VERSION 5.8 ;
BUSBITCHARS "[]" ;
DIVIDERCHAR "/" ;
UNITS
    DATABASE MICRONS 1000 ;
END UNITS

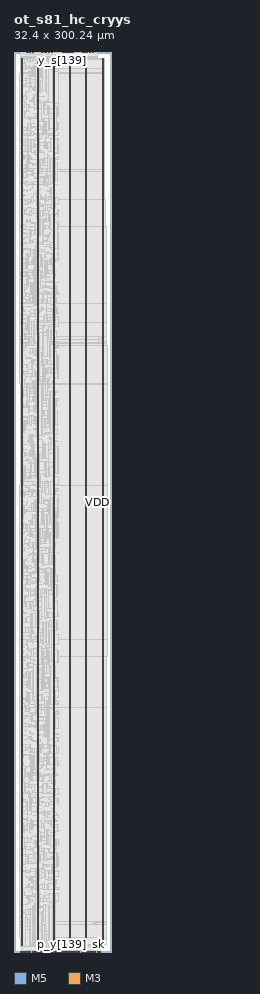
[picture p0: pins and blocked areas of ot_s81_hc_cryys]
MACRO ot_s81_hc_cryys
  FOREIGN ot_s81_hc_cryys 0 0 ;
  CLASS BLOCK ;
  SIZE 32.4 BY 300.24 ;
  PIN p_flt
    DIRECTION OUTPUT ;
    USE SIGNAL ;
    PORT
      LAYER M5 ;
        RECT  28.992 0 29.016 0.192 ;
    END
  END p_flt
  PIN p_req
    DIRECTION INPUT ;
    USE SIGNAL ;
    PORT
      LAYER M5 ;
        RECT  28.8 0 28.824 0.192 ;
    END
  END p_req
  PIN p_y[0]
    DIRECTION OUTPUT ;
    USE SIGNAL ;
    PORT
      LAYER M5 ;
        RECT  2.208 0 2.232 0.192 ;
    END
  END p_y[0]
  PIN p_y[100]
    DIRECTION OUTPUT ;
    USE SIGNAL ;
    PORT
      LAYER M5 ;
        RECT  12.24 0 12.264 0.192 ;
    END
  END p_y[100]
  PIN p_y[101]
    DIRECTION OUTPUT ;
    USE SIGNAL ;
    PORT
      LAYER M3 ;
        RECT  12.348 0 12.366 0.038 ;
    END
  END p_y[101]
  PIN p_y[102]
    DIRECTION OUTPUT ;
    USE SIGNAL ;
    PORT
      LAYER M5 ;
        RECT  12.432 0 12.456 0.192 ;
    END
  END p_y[102]
  PIN p_y[103]
    DIRECTION OUTPUT ;
    USE SIGNAL ;
    PORT
      LAYER M3 ;
        RECT  12.564 0 12.582 0.038 ;
    END
  END p_y[103]
  PIN p_y[104]
    DIRECTION OUTPUT ;
    USE SIGNAL ;
    PORT
      LAYER M5 ;
        RECT  12.672 0 12.696 0.192 ;
    END
  END p_y[104]
  PIN p_y[105]
    DIRECTION OUTPUT ;
    USE SIGNAL ;
    PORT
      LAYER M3 ;
        RECT  12.744 0 12.762 0.038 ;
    END
  END p_y[105]
  PIN p_y[106]
    DIRECTION OUTPUT ;
    USE SIGNAL ;
    PORT
      LAYER M5 ;
        RECT  12.864 0 12.888 0.192 ;
    END
  END p_y[106]
  PIN p_y[107]
    DIRECTION OUTPUT ;
    USE SIGNAL ;
    PORT
      LAYER M3 ;
        RECT  12.96 0 12.978 0.038 ;
    END
  END p_y[107]
  PIN p_y[108]
    DIRECTION OUTPUT ;
    USE SIGNAL ;
    PORT
      LAYER M5 ;
        RECT  13.056 0 13.08 0.192 ;
    END
  END p_y[108]
  PIN p_y[109]
    DIRECTION OUTPUT ;
    USE SIGNAL ;
    PORT
      LAYER M3 ;
        RECT  13.176 0 13.194 0.038 ;
    END
  END p_y[109]
  PIN p_y[10]
    DIRECTION OUTPUT ;
    USE SIGNAL ;
    PORT
      LAYER M5 ;
        RECT  3.216 0 3.24 0.192 ;
    END
  END p_y[10]
  PIN p_y[110]
    DIRECTION OUTPUT ;
    USE SIGNAL ;
    PORT
      LAYER M5 ;
        RECT  13.248 0 13.272 0.192 ;
    END
  END p_y[110]
  PIN p_y[111]
    DIRECTION OUTPUT ;
    USE SIGNAL ;
    PORT
      LAYER M3 ;
        RECT  13.356 0 13.374 0.038 ;
    END
  END p_y[111]
  PIN p_y[112]
    DIRECTION OUTPUT ;
    USE SIGNAL ;
    PORT
      LAYER M5 ;
        RECT  13.44 0 13.464 0.192 ;
    END
  END p_y[112]
  PIN p_y[113]
    DIRECTION OUTPUT ;
    USE SIGNAL ;
    PORT
      LAYER M3 ;
        RECT  13.572 0 13.59 0.038 ;
    END
  END p_y[113]
  PIN p_y[114]
    DIRECTION OUTPUT ;
    USE SIGNAL ;
    PORT
      LAYER M5 ;
        RECT  13.68 0 13.704 0.192 ;
    END
  END p_y[114]
  PIN p_y[115]
    DIRECTION OUTPUT ;
    USE SIGNAL ;
    PORT
      LAYER M3 ;
        RECT  13.752 0 13.77 0.038 ;
    END
  END p_y[115]
  PIN p_y[116]
    DIRECTION OUTPUT ;
    USE SIGNAL ;
    PORT
      LAYER M5 ;
        RECT  13.872 0 13.896 0.192 ;
    END
  END p_y[116]
  PIN p_y[117]
    DIRECTION OUTPUT ;
    USE SIGNAL ;
    PORT
      LAYER M3 ;
        RECT  13.968 0 13.986 0.038 ;
    END
  END p_y[117]
  PIN p_y[118]
    DIRECTION OUTPUT ;
    USE SIGNAL ;
    PORT
      LAYER M5 ;
        RECT  14.064 0 14.088 0.192 ;
    END
  END p_y[118]
  PIN p_y[119]
    DIRECTION OUTPUT ;
    USE SIGNAL ;
    PORT
      LAYER M3 ;
        RECT  14.184 0 14.202 0.038 ;
    END
  END p_y[119]
  PIN p_y[11]
    DIRECTION OUTPUT ;
    USE SIGNAL ;
    PORT
      LAYER M3 ;
        RECT  3.312 0 3.33 0.038 ;
    END
  END p_y[11]
  PIN p_y[120]
    DIRECTION OUTPUT ;
    USE SIGNAL ;
    PORT
      LAYER M5 ;
        RECT  14.256 0 14.28 0.192 ;
    END
  END p_y[120]
  PIN p_y[121]
    DIRECTION OUTPUT ;
    USE SIGNAL ;
    PORT
      LAYER M3 ;
        RECT  14.364 0 14.382 0.038 ;
    END
  END p_y[121]
  PIN p_y[122]
    DIRECTION OUTPUT ;
    USE SIGNAL ;
    PORT
      LAYER M5 ;
        RECT  14.448 0 14.472 0.192 ;
    END
  END p_y[122]
  PIN p_y[123]
    DIRECTION OUTPUT ;
    USE SIGNAL ;
    PORT
      LAYER M3 ;
        RECT  14.58 0 14.598 0.038 ;
    END
  END p_y[123]
  PIN p_y[124]
    DIRECTION OUTPUT ;
    USE SIGNAL ;
    PORT
      LAYER M5 ;
        RECT  14.688 0 14.712 0.192 ;
    END
  END p_y[124]
  PIN p_y[125]
    DIRECTION OUTPUT ;
    USE SIGNAL ;
    PORT
      LAYER M3 ;
        RECT  14.76 0 14.778 0.038 ;
    END
  END p_y[125]
  PIN p_y[126]
    DIRECTION OUTPUT ;
    USE SIGNAL ;
    PORT
      LAYER M5 ;
        RECT  14.88 0 14.904 0.192 ;
    END
  END p_y[126]
  PIN p_y[127]
    DIRECTION OUTPUT ;
    USE SIGNAL ;
    PORT
      LAYER M3 ;
        RECT  14.976 0 14.994 0.038 ;
    END
  END p_y[127]
  PIN p_y[128]
    DIRECTION OUTPUT ;
    USE SIGNAL ;
    PORT
      LAYER M5 ;
        RECT  15.072 0 15.096 0.192 ;
    END
  END p_y[128]
  PIN p_y[129]
    DIRECTION OUTPUT ;
    USE SIGNAL ;
    PORT
      LAYER M3 ;
        RECT  15.156 0 15.174 0.038 ;
    END
  END p_y[129]
  PIN p_y[12]
    DIRECTION OUTPUT ;
    USE SIGNAL ;
    PORT
      LAYER M5 ;
        RECT  3.408 0 3.432 0.192 ;
    END
  END p_y[12]
  PIN p_y[130]
    DIRECTION OUTPUT ;
    USE SIGNAL ;
    PORT
      LAYER M5 ;
        RECT  15.264 0 15.288 0.192 ;
    END
  END p_y[130]
  PIN p_y[131]
    DIRECTION OUTPUT ;
    USE SIGNAL ;
    PORT
      LAYER M3 ;
        RECT  15.372 0 15.39 0.038 ;
    END
  END p_y[131]
  PIN p_y[132]
    DIRECTION OUTPUT ;
    USE SIGNAL ;
    PORT
      LAYER M5 ;
        RECT  15.456 0 15.48 0.192 ;
    END
  END p_y[132]
  PIN p_y[133]
    DIRECTION OUTPUT ;
    USE SIGNAL ;
    PORT
      LAYER M3 ;
        RECT  15.588 0 15.606 0.038 ;
    END
  END p_y[133]
  PIN p_y[134]
    DIRECTION OUTPUT ;
    USE SIGNAL ;
    PORT
      LAYER M5 ;
        RECT  15.648 0 15.672 0.192 ;
    END
  END p_y[134]
  PIN p_y[135]
    DIRECTION OUTPUT ;
    USE SIGNAL ;
    PORT
      LAYER M3 ;
        RECT  15.768 0 15.786 0.038 ;
    END
  END p_y[135]
  PIN p_y[136]
    DIRECTION OUTPUT ;
    USE SIGNAL ;
    PORT
      LAYER M5 ;
        RECT  15.888 0 15.912 0.192 ;
    END
  END p_y[136]
  PIN p_y[137]
    DIRECTION OUTPUT ;
    USE SIGNAL ;
    PORT
      LAYER M3 ;
        RECT  15.984 0 16.002 0.038 ;
    END
  END p_y[137]
  PIN p_y[138]
    DIRECTION OUTPUT ;
    USE SIGNAL ;
    PORT
      LAYER M5 ;
        RECT  16.08 0 16.104 0.192 ;
    END
  END p_y[138]
  PIN p_y[139]
    DIRECTION OUTPUT ;
    USE SIGNAL ;
    PORT
      LAYER M3 ;
        RECT  16.164 0 16.182 0.038 ;
    END
  END p_y[139]
  PIN p_y[13]
    DIRECTION OUTPUT ;
    USE SIGNAL ;
    PORT
      LAYER M3 ;
        RECT  3.492 0 3.51 0.038 ;
    END
  END p_y[13]
  PIN p_y[140]
    DIRECTION OUTPUT ;
    USE SIGNAL ;
    PORT
      LAYER M5 ;
        RECT  16.272 0 16.296 0.192 ;
    END
  END p_y[140]
  PIN p_y[141]
    DIRECTION OUTPUT ;
    USE SIGNAL ;
    PORT
      LAYER M3 ;
        RECT  16.344 0 16.362 0.038 ;
    END
  END p_y[141]
  PIN p_y[142]
    DIRECTION OUTPUT ;
    USE SIGNAL ;
    PORT
      LAYER M5 ;
        RECT  16.368 0 16.392 0.192 ;
    END
  END p_y[142]
  PIN p_y[143]
    DIRECTION OUTPUT ;
    USE SIGNAL ;
    PORT
      LAYER M3 ;
        RECT  16.956 0 16.974 0.038 ;
    END
  END p_y[143]
  PIN p_y[144]
    DIRECTION OUTPUT ;
    USE SIGNAL ;
    PORT
      LAYER M5 ;
        RECT  16.944 0 16.968 0.192 ;
    END
  END p_y[144]
  PIN p_y[145]
    DIRECTION OUTPUT ;
    USE SIGNAL ;
    PORT
      LAYER M3 ;
        RECT  16.992 0 17.01 0.038 ;
    END
  END p_y[145]
  PIN p_y[146]
    DIRECTION OUTPUT ;
    USE SIGNAL ;
    PORT
      LAYER M5 ;
        RECT  16.992 0 17.016 0.192 ;
    END
  END p_y[146]
  PIN p_y[147]
    DIRECTION OUTPUT ;
    USE SIGNAL ;
    PORT
      LAYER M3 ;
        RECT  17.028 0 17.046 0.038 ;
    END
  END p_y[147]
  PIN p_y[148]
    DIRECTION OUTPUT ;
    USE SIGNAL ;
    PORT
      LAYER M5 ;
        RECT  17.088 0 17.112 0.192 ;
    END
  END p_y[148]
  PIN p_y[149]
    DIRECTION OUTPUT ;
    USE SIGNAL ;
    PORT
      LAYER M3 ;
        RECT  17.172 0 17.19 0.038 ;
    END
  END p_y[149]
  PIN p_y[14]
    DIRECTION OUTPUT ;
    USE SIGNAL ;
    PORT
      LAYER M5 ;
        RECT  3.6 0 3.624 0.192 ;
    END
  END p_y[14]
  PIN p_y[150]
    DIRECTION OUTPUT ;
    USE SIGNAL ;
    PORT
      LAYER M5 ;
        RECT  17.28 0 17.304 0.192 ;
    END
  END p_y[150]
  PIN p_y[151]
    DIRECTION OUTPUT ;
    USE SIGNAL ;
    PORT
      LAYER M3 ;
        RECT  17.388 0 17.406 0.038 ;
    END
  END p_y[151]
  PIN p_y[152]
    DIRECTION OUTPUT ;
    USE SIGNAL ;
    PORT
      LAYER M5 ;
        RECT  17.472 0 17.496 0.192 ;
    END
  END p_y[152]
  PIN p_y[153]
    DIRECTION OUTPUT ;
    USE SIGNAL ;
    PORT
      LAYER M3 ;
        RECT  17.568 0 17.586 0.038 ;
    END
  END p_y[153]
  PIN p_y[154]
    DIRECTION OUTPUT ;
    USE SIGNAL ;
    PORT
      LAYER M5 ;
        RECT  17.664 0 17.688 0.192 ;
    END
  END p_y[154]
  PIN p_y[155]
    DIRECTION OUTPUT ;
    USE SIGNAL ;
    PORT
      LAYER M3 ;
        RECT  17.784 0 17.802 0.038 ;
    END
  END p_y[155]
  PIN p_y[156]
    DIRECTION OUTPUT ;
    USE SIGNAL ;
    PORT
      LAYER M5 ;
        RECT  17.904 0 17.928 0.192 ;
    END
  END p_y[156]
  PIN p_y[157]
    DIRECTION OUTPUT ;
    USE SIGNAL ;
    PORT
      LAYER M3 ;
        RECT  18 0 18.018 0.038 ;
    END
  END p_y[157]
  PIN p_y[158]
    DIRECTION OUTPUT ;
    USE SIGNAL ;
    PORT
      LAYER M5 ;
        RECT  18.096 0 18.12 0.192 ;
    END
  END p_y[158]
  PIN p_y[159]
    DIRECTION OUTPUT ;
    USE SIGNAL ;
    PORT
      LAYER M3 ;
        RECT  18.18 0 18.198 0.038 ;
    END
  END p_y[159]
  PIN p_y[15]
    DIRECTION OUTPUT ;
    USE SIGNAL ;
    PORT
      LAYER M3 ;
        RECT  3.708 0 3.726 0.038 ;
    END
  END p_y[15]
  PIN p_y[160]
    DIRECTION OUTPUT ;
    USE SIGNAL ;
    PORT
      LAYER M5 ;
        RECT  18.288 0 18.312 0.192 ;
    END
  END p_y[160]
  PIN p_y[161]
    DIRECTION OUTPUT ;
    USE SIGNAL ;
    PORT
      LAYER M3 ;
        RECT  18.396 0 18.414 0.038 ;
    END
  END p_y[161]
  PIN p_y[162]
    DIRECTION OUTPUT ;
    USE SIGNAL ;
    PORT
      LAYER M5 ;
        RECT  18.48 0 18.504 0.192 ;
    END
  END p_y[162]
  PIN p_y[163]
    DIRECTION OUTPUT ;
    USE SIGNAL ;
    PORT
      LAYER M3 ;
        RECT  18.576 0 18.594 0.038 ;
    END
  END p_y[163]
  PIN p_y[164]
    DIRECTION OUTPUT ;
    USE SIGNAL ;
    PORT
      LAYER M5 ;
        RECT  18.672 0 18.696 0.192 ;
    END
  END p_y[164]
  PIN p_y[165]
    DIRECTION OUTPUT ;
    USE SIGNAL ;
    PORT
      LAYER M3 ;
        RECT  18.792 0 18.81 0.038 ;
    END
  END p_y[165]
  PIN p_y[166]
    DIRECTION OUTPUT ;
    USE SIGNAL ;
    PORT
      LAYER M5 ;
        RECT  18.912 0 18.936 0.192 ;
    END
  END p_y[166]
  PIN p_y[167]
    DIRECTION OUTPUT ;
    USE SIGNAL ;
    PORT
      LAYER M3 ;
        RECT  19.008 0 19.026 0.038 ;
    END
  END p_y[167]
  PIN p_y[168]
    DIRECTION OUTPUT ;
    USE SIGNAL ;
    PORT
      LAYER M5 ;
        RECT  19.104 0 19.128 0.192 ;
    END
  END p_y[168]
  PIN p_y[169]
    DIRECTION OUTPUT ;
    USE SIGNAL ;
    PORT
      LAYER M3 ;
        RECT  19.188 0 19.206 0.038 ;
    END
  END p_y[169]
  PIN p_y[16]
    DIRECTION OUTPUT ;
    USE SIGNAL ;
    PORT
      LAYER M5 ;
        RECT  3.792 0 3.816 0.192 ;
    END
  END p_y[16]
  PIN p_y[170]
    DIRECTION OUTPUT ;
    USE SIGNAL ;
    PORT
      LAYER M5 ;
        RECT  19.296 0 19.32 0.192 ;
    END
  END p_y[170]
  PIN p_y[171]
    DIRECTION OUTPUT ;
    USE SIGNAL ;
    PORT
      LAYER M3 ;
        RECT  19.404 0 19.422 0.038 ;
    END
  END p_y[171]
  PIN p_y[172]
    DIRECTION OUTPUT ;
    USE SIGNAL ;
    PORT
      LAYER M5 ;
        RECT  19.488 0 19.512 0.192 ;
    END
  END p_y[172]
  PIN p_y[173]
    DIRECTION OUTPUT ;
    USE SIGNAL ;
    PORT
      LAYER M3 ;
        RECT  19.584 0 19.602 0.038 ;
    END
  END p_y[173]
  PIN p_y[174]
    DIRECTION OUTPUT ;
    USE SIGNAL ;
    PORT
      LAYER M5 ;
        RECT  19.68 0 19.704 0.192 ;
    END
  END p_y[174]
  PIN p_y[175]
    DIRECTION OUTPUT ;
    USE SIGNAL ;
    PORT
      LAYER M3 ;
        RECT  19.8 0 19.818 0.038 ;
    END
  END p_y[175]
  PIN p_y[176]
    DIRECTION OUTPUT ;
    USE SIGNAL ;
    PORT
      LAYER M5 ;
        RECT  19.872 0 19.896 0.192 ;
    END
  END p_y[176]
  PIN p_y[177]
    DIRECTION OUTPUT ;
    USE SIGNAL ;
    PORT
      LAYER M3 ;
        RECT  20.016 0 20.034 0.038 ;
    END
  END p_y[177]
  PIN p_y[178]
    DIRECTION OUTPUT ;
    USE SIGNAL ;
    PORT
      LAYER M5 ;
        RECT  20.112 0 20.136 0.192 ;
    END
  END p_y[178]
  PIN p_y[179]
    DIRECTION OUTPUT ;
    USE SIGNAL ;
    PORT
      LAYER M3 ;
        RECT  20.196 0 20.214 0.038 ;
    END
  END p_y[179]
  PIN p_y[17]
    DIRECTION OUTPUT ;
    USE SIGNAL ;
    PORT
      LAYER M3 ;
        RECT  3.924 0 3.942 0.038 ;
    END
  END p_y[17]
  PIN p_y[180]
    DIRECTION OUTPUT ;
    USE SIGNAL ;
    PORT
      LAYER M5 ;
        RECT  20.304 0 20.328 0.192 ;
    END
  END p_y[180]
  PIN p_y[181]
    DIRECTION OUTPUT ;
    USE SIGNAL ;
    PORT
      LAYER M3 ;
        RECT  20.412 0 20.43 0.038 ;
    END
  END p_y[181]
  PIN p_y[182]
    DIRECTION OUTPUT ;
    USE SIGNAL ;
    PORT
      LAYER M5 ;
        RECT  20.496 0 20.52 0.192 ;
    END
  END p_y[182]
  PIN p_y[183]
    DIRECTION OUTPUT ;
    USE SIGNAL ;
    PORT
      LAYER M3 ;
        RECT  20.592 0 20.61 0.038 ;
    END
  END p_y[183]
  PIN p_y[184]
    DIRECTION OUTPUT ;
    USE SIGNAL ;
    PORT
      LAYER M5 ;
        RECT  20.688 0 20.712 0.192 ;
    END
  END p_y[184]
  PIN p_y[185]
    DIRECTION OUTPUT ;
    USE SIGNAL ;
    PORT
      LAYER M3 ;
        RECT  20.808 0 20.826 0.038 ;
    END
  END p_y[185]
  PIN p_y[186]
    DIRECTION OUTPUT ;
    USE SIGNAL ;
    PORT
      LAYER M5 ;
        RECT  20.88 0 20.904 0.192 ;
    END
  END p_y[186]
  PIN p_y[187]
    DIRECTION OUTPUT ;
    USE SIGNAL ;
    PORT
      LAYER M3 ;
        RECT  20.988 0 21.006 0.038 ;
    END
  END p_y[187]
  PIN p_y[188]
    DIRECTION OUTPUT ;
    USE SIGNAL ;
    PORT
      LAYER M5 ;
        RECT  21.12 0 21.144 0.192 ;
    END
  END p_y[188]
  PIN p_y[189]
    DIRECTION OUTPUT ;
    USE SIGNAL ;
    PORT
      LAYER M3 ;
        RECT  21.204 0 21.222 0.038 ;
    END
  END p_y[189]
  PIN p_y[18]
    DIRECTION OUTPUT ;
    USE SIGNAL ;
    PORT
      LAYER M5 ;
        RECT  4.032 0 4.056 0.192 ;
    END
  END p_y[18]
  PIN p_y[190]
    DIRECTION OUTPUT ;
    USE SIGNAL ;
    PORT
      LAYER M5 ;
        RECT  21.312 0 21.336 0.192 ;
    END
  END p_y[190]
  PIN p_y[191]
    DIRECTION OUTPUT ;
    USE SIGNAL ;
    PORT
      LAYER M3 ;
        RECT  21.42 0 21.438 0.038 ;
    END
  END p_y[191]
  PIN p_y[192]
    DIRECTION OUTPUT ;
    USE SIGNAL ;
    PORT
      LAYER M5 ;
        RECT  21.504 0 21.528 0.192 ;
    END
  END p_y[192]
  PIN p_y[193]
    DIRECTION OUTPUT ;
    USE SIGNAL ;
    PORT
      LAYER M3 ;
        RECT  21.6 0 21.618 0.038 ;
    END
  END p_y[193]
  PIN p_y[194]
    DIRECTION OUTPUT ;
    USE SIGNAL ;
    PORT
      LAYER M5 ;
        RECT  21.696 0 21.72 0.192 ;
    END
  END p_y[194]
  PIN p_y[195]
    DIRECTION OUTPUT ;
    USE SIGNAL ;
    PORT
      LAYER M3 ;
        RECT  21.744 0 21.762 0.038 ;
    END
  END p_y[195]
  PIN p_y[196]
    DIRECTION OUTPUT ;
    USE SIGNAL ;
    PORT
      LAYER M5 ;
        RECT  21.744 0 21.768 0.192 ;
    END
  END p_y[196]
  PIN p_y[197]
    DIRECTION OUTPUT ;
    USE SIGNAL ;
    PORT
      LAYER M3 ;
        RECT  22.356 0 22.374 0.038 ;
    END
  END p_y[197]
  PIN p_y[198]
    DIRECTION OUTPUT ;
    USE SIGNAL ;
    PORT
      LAYER M5 ;
        RECT  22.368 0 22.392 0.192 ;
    END
  END p_y[198]
  PIN p_y[199]
    DIRECTION OUTPUT ;
    USE SIGNAL ;
    PORT
      LAYER M3 ;
        RECT  22.392 0 22.41 0.038 ;
    END
  END p_y[199]
  PIN p_y[19]
    DIRECTION OUTPUT ;
    USE SIGNAL ;
    PORT
      LAYER M3 ;
        RECT  4.104 0 4.122 0.038 ;
    END
  END p_y[19]
  PIN p_y[1]
    DIRECTION OUTPUT ;
    USE SIGNAL ;
    PORT
      LAYER M3 ;
        RECT  2.304 0 2.322 0.038 ;
    END
  END p_y[1]
  PIN p_y[200]
    DIRECTION OUTPUT ;
    USE SIGNAL ;
    PORT
      LAYER M5 ;
        RECT  22.416 0 22.44 0.192 ;
    END
  END p_y[200]
  PIN p_y[201]
    DIRECTION OUTPUT ;
    USE SIGNAL ;
    PORT
      LAYER M3 ;
        RECT  22.428 0 22.446 0.038 ;
    END
  END p_y[201]
  PIN p_y[202]
    DIRECTION OUTPUT ;
    USE SIGNAL ;
    PORT
      LAYER M5 ;
        RECT  22.512 0 22.536 0.192 ;
    END
  END p_y[202]
  PIN p_y[203]
    DIRECTION OUTPUT ;
    USE SIGNAL ;
    PORT
      LAYER M3 ;
        RECT  22.608 0 22.626 0.038 ;
    END
  END p_y[203]
  PIN p_y[204]
    DIRECTION OUTPUT ;
    USE SIGNAL ;
    PORT
      LAYER M5 ;
        RECT  22.704 0 22.728 0.192 ;
    END
  END p_y[204]
  PIN p_y[205]
    DIRECTION OUTPUT ;
    USE SIGNAL ;
    PORT
      LAYER M3 ;
        RECT  22.824 0 22.842 0.038 ;
    END
  END p_y[205]
  PIN p_y[206]
    DIRECTION OUTPUT ;
    USE SIGNAL ;
    PORT
      LAYER M5 ;
        RECT  22.896 0 22.92 0.192 ;
    END
  END p_y[206]
  PIN p_y[207]
    DIRECTION OUTPUT ;
    USE SIGNAL ;
    PORT
      LAYER M3 ;
        RECT  23.004 0 23.022 0.038 ;
    END
  END p_y[207]
  PIN p_y[208]
    DIRECTION OUTPUT ;
    USE SIGNAL ;
    PORT
      LAYER M5 ;
        RECT  23.136 0 23.16 0.192 ;
    END
  END p_y[208]
  PIN p_y[209]
    DIRECTION OUTPUT ;
    USE SIGNAL ;
    PORT
      LAYER M3 ;
        RECT  23.22 0 23.238 0.038 ;
    END
  END p_y[209]
  PIN p_y[20]
    DIRECTION OUTPUT ;
    USE SIGNAL ;
    PORT
      LAYER M5 ;
        RECT  4.224 0 4.248 0.192 ;
    END
  END p_y[20]
  PIN p_y[210]
    DIRECTION OUTPUT ;
    USE SIGNAL ;
    PORT
      LAYER M5 ;
        RECT  23.328 0 23.352 0.192 ;
    END
  END p_y[210]
  PIN p_y[211]
    DIRECTION OUTPUT ;
    USE SIGNAL ;
    PORT
      LAYER M3 ;
        RECT  23.4 0 23.418 0.038 ;
    END
  END p_y[211]
  PIN p_y[212]
    DIRECTION OUTPUT ;
    USE SIGNAL ;
    PORT
      LAYER M5 ;
        RECT  23.52 0 23.544 0.192 ;
    END
  END p_y[212]
  PIN p_y[213]
    DIRECTION OUTPUT ;
    USE SIGNAL ;
    PORT
      LAYER M3 ;
        RECT  23.616 0 23.634 0.038 ;
    END
  END p_y[213]
  PIN p_y[214]
    DIRECTION OUTPUT ;
    USE SIGNAL ;
    PORT
      LAYER M5 ;
        RECT  23.712 0 23.736 0.192 ;
    END
  END p_y[214]
  PIN p_y[215]
    DIRECTION OUTPUT ;
    USE SIGNAL ;
    PORT
      LAYER M3 ;
        RECT  23.832 0 23.85 0.038 ;
    END
  END p_y[215]
  PIN p_y[216]
    DIRECTION OUTPUT ;
    USE SIGNAL ;
    PORT
      LAYER M5 ;
        RECT  23.904 0 23.928 0.192 ;
    END
  END p_y[216]
  PIN p_y[217]
    DIRECTION OUTPUT ;
    USE SIGNAL ;
    PORT
      LAYER M3 ;
        RECT  24.012 0 24.03 0.038 ;
    END
  END p_y[217]
  PIN p_y[218]
    DIRECTION OUTPUT ;
    USE SIGNAL ;
    PORT
      LAYER M5 ;
        RECT  24.096 0 24.12 0.192 ;
    END
  END p_y[218]
  PIN p_y[219]
    DIRECTION OUTPUT ;
    USE SIGNAL ;
    PORT
      LAYER M3 ;
        RECT  24.228 0 24.246 0.038 ;
    END
  END p_y[219]
  PIN p_y[21]
    DIRECTION OUTPUT ;
    USE SIGNAL ;
    PORT
      LAYER M3 ;
        RECT  4.32 0 4.338 0.038 ;
    END
  END p_y[21]
  PIN p_y[220]
    DIRECTION OUTPUT ;
    USE SIGNAL ;
    PORT
      LAYER M5 ;
        RECT  24.336 0 24.36 0.192 ;
    END
  END p_y[220]
  PIN p_y[221]
    DIRECTION OUTPUT ;
    USE SIGNAL ;
    PORT
      LAYER M3 ;
        RECT  24.408 0 24.426 0.038 ;
    END
  END p_y[221]
  PIN p_y[222]
    DIRECTION OUTPUT ;
    USE SIGNAL ;
    PORT
      LAYER M5 ;
        RECT  24.528 0 24.552 0.192 ;
    END
  END p_y[222]
  PIN p_y[223]
    DIRECTION OUTPUT ;
    USE SIGNAL ;
    PORT
      LAYER M3 ;
        RECT  24.624 0 24.642 0.038 ;
    END
  END p_y[223]
  PIN p_y[224]
    DIRECTION OUTPUT ;
    USE SIGNAL ;
    PORT
      LAYER M5 ;
        RECT  24.72 0 24.744 0.192 ;
    END
  END p_y[224]
  PIN p_y[225]
    DIRECTION OUTPUT ;
    USE SIGNAL ;
    PORT
      LAYER M3 ;
        RECT  24.84 0 24.858 0.038 ;
    END
  END p_y[225]
  PIN p_y[226]
    DIRECTION OUTPUT ;
    USE SIGNAL ;
    PORT
      LAYER M5 ;
        RECT  24.912 0 24.936 0.192 ;
    END
  END p_y[226]
  PIN p_y[227]
    DIRECTION OUTPUT ;
    USE SIGNAL ;
    PORT
      LAYER M3 ;
        RECT  25.02 0 25.038 0.038 ;
    END
  END p_y[227]
  PIN p_y[228]
    DIRECTION OUTPUT ;
    USE SIGNAL ;
    PORT
      LAYER M5 ;
        RECT  25.104 0 25.128 0.192 ;
    END
  END p_y[228]
  PIN p_y[229]
    DIRECTION OUTPUT ;
    USE SIGNAL ;
    PORT
      LAYER M3 ;
        RECT  25.236 0 25.254 0.038 ;
    END
  END p_y[229]
  PIN p_y[22]
    DIRECTION OUTPUT ;
    USE SIGNAL ;
    PORT
      LAYER M5 ;
        RECT  4.416 0 4.44 0.192 ;
    END
  END p_y[22]
  PIN p_y[230]
    DIRECTION OUTPUT ;
    USE SIGNAL ;
    PORT
      LAYER M5 ;
        RECT  25.344 0 25.368 0.192 ;
    END
  END p_y[230]
  PIN p_y[231]
    DIRECTION OUTPUT ;
    USE SIGNAL ;
    PORT
      LAYER M3 ;
        RECT  25.416 0 25.434 0.038 ;
    END
  END p_y[231]
  PIN p_y[232]
    DIRECTION OUTPUT ;
    USE SIGNAL ;
    PORT
      LAYER M5 ;
        RECT  25.536 0 25.56 0.192 ;
    END
  END p_y[232]
  PIN p_y[233]
    DIRECTION OUTPUT ;
    USE SIGNAL ;
    PORT
      LAYER M3 ;
        RECT  25.632 0 25.65 0.038 ;
    END
  END p_y[233]
  PIN p_y[234]
    DIRECTION OUTPUT ;
    USE SIGNAL ;
    PORT
      LAYER M5 ;
        RECT  25.728 0 25.752 0.192 ;
    END
  END p_y[234]
  PIN p_y[235]
    DIRECTION OUTPUT ;
    USE SIGNAL ;
    PORT
      LAYER M3 ;
        RECT  25.812 0 25.83 0.038 ;
    END
  END p_y[235]
  PIN p_y[236]
    DIRECTION OUTPUT ;
    USE SIGNAL ;
    PORT
      LAYER M5 ;
        RECT  25.92 0 25.944 0.192 ;
    END
  END p_y[236]
  PIN p_y[237]
    DIRECTION OUTPUT ;
    USE SIGNAL ;
    PORT
      LAYER M3 ;
        RECT  26.028 0 26.046 0.038 ;
    END
  END p_y[237]
  PIN p_y[238]
    DIRECTION OUTPUT ;
    USE SIGNAL ;
    PORT
      LAYER M5 ;
        RECT  26.112 0 26.136 0.192 ;
    END
  END p_y[238]
  PIN p_y[239]
    DIRECTION OUTPUT ;
    USE SIGNAL ;
    PORT
      LAYER M3 ;
        RECT  26.244 0 26.262 0.038 ;
    END
  END p_y[239]
  PIN p_y[23]
    DIRECTION OUTPUT ;
    USE SIGNAL ;
    PORT
      LAYER M3 ;
        RECT  4.5 0 4.518 0.038 ;
    END
  END p_y[23]
  PIN p_y[240]
    DIRECTION OUTPUT ;
    USE SIGNAL ;
    PORT
      LAYER M5 ;
        RECT  26.352 0 26.376 0.192 ;
    END
  END p_y[240]
  PIN p_y[241]
    DIRECTION OUTPUT ;
    USE SIGNAL ;
    PORT
      LAYER M3 ;
        RECT  26.424 0 26.442 0.038 ;
    END
  END p_y[241]
  PIN p_y[242]
    DIRECTION OUTPUT ;
    USE SIGNAL ;
    PORT
      LAYER M5 ;
        RECT  26.544 0 26.568 0.192 ;
    END
  END p_y[242]
  PIN p_y[243]
    DIRECTION OUTPUT ;
    USE SIGNAL ;
    PORT
      LAYER M3 ;
        RECT  26.64 0 26.658 0.038 ;
    END
  END p_y[243]
  PIN p_y[244]
    DIRECTION OUTPUT ;
    USE SIGNAL ;
    PORT
      LAYER M5 ;
        RECT  26.736 0 26.76 0.192 ;
    END
  END p_y[244]
  PIN p_y[245]
    DIRECTION OUTPUT ;
    USE SIGNAL ;
    PORT
      LAYER M3 ;
        RECT  26.82 0 26.838 0.038 ;
    END
  END p_y[245]
  PIN p_y[246]
    DIRECTION OUTPUT ;
    USE SIGNAL ;
    PORT
      LAYER M5 ;
        RECT  26.928 0 26.952 0.192 ;
    END
  END p_y[246]
  PIN p_y[247]
    DIRECTION OUTPUT ;
    USE SIGNAL ;
    PORT
      LAYER M3 ;
        RECT  27.036 0 27.054 0.038 ;
    END
  END p_y[247]
  PIN p_y[248]
    DIRECTION OUTPUT ;
    USE SIGNAL ;
    PORT
      LAYER M5 ;
        RECT  27.12 0 27.144 0.192 ;
    END
  END p_y[248]
  PIN p_y[249]
    DIRECTION OUTPUT ;
    USE SIGNAL ;
    PORT
      LAYER M3 ;
        RECT  27.144 0 27.162 0.038 ;
    END
  END p_y[249]
  PIN p_y[24]
    DIRECTION OUTPUT ;
    USE SIGNAL ;
    PORT
      LAYER M5 ;
        RECT  4.608 0 4.632 0.192 ;
    END
  END p_y[24]
  PIN p_y[250]
    DIRECTION OUTPUT ;
    USE SIGNAL ;
    PORT
      LAYER M5 ;
        RECT  27.168 0 27.192 0.192 ;
    END
  END p_y[250]
  PIN p_y[251]
    DIRECTION OUTPUT ;
    USE SIGNAL ;
    PORT
      LAYER M3 ;
        RECT  27.756 0 27.774 0.038 ;
    END
  END p_y[251]
  PIN p_y[252]
    DIRECTION OUTPUT ;
    USE SIGNAL ;
    PORT
      LAYER M5 ;
        RECT  27.744 0 27.768 0.192 ;
    END
  END p_y[252]
  PIN p_y[253]
    DIRECTION OUTPUT ;
    USE SIGNAL ;
    PORT
      LAYER M3 ;
        RECT  27.792 0 27.81 0.038 ;
    END
  END p_y[253]
  PIN p_y[254]
    DIRECTION OUTPUT ;
    USE SIGNAL ;
    PORT
      LAYER M5 ;
        RECT  27.792 0 27.816 0.192 ;
    END
  END p_y[254]
  PIN p_y[255]
    DIRECTION OUTPUT ;
    USE SIGNAL ;
    PORT
      LAYER M3 ;
        RECT  27.828 0 27.846 0.038 ;
    END
  END p_y[255]
  PIN p_y[25]
    DIRECTION OUTPUT ;
    USE SIGNAL ;
    PORT
      LAYER M3 ;
        RECT  4.716 0 4.734 0.038 ;
    END
  END p_y[25]
  PIN p_y[26]
    DIRECTION OUTPUT ;
    USE SIGNAL ;
    PORT
      LAYER M5 ;
        RECT  4.8 0 4.824 0.192 ;
    END
  END p_y[26]
  PIN p_y[27]
    DIRECTION OUTPUT ;
    USE SIGNAL ;
    PORT
      LAYER M3 ;
        RECT  4.932 0 4.95 0.038 ;
    END
  END p_y[27]
  PIN p_y[28]
    DIRECTION OUTPUT ;
    USE SIGNAL ;
    PORT
      LAYER M5 ;
        RECT  4.992 0 5.016 0.192 ;
    END
  END p_y[28]
  PIN p_y[29]
    DIRECTION OUTPUT ;
    USE SIGNAL ;
    PORT
      LAYER M3 ;
        RECT  5.112 0 5.13 0.038 ;
    END
  END p_y[29]
  PIN p_y[2]
    DIRECTION OUTPUT ;
    USE SIGNAL ;
    PORT
      LAYER M5 ;
        RECT  2.4 0 2.424 0.192 ;
    END
  END p_y[2]
  PIN p_y[30]
    DIRECTION OUTPUT ;
    USE SIGNAL ;
    PORT
      LAYER M5 ;
        RECT  5.232 0 5.256 0.192 ;
    END
  END p_y[30]
  PIN p_y[31]
    DIRECTION OUTPUT ;
    USE SIGNAL ;
    PORT
      LAYER M3 ;
        RECT  5.328 0 5.346 0.038 ;
    END
  END p_y[31]
  PIN p_y[32]
    DIRECTION OUTPUT ;
    USE SIGNAL ;
    PORT
      LAYER M5 ;
        RECT  5.424 0 5.448 0.192 ;
    END
  END p_y[32]
  PIN p_y[33]
    DIRECTION OUTPUT ;
    USE SIGNAL ;
    PORT
      LAYER M3 ;
        RECT  5.508 0 5.526 0.038 ;
    END
  END p_y[33]
  PIN p_y[34]
    DIRECTION OUTPUT ;
    USE SIGNAL ;
    PORT
      LAYER M5 ;
        RECT  5.568 0 5.592 0.192 ;
    END
  END p_y[34]
  PIN p_y[35]
    DIRECTION OUTPUT ;
    USE SIGNAL ;
    PORT
      LAYER M3 ;
        RECT  5.544 0 5.562 0.038 ;
    END
  END p_y[35]
  PIN p_y[36]
    DIRECTION OUTPUT ;
    USE SIGNAL ;
    PORT
      LAYER M5 ;
        RECT  6.144 0 6.168 0.192 ;
    END
  END p_y[36]
  PIN p_y[37]
    DIRECTION OUTPUT ;
    USE SIGNAL ;
    PORT
      LAYER M3 ;
        RECT  6.156 0 6.174 0.038 ;
    END
  END p_y[37]
  PIN p_y[38]
    DIRECTION OUTPUT ;
    USE SIGNAL ;
    PORT
      LAYER M5 ;
        RECT  6.192 0 6.216 0.192 ;
    END
  END p_y[38]
  PIN p_y[39]
    DIRECTION OUTPUT ;
    USE SIGNAL ;
    PORT
      LAYER M3 ;
        RECT  6.192 0 6.21 0.038 ;
    END
  END p_y[39]
  PIN p_y[3]
    DIRECTION OUTPUT ;
    USE SIGNAL ;
    PORT
      LAYER M3 ;
        RECT  2.52 0 2.538 0.038 ;
    END
  END p_y[3]
  PIN p_y[40]
    DIRECTION OUTPUT ;
    USE SIGNAL ;
    PORT
      LAYER M5 ;
        RECT  6.24 0 6.264 0.192 ;
    END
  END p_y[40]
  PIN p_y[41]
    DIRECTION OUTPUT ;
    USE SIGNAL ;
    PORT
      LAYER M3 ;
        RECT  6.336 0 6.354 0.038 ;
    END
  END p_y[41]
  PIN p_y[42]
    DIRECTION OUTPUT ;
    USE SIGNAL ;
    PORT
      LAYER M5 ;
        RECT  6.432 0 6.456 0.192 ;
    END
  END p_y[42]
  PIN p_y[43]
    DIRECTION OUTPUT ;
    USE SIGNAL ;
    PORT
      LAYER M3 ;
        RECT  6.516 0 6.534 0.038 ;
    END
  END p_y[43]
  PIN p_y[44]
    DIRECTION OUTPUT ;
    USE SIGNAL ;
    PORT
      LAYER M5 ;
        RECT  6.624 0 6.648 0.192 ;
    END
  END p_y[44]
  PIN p_y[45]
    DIRECTION OUTPUT ;
    USE SIGNAL ;
    PORT
      LAYER M3 ;
        RECT  6.732 0 6.75 0.038 ;
    END
  END p_y[45]
  PIN p_y[46]
    DIRECTION OUTPUT ;
    USE SIGNAL ;
    PORT
      LAYER M5 ;
        RECT  6.816 0 6.84 0.192 ;
    END
  END p_y[46]
  PIN p_y[47]
    DIRECTION OUTPUT ;
    USE SIGNAL ;
    PORT
      LAYER M3 ;
        RECT  6.912 0 6.93 0.038 ;
    END
  END p_y[47]
  PIN p_y[48]
    DIRECTION OUTPUT ;
    USE SIGNAL ;
    PORT
      LAYER M5 ;
        RECT  7.008 0 7.032 0.192 ;
    END
  END p_y[48]
  PIN p_y[49]
    DIRECTION OUTPUT ;
    USE SIGNAL ;
    PORT
      LAYER M3 ;
        RECT  7.128 0 7.146 0.038 ;
    END
  END p_y[49]
  PIN p_y[4]
    DIRECTION OUTPUT ;
    USE SIGNAL ;
    PORT
      LAYER M5 ;
        RECT  2.592 0 2.616 0.192 ;
    END
  END p_y[4]
  PIN p_y[50]
    DIRECTION OUTPUT ;
    USE SIGNAL ;
    PORT
      LAYER M5 ;
        RECT  7.248 0 7.272 0.192 ;
    END
  END p_y[50]
  PIN p_y[51]
    DIRECTION OUTPUT ;
    USE SIGNAL ;
    PORT
      LAYER M3 ;
        RECT  7.344 0 7.362 0.038 ;
    END
  END p_y[51]
  PIN p_y[52]
    DIRECTION OUTPUT ;
    USE SIGNAL ;
    PORT
      LAYER M5 ;
        RECT  7.44 0 7.464 0.192 ;
    END
  END p_y[52]
  PIN p_y[53]
    DIRECTION OUTPUT ;
    USE SIGNAL ;
    PORT
      LAYER M3 ;
        RECT  7.524 0 7.542 0.038 ;
    END
  END p_y[53]
  PIN p_y[54]
    DIRECTION OUTPUT ;
    USE SIGNAL ;
    PORT
      LAYER M5 ;
        RECT  7.632 0 7.656 0.192 ;
    END
  END p_y[54]
  PIN p_y[55]
    DIRECTION OUTPUT ;
    USE SIGNAL ;
    PORT
      LAYER M3 ;
        RECT  7.74 0 7.758 0.038 ;
    END
  END p_y[55]
  PIN p_y[56]
    DIRECTION OUTPUT ;
    USE SIGNAL ;
    PORT
      LAYER M5 ;
        RECT  7.824 0 7.848 0.192 ;
    END
  END p_y[56]
  PIN p_y[57]
    DIRECTION OUTPUT ;
    USE SIGNAL ;
    PORT
      LAYER M3 ;
        RECT  7.92 0 7.938 0.038 ;
    END
  END p_y[57]
  PIN p_y[58]
    DIRECTION OUTPUT ;
    USE SIGNAL ;
    PORT
      LAYER M5 ;
        RECT  8.016 0 8.04 0.192 ;
    END
  END p_y[58]
  PIN p_y[59]
    DIRECTION OUTPUT ;
    USE SIGNAL ;
    PORT
      LAYER M3 ;
        RECT  8.136 0 8.154 0.038 ;
    END
  END p_y[59]
  PIN p_y[5]
    DIRECTION OUTPUT ;
    USE SIGNAL ;
    PORT
      LAYER M3 ;
        RECT  2.7 0 2.718 0.038 ;
    END
  END p_y[5]
  PIN p_y[60]
    DIRECTION OUTPUT ;
    USE SIGNAL ;
    PORT
      LAYER M5 ;
        RECT  8.208 0 8.232 0.192 ;
    END
  END p_y[60]
  PIN p_y[61]
    DIRECTION OUTPUT ;
    USE SIGNAL ;
    PORT
      LAYER M3 ;
        RECT  8.352 0 8.37 0.038 ;
    END
  END p_y[61]
  PIN p_y[62]
    DIRECTION OUTPUT ;
    USE SIGNAL ;
    PORT
      LAYER M5 ;
        RECT  8.448 0 8.472 0.192 ;
    END
  END p_y[62]
  PIN p_y[63]
    DIRECTION OUTPUT ;
    USE SIGNAL ;
    PORT
      LAYER M3 ;
        RECT  8.532 0 8.55 0.038 ;
    END
  END p_y[63]
  PIN p_y[64]
    DIRECTION OUTPUT ;
    USE SIGNAL ;
    PORT
      LAYER M5 ;
        RECT  8.64 0 8.664 0.192 ;
    END
  END p_y[64]
  PIN p_y[65]
    DIRECTION OUTPUT ;
    USE SIGNAL ;
    PORT
      LAYER M3 ;
        RECT  8.748 0 8.766 0.038 ;
    END
  END p_y[65]
  PIN p_y[66]
    DIRECTION OUTPUT ;
    USE SIGNAL ;
    PORT
      LAYER M5 ;
        RECT  8.832 0 8.856 0.192 ;
    END
  END p_y[66]
  PIN p_y[67]
    DIRECTION OUTPUT ;
    USE SIGNAL ;
    PORT
      LAYER M3 ;
        RECT  8.928 0 8.946 0.038 ;
    END
  END p_y[67]
  PIN p_y[68]
    DIRECTION OUTPUT ;
    USE SIGNAL ;
    PORT
      LAYER M5 ;
        RECT  9.024 0 9.048 0.192 ;
    END
  END p_y[68]
  PIN p_y[69]
    DIRECTION OUTPUT ;
    USE SIGNAL ;
    PORT
      LAYER M3 ;
        RECT  9.144 0 9.162 0.038 ;
    END
  END p_y[69]
  PIN p_y[6]
    DIRECTION OUTPUT ;
    USE SIGNAL ;
    PORT
      LAYER M5 ;
        RECT  2.784 0 2.808 0.192 ;
    END
  END p_y[6]
  PIN p_y[70]
    DIRECTION OUTPUT ;
    USE SIGNAL ;
    PORT
      LAYER M5 ;
        RECT  9.216 0 9.24 0.192 ;
    END
  END p_y[70]
  PIN p_y[71]
    DIRECTION OUTPUT ;
    USE SIGNAL ;
    PORT
      LAYER M3 ;
        RECT  9.324 0 9.342 0.038 ;
    END
  END p_y[71]
  PIN p_y[72]
    DIRECTION OUTPUT ;
    USE SIGNAL ;
    PORT
      LAYER M5 ;
        RECT  9.456 0 9.48 0.192 ;
    END
  END p_y[72]
  PIN p_y[73]
    DIRECTION OUTPUT ;
    USE SIGNAL ;
    PORT
      LAYER M3 ;
        RECT  9.54 0 9.558 0.038 ;
    END
  END p_y[73]
  PIN p_y[74]
    DIRECTION OUTPUT ;
    USE SIGNAL ;
    PORT
      LAYER M5 ;
        RECT  9.648 0 9.672 0.192 ;
    END
  END p_y[74]
  PIN p_y[75]
    DIRECTION OUTPUT ;
    USE SIGNAL ;
    PORT
      LAYER M3 ;
        RECT  9.756 0 9.774 0.038 ;
    END
  END p_y[75]
  PIN p_y[76]
    DIRECTION OUTPUT ;
    USE SIGNAL ;
    PORT
      LAYER M5 ;
        RECT  9.84 0 9.864 0.192 ;
    END
  END p_y[76]
  PIN p_y[77]
    DIRECTION OUTPUT ;
    USE SIGNAL ;
    PORT
      LAYER M3 ;
        RECT  9.936 0 9.954 0.038 ;
    END
  END p_y[77]
  PIN p_y[78]
    DIRECTION OUTPUT ;
    USE SIGNAL ;
    PORT
      LAYER M5 ;
        RECT  10.032 0 10.056 0.192 ;
    END
  END p_y[78]
  PIN p_y[79]
    DIRECTION OUTPUT ;
    USE SIGNAL ;
    PORT
      LAYER M3 ;
        RECT  10.152 0 10.17 0.038 ;
    END
  END p_y[79]
  PIN p_y[7]
    DIRECTION OUTPUT ;
    USE SIGNAL ;
    PORT
      LAYER M3 ;
        RECT  2.916 0 2.934 0.038 ;
    END
  END p_y[7]
  PIN p_y[80]
    DIRECTION OUTPUT ;
    USE SIGNAL ;
    PORT
      LAYER M5 ;
        RECT  10.224 0 10.248 0.192 ;
    END
  END p_y[80]
  PIN p_y[81]
    DIRECTION OUTPUT ;
    USE SIGNAL ;
    PORT
      LAYER M3 ;
        RECT  10.332 0 10.35 0.038 ;
    END
  END p_y[81]
  PIN p_y[82]
    DIRECTION OUTPUT ;
    USE SIGNAL ;
    PORT
      LAYER M5 ;
        RECT  10.464 0 10.488 0.192 ;
    END
  END p_y[82]
  PIN p_y[83]
    DIRECTION OUTPUT ;
    USE SIGNAL ;
    PORT
      LAYER M3 ;
        RECT  10.548 0 10.566 0.038 ;
    END
  END p_y[83]
  PIN p_y[84]
    DIRECTION OUTPUT ;
    USE SIGNAL ;
    PORT
      LAYER M5 ;
        RECT  10.656 0 10.68 0.192 ;
    END
  END p_y[84]
  PIN p_y[85]
    DIRECTION OUTPUT ;
    USE SIGNAL ;
    PORT
      LAYER M3 ;
        RECT  10.764 0 10.782 0.038 ;
    END
  END p_y[85]
  PIN p_y[86]
    DIRECTION OUTPUT ;
    USE SIGNAL ;
    PORT
      LAYER M5 ;
        RECT  10.848 0 10.872 0.192 ;
    END
  END p_y[86]
  PIN p_y[87]
    DIRECTION OUTPUT ;
    USE SIGNAL ;
    PORT
      LAYER M3 ;
        RECT  10.944 0 10.962 0.038 ;
    END
  END p_y[87]
  PIN p_y[88]
    DIRECTION OUTPUT ;
    USE SIGNAL ;
    PORT
      LAYER M5 ;
        RECT  10.944 0 10.968 0.192 ;
    END
  END p_y[88]
  PIN p_y[89]
    DIRECTION OUTPUT ;
    USE SIGNAL ;
    PORT
      LAYER M3 ;
        RECT  11.556 0 11.574 0.038 ;
    END
  END p_y[89]
  PIN p_y[8]
    DIRECTION OUTPUT ;
    USE SIGNAL ;
    PORT
      LAYER M5 ;
        RECT  3.024 0 3.048 0.192 ;
    END
  END p_y[8]
  PIN p_y[90]
    DIRECTION OUTPUT ;
    USE SIGNAL ;
    PORT
      LAYER M5 ;
        RECT  11.568 0 11.592 0.192 ;
    END
  END p_y[90]
  PIN p_y[91]
    DIRECTION OUTPUT ;
    USE SIGNAL ;
    PORT
      LAYER M3 ;
        RECT  11.592 0 11.61 0.038 ;
    END
  END p_y[91]
  PIN p_y[92]
    DIRECTION OUTPUT ;
    USE SIGNAL ;
    PORT
      LAYER M5 ;
        RECT  11.616 0 11.64 0.192 ;
    END
  END p_y[92]
  PIN p_y[93]
    DIRECTION OUTPUT ;
    USE SIGNAL ;
    PORT
      LAYER M3 ;
        RECT  11.628 0 11.646 0.038 ;
    END
  END p_y[93]
  PIN p_y[94]
    DIRECTION OUTPUT ;
    USE SIGNAL ;
    PORT
      LAYER M5 ;
        RECT  11.664 0 11.688 0.192 ;
    END
  END p_y[94]
  PIN p_y[95]
    DIRECTION OUTPUT ;
    USE SIGNAL ;
    PORT
      LAYER M3 ;
        RECT  11.736 0 11.754 0.038 ;
    END
  END p_y[95]
  PIN p_y[96]
    DIRECTION OUTPUT ;
    USE SIGNAL ;
    PORT
      LAYER M5 ;
        RECT  11.856 0 11.88 0.192 ;
    END
  END p_y[96]
  PIN p_y[97]
    DIRECTION OUTPUT ;
    USE SIGNAL ;
    PORT
      LAYER M3 ;
        RECT  11.952 0 11.97 0.038 ;
    END
  END p_y[97]
  PIN p_y[98]
    DIRECTION OUTPUT ;
    USE SIGNAL ;
    PORT
      LAYER M5 ;
        RECT  12.048 0 12.072 0.192 ;
    END
  END p_y[98]
  PIN p_y[99]
    DIRECTION OUTPUT ;
    USE SIGNAL ;
    PORT
      LAYER M3 ;
        RECT  12.168 0 12.186 0.038 ;
    END
  END p_y[99]
  PIN p_y[9]
    DIRECTION OUTPUT ;
    USE SIGNAL ;
    PORT
      LAYER M3 ;
        RECT  3.096 0 3.114 0.038 ;
    END
  END p_y[9]
  PIN sk
    DIRECTION INPUT ;
    USE SIGNAL ;
    PORT
      LAYER M5 ;
        RECT  28.224 0 28.248 0.192 ;
    END
  END sk
  PIN srs
    DIRECTION INPUT ;
    USE SIGNAL ;
    PORT
      LAYER M5 ;
        RECT  28.416 0 28.44 0.192 ;
    END
  END srs
  PIN y_s[0]
    DIRECTION INPUT ;
    USE SIGNAL ;
    PORT
      LAYER M5 ;
        RECT  2.208 300.048 2.232 300.24 ;
    END
  END y_s[0]
  PIN y_s[100]
    DIRECTION INPUT ;
    USE SIGNAL ;
    PORT
      LAYER M5 ;
        RECT  12.24 300.048 12.264 300.24 ;
    END
  END y_s[100]
  PIN y_s[101]
    DIRECTION INPUT ;
    USE SIGNAL ;
    PORT
      LAYER M3 ;
        RECT  12.348 300.202 12.366 300.24 ;
    END
  END y_s[101]
  PIN y_s[102]
    DIRECTION INPUT ;
    USE SIGNAL ;
    PORT
      LAYER M5 ;
        RECT  12.432 300.048 12.456 300.24 ;
    END
  END y_s[102]
  PIN y_s[103]
    DIRECTION INPUT ;
    USE SIGNAL ;
    PORT
      LAYER M3 ;
        RECT  12.564 300.202 12.582 300.24 ;
    END
  END y_s[103]
  PIN y_s[104]
    DIRECTION INPUT ;
    USE SIGNAL ;
    PORT
      LAYER M5 ;
        RECT  12.672 300.048 12.696 300.24 ;
    END
  END y_s[104]
  PIN y_s[105]
    DIRECTION INPUT ;
    USE SIGNAL ;
    PORT
      LAYER M3 ;
        RECT  12.744 300.202 12.762 300.24 ;
    END
  END y_s[105]
  PIN y_s[106]
    DIRECTION INPUT ;
    USE SIGNAL ;
    PORT
      LAYER M5 ;
        RECT  12.864 300.048 12.888 300.24 ;
    END
  END y_s[106]
  PIN y_s[107]
    DIRECTION INPUT ;
    USE SIGNAL ;
    PORT
      LAYER M3 ;
        RECT  12.96 300.202 12.978 300.24 ;
    END
  END y_s[107]
  PIN y_s[108]
    DIRECTION INPUT ;
    USE SIGNAL ;
    PORT
      LAYER M5 ;
        RECT  13.056 300.048 13.08 300.24 ;
    END
  END y_s[108]
  PIN y_s[109]
    DIRECTION INPUT ;
    USE SIGNAL ;
    PORT
      LAYER M3 ;
        RECT  13.176 300.202 13.194 300.24 ;
    END
  END y_s[109]
  PIN y_s[10]
    DIRECTION INPUT ;
    USE SIGNAL ;
    PORT
      LAYER M5 ;
        RECT  3.216 300.048 3.24 300.24 ;
    END
  END y_s[10]
  PIN y_s[110]
    DIRECTION INPUT ;
    USE SIGNAL ;
    PORT
      LAYER M5 ;
        RECT  13.248 300.048 13.272 300.24 ;
    END
  END y_s[110]
  PIN y_s[111]
    DIRECTION INPUT ;
    USE SIGNAL ;
    PORT
      LAYER M3 ;
        RECT  13.356 300.202 13.374 300.24 ;
    END
  END y_s[111]
  PIN y_s[112]
    DIRECTION INPUT ;
    USE SIGNAL ;
    PORT
      LAYER M5 ;
        RECT  13.44 300.048 13.464 300.24 ;
    END
  END y_s[112]
  PIN y_s[113]
    DIRECTION INPUT ;
    USE SIGNAL ;
    PORT
      LAYER M3 ;
        RECT  13.572 300.202 13.59 300.24 ;
    END
  END y_s[113]
  PIN y_s[114]
    DIRECTION INPUT ;
    USE SIGNAL ;
    PORT
      LAYER M5 ;
        RECT  13.68 300.048 13.704 300.24 ;
    END
  END y_s[114]
  PIN y_s[115]
    DIRECTION INPUT ;
    USE SIGNAL ;
    PORT
      LAYER M3 ;
        RECT  13.752 300.202 13.77 300.24 ;
    END
  END y_s[115]
  PIN y_s[116]
    DIRECTION INPUT ;
    USE SIGNAL ;
    PORT
      LAYER M5 ;
        RECT  13.872 300.048 13.896 300.24 ;
    END
  END y_s[116]
  PIN y_s[117]
    DIRECTION INPUT ;
    USE SIGNAL ;
    PORT
      LAYER M3 ;
        RECT  13.968 300.202 13.986 300.24 ;
    END
  END y_s[117]
  PIN y_s[118]
    DIRECTION INPUT ;
    USE SIGNAL ;
    PORT
      LAYER M5 ;
        RECT  14.064 300.048 14.088 300.24 ;
    END
  END y_s[118]
  PIN y_s[119]
    DIRECTION INPUT ;
    USE SIGNAL ;
    PORT
      LAYER M3 ;
        RECT  14.184 300.202 14.202 300.24 ;
    END
  END y_s[119]
  PIN y_s[11]
    DIRECTION INPUT ;
    USE SIGNAL ;
    PORT
      LAYER M3 ;
        RECT  3.312 300.202 3.33 300.24 ;
    END
  END y_s[11]
  PIN y_s[120]
    DIRECTION INPUT ;
    USE SIGNAL ;
    PORT
      LAYER M5 ;
        RECT  14.256 300.048 14.28 300.24 ;
    END
  END y_s[120]
  PIN y_s[121]
    DIRECTION INPUT ;
    USE SIGNAL ;
    PORT
      LAYER M3 ;
        RECT  14.364 300.202 14.382 300.24 ;
    END
  END y_s[121]
  PIN y_s[122]
    DIRECTION INPUT ;
    USE SIGNAL ;
    PORT
      LAYER M5 ;
        RECT  14.448 300.048 14.472 300.24 ;
    END
  END y_s[122]
  PIN y_s[123]
    DIRECTION INPUT ;
    USE SIGNAL ;
    PORT
      LAYER M3 ;
        RECT  14.58 300.202 14.598 300.24 ;
    END
  END y_s[123]
  PIN y_s[124]
    DIRECTION INPUT ;
    USE SIGNAL ;
    PORT
      LAYER M5 ;
        RECT  14.688 300.048 14.712 300.24 ;
    END
  END y_s[124]
  PIN y_s[125]
    DIRECTION INPUT ;
    USE SIGNAL ;
    PORT
      LAYER M3 ;
        RECT  14.76 300.202 14.778 300.24 ;
    END
  END y_s[125]
  PIN y_s[126]
    DIRECTION INPUT ;
    USE SIGNAL ;
    PORT
      LAYER M5 ;
        RECT  14.88 300.048 14.904 300.24 ;
    END
  END y_s[126]
  PIN y_s[127]
    DIRECTION INPUT ;
    USE SIGNAL ;
    PORT
      LAYER M3 ;
        RECT  14.976 300.202 14.994 300.24 ;
    END
  END y_s[127]
  PIN y_s[128]
    DIRECTION INPUT ;
    USE SIGNAL ;
    PORT
      LAYER M5 ;
        RECT  15.072 300.048 15.096 300.24 ;
    END
  END y_s[128]
  PIN y_s[129]
    DIRECTION INPUT ;
    USE SIGNAL ;
    PORT
      LAYER M3 ;
        RECT  15.156 300.202 15.174 300.24 ;
    END
  END y_s[129]
  PIN y_s[12]
    DIRECTION INPUT ;
    USE SIGNAL ;
    PORT
      LAYER M5 ;
        RECT  3.408 300.048 3.432 300.24 ;
    END
  END y_s[12]
  PIN y_s[130]
    DIRECTION INPUT ;
    USE SIGNAL ;
    PORT
      LAYER M5 ;
        RECT  15.264 300.048 15.288 300.24 ;
    END
  END y_s[130]
  PIN y_s[131]
    DIRECTION INPUT ;
    USE SIGNAL ;
    PORT
      LAYER M3 ;
        RECT  15.372 300.202 15.39 300.24 ;
    END
  END y_s[131]
  PIN y_s[132]
    DIRECTION INPUT ;
    USE SIGNAL ;
    PORT
      LAYER M5 ;
        RECT  15.456 300.048 15.48 300.24 ;
    END
  END y_s[132]
  PIN y_s[133]
    DIRECTION INPUT ;
    USE SIGNAL ;
    PORT
      LAYER M3 ;
        RECT  15.588 300.202 15.606 300.24 ;
    END
  END y_s[133]
  PIN y_s[134]
    DIRECTION INPUT ;
    USE SIGNAL ;
    PORT
      LAYER M5 ;
        RECT  15.648 300.048 15.672 300.24 ;
    END
  END y_s[134]
  PIN y_s[135]
    DIRECTION INPUT ;
    USE SIGNAL ;
    PORT
      LAYER M3 ;
        RECT  15.768 300.202 15.786 300.24 ;
    END
  END y_s[135]
  PIN y_s[136]
    DIRECTION INPUT ;
    USE SIGNAL ;
    PORT
      LAYER M5 ;
        RECT  15.888 300.048 15.912 300.24 ;
    END
  END y_s[136]
  PIN y_s[137]
    DIRECTION INPUT ;
    USE SIGNAL ;
    PORT
      LAYER M3 ;
        RECT  15.984 300.202 16.002 300.24 ;
    END
  END y_s[137]
  PIN y_s[138]
    DIRECTION INPUT ;
    USE SIGNAL ;
    PORT
      LAYER M5 ;
        RECT  16.08 300.048 16.104 300.24 ;
    END
  END y_s[138]
  PIN y_s[139]
    DIRECTION INPUT ;
    USE SIGNAL ;
    PORT
      LAYER M3 ;
        RECT  16.164 300.202 16.182 300.24 ;
    END
  END y_s[139]
  PIN y_s[13]
    DIRECTION INPUT ;
    USE SIGNAL ;
    PORT
      LAYER M3 ;
        RECT  3.492 300.202 3.51 300.24 ;
    END
  END y_s[13]
  PIN y_s[140]
    DIRECTION INPUT ;
    USE SIGNAL ;
    PORT
      LAYER M5 ;
        RECT  16.272 300.048 16.296 300.24 ;
    END
  END y_s[140]
  PIN y_s[141]
    DIRECTION INPUT ;
    USE SIGNAL ;
    PORT
      LAYER M3 ;
        RECT  16.344 300.202 16.362 300.24 ;
    END
  END y_s[141]
  PIN y_s[142]
    DIRECTION INPUT ;
    USE SIGNAL ;
    PORT
      LAYER M5 ;
        RECT  16.368 300.048 16.392 300.24 ;
    END
  END y_s[142]
  PIN y_s[143]
    DIRECTION INPUT ;
    USE SIGNAL ;
    PORT
      LAYER M3 ;
        RECT  16.956 300.202 16.974 300.24 ;
    END
  END y_s[143]
  PIN y_s[144]
    DIRECTION INPUT ;
    USE SIGNAL ;
    PORT
      LAYER M5 ;
        RECT  16.944 300.048 16.968 300.24 ;
    END
  END y_s[144]
  PIN y_s[145]
    DIRECTION INPUT ;
    USE SIGNAL ;
    PORT
      LAYER M3 ;
        RECT  16.992 300.202 17.01 300.24 ;
    END
  END y_s[145]
  PIN y_s[146]
    DIRECTION INPUT ;
    USE SIGNAL ;
    PORT
      LAYER M5 ;
        RECT  16.992 300.048 17.016 300.24 ;
    END
  END y_s[146]
  PIN y_s[147]
    DIRECTION INPUT ;
    USE SIGNAL ;
    PORT
      LAYER M3 ;
        RECT  17.028 300.202 17.046 300.24 ;
    END
  END y_s[147]
  PIN y_s[148]
    DIRECTION INPUT ;
    USE SIGNAL ;
    PORT
      LAYER M5 ;
        RECT  17.088 300.048 17.112 300.24 ;
    END
  END y_s[148]
  PIN y_s[149]
    DIRECTION INPUT ;
    USE SIGNAL ;
    PORT
      LAYER M3 ;
        RECT  17.172 300.202 17.19 300.24 ;
    END
  END y_s[149]
  PIN y_s[14]
    DIRECTION INPUT ;
    USE SIGNAL ;
    PORT
      LAYER M5 ;
        RECT  3.6 300.048 3.624 300.24 ;
    END
  END y_s[14]
  PIN y_s[150]
    DIRECTION INPUT ;
    USE SIGNAL ;
    PORT
      LAYER M5 ;
        RECT  17.28 300.048 17.304 300.24 ;
    END
  END y_s[150]
  PIN y_s[151]
    DIRECTION INPUT ;
    USE SIGNAL ;
    PORT
      LAYER M3 ;
        RECT  17.388 300.202 17.406 300.24 ;
    END
  END y_s[151]
  PIN y_s[152]
    DIRECTION INPUT ;
    USE SIGNAL ;
    PORT
      LAYER M5 ;
        RECT  17.472 300.048 17.496 300.24 ;
    END
  END y_s[152]
  PIN y_s[153]
    DIRECTION INPUT ;
    USE SIGNAL ;
    PORT
      LAYER M3 ;
        RECT  17.568 300.202 17.586 300.24 ;
    END
  END y_s[153]
  PIN y_s[154]
    DIRECTION INPUT ;
    USE SIGNAL ;
    PORT
      LAYER M5 ;
        RECT  17.664 300.048 17.688 300.24 ;
    END
  END y_s[154]
  PIN y_s[155]
    DIRECTION INPUT ;
    USE SIGNAL ;
    PORT
      LAYER M3 ;
        RECT  17.784 300.202 17.802 300.24 ;
    END
  END y_s[155]
  PIN y_s[156]
    DIRECTION INPUT ;
    USE SIGNAL ;
    PORT
      LAYER M5 ;
        RECT  17.904 300.048 17.928 300.24 ;
    END
  END y_s[156]
  PIN y_s[157]
    DIRECTION INPUT ;
    USE SIGNAL ;
    PORT
      LAYER M3 ;
        RECT  18 300.202 18.018 300.24 ;
    END
  END y_s[157]
  PIN y_s[158]
    DIRECTION INPUT ;
    USE SIGNAL ;
    PORT
      LAYER M5 ;
        RECT  18.096 300.048 18.12 300.24 ;
    END
  END y_s[158]
  PIN y_s[159]
    DIRECTION INPUT ;
    USE SIGNAL ;
    PORT
      LAYER M3 ;
        RECT  18.18 300.202 18.198 300.24 ;
    END
  END y_s[159]
  PIN y_s[15]
    DIRECTION INPUT ;
    USE SIGNAL ;
    PORT
      LAYER M3 ;
        RECT  3.708 300.202 3.726 300.24 ;
    END
  END y_s[15]
  PIN y_s[160]
    DIRECTION INPUT ;
    USE SIGNAL ;
    PORT
      LAYER M5 ;
        RECT  18.288 300.048 18.312 300.24 ;
    END
  END y_s[160]
  PIN y_s[161]
    DIRECTION INPUT ;
    USE SIGNAL ;
    PORT
      LAYER M3 ;
        RECT  18.396 300.202 18.414 300.24 ;
    END
  END y_s[161]
  PIN y_s[162]
    DIRECTION INPUT ;
    USE SIGNAL ;
    PORT
      LAYER M5 ;
        RECT  18.48 300.048 18.504 300.24 ;
    END
  END y_s[162]
  PIN y_s[163]
    DIRECTION INPUT ;
    USE SIGNAL ;
    PORT
      LAYER M3 ;
        RECT  18.576 300.202 18.594 300.24 ;
    END
  END y_s[163]
  PIN y_s[164]
    DIRECTION INPUT ;
    USE SIGNAL ;
    PORT
      LAYER M5 ;
        RECT  18.672 300.048 18.696 300.24 ;
    END
  END y_s[164]
  PIN y_s[165]
    DIRECTION INPUT ;
    USE SIGNAL ;
    PORT
      LAYER M3 ;
        RECT  18.792 300.202 18.81 300.24 ;
    END
  END y_s[165]
  PIN y_s[166]
    DIRECTION INPUT ;
    USE SIGNAL ;
    PORT
      LAYER M5 ;
        RECT  18.912 300.048 18.936 300.24 ;
    END
  END y_s[166]
  PIN y_s[167]
    DIRECTION INPUT ;
    USE SIGNAL ;
    PORT
      LAYER M3 ;
        RECT  19.008 300.202 19.026 300.24 ;
    END
  END y_s[167]
  PIN y_s[168]
    DIRECTION INPUT ;
    USE SIGNAL ;
    PORT
      LAYER M5 ;
        RECT  19.104 300.048 19.128 300.24 ;
    END
  END y_s[168]
  PIN y_s[169]
    DIRECTION INPUT ;
    USE SIGNAL ;
    PORT
      LAYER M3 ;
        RECT  19.188 300.202 19.206 300.24 ;
    END
  END y_s[169]
  PIN y_s[16]
    DIRECTION INPUT ;
    USE SIGNAL ;
    PORT
      LAYER M5 ;
        RECT  3.792 300.048 3.816 300.24 ;
    END
  END y_s[16]
  PIN y_s[170]
    DIRECTION INPUT ;
    USE SIGNAL ;
    PORT
      LAYER M5 ;
        RECT  19.296 300.048 19.32 300.24 ;
    END
  END y_s[170]
  PIN y_s[171]
    DIRECTION INPUT ;
    USE SIGNAL ;
    PORT
      LAYER M3 ;
        RECT  19.404 300.202 19.422 300.24 ;
    END
  END y_s[171]
  PIN y_s[172]
    DIRECTION INPUT ;
    USE SIGNAL ;
    PORT
      LAYER M5 ;
        RECT  19.488 300.048 19.512 300.24 ;
    END
  END y_s[172]
  PIN y_s[173]
    DIRECTION INPUT ;
    USE SIGNAL ;
    PORT
      LAYER M3 ;
        RECT  19.584 300.202 19.602 300.24 ;
    END
  END y_s[173]
  PIN y_s[174]
    DIRECTION INPUT ;
    USE SIGNAL ;
    PORT
      LAYER M5 ;
        RECT  19.68 300.048 19.704 300.24 ;
    END
  END y_s[174]
  PIN y_s[175]
    DIRECTION INPUT ;
    USE SIGNAL ;
    PORT
      LAYER M3 ;
        RECT  19.8 300.202 19.818 300.24 ;
    END
  END y_s[175]
  PIN y_s[176]
    DIRECTION INPUT ;
    USE SIGNAL ;
    PORT
      LAYER M5 ;
        RECT  19.872 300.048 19.896 300.24 ;
    END
  END y_s[176]
  PIN y_s[177]
    DIRECTION INPUT ;
    USE SIGNAL ;
    PORT
      LAYER M3 ;
        RECT  20.016 300.202 20.034 300.24 ;
    END
  END y_s[177]
  PIN y_s[178]
    DIRECTION INPUT ;
    USE SIGNAL ;
    PORT
      LAYER M5 ;
        RECT  20.112 300.048 20.136 300.24 ;
    END
  END y_s[178]
  PIN y_s[179]
    DIRECTION INPUT ;
    USE SIGNAL ;
    PORT
      LAYER M3 ;
        RECT  20.196 300.202 20.214 300.24 ;
    END
  END y_s[179]
  PIN y_s[17]
    DIRECTION INPUT ;
    USE SIGNAL ;
    PORT
      LAYER M3 ;
        RECT  3.924 300.202 3.942 300.24 ;
    END
  END y_s[17]
  PIN y_s[180]
    DIRECTION INPUT ;
    USE SIGNAL ;
    PORT
      LAYER M5 ;
        RECT  20.304 300.048 20.328 300.24 ;
    END
  END y_s[180]
  PIN y_s[181]
    DIRECTION INPUT ;
    USE SIGNAL ;
    PORT
      LAYER M3 ;
        RECT  20.412 300.202 20.43 300.24 ;
    END
  END y_s[181]
  PIN y_s[182]
    DIRECTION INPUT ;
    USE SIGNAL ;
    PORT
      LAYER M5 ;
        RECT  20.496 300.048 20.52 300.24 ;
    END
  END y_s[182]
  PIN y_s[183]
    DIRECTION INPUT ;
    USE SIGNAL ;
    PORT
      LAYER M3 ;
        RECT  20.592 300.202 20.61 300.24 ;
    END
  END y_s[183]
  PIN y_s[184]
    DIRECTION INPUT ;
    USE SIGNAL ;
    PORT
      LAYER M5 ;
        RECT  20.688 300.048 20.712 300.24 ;
    END
  END y_s[184]
  PIN y_s[185]
    DIRECTION INPUT ;
    USE SIGNAL ;
    PORT
      LAYER M3 ;
        RECT  20.808 300.202 20.826 300.24 ;
    END
  END y_s[185]
  PIN y_s[186]
    DIRECTION INPUT ;
    USE SIGNAL ;
    PORT
      LAYER M5 ;
        RECT  20.88 300.048 20.904 300.24 ;
    END
  END y_s[186]
  PIN y_s[187]
    DIRECTION INPUT ;
    USE SIGNAL ;
    PORT
      LAYER M3 ;
        RECT  20.988 300.202 21.006 300.24 ;
    END
  END y_s[187]
  PIN y_s[188]
    DIRECTION INPUT ;
    USE SIGNAL ;
    PORT
      LAYER M5 ;
        RECT  21.12 300.048 21.144 300.24 ;
    END
  END y_s[188]
  PIN y_s[189]
    DIRECTION INPUT ;
    USE SIGNAL ;
    PORT
      LAYER M3 ;
        RECT  21.204 300.202 21.222 300.24 ;
    END
  END y_s[189]
  PIN y_s[18]
    DIRECTION INPUT ;
    USE SIGNAL ;
    PORT
      LAYER M5 ;
        RECT  4.032 300.048 4.056 300.24 ;
    END
  END y_s[18]
  PIN y_s[190]
    DIRECTION INPUT ;
    USE SIGNAL ;
    PORT
      LAYER M5 ;
        RECT  21.312 300.048 21.336 300.24 ;
    END
  END y_s[190]
  PIN y_s[191]
    DIRECTION INPUT ;
    USE SIGNAL ;
    PORT
      LAYER M3 ;
        RECT  21.42 300.202 21.438 300.24 ;
    END
  END y_s[191]
  PIN y_s[192]
    DIRECTION INPUT ;
    USE SIGNAL ;
    PORT
      LAYER M5 ;
        RECT  21.504 300.048 21.528 300.24 ;
    END
  END y_s[192]
  PIN y_s[193]
    DIRECTION INPUT ;
    USE SIGNAL ;
    PORT
      LAYER M3 ;
        RECT  21.6 300.202 21.618 300.24 ;
    END
  END y_s[193]
  PIN y_s[194]
    DIRECTION INPUT ;
    USE SIGNAL ;
    PORT
      LAYER M5 ;
        RECT  21.696 300.048 21.72 300.24 ;
    END
  END y_s[194]
  PIN y_s[195]
    DIRECTION INPUT ;
    USE SIGNAL ;
    PORT
      LAYER M3 ;
        RECT  21.744 300.202 21.762 300.24 ;
    END
  END y_s[195]
  PIN y_s[196]
    DIRECTION INPUT ;
    USE SIGNAL ;
    PORT
      LAYER M5 ;
        RECT  21.744 300.048 21.768 300.24 ;
    END
  END y_s[196]
  PIN y_s[197]
    DIRECTION INPUT ;
    USE SIGNAL ;
    PORT
      LAYER M3 ;
        RECT  22.356 300.202 22.374 300.24 ;
    END
  END y_s[197]
  PIN y_s[198]
    DIRECTION INPUT ;
    USE SIGNAL ;
    PORT
      LAYER M5 ;
        RECT  22.368 300.048 22.392 300.24 ;
    END
  END y_s[198]
  PIN y_s[199]
    DIRECTION INPUT ;
    USE SIGNAL ;
    PORT
      LAYER M3 ;
        RECT  22.392 300.202 22.41 300.24 ;
    END
  END y_s[199]
  PIN y_s[19]
    DIRECTION INPUT ;
    USE SIGNAL ;
    PORT
      LAYER M3 ;
        RECT  4.104 300.202 4.122 300.24 ;
    END
  END y_s[19]
  PIN y_s[1]
    DIRECTION INPUT ;
    USE SIGNAL ;
    PORT
      LAYER M3 ;
        RECT  2.304 300.202 2.322 300.24 ;
    END
  END y_s[1]
  PIN y_s[200]
    DIRECTION INPUT ;
    USE SIGNAL ;
    PORT
      LAYER M5 ;
        RECT  22.416 300.048 22.44 300.24 ;
    END
  END y_s[200]
  PIN y_s[201]
    DIRECTION INPUT ;
    USE SIGNAL ;
    PORT
      LAYER M3 ;
        RECT  22.428 300.202 22.446 300.24 ;
    END
  END y_s[201]
  PIN y_s[202]
    DIRECTION INPUT ;
    USE SIGNAL ;
    PORT
      LAYER M5 ;
        RECT  22.512 300.048 22.536 300.24 ;
    END
  END y_s[202]
  PIN y_s[203]
    DIRECTION INPUT ;
    USE SIGNAL ;
    PORT
      LAYER M3 ;
        RECT  22.608 300.202 22.626 300.24 ;
    END
  END y_s[203]
  PIN y_s[204]
    DIRECTION INPUT ;
    USE SIGNAL ;
    PORT
      LAYER M5 ;
        RECT  22.704 300.048 22.728 300.24 ;
    END
  END y_s[204]
  PIN y_s[205]
    DIRECTION INPUT ;
    USE SIGNAL ;
    PORT
      LAYER M3 ;
        RECT  22.824 300.202 22.842 300.24 ;
    END
  END y_s[205]
  PIN y_s[206]
    DIRECTION INPUT ;
    USE SIGNAL ;
    PORT
      LAYER M5 ;
        RECT  22.896 300.048 22.92 300.24 ;
    END
  END y_s[206]
  PIN y_s[207]
    DIRECTION INPUT ;
    USE SIGNAL ;
    PORT
      LAYER M3 ;
        RECT  23.004 300.202 23.022 300.24 ;
    END
  END y_s[207]
  PIN y_s[208]
    DIRECTION INPUT ;
    USE SIGNAL ;
    PORT
      LAYER M5 ;
        RECT  23.136 300.048 23.16 300.24 ;
    END
  END y_s[208]
  PIN y_s[209]
    DIRECTION INPUT ;
    USE SIGNAL ;
    PORT
      LAYER M3 ;
        RECT  23.22 300.202 23.238 300.24 ;
    END
  END y_s[209]
  PIN y_s[20]
    DIRECTION INPUT ;
    USE SIGNAL ;
    PORT
      LAYER M5 ;
        RECT  4.224 300.048 4.248 300.24 ;
    END
  END y_s[20]
  PIN y_s[210]
    DIRECTION INPUT ;
    USE SIGNAL ;
    PORT
      LAYER M5 ;
        RECT  23.328 300.048 23.352 300.24 ;
    END
  END y_s[210]
  PIN y_s[211]
    DIRECTION INPUT ;
    USE SIGNAL ;
    PORT
      LAYER M3 ;
        RECT  23.4 300.202 23.418 300.24 ;
    END
  END y_s[211]
  PIN y_s[212]
    DIRECTION INPUT ;
    USE SIGNAL ;
    PORT
      LAYER M5 ;
        RECT  23.52 300.048 23.544 300.24 ;
    END
  END y_s[212]
  PIN y_s[213]
    DIRECTION INPUT ;
    USE SIGNAL ;
    PORT
      LAYER M3 ;
        RECT  23.616 300.202 23.634 300.24 ;
    END
  END y_s[213]
  PIN y_s[214]
    DIRECTION INPUT ;
    USE SIGNAL ;
    PORT
      LAYER M5 ;
        RECT  23.712 300.048 23.736 300.24 ;
    END
  END y_s[214]
  PIN y_s[215]
    DIRECTION INPUT ;
    USE SIGNAL ;
    PORT
      LAYER M3 ;
        RECT  23.832 300.202 23.85 300.24 ;
    END
  END y_s[215]
  PIN y_s[216]
    DIRECTION INPUT ;
    USE SIGNAL ;
    PORT
      LAYER M5 ;
        RECT  23.904 300.048 23.928 300.24 ;
    END
  END y_s[216]
  PIN y_s[217]
    DIRECTION INPUT ;
    USE SIGNAL ;
    PORT
      LAYER M3 ;
        RECT  24.012 300.202 24.03 300.24 ;
    END
  END y_s[217]
  PIN y_s[218]
    DIRECTION INPUT ;
    USE SIGNAL ;
    PORT
      LAYER M5 ;
        RECT  24.096 300.048 24.12 300.24 ;
    END
  END y_s[218]
  PIN y_s[219]
    DIRECTION INPUT ;
    USE SIGNAL ;
    PORT
      LAYER M3 ;
        RECT  24.228 300.202 24.246 300.24 ;
    END
  END y_s[219]
  PIN y_s[21]
    DIRECTION INPUT ;
    USE SIGNAL ;
    PORT
      LAYER M3 ;
        RECT  4.32 300.202 4.338 300.24 ;
    END
  END y_s[21]
  PIN y_s[220]
    DIRECTION INPUT ;
    USE SIGNAL ;
    PORT
      LAYER M5 ;
        RECT  24.336 300.048 24.36 300.24 ;
    END
  END y_s[220]
  PIN y_s[221]
    DIRECTION INPUT ;
    USE SIGNAL ;
    PORT
      LAYER M3 ;
        RECT  24.408 300.202 24.426 300.24 ;
    END
  END y_s[221]
  PIN y_s[222]
    DIRECTION INPUT ;
    USE SIGNAL ;
    PORT
      LAYER M5 ;
        RECT  24.528 300.048 24.552 300.24 ;
    END
  END y_s[222]
  PIN y_s[223]
    DIRECTION INPUT ;
    USE SIGNAL ;
    PORT
      LAYER M3 ;
        RECT  24.624 300.202 24.642 300.24 ;
    END
  END y_s[223]
  PIN y_s[224]
    DIRECTION INPUT ;
    USE SIGNAL ;
    PORT
      LAYER M5 ;
        RECT  24.72 300.048 24.744 300.24 ;
    END
  END y_s[224]
  PIN y_s[225]
    DIRECTION INPUT ;
    USE SIGNAL ;
    PORT
      LAYER M3 ;
        RECT  24.84 300.202 24.858 300.24 ;
    END
  END y_s[225]
  PIN y_s[226]
    DIRECTION INPUT ;
    USE SIGNAL ;
    PORT
      LAYER M5 ;
        RECT  24.912 300.048 24.936 300.24 ;
    END
  END y_s[226]
  PIN y_s[227]
    DIRECTION INPUT ;
    USE SIGNAL ;
    PORT
      LAYER M3 ;
        RECT  25.02 300.202 25.038 300.24 ;
    END
  END y_s[227]
  PIN y_s[228]
    DIRECTION INPUT ;
    USE SIGNAL ;
    PORT
      LAYER M5 ;
        RECT  25.104 300.048 25.128 300.24 ;
    END
  END y_s[228]
  PIN y_s[229]
    DIRECTION INPUT ;
    USE SIGNAL ;
    PORT
      LAYER M3 ;
        RECT  25.236 300.202 25.254 300.24 ;
    END
  END y_s[229]
  PIN y_s[22]
    DIRECTION INPUT ;
    USE SIGNAL ;
    PORT
      LAYER M5 ;
        RECT  4.416 300.048 4.44 300.24 ;
    END
  END y_s[22]
  PIN y_s[230]
    DIRECTION INPUT ;
    USE SIGNAL ;
    PORT
      LAYER M5 ;
        RECT  25.344 300.048 25.368 300.24 ;
    END
  END y_s[230]
  PIN y_s[231]
    DIRECTION INPUT ;
    USE SIGNAL ;
    PORT
      LAYER M3 ;
        RECT  25.416 300.202 25.434 300.24 ;
    END
  END y_s[231]
  PIN y_s[232]
    DIRECTION INPUT ;
    USE SIGNAL ;
    PORT
      LAYER M5 ;
        RECT  25.536 300.048 25.56 300.24 ;
    END
  END y_s[232]
  PIN y_s[233]
    DIRECTION INPUT ;
    USE SIGNAL ;
    PORT
      LAYER M3 ;
        RECT  25.632 300.202 25.65 300.24 ;
    END
  END y_s[233]
  PIN y_s[234]
    DIRECTION INPUT ;
    USE SIGNAL ;
    PORT
      LAYER M5 ;
        RECT  25.728 300.048 25.752 300.24 ;
    END
  END y_s[234]
  PIN y_s[235]
    DIRECTION INPUT ;
    USE SIGNAL ;
    PORT
      LAYER M3 ;
        RECT  25.812 300.202 25.83 300.24 ;
    END
  END y_s[235]
  PIN y_s[236]
    DIRECTION INPUT ;
    USE SIGNAL ;
    PORT
      LAYER M5 ;
        RECT  25.92 300.048 25.944 300.24 ;
    END
  END y_s[236]
  PIN y_s[237]
    DIRECTION INPUT ;
    USE SIGNAL ;
    PORT
      LAYER M3 ;
        RECT  26.028 300.202 26.046 300.24 ;
    END
  END y_s[237]
  PIN y_s[238]
    DIRECTION INPUT ;
    USE SIGNAL ;
    PORT
      LAYER M5 ;
        RECT  26.112 300.048 26.136 300.24 ;
    END
  END y_s[238]
  PIN y_s[239]
    DIRECTION INPUT ;
    USE SIGNAL ;
    PORT
      LAYER M3 ;
        RECT  26.244 300.202 26.262 300.24 ;
    END
  END y_s[239]
  PIN y_s[23]
    DIRECTION INPUT ;
    USE SIGNAL ;
    PORT
      LAYER M3 ;
        RECT  4.5 300.202 4.518 300.24 ;
    END
  END y_s[23]
  PIN y_s[240]
    DIRECTION INPUT ;
    USE SIGNAL ;
    PORT
      LAYER M5 ;
        RECT  26.352 300.048 26.376 300.24 ;
    END
  END y_s[240]
  PIN y_s[241]
    DIRECTION INPUT ;
    USE SIGNAL ;
    PORT
      LAYER M3 ;
        RECT  26.424 300.202 26.442 300.24 ;
    END
  END y_s[241]
  PIN y_s[242]
    DIRECTION INPUT ;
    USE SIGNAL ;
    PORT
      LAYER M5 ;
        RECT  26.544 300.048 26.568 300.24 ;
    END
  END y_s[242]
  PIN y_s[243]
    DIRECTION INPUT ;
    USE SIGNAL ;
    PORT
      LAYER M3 ;
        RECT  26.64 300.202 26.658 300.24 ;
    END
  END y_s[243]
  PIN y_s[244]
    DIRECTION INPUT ;
    USE SIGNAL ;
    PORT
      LAYER M5 ;
        RECT  26.736 300.048 26.76 300.24 ;
    END
  END y_s[244]
  PIN y_s[245]
    DIRECTION INPUT ;
    USE SIGNAL ;
    PORT
      LAYER M3 ;
        RECT  26.82 300.202 26.838 300.24 ;
    END
  END y_s[245]
  PIN y_s[246]
    DIRECTION INPUT ;
    USE SIGNAL ;
    PORT
      LAYER M5 ;
        RECT  26.928 300.048 26.952 300.24 ;
    END
  END y_s[246]
  PIN y_s[247]
    DIRECTION INPUT ;
    USE SIGNAL ;
    PORT
      LAYER M3 ;
        RECT  27.036 300.202 27.054 300.24 ;
    END
  END y_s[247]
  PIN y_s[248]
    DIRECTION INPUT ;
    USE SIGNAL ;
    PORT
      LAYER M5 ;
        RECT  27.12 300.048 27.144 300.24 ;
    END
  END y_s[248]
  PIN y_s[249]
    DIRECTION INPUT ;
    USE SIGNAL ;
    PORT
      LAYER M3 ;
        RECT  27.144 300.202 27.162 300.24 ;
    END
  END y_s[249]
  PIN y_s[24]
    DIRECTION INPUT ;
    USE SIGNAL ;
    PORT
      LAYER M5 ;
        RECT  4.608 300.048 4.632 300.24 ;
    END
  END y_s[24]
  PIN y_s[250]
    DIRECTION INPUT ;
    USE SIGNAL ;
    PORT
      LAYER M5 ;
        RECT  27.168 300.048 27.192 300.24 ;
    END
  END y_s[250]
  PIN y_s[251]
    DIRECTION INPUT ;
    USE SIGNAL ;
    PORT
      LAYER M3 ;
        RECT  27.756 300.202 27.774 300.24 ;
    END
  END y_s[251]
  PIN y_s[252]
    DIRECTION INPUT ;
    USE SIGNAL ;
    PORT
      LAYER M5 ;
        RECT  27.744 300.048 27.768 300.24 ;
    END
  END y_s[252]
  PIN y_s[253]
    DIRECTION INPUT ;
    USE SIGNAL ;
    PORT
      LAYER M3 ;
        RECT  27.792 300.202 27.81 300.24 ;
    END
  END y_s[253]
  PIN y_s[254]
    DIRECTION INPUT ;
    USE SIGNAL ;
    PORT
      LAYER M5 ;
        RECT  27.792 300.048 27.816 300.24 ;
    END
  END y_s[254]
  PIN y_s[255]
    DIRECTION INPUT ;
    USE SIGNAL ;
    PORT
      LAYER M3 ;
        RECT  27.828 300.202 27.846 300.24 ;
    END
  END y_s[255]
  PIN y_s[25]
    DIRECTION INPUT ;
    USE SIGNAL ;
    PORT
      LAYER M3 ;
        RECT  4.716 300.202 4.734 300.24 ;
    END
  END y_s[25]
  PIN y_s[26]
    DIRECTION INPUT ;
    USE SIGNAL ;
    PORT
      LAYER M5 ;
        RECT  4.8 300.048 4.824 300.24 ;
    END
  END y_s[26]
  PIN y_s[27]
    DIRECTION INPUT ;
    USE SIGNAL ;
    PORT
      LAYER M3 ;
        RECT  4.932 300.202 4.95 300.24 ;
    END
  END y_s[27]
  PIN y_s[28]
    DIRECTION INPUT ;
    USE SIGNAL ;
    PORT
      LAYER M5 ;
        RECT  4.992 300.048 5.016 300.24 ;
    END
  END y_s[28]
  PIN y_s[29]
    DIRECTION INPUT ;
    USE SIGNAL ;
    PORT
      LAYER M3 ;
        RECT  5.112 300.202 5.13 300.24 ;
    END
  END y_s[29]
  PIN y_s[2]
    DIRECTION INPUT ;
    USE SIGNAL ;
    PORT
      LAYER M5 ;
        RECT  2.4 300.048 2.424 300.24 ;
    END
  END y_s[2]
  PIN y_s[30]
    DIRECTION INPUT ;
    USE SIGNAL ;
    PORT
      LAYER M5 ;
        RECT  5.232 300.048 5.256 300.24 ;
    END
  END y_s[30]
  PIN y_s[31]
    DIRECTION INPUT ;
    USE SIGNAL ;
    PORT
      LAYER M3 ;
        RECT  5.328 300.202 5.346 300.24 ;
    END
  END y_s[31]
  PIN y_s[32]
    DIRECTION INPUT ;
    USE SIGNAL ;
    PORT
      LAYER M5 ;
        RECT  5.424 300.048 5.448 300.24 ;
    END
  END y_s[32]
  PIN y_s[33]
    DIRECTION INPUT ;
    USE SIGNAL ;
    PORT
      LAYER M3 ;
        RECT  5.508 300.202 5.526 300.24 ;
    END
  END y_s[33]
  PIN y_s[34]
    DIRECTION INPUT ;
    USE SIGNAL ;
    PORT
      LAYER M5 ;
        RECT  5.568 300.048 5.592 300.24 ;
    END
  END y_s[34]
  PIN y_s[35]
    DIRECTION INPUT ;
    USE SIGNAL ;
    PORT
      LAYER M3 ;
        RECT  5.544 300.202 5.562 300.24 ;
    END
  END y_s[35]
  PIN y_s[36]
    DIRECTION INPUT ;
    USE SIGNAL ;
    PORT
      LAYER M5 ;
        RECT  6.144 300.048 6.168 300.24 ;
    END
  END y_s[36]
  PIN y_s[37]
    DIRECTION INPUT ;
    USE SIGNAL ;
    PORT
      LAYER M3 ;
        RECT  6.156 300.202 6.174 300.24 ;
    END
  END y_s[37]
  PIN y_s[38]
    DIRECTION INPUT ;
    USE SIGNAL ;
    PORT
      LAYER M5 ;
        RECT  6.192 300.048 6.216 300.24 ;
    END
  END y_s[38]
  PIN y_s[39]
    DIRECTION INPUT ;
    USE SIGNAL ;
    PORT
      LAYER M3 ;
        RECT  6.192 300.202 6.21 300.24 ;
    END
  END y_s[39]
  PIN y_s[3]
    DIRECTION INPUT ;
    USE SIGNAL ;
    PORT
      LAYER M3 ;
        RECT  2.52 300.202 2.538 300.24 ;
    END
  END y_s[3]
  PIN y_s[40]
    DIRECTION INPUT ;
    USE SIGNAL ;
    PORT
      LAYER M5 ;
        RECT  6.24 300.048 6.264 300.24 ;
    END
  END y_s[40]
  PIN y_s[41]
    DIRECTION INPUT ;
    USE SIGNAL ;
    PORT
      LAYER M3 ;
        RECT  6.336 300.202 6.354 300.24 ;
    END
  END y_s[41]
  PIN y_s[42]
    DIRECTION INPUT ;
    USE SIGNAL ;
    PORT
      LAYER M5 ;
        RECT  6.432 300.048 6.456 300.24 ;
    END
  END y_s[42]
  PIN y_s[43]
    DIRECTION INPUT ;
    USE SIGNAL ;
    PORT
      LAYER M3 ;
        RECT  6.516 300.202 6.534 300.24 ;
    END
  END y_s[43]
  PIN y_s[44]
    DIRECTION INPUT ;
    USE SIGNAL ;
    PORT
      LAYER M5 ;
        RECT  6.624 300.048 6.648 300.24 ;
    END
  END y_s[44]
  PIN y_s[45]
    DIRECTION INPUT ;
    USE SIGNAL ;
    PORT
      LAYER M3 ;
        RECT  6.732 300.202 6.75 300.24 ;
    END
  END y_s[45]
  PIN y_s[46]
    DIRECTION INPUT ;
    USE SIGNAL ;
    PORT
      LAYER M5 ;
        RECT  6.816 300.048 6.84 300.24 ;
    END
  END y_s[46]
  PIN y_s[47]
    DIRECTION INPUT ;
    USE SIGNAL ;
    PORT
      LAYER M3 ;
        RECT  6.912 300.202 6.93 300.24 ;
    END
  END y_s[47]
  PIN y_s[48]
    DIRECTION INPUT ;
    USE SIGNAL ;
    PORT
      LAYER M5 ;
        RECT  7.008 300.048 7.032 300.24 ;
    END
  END y_s[48]
  PIN y_s[49]
    DIRECTION INPUT ;
    USE SIGNAL ;
    PORT
      LAYER M3 ;
        RECT  7.128 300.202 7.146 300.24 ;
    END
  END y_s[49]
  PIN y_s[4]
    DIRECTION INPUT ;
    USE SIGNAL ;
    PORT
      LAYER M5 ;
        RECT  2.592 300.048 2.616 300.24 ;
    END
  END y_s[4]
  PIN y_s[50]
    DIRECTION INPUT ;
    USE SIGNAL ;
    PORT
      LAYER M5 ;
        RECT  7.248 300.048 7.272 300.24 ;
    END
  END y_s[50]
  PIN y_s[51]
    DIRECTION INPUT ;
    USE SIGNAL ;
    PORT
      LAYER M3 ;
        RECT  7.344 300.202 7.362 300.24 ;
    END
  END y_s[51]
  PIN y_s[52]
    DIRECTION INPUT ;
    USE SIGNAL ;
    PORT
      LAYER M5 ;
        RECT  7.44 300.048 7.464 300.24 ;
    END
  END y_s[52]
  PIN y_s[53]
    DIRECTION INPUT ;
    USE SIGNAL ;
    PORT
      LAYER M3 ;
        RECT  7.524 300.202 7.542 300.24 ;
    END
  END y_s[53]
  PIN y_s[54]
    DIRECTION INPUT ;
    USE SIGNAL ;
    PORT
      LAYER M5 ;
        RECT  7.632 300.048 7.656 300.24 ;
    END
  END y_s[54]
  PIN y_s[55]
    DIRECTION INPUT ;
    USE SIGNAL ;
    PORT
      LAYER M3 ;
        RECT  7.74 300.202 7.758 300.24 ;
    END
  END y_s[55]
  PIN y_s[56]
    DIRECTION INPUT ;
    USE SIGNAL ;
    PORT
      LAYER M5 ;
        RECT  7.824 300.048 7.848 300.24 ;
    END
  END y_s[56]
  PIN y_s[57]
    DIRECTION INPUT ;
    USE SIGNAL ;
    PORT
      LAYER M3 ;
        RECT  7.92 300.202 7.938 300.24 ;
    END
  END y_s[57]
  PIN y_s[58]
    DIRECTION INPUT ;
    USE SIGNAL ;
    PORT
      LAYER M5 ;
        RECT  8.016 300.048 8.04 300.24 ;
    END
  END y_s[58]
  PIN y_s[59]
    DIRECTION INPUT ;
    USE SIGNAL ;
    PORT
      LAYER M3 ;
        RECT  8.136 300.202 8.154 300.24 ;
    END
  END y_s[59]
  PIN y_s[5]
    DIRECTION INPUT ;
    USE SIGNAL ;
    PORT
      LAYER M3 ;
        RECT  2.7 300.202 2.718 300.24 ;
    END
  END y_s[5]
  PIN y_s[60]
    DIRECTION INPUT ;
    USE SIGNAL ;
    PORT
      LAYER M5 ;
        RECT  8.208 300.048 8.232 300.24 ;
    END
  END y_s[60]
  PIN y_s[61]
    DIRECTION INPUT ;
    USE SIGNAL ;
    PORT
      LAYER M3 ;
        RECT  8.352 300.202 8.37 300.24 ;
    END
  END y_s[61]
  PIN y_s[62]
    DIRECTION INPUT ;
    USE SIGNAL ;
    PORT
      LAYER M5 ;
        RECT  8.448 300.048 8.472 300.24 ;
    END
  END y_s[62]
  PIN y_s[63]
    DIRECTION INPUT ;
    USE SIGNAL ;
    PORT
      LAYER M3 ;
        RECT  8.532 300.202 8.55 300.24 ;
    END
  END y_s[63]
  PIN y_s[64]
    DIRECTION INPUT ;
    USE SIGNAL ;
    PORT
      LAYER M5 ;
        RECT  8.64 300.048 8.664 300.24 ;
    END
  END y_s[64]
  PIN y_s[65]
    DIRECTION INPUT ;
    USE SIGNAL ;
    PORT
      LAYER M3 ;
        RECT  8.748 300.202 8.766 300.24 ;
    END
  END y_s[65]
  PIN y_s[66]
    DIRECTION INPUT ;
    USE SIGNAL ;
    PORT
      LAYER M5 ;
        RECT  8.832 300.048 8.856 300.24 ;
    END
  END y_s[66]
  PIN y_s[67]
    DIRECTION INPUT ;
    USE SIGNAL ;
    PORT
      LAYER M3 ;
        RECT  8.928 300.202 8.946 300.24 ;
    END
  END y_s[67]
  PIN y_s[68]
    DIRECTION INPUT ;
    USE SIGNAL ;
    PORT
      LAYER M5 ;
        RECT  9.024 300.048 9.048 300.24 ;
    END
  END y_s[68]
  PIN y_s[69]
    DIRECTION INPUT ;
    USE SIGNAL ;
    PORT
      LAYER M3 ;
        RECT  9.144 300.202 9.162 300.24 ;
    END
  END y_s[69]
  PIN y_s[6]
    DIRECTION INPUT ;
    USE SIGNAL ;
    PORT
      LAYER M5 ;
        RECT  2.784 300.048 2.808 300.24 ;
    END
  END y_s[6]
  PIN y_s[70]
    DIRECTION INPUT ;
    USE SIGNAL ;
    PORT
      LAYER M5 ;
        RECT  9.216 300.048 9.24 300.24 ;
    END
  END y_s[70]
  PIN y_s[71]
    DIRECTION INPUT ;
    USE SIGNAL ;
    PORT
      LAYER M3 ;
        RECT  9.324 300.202 9.342 300.24 ;
    END
  END y_s[71]
  PIN y_s[72]
    DIRECTION INPUT ;
    USE SIGNAL ;
    PORT
      LAYER M5 ;
        RECT  9.456 300.048 9.48 300.24 ;
    END
  END y_s[72]
  PIN y_s[73]
    DIRECTION INPUT ;
    USE SIGNAL ;
    PORT
      LAYER M3 ;
        RECT  9.54 300.202 9.558 300.24 ;
    END
  END y_s[73]
  PIN y_s[74]
    DIRECTION INPUT ;
    USE SIGNAL ;
    PORT
      LAYER M5 ;
        RECT  9.648 300.048 9.672 300.24 ;
    END
  END y_s[74]
  PIN y_s[75]
    DIRECTION INPUT ;
    USE SIGNAL ;
    PORT
      LAYER M3 ;
        RECT  9.756 300.202 9.774 300.24 ;
    END
  END y_s[75]
  PIN y_s[76]
    DIRECTION INPUT ;
    USE SIGNAL ;
    PORT
      LAYER M5 ;
        RECT  9.84 300.048 9.864 300.24 ;
    END
  END y_s[76]
  PIN y_s[77]
    DIRECTION INPUT ;
    USE SIGNAL ;
    PORT
      LAYER M3 ;
        RECT  9.936 300.202 9.954 300.24 ;
    END
  END y_s[77]
  PIN y_s[78]
    DIRECTION INPUT ;
    USE SIGNAL ;
    PORT
      LAYER M5 ;
        RECT  10.032 300.048 10.056 300.24 ;
    END
  END y_s[78]
  PIN y_s[79]
    DIRECTION INPUT ;
    USE SIGNAL ;
    PORT
      LAYER M3 ;
        RECT  10.152 300.202 10.17 300.24 ;
    END
  END y_s[79]
  PIN y_s[7]
    DIRECTION INPUT ;
    USE SIGNAL ;
    PORT
      LAYER M3 ;
        RECT  2.916 300.202 2.934 300.24 ;
    END
  END y_s[7]
  PIN y_s[80]
    DIRECTION INPUT ;
    USE SIGNAL ;
    PORT
      LAYER M5 ;
        RECT  10.224 300.048 10.248 300.24 ;
    END
  END y_s[80]
  PIN y_s[81]
    DIRECTION INPUT ;
    USE SIGNAL ;
    PORT
      LAYER M3 ;
        RECT  10.332 300.202 10.35 300.24 ;
    END
  END y_s[81]
  PIN y_s[82]
    DIRECTION INPUT ;
    USE SIGNAL ;
    PORT
      LAYER M5 ;
        RECT  10.464 300.048 10.488 300.24 ;
    END
  END y_s[82]
  PIN y_s[83]
    DIRECTION INPUT ;
    USE SIGNAL ;
    PORT
      LAYER M3 ;
        RECT  10.548 300.202 10.566 300.24 ;
    END
  END y_s[83]
  PIN y_s[84]
    DIRECTION INPUT ;
    USE SIGNAL ;
    PORT
      LAYER M5 ;
        RECT  10.656 300.048 10.68 300.24 ;
    END
  END y_s[84]
  PIN y_s[85]
    DIRECTION INPUT ;
    USE SIGNAL ;
    PORT
      LAYER M3 ;
        RECT  10.764 300.202 10.782 300.24 ;
    END
  END y_s[85]
  PIN y_s[86]
    DIRECTION INPUT ;
    USE SIGNAL ;
    PORT
      LAYER M5 ;
        RECT  10.848 300.048 10.872 300.24 ;
    END
  END y_s[86]
  PIN y_s[87]
    DIRECTION INPUT ;
    USE SIGNAL ;
    PORT
      LAYER M3 ;
        RECT  10.944 300.202 10.962 300.24 ;
    END
  END y_s[87]
  PIN y_s[88]
    DIRECTION INPUT ;
    USE SIGNAL ;
    PORT
      LAYER M5 ;
        RECT  10.944 300.048 10.968 300.24 ;
    END
  END y_s[88]
  PIN y_s[89]
    DIRECTION INPUT ;
    USE SIGNAL ;
    PORT
      LAYER M3 ;
        RECT  11.556 300.202 11.574 300.24 ;
    END
  END y_s[89]
  PIN y_s[8]
    DIRECTION INPUT ;
    USE SIGNAL ;
    PORT
      LAYER M5 ;
        RECT  3.024 300.048 3.048 300.24 ;
    END
  END y_s[8]
  PIN y_s[90]
    DIRECTION INPUT ;
    USE SIGNAL ;
    PORT
      LAYER M5 ;
        RECT  11.568 300.048 11.592 300.24 ;
    END
  END y_s[90]
  PIN y_s[91]
    DIRECTION INPUT ;
    USE SIGNAL ;
    PORT
      LAYER M3 ;
        RECT  11.592 300.202 11.61 300.24 ;
    END
  END y_s[91]
  PIN y_s[92]
    DIRECTION INPUT ;
    USE SIGNAL ;
    PORT
      LAYER M5 ;
        RECT  11.616 300.048 11.64 300.24 ;
    END
  END y_s[92]
  PIN y_s[93]
    DIRECTION INPUT ;
    USE SIGNAL ;
    PORT
      LAYER M3 ;
        RECT  11.628 300.202 11.646 300.24 ;
    END
  END y_s[93]
  PIN y_s[94]
    DIRECTION INPUT ;
    USE SIGNAL ;
    PORT
      LAYER M5 ;
        RECT  11.664 300.048 11.688 300.24 ;
    END
  END y_s[94]
  PIN y_s[95]
    DIRECTION INPUT ;
    USE SIGNAL ;
    PORT
      LAYER M3 ;
        RECT  11.736 300.202 11.754 300.24 ;
    END
  END y_s[95]
  PIN y_s[96]
    DIRECTION INPUT ;
    USE SIGNAL ;
    PORT
      LAYER M5 ;
        RECT  11.856 300.048 11.88 300.24 ;
    END
  END y_s[96]
  PIN y_s[97]
    DIRECTION INPUT ;
    USE SIGNAL ;
    PORT
      LAYER M3 ;
        RECT  11.952 300.202 11.97 300.24 ;
    END
  END y_s[97]
  PIN y_s[98]
    DIRECTION INPUT ;
    USE SIGNAL ;
    PORT
      LAYER M5 ;
        RECT  12.048 300.048 12.072 300.24 ;
    END
  END y_s[98]
  PIN y_s[99]
    DIRECTION INPUT ;
    USE SIGNAL ;
    PORT
      LAYER M3 ;
        RECT  12.168 300.202 12.186 300.24 ;
    END
  END y_s[99]
  PIN y_s[9]
    DIRECTION INPUT ;
    USE SIGNAL ;
    PORT
      LAYER M3 ;
        RECT  3.096 300.202 3.114 300.24 ;
    END
  END y_s[9]
  PIN yacc
    DIRECTION INPUT ;
    USE SIGNAL ;
    PORT
      LAYER M5 ;
        RECT  28.608 0 28.632 0.192 ;
    END
  END yacc
  PIN VDD
    DIRECTION INOUT ;
    USE POWER ;
    PORT
      LAYER M5 ;
        RECT  29.592 2.151 29.712 298.089 ;
        RECT  24.192 2.151 24.312 298.089 ;
        RECT  18.792 2.151 18.912 298.089 ;
        RECT  13.392 2.151 13.512 298.089 ;
        RECT  7.992 2.151 8.112 298.089 ;
        RECT  2.592 2.151 2.712 298.089 ;
    END
  END VDD
  PIN VSS
    DIRECTION INOUT ;
    USE GROUND ;
    PORT
      LAYER M5 ;
        RECT  29.4 2.137 29.52 298.103 ;
        RECT  24 2.137 24.12 298.103 ;
        RECT  18.6 2.137 18.72 298.103 ;
        RECT  13.2 2.137 13.32 298.103 ;
        RECT  7.8 2.137 7.92 298.103 ;
        RECT  2.4 2.137 2.52 298.103 ;
    END
  END VSS
  # OT_OBS_CLOSED layer=M5 d_um=1.536 added=40
  OBS
    LAYER RVTN ;
     RECT  2.16 2.16 30.24 2.295 ;
     RECT  2.16 2.565 30.24 2.835 ;
     RECT  2.16 3.105 30.24 3.375 ;
     RECT  2.16 3.645 30.24 3.915 ;
     RECT  2.16 4.185 30.24 4.455 ;
     RECT  2.16 4.725 30.24 4.995 ;
     RECT  2.16 5.265 30.24 5.535 ;
     RECT  2.16 5.805 30.24 6.075 ;
     RECT  2.16 6.345 30.24 6.615 ;
     RECT  2.16 6.885 30.24 7.155 ;
     RECT  2.16 7.425 30.24 7.695 ;
     RECT  2.16 7.965 30.24 8.235 ;
     RECT  2.16 8.505 30.24 8.775 ;
     RECT  2.16 9.045 30.24 9.315 ;
     RECT  2.16 9.585 30.24 9.855 ;
     RECT  2.16 10.125 30.24 10.395 ;
     RECT  2.16 10.665 30.24 10.935 ;
     RECT  2.16 11.205 30.24 11.475 ;
     RECT  2.16 11.745 30.24 12.015 ;
     RECT  2.16 12.285 30.24 12.555 ;
     RECT  2.16 12.825 30.24 13.095 ;
     RECT  2.16 13.365 30.24 13.635 ;
     RECT  2.16 13.905 30.24 14.175 ;
     RECT  2.16 14.445 30.24 14.715 ;
     RECT  2.16 14.985 30.24 15.255 ;
     RECT  2.16 15.525 30.24 15.795 ;
     RECT  2.16 16.065 30.24 16.335 ;
     RECT  2.16 16.605 30.24 16.875 ;
     RECT  2.16 17.145 30.24 17.415 ;
     RECT  2.16 17.685 30.24 17.955 ;
     RECT  2.16 18.225 30.24 18.495 ;
     RECT  2.16 18.765 30.24 19.035 ;
     RECT  2.16 19.305 30.24 19.575 ;
     RECT  2.16 19.845 30.24 20.115 ;
     RECT  2.16 20.385 30.24 20.655 ;
     RECT  2.16 20.925 30.24 21.195 ;
     RECT  2.16 21.465 30.24 21.735 ;
     RECT  2.16 22.005 30.24 22.275 ;
     RECT  2.16 22.545 30.24 22.815 ;
     RECT  2.16 23.085 30.24 23.355 ;
     RECT  2.16 23.625 30.24 23.895 ;
     RECT  2.16 24.165 30.24 24.435 ;
     RECT  2.16 24.705 30.24 24.975 ;
     RECT  2.16 25.245 30.24 25.515 ;
     RECT  2.16 25.785 30.24 26.055 ;
     RECT  2.16 26.325 30.24 26.595 ;
     RECT  2.16 26.865 30.24 27.135 ;
     RECT  2.16 27.405 30.24 27.675 ;
     RECT  2.16 27.945 30.24 28.215 ;
     RECT  2.16 28.485 30.24 28.755 ;
     RECT  2.16 29.025 30.24 29.295 ;
     RECT  2.16 29.565 30.24 29.835 ;
     RECT  2.16 30.105 30.24 30.375 ;
     RECT  2.16 30.645 30.24 30.915 ;
     RECT  2.16 31.185 30.24 31.455 ;
     RECT  2.16 31.725 30.24 31.995 ;
     RECT  2.16 32.265 30.24 32.535 ;
     RECT  2.16 32.805 30.24 33.075 ;
     RECT  2.16 33.345 30.24 33.615 ;
     RECT  2.16 33.885 30.24 34.155 ;
     RECT  2.16 34.425 30.24 34.695 ;
     RECT  2.16 34.965 30.24 35.235 ;
     RECT  2.16 35.505 30.24 35.775 ;
     RECT  2.16 36.045 30.24 36.315 ;
     RECT  2.16 36.585 30.24 36.855 ;
     RECT  2.16 37.125 30.24 37.395 ;
     RECT  2.16 37.665 30.24 37.935 ;
     RECT  2.16 38.205 30.24 38.475 ;
     RECT  2.16 38.745 30.24 39.015 ;
     RECT  2.16 39.285 30.24 39.555 ;
     RECT  2.16 39.825 30.24 40.095 ;
     RECT  2.16 40.365 30.24 40.635 ;
     RECT  2.16 40.905 30.24 41.175 ;
     RECT  2.16 41.445 30.24 41.715 ;
     RECT  2.16 41.985 30.24 42.255 ;
     RECT  2.16 42.525 30.24 42.795 ;
     RECT  2.16 43.065 30.24 43.335 ;
     RECT  2.16 43.605 30.24 43.875 ;
     RECT  2.16 44.145 30.24 44.415 ;
     RECT  2.16 44.685 30.24 44.955 ;
     RECT  2.16 45.225 30.24 45.495 ;
     RECT  2.16 45.765 30.24 46.035 ;
     RECT  2.16 46.305 30.24 46.575 ;
     RECT  2.16 46.845 30.24 47.115 ;
     RECT  2.16 47.385 30.24 47.655 ;
     RECT  2.16 47.925 30.24 48.195 ;
     RECT  2.16 48.465 30.24 48.735 ;
     RECT  2.16 49.005 30.24 49.275 ;
     RECT  2.16 49.545 30.24 49.815 ;
     RECT  2.16 50.085 30.24 50.355 ;
     RECT  2.16 50.625 30.24 50.895 ;
     RECT  2.16 51.165 30.24 51.435 ;
     RECT  2.16 51.705 30.24 51.975 ;
     RECT  2.16 52.245 30.24 52.515 ;
     RECT  2.16 52.785 30.24 53.055 ;
     RECT  2.16 53.325 30.24 53.595 ;
     RECT  2.16 53.865 30.24 54.135 ;
     RECT  2.16 54.405 30.24 54.675 ;
     RECT  2.16 54.945 30.24 55.215 ;
     RECT  2.16 55.485 30.24 55.755 ;
     RECT  2.16 56.025 30.24 56.295 ;
     RECT  2.16 56.565 30.24 56.835 ;
     RECT  2.16 57.105 30.24 57.375 ;
     RECT  2.16 57.645 30.24 57.915 ;
     RECT  2.16 58.185 30.24 58.455 ;
     RECT  2.16 58.725 30.24 58.995 ;
     RECT  2.16 59.265 30.24 59.535 ;
     RECT  2.16 59.805 30.24 60.075 ;
     RECT  2.16 60.345 30.24 60.615 ;
     RECT  2.16 60.885 30.24 61.155 ;
     RECT  2.16 61.425 30.24 61.695 ;
     RECT  2.16 61.965 30.24 62.235 ;
     RECT  2.16 62.505 30.24 62.775 ;
     RECT  2.16 63.045 30.24 63.315 ;
     RECT  2.16 63.585 30.24 63.855 ;
     RECT  2.16 64.125 30.24 64.395 ;
     RECT  2.16 64.665 30.24 64.935 ;
     RECT  2.16 65.205 30.24 65.475 ;
     RECT  2.16 65.745 30.24 66.015 ;
     RECT  2.16 66.285 30.24 66.555 ;
     RECT  2.16 66.825 30.24 67.095 ;
     RECT  2.16 67.365 30.24 67.635 ;
     RECT  2.16 67.905 30.24 68.175 ;
     RECT  2.16 68.445 30.24 68.715 ;
     RECT  2.16 68.985 30.24 69.255 ;
     RECT  2.16 69.525 30.24 69.795 ;
     RECT  2.16 70.065 30.24 70.335 ;
     RECT  2.16 70.605 30.24 70.875 ;
     RECT  2.16 71.145 30.24 71.415 ;
     RECT  2.16 71.685 30.24 71.955 ;
     RECT  2.16 72.225 30.24 72.495 ;
     RECT  2.16 72.765 30.24 73.035 ;
     RECT  2.16 73.305 30.24 73.575 ;
     RECT  2.16 73.845 30.24 74.115 ;
     RECT  2.16 74.385 30.24 74.655 ;
     RECT  2.16 74.925 30.24 75.195 ;
     RECT  2.16 75.465 30.24 75.735 ;
     RECT  2.16 76.005 30.24 76.275 ;
     RECT  2.16 76.545 30.24 76.815 ;
     RECT  2.16 77.085 30.24 77.355 ;
     RECT  2.16 77.625 30.24 77.895 ;
     RECT  2.16 78.165 30.24 78.435 ;
     RECT  2.16 78.705 30.24 78.975 ;
     RECT  2.16 79.245 30.24 79.515 ;
     RECT  2.16 79.785 30.24 80.055 ;
     RECT  2.16 80.325 30.24 80.595 ;
     RECT  2.16 80.865 30.24 81.135 ;
     RECT  2.16 81.405 30.24 81.675 ;
     RECT  2.16 81.945 30.24 82.215 ;
     RECT  2.16 82.485 30.24 82.755 ;
     RECT  2.16 83.025 30.24 83.295 ;
     RECT  2.16 83.565 30.24 83.835 ;
     RECT  2.16 84.105 30.24 84.375 ;
     RECT  2.16 84.645 30.24 84.915 ;
     RECT  2.16 85.185 30.24 85.455 ;
     RECT  2.16 85.725 30.24 85.995 ;
     RECT  2.16 86.265 30.24 86.535 ;
     RECT  2.16 86.805 30.24 87.075 ;
     RECT  2.16 87.345 30.24 87.615 ;
     RECT  2.16 87.885 30.24 88.155 ;
     RECT  2.16 88.425 30.24 88.695 ;
     RECT  2.16 88.965 30.24 89.235 ;
     RECT  2.16 89.505 30.24 89.775 ;
     RECT  2.16 90.045 30.24 90.315 ;
     RECT  2.16 90.585 30.24 90.855 ;
     RECT  2.16 91.125 30.24 91.395 ;
     RECT  2.16 91.665 30.24 91.935 ;
     RECT  2.16 92.205 30.24 92.475 ;
     RECT  2.16 92.745 30.24 93.015 ;
     RECT  2.16 93.285 30.24 93.555 ;
     RECT  2.16 93.825 30.24 94.095 ;
     RECT  2.16 94.365 30.24 94.635 ;
     RECT  2.16 94.905 30.24 95.175 ;
     RECT  2.16 95.445 30.24 95.715 ;
     RECT  2.16 95.985 30.24 96.255 ;
     RECT  2.16 96.525 30.24 96.795 ;
     RECT  2.16 97.065 30.24 97.335 ;
     RECT  2.16 97.605 30.24 97.875 ;
     RECT  2.16 98.145 30.24 98.415 ;
     RECT  2.16 98.685 30.24 98.955 ;
     RECT  2.16 99.225 30.24 99.495 ;
     RECT  2.16 99.765 30.24 100.035 ;
     RECT  2.16 100.305 30.24 100.575 ;
     RECT  2.16 100.845 30.24 101.115 ;
     RECT  2.16 101.385 30.24 101.655 ;
     RECT  2.16 101.925 30.24 102.195 ;
     RECT  2.16 102.465 30.24 102.735 ;
     RECT  2.16 103.005 30.24 103.275 ;
     RECT  2.16 103.545 30.24 103.815 ;
     RECT  2.16 104.085 30.24 104.355 ;
     RECT  2.16 104.625 30.24 104.895 ;
     RECT  2.16 105.165 30.24 105.435 ;
     RECT  2.16 105.705 30.24 105.975 ;
     RECT  2.16 106.245 30.24 106.515 ;
     RECT  2.16 106.785 30.24 107.055 ;
     RECT  2.16 107.325 30.24 107.595 ;
     RECT  2.16 107.865 30.24 108.135 ;
     RECT  2.16 108.405 30.24 108.675 ;
     RECT  2.16 108.945 30.24 109.215 ;
     RECT  2.16 109.485 30.24 109.755 ;
     RECT  2.16 110.025 30.24 110.295 ;
     RECT  2.16 110.565 30.24 110.835 ;
     RECT  2.16 111.105 30.24 111.375 ;
     RECT  2.16 111.645 30.24 111.915 ;
     RECT  2.16 112.185 30.24 112.455 ;
     RECT  2.16 112.725 30.24 112.995 ;
     RECT  2.16 113.265 30.24 113.535 ;
     RECT  2.16 113.805 30.24 114.075 ;
     RECT  2.16 114.345 30.24 114.615 ;
     RECT  2.16 114.885 30.24 115.155 ;
     RECT  2.16 115.425 30.24 115.695 ;
     RECT  2.16 115.965 30.24 116.235 ;
     RECT  2.16 116.505 30.24 116.775 ;
     RECT  2.16 117.045 30.24 117.315 ;
     RECT  2.16 117.585 30.24 117.855 ;
     RECT  2.16 118.125 30.24 118.395 ;
     RECT  2.16 118.665 30.24 118.935 ;
     RECT  2.16 119.205 30.24 119.475 ;
     RECT  2.16 119.745 30.24 120.015 ;
     RECT  2.16 120.285 30.24 120.555 ;
     RECT  2.16 120.825 30.24 121.095 ;
     RECT  2.16 121.365 30.24 121.635 ;
     RECT  2.16 121.905 30.24 122.175 ;
     RECT  2.16 122.445 30.24 122.715 ;
     RECT  2.16 122.985 30.24 123.255 ;
     RECT  2.16 123.525 30.24 123.795 ;
     RECT  2.16 124.065 30.24 124.335 ;
     RECT  2.16 124.605 30.24 124.875 ;
     RECT  2.16 125.145 30.24 125.415 ;
     RECT  2.16 125.685 30.24 125.955 ;
     RECT  2.16 126.225 30.24 126.495 ;
     RECT  2.16 126.765 30.24 127.035 ;
     RECT  2.16 127.305 30.24 127.575 ;
     RECT  2.16 127.845 30.24 128.115 ;
     RECT  2.16 128.385 30.24 128.655 ;
     RECT  2.16 128.925 30.24 129.195 ;
     RECT  2.16 129.465 30.24 129.735 ;
     RECT  2.16 130.005 30.24 130.275 ;
     RECT  2.16 130.545 30.24 130.815 ;
     RECT  2.16 131.085 30.24 131.355 ;
     RECT  2.16 131.625 30.24 131.895 ;
     RECT  2.16 132.165 30.24 132.435 ;
     RECT  2.16 132.705 30.24 132.975 ;
     RECT  2.16 133.245 30.24 133.515 ;
     RECT  2.16 133.785 30.24 134.055 ;
     RECT  2.16 134.325 30.24 134.595 ;
     RECT  2.16 134.865 30.24 135.135 ;
     RECT  2.16 135.405 30.24 135.675 ;
     RECT  2.16 135.945 30.24 136.215 ;
     RECT  2.16 136.485 30.24 136.755 ;
     RECT  2.16 137.025 30.24 137.295 ;
     RECT  2.16 137.565 30.24 137.835 ;
     RECT  2.16 138.105 30.24 138.375 ;
     RECT  2.16 138.645 30.24 138.915 ;
     RECT  2.16 139.185 30.24 139.455 ;
     RECT  2.16 139.725 30.24 139.995 ;
     RECT  2.16 140.265 30.24 140.535 ;
     RECT  2.16 140.805 30.24 141.075 ;
     RECT  2.16 141.345 30.24 141.615 ;
     RECT  2.16 141.885 30.24 142.155 ;
     RECT  2.16 142.425 30.24 142.695 ;
     RECT  2.16 142.965 30.24 143.235 ;
     RECT  2.16 143.505 30.24 143.775 ;
     RECT  2.16 144.045 30.24 144.315 ;
     RECT  2.16 144.585 30.24 144.855 ;
     RECT  2.16 145.125 30.24 145.395 ;
     RECT  2.16 145.665 30.24 145.935 ;
     RECT  2.16 146.205 30.24 146.475 ;
     RECT  2.16 146.745 30.24 147.015 ;
     RECT  2.16 147.285 30.24 147.555 ;
     RECT  2.16 147.825 30.24 148.095 ;
     RECT  2.16 148.365 30.24 148.635 ;
     RECT  2.16 148.905 30.24 149.175 ;
     RECT  2.16 149.445 30.24 149.715 ;
     RECT  2.16 149.985 30.24 150.255 ;
     RECT  2.16 150.525 30.24 150.795 ;
     RECT  2.16 151.065 30.24 151.335 ;
     RECT  2.16 151.605 30.24 151.875 ;
     RECT  2.16 152.145 30.24 152.415 ;
     RECT  2.16 152.685 30.24 152.955 ;
     RECT  2.16 153.225 30.24 153.495 ;
     RECT  2.16 153.765 30.24 154.035 ;
     RECT  2.16 154.305 30.24 154.575 ;
     RECT  2.16 154.845 30.24 155.115 ;
     RECT  2.16 155.385 30.24 155.655 ;
     RECT  2.16 155.925 30.24 156.195 ;
     RECT  2.16 156.465 30.24 156.735 ;
     RECT  2.16 157.005 30.24 157.275 ;
     RECT  2.16 157.545 30.24 157.815 ;
     RECT  2.16 158.085 30.24 158.355 ;
     RECT  2.16 158.625 30.24 158.895 ;
     RECT  2.16 159.165 30.24 159.435 ;
     RECT  2.16 159.705 30.24 159.975 ;
     RECT  2.16 160.245 30.24 160.515 ;
     RECT  2.16 160.785 30.24 161.055 ;
     RECT  2.16 161.325 30.24 161.595 ;
     RECT  2.16 161.865 30.24 162.135 ;
     RECT  2.16 162.405 30.24 162.675 ;
     RECT  2.16 162.945 30.24 163.215 ;
     RECT  2.16 163.485 30.24 163.755 ;
     RECT  2.16 164.025 30.24 164.295 ;
     RECT  2.16 164.565 30.24 164.835 ;
     RECT  2.16 165.105 30.24 165.375 ;
     RECT  2.16 165.645 30.24 165.915 ;
     RECT  2.16 166.185 30.24 166.455 ;
     RECT  2.16 166.725 30.24 166.995 ;
     RECT  2.16 167.265 30.24 167.535 ;
     RECT  2.16 167.805 30.24 168.075 ;
     RECT  2.16 168.345 30.24 168.615 ;
     RECT  2.16 168.885 30.24 169.155 ;
     RECT  2.16 169.425 30.24 169.695 ;
     RECT  2.16 169.965 30.24 170.235 ;
     RECT  2.16 170.505 30.24 170.775 ;
     RECT  2.16 171.045 30.24 171.315 ;
     RECT  2.16 171.585 30.24 171.855 ;
     RECT  2.16 172.125 30.24 172.395 ;
     RECT  2.16 172.665 30.24 172.935 ;
     RECT  2.16 173.205 30.24 173.475 ;
     RECT  2.16 173.745 30.24 174.015 ;
     RECT  2.16 174.285 30.24 174.555 ;
     RECT  2.16 174.825 30.24 175.095 ;
     RECT  2.16 175.365 30.24 175.635 ;
     RECT  2.16 175.905 30.24 176.175 ;
     RECT  2.16 176.445 30.24 176.715 ;
     RECT  2.16 176.985 30.24 177.255 ;
     RECT  2.16 177.525 30.24 177.795 ;
     RECT  2.16 178.065 30.24 178.335 ;
     RECT  2.16 178.605 30.24 178.875 ;
     RECT  2.16 179.145 30.24 179.415 ;
     RECT  2.16 179.685 30.24 179.955 ;
     RECT  2.16 180.225 30.24 180.495 ;
     RECT  2.16 180.765 30.24 181.035 ;
     RECT  2.16 181.305 30.24 181.575 ;
     RECT  2.16 181.845 30.24 182.115 ;
     RECT  2.16 182.385 30.24 182.655 ;
     RECT  2.16 182.925 30.24 183.195 ;
     RECT  2.16 183.465 30.24 183.735 ;
     RECT  2.16 184.005 30.24 184.275 ;
     RECT  2.16 184.545 30.24 184.815 ;
     RECT  2.16 185.085 30.24 185.355 ;
     RECT  2.16 185.625 30.24 185.895 ;
     RECT  2.16 186.165 30.24 186.435 ;
     RECT  2.16 186.705 30.24 186.975 ;
     RECT  2.16 187.245 30.24 187.515 ;
     RECT  2.16 187.785 30.24 188.055 ;
     RECT  2.16 188.325 30.24 188.595 ;
     RECT  2.16 188.865 30.24 189.135 ;
     RECT  2.16 189.405 30.24 189.675 ;
     RECT  2.16 189.945 30.24 190.215 ;
     RECT  2.16 190.485 30.24 190.755 ;
     RECT  2.16 191.025 30.24 191.295 ;
     RECT  2.16 191.565 30.24 191.835 ;
     RECT  2.16 192.105 30.24 192.375 ;
     RECT  2.16 192.645 30.24 192.915 ;
     RECT  2.16 193.185 30.24 193.455 ;
     RECT  2.16 193.725 30.24 193.995 ;
     RECT  2.16 194.265 30.24 194.535 ;
     RECT  2.16 194.805 30.24 195.075 ;
     RECT  2.16 195.345 30.24 195.615 ;
     RECT  2.16 195.885 30.24 196.155 ;
     RECT  2.16 196.425 30.24 196.695 ;
     RECT  2.16 196.965 30.24 197.235 ;
     RECT  2.16 197.505 30.24 197.775 ;
     RECT  2.16 198.045 30.24 198.315 ;
     RECT  2.16 198.585 30.24 198.855 ;
     RECT  2.16 199.125 30.24 199.395 ;
     RECT  2.16 199.665 30.24 199.935 ;
     RECT  2.16 200.205 30.24 200.475 ;
     RECT  2.16 200.745 30.24 201.015 ;
     RECT  2.16 201.285 30.24 201.555 ;
     RECT  2.16 201.825 30.24 202.095 ;
     RECT  2.16 202.365 30.24 202.635 ;
     RECT  2.16 202.905 30.24 203.175 ;
     RECT  2.16 203.445 30.24 203.715 ;
     RECT  2.16 203.985 30.24 204.255 ;
     RECT  2.16 204.525 30.24 204.795 ;
     RECT  2.16 205.065 30.24 205.335 ;
     RECT  2.16 205.605 30.24 205.875 ;
     RECT  2.16 206.145 30.24 206.415 ;
     RECT  2.16 206.685 30.24 206.955 ;
     RECT  2.16 207.225 30.24 207.495 ;
     RECT  2.16 207.765 30.24 208.035 ;
     RECT  2.16 208.305 30.24 208.575 ;
     RECT  2.16 208.845 30.24 209.115 ;
     RECT  2.16 209.385 30.24 209.655 ;
     RECT  2.16 209.925 30.24 210.195 ;
     RECT  2.16 210.465 30.24 210.735 ;
     RECT  2.16 211.005 30.24 211.275 ;
     RECT  2.16 211.545 30.24 211.815 ;
     RECT  2.16 212.085 30.24 212.355 ;
     RECT  2.16 212.625 30.24 212.895 ;
     RECT  2.16 213.165 30.24 213.435 ;
     RECT  2.16 213.705 30.24 213.975 ;
     RECT  2.16 214.245 30.24 214.515 ;
     RECT  2.16 214.785 30.24 215.055 ;
     RECT  2.16 215.325 30.24 215.595 ;
     RECT  2.16 215.865 30.24 216.135 ;
     RECT  2.16 216.405 30.24 216.675 ;
     RECT  2.16 216.945 30.24 217.215 ;
     RECT  2.16 217.485 30.24 217.755 ;
     RECT  2.16 218.025 30.24 218.295 ;
     RECT  2.16 218.565 30.24 218.835 ;
     RECT  2.16 219.105 30.24 219.375 ;
     RECT  2.16 219.645 30.24 219.915 ;
     RECT  2.16 220.185 30.24 220.455 ;
     RECT  2.16 220.725 30.24 220.995 ;
     RECT  2.16 221.265 30.24 221.535 ;
     RECT  2.16 221.805 30.24 222.075 ;
     RECT  2.16 222.345 30.24 222.615 ;
     RECT  2.16 222.885 30.24 223.155 ;
     RECT  2.16 223.425 30.24 223.695 ;
     RECT  2.16 223.965 30.24 224.235 ;
     RECT  2.16 224.505 30.24 224.775 ;
     RECT  2.16 225.045 30.24 225.315 ;
     RECT  2.16 225.585 30.24 225.855 ;
     RECT  2.16 226.125 30.24 226.395 ;
     RECT  2.16 226.665 30.24 226.935 ;
     RECT  2.16 227.205 30.24 227.475 ;
     RECT  2.16 227.745 30.24 228.015 ;
     RECT  2.16 228.285 30.24 228.555 ;
     RECT  2.16 228.825 30.24 229.095 ;
     RECT  2.16 229.365 30.24 229.635 ;
     RECT  2.16 229.905 30.24 230.175 ;
     RECT  2.16 230.445 30.24 230.715 ;
     RECT  2.16 230.985 30.24 231.255 ;
     RECT  2.16 231.525 30.24 231.795 ;
     RECT  2.16 232.065 30.24 232.335 ;
     RECT  2.16 232.605 30.24 232.875 ;
     RECT  2.16 233.145 30.24 233.415 ;
     RECT  2.16 233.685 30.24 233.955 ;
     RECT  2.16 234.225 30.24 234.495 ;
     RECT  2.16 234.765 30.24 235.035 ;
     RECT  2.16 235.305 30.24 235.575 ;
     RECT  2.16 235.845 30.24 236.115 ;
     RECT  2.16 236.385 30.24 236.655 ;
     RECT  2.16 236.925 30.24 237.195 ;
     RECT  2.16 237.465 30.24 237.735 ;
     RECT  2.16 238.005 30.24 238.275 ;
     RECT  2.16 238.545 30.24 238.815 ;
     RECT  2.16 239.085 30.24 239.355 ;
     RECT  2.16 239.625 30.24 239.895 ;
     RECT  2.16 240.165 30.24 240.435 ;
     RECT  2.16 240.705 30.24 240.975 ;
     RECT  2.16 241.245 30.24 241.515 ;
     RECT  2.16 241.785 30.24 242.055 ;
     RECT  2.16 242.325 30.24 242.595 ;
     RECT  2.16 242.865 30.24 243.135 ;
     RECT  2.16 243.405 30.24 243.675 ;
     RECT  2.16 243.945 30.24 244.215 ;
     RECT  2.16 244.485 30.24 244.755 ;
     RECT  2.16 245.025 30.24 245.295 ;
     RECT  2.16 245.565 30.24 245.835 ;
     RECT  2.16 246.105 30.24 246.375 ;
     RECT  2.16 246.645 30.24 246.915 ;
     RECT  2.16 247.185 30.24 247.455 ;
     RECT  2.16 247.725 30.24 247.995 ;
     RECT  2.16 248.265 30.24 248.535 ;
     RECT  2.16 248.805 30.24 249.075 ;
     RECT  2.16 249.345 30.24 249.615 ;
     RECT  2.16 249.885 30.24 250.155 ;
     RECT  2.16 250.425 30.24 250.695 ;
     RECT  2.16 250.965 30.24 251.235 ;
     RECT  2.16 251.505 30.24 251.775 ;
     RECT  2.16 252.045 30.24 252.315 ;
     RECT  2.16 252.585 30.24 252.855 ;
     RECT  2.16 253.125 30.24 253.395 ;
     RECT  2.16 253.665 30.24 253.935 ;
     RECT  2.16 254.205 30.24 254.475 ;
     RECT  2.16 254.745 30.24 255.015 ;
     RECT  2.16 255.285 30.24 255.555 ;
     RECT  2.16 255.825 30.24 256.095 ;
     RECT  2.16 256.365 30.24 256.635 ;
     RECT  2.16 256.905 30.24 257.175 ;
     RECT  2.16 257.445 30.24 257.715 ;
     RECT  2.16 257.985 30.24 258.255 ;
     RECT  2.16 258.525 30.24 258.795 ;
     RECT  2.16 259.065 30.24 259.335 ;
     RECT  2.16 259.605 30.24 259.875 ;
     RECT  2.16 260.145 30.24 260.415 ;
     RECT  2.16 260.685 30.24 260.955 ;
     RECT  2.16 261.225 30.24 261.495 ;
     RECT  2.16 261.765 30.24 262.035 ;
     RECT  2.16 262.305 30.24 262.575 ;
     RECT  2.16 262.845 30.24 263.115 ;
     RECT  2.16 263.385 30.24 263.655 ;
     RECT  2.16 263.925 30.24 264.195 ;
     RECT  2.16 264.465 30.24 264.735 ;
     RECT  2.16 265.005 30.24 265.275 ;
     RECT  2.16 265.545 30.24 265.815 ;
     RECT  2.16 266.085 30.24 266.355 ;
     RECT  2.16 266.625 30.24 266.895 ;
     RECT  2.16 267.165 30.24 267.435 ;
     RECT  2.16 267.705 30.24 267.975 ;
     RECT  2.16 268.245 30.24 268.515 ;
     RECT  2.16 268.785 30.24 269.055 ;
     RECT  2.16 269.325 30.24 269.595 ;
     RECT  2.16 269.865 30.24 270.135 ;
     RECT  2.16 270.405 30.24 270.675 ;
     RECT  2.16 270.945 30.24 271.215 ;
     RECT  2.16 271.485 30.24 271.755 ;
     RECT  2.16 272.025 30.24 272.295 ;
     RECT  2.16 272.565 30.24 272.835 ;
     RECT  2.16 273.105 30.24 273.375 ;
     RECT  2.16 273.645 30.24 273.915 ;
     RECT  2.16 274.185 30.24 274.455 ;
     RECT  2.16 274.725 30.24 274.995 ;
     RECT  2.16 275.265 30.24 275.535 ;
     RECT  2.16 275.805 30.24 276.075 ;
     RECT  2.16 276.345 30.24 276.615 ;
     RECT  2.16 276.885 30.24 277.155 ;
     RECT  2.16 277.425 30.24 277.695 ;
     RECT  2.16 277.965 30.24 278.235 ;
     RECT  2.16 278.505 30.24 278.775 ;
     RECT  2.16 279.045 30.24 279.315 ;
     RECT  2.16 279.585 30.24 279.855 ;
     RECT  2.16 280.125 30.24 280.395 ;
     RECT  2.16 280.665 30.24 280.935 ;
     RECT  2.16 281.205 30.24 281.475 ;
     RECT  2.16 281.745 30.24 282.015 ;
     RECT  2.16 282.285 30.24 282.555 ;
     RECT  2.16 282.825 30.24 283.095 ;
     RECT  2.16 283.365 30.24 283.635 ;
     RECT  2.16 283.905 30.24 284.175 ;
     RECT  2.16 284.445 30.24 284.715 ;
     RECT  2.16 284.985 30.24 285.255 ;
     RECT  2.16 285.525 30.24 285.795 ;
     RECT  2.16 286.065 30.24 286.335 ;
     RECT  2.16 286.605 30.24 286.875 ;
     RECT  2.16 287.145 30.24 287.415 ;
     RECT  2.16 287.685 30.24 287.955 ;
     RECT  2.16 288.225 30.24 288.495 ;
     RECT  2.16 288.765 30.24 289.035 ;
     RECT  2.16 289.305 30.24 289.575 ;
     RECT  2.16 289.845 30.24 290.115 ;
     RECT  2.16 290.385 30.24 290.655 ;
     RECT  2.16 290.925 30.24 291.195 ;
     RECT  2.16 291.465 30.24 291.735 ;
     RECT  2.16 292.005 30.24 292.275 ;
     RECT  2.16 292.545 30.24 292.815 ;
     RECT  2.16 293.085 30.24 293.355 ;
     RECT  2.16 293.625 30.24 293.895 ;
     RECT  2.16 294.165 30.24 294.435 ;
     RECT  2.16 294.705 30.24 294.975 ;
     RECT  2.16 295.245 30.24 295.515 ;
     RECT  2.16 295.785 30.24 296.055 ;
     RECT  2.16 296.325 30.24 296.595 ;
     RECT  2.16 296.865 30.24 297.135 ;
     RECT  2.16 297.405 30.24 297.675 ;
     RECT  2.16 297.945 30.24 298.08 ;
    LAYER RVTP ;
     RECT  2.16 2.295 30.24 2.565 ;
     RECT  2.16 2.835 30.24 3.105 ;
     RECT  2.16 3.375 30.24 3.645 ;
     RECT  2.16 3.915 30.24 4.185 ;
     RECT  2.16 4.455 30.24 4.725 ;
     RECT  2.16 4.995 30.24 5.265 ;
     RECT  2.16 5.535 30.24 5.805 ;
     RECT  2.16 6.075 30.24 6.345 ;
     RECT  2.16 6.615 30.24 6.885 ;
     RECT  2.16 7.155 30.24 7.425 ;
     RECT  2.16 7.695 30.24 7.965 ;
     RECT  2.16 8.235 30.24 8.505 ;
     RECT  2.16 8.775 30.24 9.045 ;
     RECT  2.16 9.315 30.24 9.585 ;
     RECT  2.16 9.855 30.24 10.125 ;
     RECT  2.16 10.395 30.24 10.665 ;
     RECT  2.16 10.935 30.24 11.205 ;
     RECT  2.16 11.475 30.24 11.745 ;
     RECT  2.16 12.015 30.24 12.285 ;
     RECT  2.16 12.555 30.24 12.825 ;
     RECT  2.16 13.095 30.24 13.365 ;
     RECT  2.16 13.635 30.24 13.905 ;
     RECT  2.16 14.175 30.24 14.445 ;
     RECT  2.16 14.715 30.24 14.985 ;
     RECT  2.16 15.255 30.24 15.525 ;
     RECT  2.16 15.795 30.24 16.065 ;
     RECT  2.16 16.335 30.24 16.605 ;
     RECT  2.16 16.875 30.24 17.145 ;
     RECT  2.16 17.415 30.24 17.685 ;
     RECT  2.16 17.955 30.24 18.225 ;
     RECT  2.16 18.495 30.24 18.765 ;
     RECT  2.16 19.035 30.24 19.305 ;
     RECT  2.16 19.575 30.24 19.845 ;
     RECT  2.16 20.115 30.24 20.385 ;
     RECT  2.16 20.655 30.24 20.925 ;
     RECT  2.16 21.195 30.24 21.465 ;
     RECT  2.16 21.735 30.24 22.005 ;
     RECT  2.16 22.275 30.24 22.545 ;
     RECT  2.16 22.815 30.24 23.085 ;
     RECT  2.16 23.355 30.24 23.625 ;
     RECT  2.16 23.895 30.24 24.165 ;
     RECT  2.16 24.435 30.24 24.705 ;
     RECT  2.16 24.975 30.24 25.245 ;
     RECT  2.16 25.515 30.24 25.785 ;
     RECT  2.16 26.055 30.24 26.325 ;
     RECT  2.16 26.595 30.24 26.865 ;
     RECT  2.16 27.135 30.24 27.405 ;
     RECT  2.16 27.675 30.24 27.945 ;
     RECT  2.16 28.215 30.24 28.485 ;
     RECT  2.16 28.755 30.24 29.025 ;
     RECT  2.16 29.295 30.24 29.565 ;
     RECT  2.16 29.835 30.24 30.105 ;
     RECT  2.16 30.375 30.24 30.645 ;
     RECT  2.16 30.915 30.24 31.185 ;
     RECT  2.16 31.455 30.24 31.725 ;
     RECT  2.16 31.995 30.24 32.265 ;
     RECT  2.16 32.535 30.24 32.805 ;
     RECT  2.16 33.075 30.24 33.345 ;
     RECT  2.16 33.615 30.24 33.885 ;
     RECT  2.16 34.155 30.24 34.425 ;
     RECT  2.16 34.695 30.24 34.965 ;
     RECT  2.16 35.235 30.24 35.505 ;
     RECT  2.16 35.775 30.24 36.045 ;
     RECT  2.16 36.315 30.24 36.585 ;
     RECT  2.16 36.855 30.24 37.125 ;
     RECT  2.16 37.395 30.24 37.665 ;
     RECT  2.16 37.935 30.24 38.205 ;
     RECT  2.16 38.475 30.24 38.745 ;
     RECT  2.16 39.015 30.24 39.285 ;
     RECT  2.16 39.555 30.24 39.825 ;
     RECT  2.16 40.095 30.24 40.365 ;
     RECT  2.16 40.635 30.24 40.905 ;
     RECT  2.16 41.175 30.24 41.445 ;
     RECT  2.16 41.715 30.24 41.985 ;
     RECT  2.16 42.255 30.24 42.525 ;
     RECT  2.16 42.795 30.24 43.065 ;
     RECT  2.16 43.335 30.24 43.605 ;
     RECT  2.16 43.875 30.24 44.145 ;
     RECT  2.16 44.415 30.24 44.685 ;
     RECT  2.16 44.955 30.24 45.225 ;
     RECT  2.16 45.495 30.24 45.765 ;
     RECT  2.16 46.035 30.24 46.305 ;
     RECT  2.16 46.575 30.24 46.845 ;
     RECT  2.16 47.115 30.24 47.385 ;
     RECT  2.16 47.655 30.24 47.925 ;
     RECT  2.16 48.195 30.24 48.465 ;
     RECT  2.16 48.735 30.24 49.005 ;
     RECT  2.16 49.275 30.24 49.545 ;
     RECT  2.16 49.815 30.24 50.085 ;
     RECT  2.16 50.355 30.24 50.625 ;
     RECT  2.16 50.895 30.24 51.165 ;
     RECT  2.16 51.435 30.24 51.705 ;
     RECT  2.16 51.975 30.24 52.245 ;
     RECT  2.16 52.515 30.24 52.785 ;
     RECT  2.16 53.055 30.24 53.325 ;
     RECT  2.16 53.595 30.24 53.865 ;
     RECT  2.16 54.135 30.24 54.405 ;
     RECT  2.16 54.675 30.24 54.945 ;
     RECT  2.16 55.215 30.24 55.485 ;
     RECT  2.16 55.755 30.24 56.025 ;
     RECT  2.16 56.295 30.24 56.565 ;
     RECT  2.16 56.835 30.24 57.105 ;
     RECT  2.16 57.375 30.24 57.645 ;
     RECT  2.16 57.915 30.24 58.185 ;
     RECT  2.16 58.455 30.24 58.725 ;
     RECT  2.16 58.995 30.24 59.265 ;
     RECT  2.16 59.535 30.24 59.805 ;
     RECT  2.16 60.075 30.24 60.345 ;
     RECT  2.16 60.615 30.24 60.885 ;
     RECT  2.16 61.155 30.24 61.425 ;
     RECT  2.16 61.695 30.24 61.965 ;
     RECT  2.16 62.235 30.24 62.505 ;
     RECT  2.16 62.775 30.24 63.045 ;
     RECT  2.16 63.315 30.24 63.585 ;
     RECT  2.16 63.855 30.24 64.125 ;
     RECT  2.16 64.395 30.24 64.665 ;
     RECT  2.16 64.935 30.24 65.205 ;
     RECT  2.16 65.475 30.24 65.745 ;
     RECT  2.16 66.015 30.24 66.285 ;
     RECT  2.16 66.555 30.24 66.825 ;
     RECT  2.16 67.095 30.24 67.365 ;
     RECT  2.16 67.635 30.24 67.905 ;
     RECT  2.16 68.175 30.24 68.445 ;
     RECT  2.16 68.715 30.24 68.985 ;
     RECT  2.16 69.255 30.24 69.525 ;
     RECT  2.16 69.795 30.24 70.065 ;
     RECT  2.16 70.335 30.24 70.605 ;
     RECT  2.16 70.875 30.24 71.145 ;
     RECT  2.16 71.415 30.24 71.685 ;
     RECT  2.16 71.955 30.24 72.225 ;
     RECT  2.16 72.495 30.24 72.765 ;
     RECT  2.16 73.035 30.24 73.305 ;
     RECT  2.16 73.575 30.24 73.845 ;
     RECT  2.16 74.115 30.24 74.385 ;
     RECT  2.16 74.655 30.24 74.925 ;
     RECT  2.16 75.195 30.24 75.465 ;
     RECT  2.16 75.735 30.24 76.005 ;
     RECT  2.16 76.275 30.24 76.545 ;
     RECT  2.16 76.815 30.24 77.085 ;
     RECT  2.16 77.355 30.24 77.625 ;
     RECT  2.16 77.895 30.24 78.165 ;
     RECT  2.16 78.435 30.24 78.705 ;
     RECT  2.16 78.975 30.24 79.245 ;
     RECT  2.16 79.515 30.24 79.785 ;
     RECT  2.16 80.055 30.24 80.325 ;
     RECT  2.16 80.595 30.24 80.865 ;
     RECT  2.16 81.135 30.24 81.405 ;
     RECT  2.16 81.675 30.24 81.945 ;
     RECT  2.16 82.215 30.24 82.485 ;
     RECT  2.16 82.755 30.24 83.025 ;
     RECT  2.16 83.295 30.24 83.565 ;
     RECT  2.16 83.835 30.24 84.105 ;
     RECT  2.16 84.375 30.24 84.645 ;
     RECT  2.16 84.915 30.24 85.185 ;
     RECT  2.16 85.455 30.24 85.725 ;
     RECT  2.16 85.995 30.24 86.265 ;
     RECT  2.16 86.535 30.24 86.805 ;
     RECT  2.16 87.075 30.24 87.345 ;
     RECT  2.16 87.615 30.24 87.885 ;
     RECT  2.16 88.155 30.24 88.425 ;
     RECT  2.16 88.695 30.24 88.965 ;
     RECT  2.16 89.235 30.24 89.505 ;
     RECT  2.16 89.775 30.24 90.045 ;
     RECT  2.16 90.315 30.24 90.585 ;
     RECT  2.16 90.855 30.24 91.125 ;
     RECT  2.16 91.395 30.24 91.665 ;
     RECT  2.16 91.935 30.24 92.205 ;
     RECT  2.16 92.475 30.24 92.745 ;
     RECT  2.16 93.015 30.24 93.285 ;
     RECT  2.16 93.555 30.24 93.825 ;
     RECT  2.16 94.095 30.24 94.365 ;
     RECT  2.16 94.635 30.24 94.905 ;
     RECT  2.16 95.175 30.24 95.445 ;
     RECT  2.16 95.715 30.24 95.985 ;
     RECT  2.16 96.255 30.24 96.525 ;
     RECT  2.16 96.795 30.24 97.065 ;
     RECT  2.16 97.335 30.24 97.605 ;
     RECT  2.16 97.875 30.24 98.145 ;
     RECT  2.16 98.415 30.24 98.685 ;
     RECT  2.16 98.955 30.24 99.225 ;
     RECT  2.16 99.495 30.24 99.765 ;
     RECT  2.16 100.035 30.24 100.305 ;
     RECT  2.16 100.575 30.24 100.845 ;
     RECT  2.16 101.115 30.24 101.385 ;
     RECT  2.16 101.655 30.24 101.925 ;
     RECT  2.16 102.195 30.24 102.465 ;
     RECT  2.16 102.735 30.24 103.005 ;
     RECT  2.16 103.275 30.24 103.545 ;
     RECT  2.16 103.815 30.24 104.085 ;
     RECT  2.16 104.355 30.24 104.625 ;
     RECT  2.16 104.895 30.24 105.165 ;
     RECT  2.16 105.435 30.24 105.705 ;
     RECT  2.16 105.975 30.24 106.245 ;
     RECT  2.16 106.515 30.24 106.785 ;
     RECT  2.16 107.055 30.24 107.325 ;
     RECT  2.16 107.595 30.24 107.865 ;
     RECT  2.16 108.135 30.24 108.405 ;
     RECT  2.16 108.675 30.24 108.945 ;
     RECT  2.16 109.215 30.24 109.485 ;
     RECT  2.16 109.755 30.24 110.025 ;
     RECT  2.16 110.295 30.24 110.565 ;
     RECT  2.16 110.835 30.24 111.105 ;
     RECT  2.16 111.375 30.24 111.645 ;
     RECT  2.16 111.915 30.24 112.185 ;
     RECT  2.16 112.455 30.24 112.725 ;
     RECT  2.16 112.995 30.24 113.265 ;
     RECT  2.16 113.535 30.24 113.805 ;
     RECT  2.16 114.075 30.24 114.345 ;
     RECT  2.16 114.615 30.24 114.885 ;
     RECT  2.16 115.155 30.24 115.425 ;
     RECT  2.16 115.695 30.24 115.965 ;
     RECT  2.16 116.235 30.24 116.505 ;
     RECT  2.16 116.775 30.24 117.045 ;
     RECT  2.16 117.315 30.24 117.585 ;
     RECT  2.16 117.855 30.24 118.125 ;
     RECT  2.16 118.395 30.24 118.665 ;
     RECT  2.16 118.935 30.24 119.205 ;
     RECT  2.16 119.475 30.24 119.745 ;
     RECT  2.16 120.015 30.24 120.285 ;
     RECT  2.16 120.555 30.24 120.825 ;
     RECT  2.16 121.095 30.24 121.365 ;
     RECT  2.16 121.635 30.24 121.905 ;
     RECT  2.16 122.175 30.24 122.445 ;
     RECT  2.16 122.715 30.24 122.985 ;
     RECT  2.16 123.255 30.24 123.525 ;
     RECT  2.16 123.795 30.24 124.065 ;
     RECT  2.16 124.335 30.24 124.605 ;
     RECT  2.16 124.875 30.24 125.145 ;
     RECT  2.16 125.415 30.24 125.685 ;
     RECT  2.16 125.955 30.24 126.225 ;
     RECT  2.16 126.495 30.24 126.765 ;
     RECT  2.16 127.035 30.24 127.305 ;
     RECT  2.16 127.575 30.24 127.845 ;
     RECT  2.16 128.115 30.24 128.385 ;
     RECT  2.16 128.655 30.24 128.925 ;
     RECT  2.16 129.195 30.24 129.465 ;
     RECT  2.16 129.735 30.24 130.005 ;
     RECT  2.16 130.275 30.24 130.545 ;
     RECT  2.16 130.815 30.24 131.085 ;
     RECT  2.16 131.355 30.24 131.625 ;
     RECT  2.16 131.895 30.24 132.165 ;
     RECT  2.16 132.435 30.24 132.705 ;
     RECT  2.16 132.975 30.24 133.245 ;
     RECT  2.16 133.515 30.24 133.785 ;
     RECT  2.16 134.055 30.24 134.325 ;
     RECT  2.16 134.595 30.24 134.865 ;
     RECT  2.16 135.135 30.24 135.405 ;
     RECT  2.16 135.675 30.24 135.945 ;
     RECT  2.16 136.215 30.24 136.485 ;
     RECT  2.16 136.755 30.24 137.025 ;
     RECT  2.16 137.295 30.24 137.565 ;
     RECT  2.16 137.835 30.24 138.105 ;
     RECT  2.16 138.375 30.24 138.645 ;
     RECT  2.16 138.915 30.24 139.185 ;
     RECT  2.16 139.455 30.24 139.725 ;
     RECT  2.16 139.995 30.24 140.265 ;
     RECT  2.16 140.535 30.24 140.805 ;
     RECT  2.16 141.075 30.24 141.345 ;
     RECT  2.16 141.615 30.24 141.885 ;
     RECT  2.16 142.155 30.24 142.425 ;
     RECT  2.16 142.695 30.24 142.965 ;
     RECT  2.16 143.235 30.24 143.505 ;
     RECT  2.16 143.775 30.24 144.045 ;
     RECT  2.16 144.315 30.24 144.585 ;
     RECT  2.16 144.855 30.24 145.125 ;
     RECT  2.16 145.395 30.24 145.665 ;
     RECT  2.16 145.935 30.24 146.205 ;
     RECT  2.16 146.475 30.24 146.745 ;
     RECT  2.16 147.015 30.24 147.285 ;
     RECT  2.16 147.555 30.24 147.825 ;
     RECT  2.16 148.095 30.24 148.365 ;
     RECT  2.16 148.635 30.24 148.905 ;
     RECT  2.16 149.175 30.24 149.445 ;
     RECT  2.16 149.715 30.24 149.985 ;
     RECT  2.16 150.255 30.24 150.525 ;
     RECT  2.16 150.795 30.24 151.065 ;
     RECT  2.16 151.335 30.24 151.605 ;
     RECT  2.16 151.875 30.24 152.145 ;
     RECT  2.16 152.415 30.24 152.685 ;
     RECT  2.16 152.955 30.24 153.225 ;
     RECT  2.16 153.495 30.24 153.765 ;
     RECT  2.16 154.035 30.24 154.305 ;
     RECT  2.16 154.575 30.24 154.845 ;
     RECT  2.16 155.115 30.24 155.385 ;
     RECT  2.16 155.655 30.24 155.925 ;
     RECT  2.16 156.195 30.24 156.465 ;
     RECT  2.16 156.735 30.24 157.005 ;
     RECT  2.16 157.275 30.24 157.545 ;
     RECT  2.16 157.815 30.24 158.085 ;
     RECT  2.16 158.355 30.24 158.625 ;
     RECT  2.16 158.895 30.24 159.165 ;
     RECT  2.16 159.435 30.24 159.705 ;
     RECT  2.16 159.975 30.24 160.245 ;
     RECT  2.16 160.515 30.24 160.785 ;
     RECT  2.16 161.055 30.24 161.325 ;
     RECT  2.16 161.595 30.24 161.865 ;
     RECT  2.16 162.135 30.24 162.405 ;
     RECT  2.16 162.675 30.24 162.945 ;
     RECT  2.16 163.215 30.24 163.485 ;
     RECT  2.16 163.755 30.24 164.025 ;
     RECT  2.16 164.295 30.24 164.565 ;
     RECT  2.16 164.835 30.24 165.105 ;
     RECT  2.16 165.375 30.24 165.645 ;
     RECT  2.16 165.915 30.24 166.185 ;
     RECT  2.16 166.455 30.24 166.725 ;
     RECT  2.16 166.995 30.24 167.265 ;
     RECT  2.16 167.535 30.24 167.805 ;
     RECT  2.16 168.075 30.24 168.345 ;
     RECT  2.16 168.615 30.24 168.885 ;
     RECT  2.16 169.155 30.24 169.425 ;
     RECT  2.16 169.695 30.24 169.965 ;
     RECT  2.16 170.235 30.24 170.505 ;
     RECT  2.16 170.775 30.24 171.045 ;
     RECT  2.16 171.315 30.24 171.585 ;
     RECT  2.16 171.855 30.24 172.125 ;
     RECT  2.16 172.395 30.24 172.665 ;
     RECT  2.16 172.935 30.24 173.205 ;
     RECT  2.16 173.475 30.24 173.745 ;
     RECT  2.16 174.015 30.24 174.285 ;
     RECT  2.16 174.555 30.24 174.825 ;
     RECT  2.16 175.095 30.24 175.365 ;
     RECT  2.16 175.635 30.24 175.905 ;
     RECT  2.16 176.175 30.24 176.445 ;
     RECT  2.16 176.715 30.24 176.985 ;
     RECT  2.16 177.255 30.24 177.525 ;
     RECT  2.16 177.795 30.24 178.065 ;
     RECT  2.16 178.335 30.24 178.605 ;
     RECT  2.16 178.875 30.24 179.145 ;
     RECT  2.16 179.415 30.24 179.685 ;
     RECT  2.16 179.955 30.24 180.225 ;
     RECT  2.16 180.495 30.24 180.765 ;
     RECT  2.16 181.035 30.24 181.305 ;
     RECT  2.16 181.575 30.24 181.845 ;
     RECT  2.16 182.115 30.24 182.385 ;
     RECT  2.16 182.655 30.24 182.925 ;
     RECT  2.16 183.195 30.24 183.465 ;
     RECT  2.16 183.735 30.24 184.005 ;
     RECT  2.16 184.275 30.24 184.545 ;
     RECT  2.16 184.815 30.24 185.085 ;
     RECT  2.16 185.355 30.24 185.625 ;
     RECT  2.16 185.895 30.24 186.165 ;
     RECT  2.16 186.435 30.24 186.705 ;
     RECT  2.16 186.975 30.24 187.245 ;
     RECT  2.16 187.515 30.24 187.785 ;
     RECT  2.16 188.055 30.24 188.325 ;
     RECT  2.16 188.595 30.24 188.865 ;
     RECT  2.16 189.135 30.24 189.405 ;
     RECT  2.16 189.675 30.24 189.945 ;
     RECT  2.16 190.215 30.24 190.485 ;
     RECT  2.16 190.755 30.24 191.025 ;
     RECT  2.16 191.295 30.24 191.565 ;
     RECT  2.16 191.835 30.24 192.105 ;
     RECT  2.16 192.375 30.24 192.645 ;
     RECT  2.16 192.915 30.24 193.185 ;
     RECT  2.16 193.455 30.24 193.725 ;
     RECT  2.16 193.995 30.24 194.265 ;
     RECT  2.16 194.535 30.24 194.805 ;
     RECT  2.16 195.075 30.24 195.345 ;
     RECT  2.16 195.615 30.24 195.885 ;
     RECT  2.16 196.155 30.24 196.425 ;
     RECT  2.16 196.695 30.24 196.965 ;
     RECT  2.16 197.235 30.24 197.505 ;
     RECT  2.16 197.775 30.24 198.045 ;
     RECT  2.16 198.315 30.24 198.585 ;
     RECT  2.16 198.855 30.24 199.125 ;
     RECT  2.16 199.395 30.24 199.665 ;
     RECT  2.16 199.935 30.24 200.205 ;
     RECT  2.16 200.475 30.24 200.745 ;
     RECT  2.16 201.015 30.24 201.285 ;
     RECT  2.16 201.555 30.24 201.825 ;
     RECT  2.16 202.095 30.24 202.365 ;
     RECT  2.16 202.635 30.24 202.905 ;
     RECT  2.16 203.175 30.24 203.445 ;
     RECT  2.16 203.715 30.24 203.985 ;
     RECT  2.16 204.255 30.24 204.525 ;
     RECT  2.16 204.795 30.24 205.065 ;
     RECT  2.16 205.335 30.24 205.605 ;
     RECT  2.16 205.875 30.24 206.145 ;
     RECT  2.16 206.415 30.24 206.685 ;
     RECT  2.16 206.955 30.24 207.225 ;
     RECT  2.16 207.495 30.24 207.765 ;
     RECT  2.16 208.035 30.24 208.305 ;
     RECT  2.16 208.575 30.24 208.845 ;
     RECT  2.16 209.115 30.24 209.385 ;
     RECT  2.16 209.655 30.24 209.925 ;
     RECT  2.16 210.195 30.24 210.465 ;
     RECT  2.16 210.735 30.24 211.005 ;
     RECT  2.16 211.275 30.24 211.545 ;
     RECT  2.16 211.815 30.24 212.085 ;
     RECT  2.16 212.355 30.24 212.625 ;
     RECT  2.16 212.895 30.24 213.165 ;
     RECT  2.16 213.435 30.24 213.705 ;
     RECT  2.16 213.975 30.24 214.245 ;
     RECT  2.16 214.515 30.24 214.785 ;
     RECT  2.16 215.055 30.24 215.325 ;
     RECT  2.16 215.595 30.24 215.865 ;
     RECT  2.16 216.135 30.24 216.405 ;
     RECT  2.16 216.675 30.24 216.945 ;
     RECT  2.16 217.215 30.24 217.485 ;
     RECT  2.16 217.755 30.24 218.025 ;
     RECT  2.16 218.295 30.24 218.565 ;
     RECT  2.16 218.835 30.24 219.105 ;
     RECT  2.16 219.375 30.24 219.645 ;
     RECT  2.16 219.915 30.24 220.185 ;
     RECT  2.16 220.455 30.24 220.725 ;
     RECT  2.16 220.995 30.24 221.265 ;
     RECT  2.16 221.535 30.24 221.805 ;
     RECT  2.16 222.075 30.24 222.345 ;
     RECT  2.16 222.615 30.24 222.885 ;
     RECT  2.16 223.155 30.24 223.425 ;
     RECT  2.16 223.695 30.24 223.965 ;
     RECT  2.16 224.235 30.24 224.505 ;
     RECT  2.16 224.775 30.24 225.045 ;
     RECT  2.16 225.315 30.24 225.585 ;
     RECT  2.16 225.855 30.24 226.125 ;
     RECT  2.16 226.395 30.24 226.665 ;
     RECT  2.16 226.935 30.24 227.205 ;
     RECT  2.16 227.475 30.24 227.745 ;
     RECT  2.16 228.015 30.24 228.285 ;
     RECT  2.16 228.555 30.24 228.825 ;
     RECT  2.16 229.095 30.24 229.365 ;
     RECT  2.16 229.635 30.24 229.905 ;
     RECT  2.16 230.175 30.24 230.445 ;
     RECT  2.16 230.715 30.24 230.985 ;
     RECT  2.16 231.255 30.24 231.525 ;
     RECT  2.16 231.795 30.24 232.065 ;
     RECT  2.16 232.335 30.24 232.605 ;
     RECT  2.16 232.875 30.24 233.145 ;
     RECT  2.16 233.415 30.24 233.685 ;
     RECT  2.16 233.955 30.24 234.225 ;
     RECT  2.16 234.495 30.24 234.765 ;
     RECT  2.16 235.035 30.24 235.305 ;
     RECT  2.16 235.575 30.24 235.845 ;
     RECT  2.16 236.115 30.24 236.385 ;
     RECT  2.16 236.655 30.24 236.925 ;
     RECT  2.16 237.195 30.24 237.465 ;
     RECT  2.16 237.735 30.24 238.005 ;
     RECT  2.16 238.275 30.24 238.545 ;
     RECT  2.16 238.815 30.24 239.085 ;
     RECT  2.16 239.355 30.24 239.625 ;
     RECT  2.16 239.895 30.24 240.165 ;
     RECT  2.16 240.435 30.24 240.705 ;
     RECT  2.16 240.975 30.24 241.245 ;
     RECT  2.16 241.515 30.24 241.785 ;
     RECT  2.16 242.055 30.24 242.325 ;
     RECT  2.16 242.595 30.24 242.865 ;
     RECT  2.16 243.135 30.24 243.405 ;
     RECT  2.16 243.675 30.24 243.945 ;
     RECT  2.16 244.215 30.24 244.485 ;
     RECT  2.16 244.755 30.24 245.025 ;
     RECT  2.16 245.295 30.24 245.565 ;
     RECT  2.16 245.835 30.24 246.105 ;
     RECT  2.16 246.375 30.24 246.645 ;
     RECT  2.16 246.915 30.24 247.185 ;
     RECT  2.16 247.455 30.24 247.725 ;
     RECT  2.16 247.995 30.24 248.265 ;
     RECT  2.16 248.535 30.24 248.805 ;
     RECT  2.16 249.075 30.24 249.345 ;
     RECT  2.16 249.615 30.24 249.885 ;
     RECT  2.16 250.155 30.24 250.425 ;
     RECT  2.16 250.695 30.24 250.965 ;
     RECT  2.16 251.235 30.24 251.505 ;
     RECT  2.16 251.775 30.24 252.045 ;
     RECT  2.16 252.315 30.24 252.585 ;
     RECT  2.16 252.855 30.24 253.125 ;
     RECT  2.16 253.395 30.24 253.665 ;
     RECT  2.16 253.935 30.24 254.205 ;
     RECT  2.16 254.475 30.24 254.745 ;
     RECT  2.16 255.015 30.24 255.285 ;
     RECT  2.16 255.555 30.24 255.825 ;
     RECT  2.16 256.095 30.24 256.365 ;
     RECT  2.16 256.635 30.24 256.905 ;
     RECT  2.16 257.175 30.24 257.445 ;
     RECT  2.16 257.715 30.24 257.985 ;
     RECT  2.16 258.255 30.24 258.525 ;
     RECT  2.16 258.795 30.24 259.065 ;
     RECT  2.16 259.335 30.24 259.605 ;
     RECT  2.16 259.875 30.24 260.145 ;
     RECT  2.16 260.415 30.24 260.685 ;
     RECT  2.16 260.955 30.24 261.225 ;
     RECT  2.16 261.495 30.24 261.765 ;
     RECT  2.16 262.035 30.24 262.305 ;
     RECT  2.16 262.575 30.24 262.845 ;
     RECT  2.16 263.115 30.24 263.385 ;
     RECT  2.16 263.655 30.24 263.925 ;
     RECT  2.16 264.195 30.24 264.465 ;
     RECT  2.16 264.735 30.24 265.005 ;
     RECT  2.16 265.275 30.24 265.545 ;
     RECT  2.16 265.815 30.24 266.085 ;
     RECT  2.16 266.355 30.24 266.625 ;
     RECT  2.16 266.895 30.24 267.165 ;
     RECT  2.16 267.435 30.24 267.705 ;
     RECT  2.16 267.975 30.24 268.245 ;
     RECT  2.16 268.515 30.24 268.785 ;
     RECT  2.16 269.055 30.24 269.325 ;
     RECT  2.16 269.595 30.24 269.865 ;
     RECT  2.16 270.135 30.24 270.405 ;
     RECT  2.16 270.675 30.24 270.945 ;
     RECT  2.16 271.215 30.24 271.485 ;
     RECT  2.16 271.755 30.24 272.025 ;
     RECT  2.16 272.295 30.24 272.565 ;
     RECT  2.16 272.835 30.24 273.105 ;
     RECT  2.16 273.375 30.24 273.645 ;
     RECT  2.16 273.915 30.24 274.185 ;
     RECT  2.16 274.455 30.24 274.725 ;
     RECT  2.16 274.995 30.24 275.265 ;
     RECT  2.16 275.535 30.24 275.805 ;
     RECT  2.16 276.075 30.24 276.345 ;
     RECT  2.16 276.615 30.24 276.885 ;
     RECT  2.16 277.155 30.24 277.425 ;
     RECT  2.16 277.695 30.24 277.965 ;
     RECT  2.16 278.235 30.24 278.505 ;
     RECT  2.16 278.775 30.24 279.045 ;
     RECT  2.16 279.315 30.24 279.585 ;
     RECT  2.16 279.855 30.24 280.125 ;
     RECT  2.16 280.395 30.24 280.665 ;
     RECT  2.16 280.935 30.24 281.205 ;
     RECT  2.16 281.475 30.24 281.745 ;
     RECT  2.16 282.015 30.24 282.285 ;
     RECT  2.16 282.555 30.24 282.825 ;
     RECT  2.16 283.095 30.24 283.365 ;
     RECT  2.16 283.635 30.24 283.905 ;
     RECT  2.16 284.175 30.24 284.445 ;
     RECT  2.16 284.715 30.24 284.985 ;
     RECT  2.16 285.255 30.24 285.525 ;
     RECT  2.16 285.795 30.24 286.065 ;
     RECT  2.16 286.335 30.24 286.605 ;
     RECT  2.16 286.875 30.24 287.145 ;
     RECT  2.16 287.415 30.24 287.685 ;
     RECT  2.16 287.955 30.24 288.225 ;
     RECT  2.16 288.495 30.24 288.765 ;
     RECT  2.16 289.035 30.24 289.305 ;
     RECT  2.16 289.575 30.24 289.845 ;
     RECT  2.16 290.115 30.24 290.385 ;
     RECT  2.16 290.655 30.24 290.925 ;
     RECT  2.16 291.195 30.24 291.465 ;
     RECT  2.16 291.735 30.24 292.005 ;
     RECT  2.16 292.275 30.24 292.545 ;
     RECT  2.16 292.815 30.24 293.085 ;
     RECT  2.16 293.355 30.24 293.625 ;
     RECT  2.16 293.895 30.24 294.165 ;
     RECT  2.16 294.435 30.24 294.705 ;
     RECT  2.16 294.975 30.24 295.245 ;
     RECT  2.16 295.515 30.24 295.785 ;
     RECT  2.16 296.055 30.24 296.325 ;
     RECT  2.16 296.595 30.24 296.865 ;
     RECT  2.16 297.135 30.24 297.405 ;
     RECT  2.16 297.675 30.24 297.945 ;
    LAYER M1 ;
     RECT  2.16 2.151 30.24 298.089 ;
    LAYER M2 ;
     RECT  1.975 189.612 2.011 189.63 ;
     RECT  1.975 293.166 2.011 293.184 ;
     RECT  1.903 4.77 2.047 4.788 ;
     RECT  1.903 155.466 2.083 155.484 ;
     RECT  2.083 7.236 2.155 7.254 ;
     RECT  2.083 155.286 2.155 155.484 ;
     RECT  2.155 2.538 2.16 2.556 ;
     RECT  2.047 4.77 2.16 5.094 ;
     RECT  2.011 6.426 2.16 6.444 ;
     RECT  2.155 7.236 2.16 7.344 ;
     RECT  2.155 8.316 2.16 8.334 ;
     RECT  2.119 73.854 2.16 73.872 ;
     RECT  2.047 78.516 2.16 78.534 ;
     RECT  2.047 84.726 2.16 84.744 ;
     RECT  1.939 104.526 2.16 104.544 ;
     RECT  2.011 119.286 2.16 119.304 ;
     RECT  2.083 136.026 2.16 136.044 ;
     RECT  2.155 149.526 2.16 149.544 ;
     RECT  2.155 155.088 2.16 155.484 ;
     RECT  2.011 189.342 2.16 189.63 ;
     RECT  2.047 198.936 2.16 198.954 ;
     RECT  2.119 204.768 2.16 204.786 ;
     RECT  2.083 265.554 2.16 265.572 ;
     RECT  2.155 291.276 2.16 291.294 ;
     RECT  2.011 293.166 2.16 293.274 ;
     RECT  2.16 2.151 2.263 298.089 ;
     RECT  2.263 2.151 2.515 298.134 ;
     RECT  2.515 2.151 2.579 298.17 ;
     RECT  2.299 0.036 2.695 0.054 ;
     RECT  2.695 0.036 2.831 0.126 ;
     RECT  2.579 2.151 2.911 298.089 ;
     RECT  2.911 1.728 3.019 298.089 ;
     RECT  2.831 0.036 3.119 0.054 ;
     RECT  3.019 1.152 3.191 298.089 ;
     RECT  3.559 299.232 3.631 299.25 ;
     RECT  3.631 299.232 3.731 299.358 ;
     RECT  3.191 1.152 3.947 1.17 ;
     RECT  4.315 0.036 4.711 0.054 ;
     RECT  3.731 299.268 4.711 299.286 ;
     RECT  4.711 299.268 4.811 299.439 ;
     RECT  4.783 1.152 4.927 1.17 ;
     RECT  4.927 1.152 5.063 1.206 ;
     RECT  4.711 0.036 5.135 0.126 ;
     RECT  3.191 2.151 5.251 298.089 ;
     RECT  4.811 299.268 5.387 299.286 ;
     RECT  5.251 2.106 5.539 298.089 ;
     RECT  6.043 299.34 6.115 299.358 ;
     RECT  5.539 2.034 6.151 298.089 ;
     RECT  6.151 1.962 6.431 298.089 ;
     RECT  6.115 299.268 6.539 299.358 ;
     RECT  6.431 2.106 6.719 298.089 ;
     RECT  6.655 0.036 6.755 0.054 ;
     RECT  5.063 1.152 6.755 1.17 ;
     RECT  6.539 299.34 6.755 299.358 ;
     RECT  6.719 2.151 6.871 298.089 ;
     RECT  6.871 2.151 6.979 298.134 ;
     RECT  7.555 0.036 7.627 0.054 ;
     RECT  7.627 0.036 7.763 0.126 ;
     RECT  7.763 0.108 7.943 0.126 ;
     RECT  6.979 2.151 7.951 298.206 ;
     RECT  7.555 1.152 8.231 1.17 ;
     RECT  7.951 2.106 8.383 298.206 ;
     RECT  8.383 2.106 8.527 298.242 ;
     RECT  8.527 2.034 8.555 298.242 ;
     RECT  8.555 2.034 8.743 298.134 ;
     RECT  8.743 1.728 8.987 298.134 ;
     RECT  8.987 1.728 9.131 298.089 ;
     RECT  8.923 0.036 9.563 0.054 ;
     RECT  9.751 300.186 9.887 300.204 ;
     RECT  9.131 2.07 9.931 298.089 ;
     RECT  9.931 1.728 10.075 298.089 ;
     RECT  10.075 1.728 10.147 298.134 ;
     RECT  10.147 1.152 10.175 298.134 ;
     RECT  10.175 1.152 10.211 298.089 ;
     RECT  10.211 1.152 10.247 1.17 ;
     RECT  9.931 299.268 10.643 299.286 ;
     RECT  10.211 2.151 11.155 298.089 ;
     RECT  11.011 1.152 11.695 1.17 ;
     RECT  10.471 0.036 11.723 0.054 ;
     RECT  11.623 300.186 11.723 300.204 ;
     RECT  11.695 1.152 11.731 1.242 ;
     RECT  11.155 2.106 11.759 298.089 ;
     RECT  11.731 1.152 11.975 1.314 ;
     RECT  11.975 1.152 12.299 1.17 ;
     RECT  12.559 0.18 12.739 0.198 ;
     RECT  12.343 299.268 12.875 299.286 ;
     RECT  12.739 0.036 12.983 0.198 ;
     RECT  12.983 0.036 13.055 0.126 ;
     RECT  11.759 2.151 13.171 298.089 ;
     RECT  13.171 1.728 13.351 298.089 ;
     RECT  13.351 1.224 13.423 298.089 ;
     RECT  13.423 1.152 13.747 298.089 ;
     RECT  13.747 1.152 13.955 298.134 ;
     RECT  13.055 0.036 14.063 0.054 ;
     RECT  13.955 1.152 14.711 298.089 ;
     RECT  14.935 299.502 14.971 299.52 ;
     RECT  14.711 1.152 15.035 1.17 ;
     RECT  14.971 299.421 15.179 299.52 ;
     RECT  14.827 0.036 15.395 0.054 ;
     RECT  14.711 2.106 16.843 298.089 ;
     RECT  16.879 0.108 16.987 0.126 ;
     RECT  16.987 0.036 17.051 0.126 ;
     RECT  16.951 1.152 17.051 1.17 ;
     RECT  16.051 300.186 17.051 300.204 ;
     RECT  16.843 2.07 17.195 298.089 ;
     RECT  17.995 1.152 18.175 1.17 ;
     RECT  17.195 2.106 18.175 298.089 ;
     RECT  18.175 1.152 18.383 298.089 ;
     RECT  18.383 2.106 18.419 298.089 ;
     RECT  18.383 1.152 18.491 1.242 ;
     RECT  18.491 1.224 18.599 1.242 ;
     RECT  18.419 2.151 18.787 298.089 ;
     RECT  18.787 2.151 19.031 298.134 ;
     RECT  18.931 300.186 19.031 300.204 ;
     RECT  19.031 2.151 19.183 298.089 ;
     RECT  19.183 2.106 19.607 298.089 ;
     RECT  17.051 0.036 19.787 0.054 ;
     RECT  20.191 1.224 20.227 1.242 ;
     RECT  20.227 1.152 20.363 1.242 ;
     RECT  19.607 2.151 20.587 298.089 ;
     RECT  20.587 300.186 20.687 300.204 ;
     RECT  20.587 1.728 20.867 298.089 ;
     RECT  20.867 2.151 20.911 298.089 ;
     RECT  20.875 0.036 21.011 0.054 ;
     RECT  20.911 2.151 21.415 298.134 ;
     RECT  21.415 2.151 21.551 298.206 ;
     RECT  21.551 2.151 22.279 298.089 ;
     RECT  22.279 2.151 22.387 298.134 ;
     RECT  21.739 0.036 22.423 0.054 ;
     RECT  22.423 0.036 22.531 0.126 ;
     RECT  22.387 2.151 22.667 298.206 ;
     RECT  22.531 0.036 22.703 0.198 ;
     RECT  22.667 2.151 23.611 298.134 ;
     RECT  23.611 2.106 23.791 298.134 ;
     RECT  22.703 0.036 23.827 0.054 ;
     RECT  23.827 0.036 23.935 0.126 ;
     RECT  23.935 0.036 24.035 0.162 ;
     RECT  23.791 2.106 24.035 298.17 ;
     RECT  24.035 2.106 24.359 298.134 ;
     RECT  24.035 0.036 24.791 0.126 ;
     RECT  24.791 0.036 25.331 0.054 ;
     RECT  24.359 2.151 26.771 298.134 ;
     RECT  26.771 2.151 27.031 298.089 ;
     RECT  26.815 0.108 27.139 0.126 ;
     RECT  27.139 0.036 27.167 0.126 ;
     RECT  27.031 1.728 27.347 298.089 ;
     RECT  27.031 299.268 27.455 299.286 ;
     RECT  27.347 2.034 27.679 298.089 ;
     RECT  27.679 2.034 27.751 298.134 ;
     RECT  27.751 2.034 27.887 298.314 ;
     RECT  27.887 2.034 28.319 298.089 ;
     RECT  27.167 0.036 28.715 0.054 ;
     RECT  28.319 2.106 29.083 298.089 ;
     RECT  29.083 2.07 29.327 298.089 ;
     RECT  29.327 2.106 29.723 298.089 ;
     RECT  29.723 2.151 30.24 298.089 ;
     RECT  30.24 101.466 30.263 104.994 ;
     RECT  30.24 239.166 30.263 239.184 ;
     RECT  30.263 101.826 30.299 104.994 ;
     RECT  30.24 240.786 30.299 242.082 ;
     RECT  30.24 121.176 30.335 121.554 ;
     RECT  30.24 167.166 30.335 167.184 ;
     RECT  30.24 294.75 30.335 294.768 ;
     RECT  30.24 2.376 30.371 2.628 ;
     RECT  30.24 98.622 30.371 99.864 ;
     RECT  30.24 115.74 30.371 115.758 ;
     RECT  30.299 241.254 30.371 242.082 ;
     RECT  30.24 10.476 30.407 10.494 ;
     RECT  30.335 121.176 30.407 121.464 ;
     RECT  30.24 129.942 30.407 129.96 ;
     RECT  30.24 250.974 30.407 250.992 ;
     RECT  30.24 205.506 30.443 205.524 ;
     RECT  30.24 86.436 30.479 86.994 ;
     RECT  30.24 183.546 30.479 183.564 ;
     RECT  30.24 5.976 30.515 5.994 ;
     RECT  30.371 99.846 30.515 99.864 ;
     RECT  30.299 101.826 30.515 104.346 ;
     RECT  30.24 197.478 30.515 198.072 ;
     RECT  30.515 197.478 30.551 197.496 ;
     RECT  30.24 187.596 30.587 187.614 ;
     RECT  30.24 3.384 30.623 3.402 ;
     RECT  30.24 109.494 30.623 109.854 ;
     RECT  30.371 2.376 30.767 2.484 ;
     RECT  30.24 107.406 30.767 107.622 ;
     RECT  30.24 11.286 30.803 11.304 ;
     RECT  30.623 109.836 30.803 109.854 ;
     RECT  30.24 117.396 30.803 117.414 ;
     RECT  30.371 241.254 30.803 241.974 ;
     RECT  30.24 6.894 30.839 7.254 ;
     RECT  30.407 121.446 30.839 121.464 ;
     RECT  30.24 123.498 30.839 123.516 ;
     RECT  30.803 241.956 30.839 241.974 ;
     RECT  30.479 86.436 30.875 86.454 ;
     RECT  30.24 203.184 30.875 203.706 ;
     RECT  30.839 6.894 30.911 6.912 ;
     RECT  30.515 102.672 30.911 104.346 ;
     RECT  30.767 107.604 30.911 107.622 ;
     RECT  30.767 2.466 30.947 2.484 ;
     RECT  30.24 93.798 30.947 93.816 ;
     RECT  30.515 101.826 30.947 101.844 ;
     RECT  30.24 210.096 30.947 210.114 ;
     RECT  30.24 81.486 30.983 81.504 ;
     RECT  30.911 102.672 30.983 103.374 ;
     RECT  30.24 181.926 30.983 181.944 ;
     RECT  30.911 104.166 31.019 104.346 ;
     RECT  30.875 203.688 31.019 203.706 ;
     RECT  30.983 103.356 31.055 103.374 ;
     RECT  30.24 202.176 31.055 202.194 ;
     RECT  30.371 98.622 31.091 98.64 ;
     RECT  31.019 104.328 31.091 104.346 ;
    LAYER M3 ;
     RECT  2.304 0.012 27.846 0.059 ;
     RECT  2.376 0.059 27.81 0.557 ;
     RECT  2.376 0.557 25.974 1.723 ;
     RECT  27.036 0.557 27.81 1.723 ;
     RECT  28.692 0.031 28.71 1.723 ;
     RECT  2.232 1.723 28.782 2.065 ;
     RECT  2.232 2.065 29.322 2.101 ;
     RECT  2.232 2.101 29.718 2.191 ;
     RECT  2.232 2.191 29.898 2.461 ;
     RECT  30.744 2.371 30.762 2.461 ;
     RECT  2.232 2.461 30.942 2.533 ;
     RECT  2.16 2.533 30.942 4.765 ;
     RECT  1.908 4.765 30.942 9.041 ;
     RECT  27.396 9.041 30.942 9.895 ;
     RECT  1.908 9.041 26.442 10.165 ;
     RECT  27.36 9.895 30.942 10.165 ;
     RECT  1.908 10.165 30.942 81.481 ;
     RECT  1.908 81.481 30.978 98.617 ;
     RECT  1.908 98.617 31.086 104.351 ;
     RECT  1.908 104.351 31.05 155.489 ;
     RECT  2.052 155.489 31.05 189.337 ;
     RECT  2.016 189.337 31.05 189.607 ;
     RECT  1.98 189.607 31.05 202.199 ;
     RECT  1.98 202.199 31.014 202.865 ;
     RECT  29.232 202.865 31.014 202.937 ;
     RECT  1.98 202.865 28.494 203.441 ;
     RECT  29.304 202.937 31.014 203.711 ;
     RECT  1.98 203.441 28.35 204.295 ;
     RECT  1.98 204.295 28.494 205.243 ;
     RECT  29.304 203.711 30.942 205.243 ;
     RECT  1.98 205.243 30.942 210.119 ;
     RECT  1.98 210.119 30.906 216.173 ;
     RECT  1.98 216.173 30.834 241.979 ;
     RECT  1.98 241.979 30.402 250.997 ;
     RECT  1.98 250.997 30.33 260.237 ;
     RECT  1.98 260.237 15.462 260.995 ;
     RECT  16.2 260.237 30.33 260.995 ;
     RECT  1.98 260.995 30.33 293.189 ;
     RECT  2.016 293.189 30.33 293.279 ;
     RECT  2.196 293.279 30.33 294.773 ;
     RECT  2.196 294.773 29.97 294.899 ;
     RECT  2.196 294.899 29.697 297.827 ;
     RECT  2.196 297.827 29.505 297.977 ;
     RECT  28.836 297.977 29.505 298.013 ;
     RECT  28.908 298.013 29.505 298.049 ;
     RECT  29.415 298.049 29.505 298.097 ;
     RECT  2.196 297.977 27.882 298.319 ;
     RECT  2.196 298.319 27.846 298.733 ;
     RECT  2.304 298.733 27.846 300.221 ;
    LAYER M4 ;
     RECT  2.221 153.696 2.293 153.72 ;
     RECT  2.252 225.648 2.293 225.672 ;
     RECT  2.252 267.888 2.293 267.912 ;
     RECT  2.185 298.704 2.293 298.728 ;
     RECT  2.177 1.728 2.365 1.752 ;
     RECT  2.185 3.312 2.365 3.336 ;
     RECT  2.221 6.864 2.365 6.888 ;
     RECT  1.933 8.016 2.365 8.04 ;
     RECT  2.329 9.264 2.365 9.288 ;
     RECT  2.365 1.728 2.389 3.336 ;
     RECT  2.389 1.68 2.408 3.336 ;
     RECT  2.365 4.656 2.408 4.68 ;
     RECT  2.365 6.864 2.408 9.288 ;
     RECT  2.293 11.52 2.408 11.976 ;
     RECT  2.293 13.632 2.408 13.656 ;
     RECT  2.293 15.456 2.408 15.48 ;
     RECT  2.293 16.56 2.408 16.584 ;
     RECT  2.401 51.12 2.408 51.144 ;
     RECT  2.365 79.2 2.408 79.224 ;
     RECT  2.365 108.096 2.408 108.12 ;
     RECT  2.365 115.152 2.408 115.176 ;
     RECT  2.365 116.832 2.408 116.856 ;
     RECT  2.401 138.96 2.408 138.984 ;
     RECT  2.401 150.288 2.408 150.312 ;
     RECT  2.293 152.736 2.408 153.72 ;
     RECT  2.365 157.488 2.408 157.512 ;
     RECT  2.293 161.088 2.408 161.112 ;
     RECT  2.365 199.056 2.408 199.08 ;
     RECT  2.365 214.176 2.408 214.2 ;
     RECT  2.365 216.624 2.408 216.648 ;
     RECT  2.365 217.68 2.408 217.704 ;
     RECT  2.293 224.448 2.408 224.472 ;
     RECT  2.293 225.648 2.408 226.632 ;
     RECT  2.293 241.632 2.408 241.656 ;
     RECT  2.293 262.224 2.408 262.248 ;
     RECT  2.252 266.736 2.408 266.76 ;
     RECT  2.293 267.888 2.408 268.008 ;
     RECT  2.293 270.864 2.408 270.888 ;
     RECT  2.401 274.944 2.408 274.968 ;
     RECT  2.221 290.592 2.408 290.616 ;
     RECT  2.293 293.952 2.408 293.976 ;
     RECT  2.197 295.488 2.408 295.512 ;
     RECT  2.365 296.64 2.408 296.664 ;
     RECT  2.293 298.176 2.408 298.728 ;
     RECT  2.408 1.68 2.435 298.728 ;
     RECT  2.677 299.856 2.689 299.88 ;
     RECT  2.435 1.68 2.704 298.2 ;
     RECT  2.704 1.68 2.801 13.08 ;
     RECT  2.704 15.456 2.801 16.584 ;
     RECT  2.704 77.952 2.819 79.224 ;
     RECT  2.704 83.856 2.819 86.04 ;
     RECT  2.704 89.232 2.819 92.952 ;
     RECT  2.704 99.696 2.819 100.248 ;
     RECT  2.704 105.216 2.819 108.12 ;
     RECT  2.704 121.152 2.819 122.376 ;
     RECT  2.704 207.888 2.819 209.592 ;
     RECT  2.704 210.912 2.819 212.664 ;
     RECT  2.704 237.696 2.819 243.432 ;
     RECT  2.704 245.04 2.819 248.52 ;
     RECT  2.704 249.504 2.819 249.624 ;
     RECT  2.704 250.752 2.819 252.936 ;
     RECT  2.704 267.072 2.819 269.112 ;
     RECT  2.704 293.712 2.819 295.272 ;
     RECT  2.819 84.384 2.837 86.04 ;
     RECT  2.704 87.504 2.837 87.528 ;
     RECT  2.819 89.232 2.837 92.52 ;
     RECT  2.704 95.712 2.837 95.976 ;
     RECT  2.704 101.568 2.837 104.184 ;
     RECT  2.704 255.936 2.837 256.968 ;
     RECT  2.801 15.84 2.867 16.584 ;
     RECT  2.704 217.68 2.867 218.28 ;
     RECT  2.704 219.6 2.867 222.84 ;
     RECT  2.704 231.408 2.867 234.888 ;
     RECT  2.819 239.424 2.867 243.432 ;
     RECT  2.819 245.04 2.867 247.704 ;
     RECT  2.704 261.456 2.867 263.352 ;
     RECT  2.704 270.096 2.867 270.888 ;
     RECT  2.704 296.4 2.867 298.2 ;
     RECT  2.704 18.384 2.909 20.088 ;
     RECT  2.704 67.248 2.915 70.968 ;
     RECT  2.704 138.96 2.915 140.28 ;
     RECT  2.704 172.608 2.915 177.24 ;
     RECT  2.704 272.352 2.915 274.968 ;
     RECT  2.704 276.144 2.915 277.128 ;
     RECT  2.915 67.344 2.917 70.968 ;
     RECT  2.704 116.304 2.945 119.4 ;
     RECT  2.704 151.584 2.945 153.96 ;
     RECT  2.915 272.352 2.953 272.904 ;
     RECT  2.915 273.984 2.953 274.968 ;
     RECT  2.915 276.144 2.953 276.168 ;
     RECT  2.704 80.4 2.956 82.872 ;
     RECT  2.704 46.176 2.963 48.456 ;
     RECT  2.704 163.824 2.963 166.584 ;
     RECT  2.963 163.824 2.981 163.944 ;
     RECT  2.704 178.224 2.981 179.016 ;
     RECT  2.867 239.424 2.981 241.464 ;
     RECT  2.867 233.328 2.989 234.888 ;
     RECT  2.704 284.928 3.011 285.624 ;
     RECT  2.689 299.76 3.013 299.88 ;
     RECT  2.867 231.408 3.017 231.72 ;
     RECT  3.013 299.76 3.049 300.024 ;
     RECT  2.837 95.856 3.053 95.976 ;
     RECT  2.704 192.624 3.053 193.848 ;
     RECT  2.704 258.096 3.053 259.944 ;
     RECT  2.704 50.112 3.059 51.144 ;
     RECT  3.053 95.952 3.059 95.976 ;
     RECT  2.819 100.08 3.059 100.104 ;
     RECT  2.704 141.264 3.059 143.352 ;
     RECT  2.704 39.84 3.089 42.792 ;
     RECT  2.704 124.368 3.107 130.92 ;
     RECT  2.704 144.768 3.107 148.92 ;
     RECT  2.704 180.576 3.107 180.6 ;
     RECT  2.704 181.632 3.107 182.856 ;
     RECT  2.704 184.032 3.107 184.056 ;
     RECT  2.704 185.136 3.107 187.176 ;
     RECT  2.837 91.536 3.125 92.52 ;
     RECT  2.989 233.328 3.125 234.792 ;
     RECT  3.049 299.76 3.133 300.12 ;
     RECT  2.704 167.568 3.155 167.832 ;
     RECT  2.704 98.4 3.197 98.664 ;
     RECT  2.867 242.448 3.197 242.712 ;
     RECT  2.704 194.928 3.203 194.952 ;
     RECT  2.704 197.184 3.203 197.208 ;
     RECT  3.059 50.112 3.251 50.856 ;
     RECT  2.704 112.848 3.251 113.976 ;
     RECT  3.107 145.92 3.269 148.92 ;
     RECT  2.704 292.416 3.269 292.44 ;
     RECT  2.704 62.256 3.299 63.24 ;
     RECT  2.704 155.568 3.299 162.456 ;
     RECT  2.704 213.744 3.299 215.496 ;
     RECT  2.704 216.528 3.299 216.648 ;
     RECT  2.704 64.992 3.305 66.12 ;
     RECT  2.945 152.112 3.305 153.96 ;
     RECT  2.704 168.816 3.305 169.368 ;
     RECT  2.915 173.28 3.305 177.24 ;
     RECT  2.867 245.04 3.305 245.064 ;
     RECT  2.819 252 3.305 252.6 ;
     RECT  2.704 264.48 3.305 265.944 ;
     RECT  3.299 156.864 3.34 162.456 ;
     RECT  2.963 165.312 3.341 166.584 ;
     RECT  3.089 39.84 3.347 42.216 ;
     RECT  3.299 62.256 3.347 62.28 ;
     RECT  2.704 281.664 3.347 283.896 ;
     RECT  3.305 264.48 3.377 265.848 ;
     RECT  2.704 52.848 3.395 56.76 ;
     RECT  2.704 57.936 3.395 61.224 ;
     RECT  2.704 133.584 3.395 134.952 ;
     RECT  2.819 237.696 3.395 238.344 ;
     RECT  2.704 278.256 3.395 280.392 ;
     RECT  2.837 101.568 3.413 101.592 ;
     RECT  2.704 136.032 3.413 137.736 ;
     RECT  2.704 254.112 3.413 254.232 ;
     RECT  2.867 296.4 3.413 298.104 ;
     RECT  3.413 136.032 3.443 136.2 ;
     RECT  2.867 220.08 3.443 222.84 ;
     RECT  2.704 150.288 3.449 150.312 ;
     RECT  3.305 152.112 3.449 153.72 ;
     RECT  3.347 39.84 3.485 40.968 ;
     RECT  3.269 146.4 3.521 148.92 ;
     RECT  3.305 173.376 3.521 177.24 ;
     RECT  2.704 204.432 3.521 206.616 ;
     RECT  2.909 18.768 3.539 20.088 ;
     RECT  3.107 127.776 3.539 130.92 ;
     RECT  3.395 134.688 3.539 134.952 ;
     RECT  2.915 139.536 3.539 140.28 ;
     RECT  3.539 18.768 3.557 19.368 ;
     RECT  2.956 81.504 3.557 82.872 ;
     RECT  2.819 105.216 3.557 105.24 ;
     RECT  3.299 213.744 3.557 214.008 ;
     RECT  2.867 246.192 3.557 247.704 ;
     RECT  2.819 210.912 3.565 211.464 ;
     RECT  2.945 116.304 3.58 118.92 ;
     RECT  2.704 170.4 3.587 170.424 ;
     RECT  2.704 171.504 3.587 171.528 ;
     RECT  2.867 217.968 3.629 218.28 ;
     RECT  2.704 34.608 3.635 38.136 ;
     RECT  3.539 134.688 3.635 134.808 ;
     RECT  2.819 212.544 3.635 212.664 ;
     RECT  3.485 39.888 3.665 40.968 ;
     RECT  3.395 133.584 3.665 133.608 ;
     RECT  2.704 188.208 3.665 190.92 ;
     RECT  3.305 252.288 3.665 252.6 ;
     RECT  3.395 52.848 3.673 56.616 ;
     RECT  2.704 288.672 3.673 289.56 ;
     RECT  3.341 165.504 3.683 166.584 ;
     RECT  3.521 174.288 3.683 177.24 ;
     RECT  2.981 239.808 3.683 240.12 ;
     RECT  3.58 116.304 3.685 116.856 ;
     RECT  2.819 267.072 3.685 269.064 ;
     RECT  2.704 29.184 3.697 29.832 ;
     RECT  2.704 94.704 3.697 94.728 ;
     RECT  3.299 155.568 3.697 155.784 ;
     RECT  3.665 190.896 3.697 190.92 ;
     RECT  2.867 261.456 3.697 262.536 ;
     RECT  2.704 200.592 3.701 200.808 ;
     RECT  3.557 213.984 3.701 214.008 ;
     RECT  3.58 117.84 3.731 118.92 ;
     RECT  3.697 154.992 3.733 155.784 ;
     RECT  2.819 207.984 3.733 209.592 ;
     RECT  2.704 225.504 3.733 225.528 ;
     RECT  2.704 226.608 3.733 226.872 ;
     RECT  2.704 229.104 3.733 229.752 ;
     RECT  2.819 249.504 3.733 249.528 ;
     RECT  3.395 278.256 3.733 278.472 ;
     RECT  3.011 285.456 3.733 285.624 ;
     RECT  3.34 157.968 3.737 162.456 ;
     RECT  3.683 174.384 3.737 177.24 ;
     RECT  2.704 199.056 3.737 199.08 ;
     RECT  2.819 77.952 3.74 78.888 ;
     RECT  2.704 201.792 3.74 202.344 ;
     RECT  2.704 32.448 3.769 32.472 ;
     RECT  2.819 122.352 3.769 122.376 ;
     RECT  3.413 254.112 3.769 254.184 ;
     RECT  2.819 294.24 3.769 295.272 ;
     RECT  3.413 296.4 3.769 296.664 ;
     RECT  3.395 279.888 3.772 280.392 ;
     RECT  3.251 50.112 3.773 50.76 ;
     RECT  3.769 294.24 3.773 296.664 ;
     RECT  3.449 152.208 3.779 153.72 ;
     RECT  3.683 165.504 3.779 166.488 ;
     RECT  3.737 174.384 3.779 174.456 ;
     RECT  2.704 75.264 3.781 76.392 ;
     RECT  2.819 106.464 3.781 108.12 ;
     RECT  2.819 121.152 3.781 121.368 ;
     RECT  2.819 250.752 3.781 250.92 ;
     RECT  2.704 227.952 3.788 227.976 ;
     RECT  3.733 229.104 3.788 229.8 ;
     RECT  2.837 84.384 3.805 84.6 ;
     RECT  3.125 91.584 3.805 92.52 ;
     RECT  2.704 115.104 3.805 115.176 ;
     RECT  3.685 116.16 3.805 116.856 ;
     RECT  2.801 1.728 3.809 13.08 ;
     RECT  3.673 54.528 3.809 56.616 ;
     RECT  2.981 178.224 3.809 178.728 ;
     RECT  3.773 294.48 3.82 296.664 ;
     RECT  3.74 77.76 3.827 78.888 ;
     RECT  3.059 141.264 3.827 142.872 ;
     RECT  3.74 144.48 3.827 144.504 ;
     RECT  3.521 146.4 3.827 147.624 ;
     RECT  3.737 159.888 3.827 162.456 ;
     RECT  3.701 200.784 3.827 200.808 ;
     RECT  3.521 204.432 3.827 206.472 ;
     RECT  3.781 120.576 3.836 121.368 ;
     RECT  3.769 122.352 3.836 122.568 ;
     RECT  3.017 231.408 3.836 231.432 ;
     RECT  2.981 241.104 3.837 241.464 ;
     RECT  3.769 32.448 3.841 32.568 ;
     RECT  3.773 50.112 3.841 50.136 ;
     RECT  3.395 58.656 3.841 61.224 ;
     RECT  3.413 137.712 3.841 137.736 ;
     RECT  3.107 181.632 3.841 182.376 ;
     RECT  3.443 220.08 3.841 220.104 ;
     RECT  2.837 256.272 3.841 256.968 ;
     RECT  3.685 267.024 3.841 269.064 ;
     RECT  2.867 270.096 3.841 270.792 ;
     RECT  3.733 285.456 3.841 285.72 ;
     RECT  3.836 286.752 3.841 286.776 ;
     RECT  2.704 97.392 3.845 97.416 ;
     RECT  3.809 8.352 3.868 13.08 ;
     RECT  3.781 250.752 3.868 251.064 ;
     RECT  3.827 159.888 3.875 161.928 ;
     RECT  3.733 249.408 3.875 249.528 ;
     RECT  3.868 250.752 3.875 250.92 ;
     RECT  3.841 285.456 3.875 286.776 ;
     RECT  3.82 294.624 3.875 296.664 ;
     RECT  2.704 26.784 3.877 27.336 ;
     RECT  3.805 73.488 3.877 73.512 ;
     RECT  3.781 74.784 3.877 76.392 ;
     RECT  3.805 83.472 3.877 84.6 ;
     RECT  3.836 120.576 3.877 122.568 ;
     RECT  3.733 207.984 3.877 209.688 ;
     RECT  3.697 261.264 3.877 262.536 ;
     RECT  3.733 154.896 3.881 155.784 ;
     RECT  3.697 29.184 3.884 30.696 ;
     RECT  3.841 31.92 3.884 32.568 ;
     RECT  3.875 250.752 3.889 250.824 ;
     RECT  3.557 247.44 3.913 247.704 ;
     RECT  3.809 54.528 3.917 56.088 ;
     RECT  2.917 67.344 3.917 69.24 ;
     RECT  3.733 278.16 3.917 278.472 ;
     RECT  3.884 29.184 3.923 30.792 ;
     RECT  3.827 77.856 3.923 78.888 ;
     RECT  3.781 106.416 3.923 108.12 ;
     RECT  3.877 120.576 3.923 123.336 ;
     RECT  3.125 234.24 3.923 234.792 ;
     RECT  3.884 31.92 3.925 33.48 ;
     RECT  3.635 34.608 3.925 35.448 ;
     RECT  3.697 190.896 3.925 191.4 ;
     RECT  3.053 192.624 3.925 193.8 ;
     RECT  3.788 227.952 3.925 229.8 ;
     RECT  3.836 231.312 3.925 231.432 ;
     RECT  3.841 267.024 3.941 270.792 ;
     RECT  3.868 12.48 3.949 13.08 ;
     RECT  3.781 14.208 3.949 14.232 ;
     RECT  3.877 80.256 3.949 80.28 ;
     RECT  3.557 81.504 3.949 82.2 ;
     RECT  3.875 249.504 3.949 249.528 ;
     RECT  3.889 250.752 3.949 250.776 ;
     RECT  3.769 254.016 3.949 254.184 ;
     RECT  2.704 109.872 3.953 111.096 ;
     RECT  3.251 112.848 3.953 113.4 ;
     RECT  3.539 127.776 3.953 129.432 ;
     RECT  3.841 137.712 3.953 138.504 ;
     RECT  3.197 242.688 3.953 242.712 ;
     RECT  3.877 73.488 3.961 76.392 ;
     RECT  3.877 26.784 3.964 28.152 ;
     RECT  3.925 31.92 3.971 35.448 ;
     RECT  3.961 73.488 3.971 73.992 ;
     RECT  3.875 159.888 3.971 161.832 ;
     RECT  3.925 190.896 3.971 193.8 ;
     RECT  3.964 26.784 3.973 27.336 ;
     RECT  3.841 219.6 3.973 220.104 ;
     RECT  3.877 261.264 3.973 262.776 ;
     RECT  3.941 267.024 3.98 271.368 ;
     RECT  3.841 58.656 3.989 61.992 ;
     RECT  3.973 26.688 4.019 27.336 ;
     RECT  3.881 154.896 4.019 155.016 ;
     RECT  3.985 25.104 4.021 25.128 ;
     RECT  3.107 186 4.021 187.176 ;
     RECT  3.665 188.208 4.021 189.816 ;
     RECT  2.917 70.944 4.025 70.968 ;
     RECT  3.971 73.968 4.025 73.992 ;
     RECT  3.827 146.976 4.025 147.624 ;
     RECT  3.737 175.536 4.025 177.24 ;
     RECT  2.704 236.448 4.025 236.712 ;
     RECT  3.557 246.192 4.025 246.216 ;
     RECT  3.913 247.44 4.025 247.752 ;
     RECT  2.704 290.592 4.028 291.384 ;
     RECT  3.805 21.648 4.057 21.672 ;
     RECT  3.805 91.584 4.057 93.288 ;
     RECT  3.923 122.544 4.057 123.336 ;
     RECT  3.107 124.368 4.057 125.496 ;
     RECT  2.981 163.92 4.057 163.944 ;
     RECT  3.053 258.24 4.057 259.944 ;
     RECT  3.973 261.216 4.057 262.776 ;
     RECT  3.731 118.176 4.061 118.92 ;
     RECT  3.155 167.568 4.061 167.592 ;
     RECT  3.305 169.344 4.061 169.368 ;
     RECT  3.973 218.736 4.061 220.104 ;
     RECT  3.395 238.272 4.061 238.344 ;
     RECT  4.025 247.728 4.061 247.752 ;
     RECT  3.557 18.768 4.093 18.792 ;
     RECT  2.837 89.232 4.093 90.36 ;
     RECT  3.539 140.16 4.093 140.28 ;
     RECT  3.827 141.264 4.093 142.776 ;
     RECT  3.877 207.456 4.093 209.688 ;
     RECT  3.443 221.136 4.093 222.84 ;
     RECT  3.733 225.504 4.093 226.872 ;
     RECT  3.877 233.088 4.093 233.16 ;
     RECT  3.989 61.2 4.097 61.992 ;
     RECT  3.953 113.376 4.097 113.4 ;
     RECT  3.635 212.544 4.097 212.568 ;
     RECT  3.683 239.808 4.097 239.832 ;
     RECT  3.299 216.624 4.115 216.648 ;
     RECT  4.057 258.24 4.115 262.776 ;
     RECT  4.028 290.592 4.115 292.056 ;
     RECT  2.963 47.28 4.117 48.456 ;
     RECT  3.841 49.872 4.117 50.136 ;
     RECT  3.841 217.728 4.117 217.752 ;
     RECT  3.772 280.368 4.117 280.392 ;
     RECT  3.347 281.664 4.117 283.272 ;
     RECT  3.347 42.144 4.129 42.216 ;
     RECT  3.877 83.472 4.129 84.936 ;
     RECT  4.021 96.096 4.129 96.12 ;
     RECT  3.953 109.968 4.129 111.096 ;
     RECT  3.805 115.104 4.129 116.856 ;
     RECT  3.107 126.576 4.129 126.744 ;
     RECT  3.953 127.776 4.129 129.096 ;
     RECT  4.093 221.136 4.129 222.984 ;
     RECT  4.061 238.32 4.129 238.344 ;
     RECT  4.115 258.576 4.129 262.776 ;
     RECT  4.057 263.856 4.129 263.88 ;
     RECT  3.917 69.216 4.133 69.24 ;
     RECT  3.949 80.256 4.133 82.2 ;
     RECT  3.74 201.792 4.157 202.536 ;
     RECT  4.021 24.816 4.163 25.128 ;
     RECT  4.129 221.136 4.165 223.08 ;
     RECT  3.769 224.352 4.165 224.376 ;
     RECT  3.925 227.952 4.165 231.432 ;
     RECT  4.093 232.8 4.165 233.16 ;
     RECT  2.704 72.336 4.169 72.36 ;
     RECT  4.165 221.136 4.169 224.376 ;
     RECT  2.953 274.128 4.172 274.968 ;
     RECT  4.129 83.472 4.201 85.752 ;
     RECT  4.115 290.592 4.201 291.24 ;
     RECT  4.117 23.712 4.204 23.736 ;
     RECT  3.539 130.512 4.205 130.92 ;
     RECT  3.397 299.28 4.211 299.4 ;
     RECT  4.021 183.408 4.213 183.432 ;
     RECT  4.021 186 4.213 189.816 ;
     RECT  3.829 284.4 4.213 284.424 ;
     RECT  3.875 285.456 4.213 285.624 ;
     RECT  3.875 286.608 4.213 286.776 ;
     RECT  4.201 83.472 4.22 86.664 ;
     RECT  3.521 148.8 4.22 148.92 ;
     RECT  3.841 181.488 4.22 182.376 ;
     RECT  4.213 183.408 4.22 183.96 ;
     RECT  3.805 198.24 4.237 198.408 ;
     RECT  4.129 238.32 4.237 238.824 ;
     RECT  4.021 243.36 4.237 243.384 ;
     RECT  4.157 201.456 4.241 202.536 ;
     RECT  4.213 284.4 4.241 285.624 ;
     RECT  4.117 280.368 4.259 283.272 ;
     RECT  4.213 286.608 4.259 287.064 ;
     RECT  3.197 98.4 4.261 98.616 ;
     RECT  2.837 102.624 4.261 104.184 ;
     RECT  4.22 148.8 4.261 149.016 ;
     RECT  3.949 253.872 4.268 254.184 ;
     RECT  2.704 44.304 4.273 44.424 ;
     RECT  4.093 88.32 4.273 90.36 ;
     RECT  3.665 252.288 4.277 252.312 ;
     RECT  4.129 258.576 4.277 263.88 ;
     RECT  4.097 61.584 4.307 61.992 ;
     RECT  4.22 83.472 4.307 87 ;
     RECT  4.261 148.8 4.307 149.928 ;
     RECT  4.273 43.872 4.316 44.424 ;
     RECT  4.165 195.072 4.316 195.096 ;
     RECT  2.704 196.08 4.316 196.104 ;
     RECT  4.316 43.824 4.337 44.424 ;
     RECT  4.261 98.4 4.349 99.144 ;
     RECT  3.413 297.696 4.349 298.104 ;
     RECT  3.949 249.504 4.355 250.776 ;
     RECT  4.268 253.632 4.355 254.184 ;
     RECT  4.337 43.824 4.364 45.048 ;
     RECT  2.963 46.176 4.364 46.2 ;
     RECT  3.923 29.472 4.381 30.792 ;
     RECT  3.971 31.92 4.381 32.52 ;
     RECT  3.665 40.416 4.381 40.968 ;
     RECT  4.129 42.144 4.381 42.744 ;
     RECT  3.989 58.656 4.381 59.832 ;
     RECT  3.868 8.352 4.385 11.4 ;
     RECT  4.057 163.92 4.385 164.52 ;
     RECT  4.364 43.824 4.403 46.2 ;
     RECT  4.316 195.072 4.403 196.104 ;
     RECT  4.237 243.36 4.403 244.296 ;
     RECT  4.237 248.16 4.403 248.184 ;
     RECT  4.355 249.504 4.403 250.152 ;
     RECT  4.403 43.872 4.405 46.2 ;
     RECT  4.117 47.232 4.405 50.136 ;
     RECT  4.355 253.872 4.405 254.184 ;
     RECT  4.211 299.328 4.405 299.4 ;
     RECT  4.025 147.072 4.421 147.624 ;
     RECT  4.261 102.384 4.449 104.184 ;
     RECT  3.841 255.84 4.451 256.968 ;
     RECT  4.277 258.576 4.451 259.32 ;
     RECT  4.169 221.856 4.453 224.376 ;
     RECT  4.093 225.504 4.453 226.92 ;
     RECT  4.405 299.328 4.453 300.024 ;
     RECT  4.057 122.544 4.457 125.496 ;
     RECT  4.093 140.16 4.457 142.776 ;
     RECT  4.451 256.08 4.457 256.968 ;
     RECT  4.273 88.128 4.46 90.36 ;
     RECT  4.172 274.128 4.489 275.16 ;
     RECT  4.405 253.872 4.492 254.376 ;
     RECT  3.635 36.528 4.493 38.136 ;
     RECT  4.449 103.248 4.493 104.184 ;
     RECT  4.22 181.488 4.493 183.96 ;
     RECT  4.213 185.28 4.493 189.816 ;
     RECT  4.025 236.448 4.493 236.472 ;
     RECT  4.417 131.424 4.501 131.448 ;
     RECT  3.443 136.128 4.525 136.2 ;
     RECT  4.493 185.28 4.525 188.664 ;
     RECT  4.241 202.32 4.525 202.536 ;
     RECT  2.867 15.84 4.529 15.864 ;
     RECT  4.457 122.544 4.529 124.536 ;
     RECT  4.129 126.576 4.529 129.096 ;
     RECT  4.453 299.328 4.537 300.12 ;
     RECT  4.405 43.872 4.547 50.136 ;
     RECT  4.453 221.856 4.547 226.92 ;
     RECT  4.093 207.456 4.549 209.736 ;
     RECT  3.565 211.392 4.549 211.464 ;
     RECT  4.349 297.696 4.549 297.912 ;
     RECT  4.307 149.904 4.561 149.928 ;
     RECT  3.98 266.976 4.561 271.368 ;
     RECT  2.953 272.448 4.561 272.904 ;
     RECT  4.489 274.128 4.561 275.928 ;
     RECT  4.529 122.544 4.565 124.488 ;
     RECT  4.493 183.408 4.565 183.96 ;
     RECT  4.493 189.648 4.565 189.816 ;
     RECT  4.501 131.424 4.595 131.544 ;
     RECT  4.349 98.4 4.597 99 ;
     RECT  3.923 120.576 4.597 121.32 ;
     RECT  4.489 170.448 4.597 170.472 ;
     RECT  4.565 183.792 4.597 183.96 ;
     RECT  4.525 185.184 4.597 188.664 ;
     RECT  3.971 193.104 4.597 193.8 ;
     RECT  4.547 43.872 4.601 44.424 ;
     RECT  4.595 131.52 4.601 131.544 ;
     RECT  4.307 83.472 4.604 86.664 ;
     RECT  3.377 265.008 4.625 265.848 ;
     RECT  4.561 266.976 4.625 272.904 ;
     RECT  4.093 17.904 4.633 18.792 ;
     RECT  4.381 40.416 4.633 42.744 ;
     RECT  3.697 94.656 4.633 94.728 ;
     RECT  4.129 95.712 4.633 96.12 ;
     RECT  4.025 176.352 4.633 177.24 ;
     RECT  3.809 178.224 4.633 178.584 ;
     RECT  4.549 207.456 4.633 211.464 ;
     RECT  4.547 226.8 4.633 226.92 ;
     RECT  4.165 227.952 4.633 233.16 ;
     RECT  4.625 265.008 4.633 272.904 ;
     RECT  4.547 45.744 4.637 46.2 ;
     RECT  4.547 47.232 4.637 50.136 ;
     RECT  3.917 67.344 4.637 68.136 ;
     RECT  4.561 149.904 4.637 150.456 ;
     RECT  4.633 226.8 4.637 233.16 ;
     RECT  3.875 294.624 4.643 295.272 ;
     RECT  4.637 150.432 4.645 150.456 ;
     RECT  4.597 193.104 4.645 194.472 ;
     RECT  4.633 265.008 4.645 273 ;
     RECT  4.261 101.28 4.652 101.304 ;
     RECT  3.673 52.848 4.669 52.872 ;
     RECT  4.633 94.656 4.669 96.12 ;
     RECT  4.652 101.28 4.669 101.976 ;
     RECT  4.277 260.832 4.669 263.88 ;
     RECT  4.645 265.008 4.669 271.128 ;
     RECT  4.381 29.472 4.673 32.52 ;
     RECT  3.923 78.432 4.673 78.888 ;
     RECT  4.529 127.776 4.673 129.096 ;
     RECT  4.241 284.928 4.673 284.952 ;
     RECT  4.549 134.496 4.691 134.52 ;
     RECT  4.645 272.256 4.691 273 ;
     RECT  3.923 106.464 4.693 108.12 ;
     RECT  3.917 278.256 4.693 278.472 ;
     RECT  3.923 234.24 4.705 234.6 ;
     RECT  3.961 75.168 4.709 76.392 ;
     RECT  3.779 174.432 4.709 174.456 ;
     RECT  4.403 196.08 4.709 196.104 ;
     RECT  4.669 260.832 4.709 271.128 ;
     RECT  4.669 94.656 4.717 96.696 ;
     RECT  4.604 83.136 4.739 86.664 ;
     RECT  4.717 94.896 4.739 96.696 ;
     RECT  4.597 98.016 4.739 99 ;
     RECT  4.669 100.8 4.739 101.976 ;
     RECT  4.637 229.008 4.739 233.16 ;
     RECT  4.259 280.368 4.739 282.888 ;
     RECT  3.779 152.784 4.741 153.72 ;
     RECT  4.019 154.896 4.741 154.968 ;
     RECT  4.385 163.92 4.741 164.136 ;
     RECT  4.133 80.256 4.745 82.104 ;
     RECT  4.565 122.64 4.745 124.488 ;
     RECT  4.493 181.488 4.777 182.424 ;
     RECT  3.299 215.472 4.777 215.496 ;
     RECT  4.633 17.904 4.781 18.936 ;
     RECT  4.057 21.648 4.789 22.344 ;
     RECT  4.777 181.2 4.789 182.424 ;
     RECT  4.525 202.32 4.789 202.824 ;
     RECT  3.827 204.528 4.789 204.744 ;
     RECT  4.316 245.904 4.789 245.928 ;
     RECT  4.739 100.8 4.817 101.304 ;
     RECT  4.777 214.896 4.817 215.496 ;
     RECT  4.739 229.008 4.817 230.568 ;
     RECT  4.709 260.832 4.825 265.848 ;
     RECT  4.453 179.856 4.835 179.88 ;
     RECT  4.825 260.832 4.835 261.672 ;
     RECT  4.381 58.608 4.837 59.832 ;
     RECT  3.34 156.864 4.837 156.888 ;
     RECT  3.737 157.968 4.837 158.568 ;
     RECT  3.949 12.48 4.849 14.232 ;
     RECT  4.781 17.904 4.849 18.744 ;
     RECT  4.817 100.8 4.849 100.92 ;
     RECT  4.741 163.872 4.849 164.136 ;
     RECT  4.789 180.912 4.849 182.424 ;
     RECT  4.817 214.896 4.861 215.352 ;
     RECT  4.673 29.472 4.876 30.12 ;
     RECT  4.604 16.224 4.885 16.296 ;
     RECT  4.777 51.6 4.885 51.624 ;
     RECT  4.669 52.848 4.885 53.496 ;
     RECT  3.917 54.768 4.885 56.088 ;
     RECT  4.46 88.128 4.885 90.504 ;
     RECT  4.057 91.584 4.885 93.528 ;
     RECT  4.061 118.752 4.885 118.92 ;
     RECT  4.597 120.24 4.885 121.32 ;
     RECT  4.597 169.872 4.885 170.472 ;
     RECT  4.741 152.784 4.889 154.968 ;
     RECT  4.885 16.224 4.921 16.344 ;
     RECT  4.849 17.424 4.921 18.744 ;
     RECT  4.789 21.36 4.921 22.344 ;
     RECT  4.885 88.128 4.921 93.528 ;
     RECT  4.849 163.152 4.921 164.136 ;
     RECT  4.837 156.864 4.925 158.568 ;
     RECT  4.835 260.832 4.925 261.576 ;
     RECT  4.547 221.856 4.931 225.768 ;
     RECT  3.827 206.16 4.957 206.472 ;
     RECT  4.633 207.456 4.957 212.424 ;
     RECT  4.876 29.568 4.979 30.12 ;
     RECT  4.163 24.816 4.981 24.84 ;
     RECT  4.561 274.128 4.981 276.456 ;
     RECT  4.381 71.088 4.993 71.112 ;
     RECT  4.525 135.552 4.993 136.2 ;
     RECT  4.691 272.352 4.993 273 ;
     RECT  4.693 278.256 4.993 278.712 ;
     RECT  4.817 229.008 4.997 230.136 ;
     RECT  4.889 153.6 5.027 154.968 ;
     RECT  4.885 169.872 5.029 171.048 ;
     RECT  4.885 172.08 5.029 172.104 ;
     RECT  4.633 176.352 5.029 178.584 ;
     RECT  4.117 216.864 5.029 217.752 ;
     RECT  4.061 218.736 5.029 219.72 ;
     RECT  4.019 26.688 5.033 27.048 ;
     RECT  4.885 51.6 5.033 53.496 ;
     RECT  4.549 130.32 5.033 130.392 ;
     RECT  4.993 277.584 5.033 278.712 ;
     RECT  4.739 280.368 5.033 280.44 ;
     RECT  4.693 143.76 5.065 143.784 ;
     RECT  3.779 165.504 5.065 166.44 ;
     RECT  5.029 200.112 5.065 200.136 ;
     RECT  4.237 238.32 5.065 239.592 ;
     RECT  4.789 245.664 5.065 245.928 ;
     RECT  4.921 16.224 5.069 18.744 ;
     RECT  4.981 20.208 5.069 20.232 ;
     RECT  4.988 213.696 5.075 213.72 ;
     RECT  5.029 216.864 5.075 219.72 ;
     RECT  4.825 263.136 5.075 265.848 ;
     RECT  4.739 281.568 5.075 282.888 ;
     RECT  4.633 40.416 5.077 42.888 ;
     RECT  4.745 80.256 5.077 81.528 ;
     RECT  4.129 114.576 5.077 116.856 ;
     RECT  4.309 292.464 5.077 292.488 ;
     RECT  4.849 293.568 5.077 293.592 ;
     RECT  4.921 87.888 5.101 93.528 ;
     RECT  4.789 202.32 5.105 204.744 ;
     RECT  5.077 39.888 5.123 42.888 ;
     RECT  5.033 51.6 5.123 53.4 ;
     RECT  5.077 79.584 5.123 81.528 ;
     RECT  4.849 180.144 5.123 182.424 ;
     RECT  4.957 206.16 5.123 212.424 ;
     RECT  4.885 54.72 5.125 56.088 ;
     RECT  4.837 57.744 5.125 59.832 ;
     RECT  4.925 158.112 5.125 158.568 ;
     RECT  3.971 159.888 5.125 161.112 ;
     RECT  5.029 169.872 5.125 172.104 ;
     RECT  5.029 175.584 5.125 178.584 ;
     RECT  4.259 287.04 5.125 287.064 ;
     RECT  3.673 288.672 5.125 288.696 ;
     RECT  4.993 135.552 5.132 136.728 ;
     RECT  3.953 137.712 5.132 137.736 ;
     RECT  4.637 47.28 5.137 50.136 ;
     RECT  5.123 51.6 5.137 53.016 ;
     RECT  4.637 67.872 5.137 68.136 ;
     RECT  4.993 69.312 5.137 69.336 ;
     RECT  5.065 237.456 5.137 239.592 ;
     RECT  4.201 289.776 5.137 291.24 ;
     RECT  5.077 292.464 5.137 293.592 ;
     RECT  4.921 21.36 5.141 22.728 ;
     RECT  4.457 140.16 5.141 142.536 ;
     RECT  4.597 183.792 5.141 188.664 ;
     RECT  5.125 54.72 5.171 59.832 ;
     RECT  5.123 180.144 5.171 181.944 ;
     RECT  4.931 224.688 5.171 225.768 ;
     RECT  4.669 132.24 5.173 132.264 ;
     RECT  5.132 135.552 5.173 137.736 ;
     RECT  4.561 139.104 5.173 139.128 ;
     RECT  5.141 140.16 5.173 141.288 ;
     RECT  5.075 263.136 5.177 265.608 ;
     RECT  5.125 287.04 5.177 288.696 ;
     RECT  4.957 64.416 5.201 64.44 ;
     RECT  4.981 23.856 5.209 24.84 ;
     RECT  4.307 61.728 5.209 61.992 ;
     RECT  4.739 83.136 5.209 86.472 ;
     RECT  5.075 216.864 5.209 218.28 ;
     RECT  5.137 236.496 5.209 239.592 ;
     RECT  3.837 241.104 5.209 241.176 ;
     RECT  5.177 287.76 5.212 288.696 ;
     RECT  5.069 16.32 5.213 17.352 ;
     RECT  5.173 132.24 5.219 132.792 ;
     RECT  5.173 134.784 5.219 137.736 ;
     RECT  5.065 165.504 5.228 167.208 ;
     RECT  4.643 294.768 5.237 295.272 ;
     RECT  5.201 64.08 5.245 64.44 ;
     RECT  3.305 65.712 5.245 65.736 ;
     RECT  5.123 206.16 5.249 210.84 ;
     RECT  5.033 280.368 5.249 280.392 ;
     RECT  5.101 73.008 5.269 73.032 ;
     RECT  4.709 75.168 5.276 75.864 ;
     RECT  5.173 139.104 5.281 141.288 ;
     RECT  5.209 82.656 5.285 86.472 ;
     RECT  5.219 134.784 5.285 136.776 ;
     RECT  3.809 1.728 5.317 7.368 ;
     RECT  4.385 8.352 5.317 10.968 ;
     RECT  5.269 73.008 5.317 73.56 ;
     RECT  4.525 125.568 5.317 125.592 ;
     RECT  4.529 126.576 5.317 126.744 ;
     RECT  5.065 245.664 5.317 246.312 ;
     RECT  4.403 249.552 5.317 250.152 ;
     RECT  4.549 296.976 5.317 297.912 ;
     RECT  4.537 299.328 5.317 299.352 ;
     RECT  5.237 294.768 5.321 295.848 ;
     RECT  4.849 12.48 5.353 14.28 ;
     RECT  5.281 138.72 5.353 141.288 ;
     RECT  3.971 34.128 5.357 35.304 ;
     RECT  5.285 82.656 5.357 82.776 ;
     RECT  5.077 114.432 5.357 116.856 ;
     RECT  5.137 67.872 5.363 69.336 ;
     RECT  5.276 75.024 5.363 75.864 ;
     RECT  5.276 173.808 5.363 173.832 ;
     RECT  5.209 236.496 5.363 241.176 ;
     RECT  5.317 249.552 5.363 250.248 ;
     RECT  4.709 267.024 5.363 271.128 ;
     RECT  5.209 23.856 5.365 25.128 ;
     RECT  5.209 61.728 5.372 62.76 ;
     RECT  5.245 64.08 5.372 65.736 ;
     RECT  4.493 103.584 5.372 104.184 ;
     RECT  4.489 105.408 5.372 105.432 ;
     RECT  3.589 0.192 5.381 0.216 ;
     RECT  5.353 77.088 5.389 77.112 ;
     RECT  4.673 78.432 5.389 78.456 ;
     RECT  5.101 87.888 5.389 93.624 ;
     RECT  4.739 96.288 5.389 96.696 ;
     RECT  4.739 98.016 5.389 98.664 ;
     RECT  4.931 221.856 5.389 223.416 ;
     RECT  4.403 243.6 5.389 243.96 ;
     RECT  4.981 274.128 5.389 276.504 ;
     RECT  5.033 277.584 5.389 278.232 ;
     RECT  5.317 1.728 5.393 10.968 ;
     RECT  5.137 47.28 5.393 53.016 ;
     RECT  5.171 57.024 5.393 59.832 ;
     RECT  5.363 67.872 5.393 68.952 ;
     RECT  5.141 186.432 5.393 188.664 ;
     RECT  5.209 216.624 5.393 218.28 ;
     RECT  5.317 296.976 5.401 298.104 ;
     RECT  5.372 103.584 5.413 105.432 ;
     RECT  4.693 106.464 5.413 108.312 ;
     RECT  4.129 109.968 5.413 112.008 ;
     RECT  5.075 219.408 5.413 219.72 ;
     RECT  5.389 221.568 5.413 223.416 ;
     RECT  4.739 231.984 5.413 233.16 ;
     RECT  4.705 234.144 5.413 234.6 ;
     RECT  5.389 243.6 5.413 244.584 ;
     RECT  5.353 12.48 5.42 14.52 ;
     RECT  5.123 40.944 5.425 42.888 ;
     RECT  4.601 43.872 5.425 43.896 ;
     RECT  4.457 256.08 5.425 256.104 ;
     RECT  5.393 67.872 5.429 68.712 ;
     RECT  4.885 118.752 5.429 121.32 ;
     RECT  5.363 236.496 5.429 240.696 ;
     RECT  5.389 274.128 5.429 278.232 ;
     RECT  5.429 67.872 5.459 68.616 ;
     RECT  5.413 231.984 5.459 234.6 ;
     RECT  5.429 236.496 5.459 237.624 ;
     RECT  5.393 2.832 5.461 10.968 ;
     RECT  5.42 12.192 5.461 14.52 ;
     RECT  5.357 34.128 5.461 35.256 ;
     RECT  4.493 36.528 5.461 37.944 ;
     RECT  5.393 57.12 5.461 59.832 ;
     RECT  4.993 71.088 5.461 71.784 ;
     RECT  5.317 72.96 5.461 73.56 ;
     RECT  4.921 163.008 5.461 164.136 ;
     RECT  4.993 272.352 5.461 273.144 ;
     RECT  5.212 288.24 5.461 288.696 ;
     RECT  5.137 289.776 5.461 293.592 ;
     RECT  5.381 0.192 5.465 0.6 ;
     RECT  5.461 72.912 5.465 73.56 ;
     RECT  5.389 96.288 5.465 98.664 ;
     RECT  5.429 118.752 5.465 121.176 ;
     RECT  5.461 162.144 5.465 164.136 ;
     RECT  5.461 288.24 5.465 293.592 ;
     RECT  5.413 243.312 5.473 244.584 ;
     RECT  5.429 274.656 5.473 278.232 ;
     RECT  5.033 26.976 5.497 27.048 ;
     RECT  5.413 103.584 5.497 108.312 ;
     RECT  5.413 109.968 5.497 112.776 ;
     RECT  5.459 231.984 5.5 234.216 ;
     RECT  5.461 33.792 5.507 35.256 ;
     RECT  5.461 36.528 5.507 37.992 ;
     RECT  5.461 70.656 5.509 71.784 ;
     RECT  5.357 116.736 5.509 116.856 ;
     RECT  5.317 125.568 5.516 126.744 ;
     RECT  5.228 165.264 5.516 167.208 ;
     RECT  5.507 37.632 5.533 37.992 ;
     RECT  3.971 191.856 5.533 192.072 ;
     RECT  5.123 211.872 5.533 212.424 ;
     RECT  4.492 253.872 5.533 253.896 ;
     RECT  5.317 299.28 5.533 299.352 ;
     RECT  5.533 253.872 5.537 254.712 ;
     RECT  5.125 158.112 5.557 161.112 ;
     RECT  5.465 162.144 5.557 163.608 ;
     RECT  5.317 168.816 5.557 168.84 ;
     RECT  5.125 169.872 5.557 172.584 ;
     RECT  5.141 142.512 5.569 142.536 ;
     RECT  5.065 143.76 5.569 144.072 ;
     RECT  5.393 187.872 5.569 188.664 ;
     RECT  5.065 199.824 5.569 200.136 ;
     RECT  5.123 80.784 5.573 81.528 ;
     RECT  5.5 231.984 5.573 233.016 ;
     RECT  5.473 243.312 5.573 243.672 ;
     RECT  5.465 119.088 5.603 121.176 ;
     RECT  4.745 122.64 5.603 124.248 ;
     RECT  5.557 158.112 5.603 163.608 ;
     RECT  5.075 281.568 5.609 282.12 ;
     RECT  5.533 211.872 5.617 213.192 ;
     RECT  5.177 264.432 5.617 265.608 ;
     RECT  5.425 40.944 5.641 43.896 ;
     RECT  4.637 45.744 5.641 45.768 ;
     RECT  5.569 199.776 5.641 200.136 ;
     RECT  5.132 201.168 5.641 201.192 ;
     RECT  5.363 249.936 5.641 250.248 ;
     RECT  5.617 264.432 5.645 265.032 ;
     RECT  5.603 119.088 5.651 120.888 ;
     RECT  5.533 191.472 5.651 192.072 ;
     RECT  5.533 299.28 5.651 299.976 ;
     RECT  5.461 57.12 5.653 60.744 ;
     RECT  5.372 61.728 5.653 65.736 ;
     RECT  5.209 66.72 5.653 66.744 ;
     RECT  5.459 67.872 5.653 67.896 ;
     RECT  5.573 243.312 5.677 243.336 ;
     RECT  4.451 259.296 5.677 259.32 ;
     RECT  5.321 294.768 5.677 295.176 ;
     RECT  5.125 175.584 5.681 179.016 ;
     RECT  5.429 238.8 5.681 240.696 ;
     RECT  5.653 57.12 5.699 65.736 ;
     RECT  5.681 239.136 5.699 240.696 ;
     RECT  5.465 288.24 5.699 288.984 ;
     RECT  5.641 40.944 5.701 43.992 ;
     RECT  5.363 75.168 5.701 75.864 ;
     RECT  4.549 148.224 5.701 148.248 ;
     RECT  5.461 272.352 5.701 273.576 ;
     RECT  5.497 103.584 5.708 112.776 ;
     RECT  5.701 148.224 5.708 148.68 ;
     RECT  5.507 36.528 5.713 36.552 ;
     RECT  5.389 77.088 5.713 78.456 ;
     RECT  5.123 79.584 5.713 79.752 ;
     RECT  5.708 148.224 5.713 149.016 ;
     RECT  4.673 128.016 5.717 129.096 ;
     RECT  5.603 159.984 5.725 163.608 ;
     RECT  5.641 241.68 5.725 241.704 ;
     RECT  5.641 45.744 5.749 45.864 ;
     RECT  5.393 47.28 5.749 51.624 ;
     RECT  4.849 100.176 5.749 100.92 ;
     RECT  5.357 114.432 5.749 115.512 ;
     RECT  5.281 205.056 5.749 205.08 ;
     RECT  5.249 206.16 5.749 210.408 ;
     RECT  5.363 267.024 5.749 270.888 ;
     RECT  5.677 294.672 5.749 295.176 ;
     RECT  5.516 125.328 5.753 126.744 ;
     RECT  5.669 190.944 5.753 190.968 ;
     RECT  5.645 264.48 5.753 265.032 ;
     RECT  5.708 103.44 5.785 112.776 ;
     RECT  4.997 229.296 5.785 230.136 ;
     RECT  5.123 39.888 5.789 39.912 ;
     RECT  5.653 66.72 5.789 67.896 ;
     RECT  5.725 159.984 5.789 163.176 ;
     RECT  4.237 198.144 5.789 198.408 ;
     RECT  5.749 266.832 5.789 270.888 ;
     RECT  5.701 272.304 5.789 273.576 ;
     RECT  5.473 274.656 5.789 276.504 ;
     RECT  5.749 45.744 5.795 51.624 ;
     RECT  5.785 103.44 5.795 112.824 ;
     RECT  5.105 202.32 5.795 203.784 ;
     RECT  5.171 54.72 5.797 56.04 ;
     RECT  5.141 21.36 5.821 21.816 ;
     RECT  5.365 23.856 5.821 25.32 ;
     RECT  4.565 189.792 5.821 189.816 ;
     RECT  4.645 193.104 5.821 193.128 ;
     RECT  5.533 37.632 5.825 38.04 ;
     RECT  5.681 176.352 5.825 179.016 ;
     RECT  5.569 142.512 5.829 144.072 ;
     RECT  5.795 46.752 5.843 51.624 ;
     RECT  5.465 98.64 5.852 98.664 ;
     RECT  5.749 99.696 5.852 100.92 ;
     RECT  5.717 128.304 5.853 128.52 ;
     RECT  5.843 49.488 5.861 51.624 ;
     RECT  5.795 104.832 5.869 112.824 ;
     RECT  4.979 29.664 5.897 30.12 ;
     RECT  5.701 40.944 5.897 44.472 ;
     RECT  5.509 70.56 5.897 71.784 ;
     RECT  5.465 72.912 5.897 73.032 ;
     RECT  5.603 158.112 5.897 159 ;
     RECT  5.317 245.664 5.897 247.128 ;
     RECT  4.489 248.496 5.897 248.52 ;
     RECT  5.177 263.136 5.897 263.352 ;
     RECT  5.789 267.888 5.897 270.888 ;
     RECT  5.789 66.72 5.929 67.8 ;
     RECT  5.852 98.64 5.929 100.92 ;
     RECT  4.421 147.072 5.929 147.096 ;
     RECT  5.713 148.224 5.929 149.64 ;
     RECT  5.173 196.656 5.929 196.68 ;
     RECT  5.677 258.96 5.929 259.32 ;
     RECT  5.861 49.584 5.933 51.624 ;
     RECT  5.701 75.168 5.933 76.104 ;
     RECT  5.843 46.752 5.939 48.456 ;
     RECT  5.797 54.672 5.939 56.04 ;
     RECT  5.413 219.408 5.941 223.416 ;
     RECT  5.317 151.968 5.965 151.992 ;
     RECT  5.027 153.6 5.965 154.344 ;
     RECT  5.516 165.264 5.965 167.496 ;
     RECT  5.557 168.816 5.965 172.584 ;
     RECT  4.645 194.448 5.965 194.472 ;
     RECT  5.929 195.84 5.965 196.68 ;
     RECT  5.897 246.288 5.965 247.128 ;
     RECT  5.641 249.936 5.965 250.728 ;
     RECT  5.749 251.856 5.965 251.88 ;
     RECT  5.137 283.872 5.965 283.896 ;
     RECT  5.353 138.528 5.969 141.288 ;
     RECT  5.897 72.912 5.989 72.936 ;
     RECT  5.965 194.448 5.989 196.68 ;
     RECT  5.465 292.032 5.996 293.592 ;
     RECT  5.749 294.624 5.996 295.176 ;
     RECT  5.713 77.088 6.001 79.752 ;
     RECT  5.393 52.992 6.005 53.016 ;
     RECT  5.897 70.56 6.037 71.112 ;
     RECT  5.219 132.768 6.037 132.792 ;
     RECT  4.925 156.864 6.037 156.984 ;
     RECT  5.821 189.744 6.037 189.816 ;
     RECT  5.897 263.136 6.037 263.16 ;
     RECT  5.213 16.848 6.041 17.352 ;
     RECT  5.461 2.832 6.044 14.52 ;
     RECT  5.795 103.44 6.073 103.752 ;
     RECT  5.965 165.264 6.073 172.584 ;
     RECT  5.171 225.744 6.073 225.768 ;
     RECT  4.637 226.8 6.073 227.4 ;
     RECT  5.425 256.08 6.073 256.632 ;
     RECT  5.965 283.872 6.073 284.472 ;
     RECT  5.989 72.576 6.076 72.936 ;
     RECT  5.789 274.656 6.076 275.304 ;
     RECT  5.401 296.976 6.077 298.056 ;
     RECT  5.933 49.776 6.083 51.624 ;
     RECT  5.069 18.384 6.085 18.744 ;
     RECT  5.821 192.144 6.085 193.128 ;
     RECT  5.989 194.448 6.085 197.736 ;
     RECT  6.073 164.736 6.113 172.584 ;
     RECT  6.041 17.328 6.131 17.352 ;
     RECT  5.473 278.064 6.131 278.232 ;
     RECT  6.085 18.384 6.181 19.512 ;
     RECT  5.821 20.544 6.181 21.816 ;
     RECT  5.389 87.552 6.181 93.624 ;
     RECT  5.753 126.24 6.181 126.744 ;
     RECT  5.537 254.688 6.181 254.712 ;
     RECT  6.073 255.936 6.181 256.632 ;
     RECT  5.965 151.968 6.185 154.344 ;
     RECT  6.076 274.752 6.185 275.304 ;
     RECT  6.113 171.6 6.193 172.584 ;
     RECT  5.813 129.792 6.217 129.96 ;
     RECT  5.749 131.04 6.217 131.064 ;
     RECT  5.569 187.872 6.217 188.712 ;
     RECT  6.037 189.744 6.217 190.728 ;
     RECT  5.641 199.776 6.217 201.192 ;
     RECT  5.785 229.296 6.217 230.76 ;
     RECT  5.929 258.96 6.217 259.704 ;
     RECT  4.925 260.832 6.217 261.24 ;
     RECT  5.699 288.24 6.217 288.36 ;
     RECT  5.699 57.12 6.221 65.544 ;
     RECT  5.933 75.168 6.221 75.624 ;
     RECT  6.181 18.384 6.227 21.816 ;
     RECT  6.001 77.04 6.227 79.752 ;
     RECT  6.14 253.632 6.227 253.656 ;
     RECT  6.181 254.688 6.227 256.632 ;
     RECT  5.829 142.512 6.229 144.312 ;
     RECT  5.285 83.76 6.253 86.472 ;
     RECT  6.181 87.552 6.253 93.912 ;
     RECT  6.229 142.512 6.253 144.648 ;
     RECT  6.145 145.824 6.253 145.848 ;
     RECT  5.821 23.328 6.257 25.32 ;
     RECT  6.037 70.224 6.257 71.112 ;
     RECT  4.861 215.328 6.257 215.352 ;
     RECT  5.897 40.944 6.275 43.992 ;
     RECT  6.253 142.512 6.275 145.848 ;
     RECT  6.085 192.144 6.275 197.736 ;
     RECT  6.217 129.792 6.277 131.064 ;
     RECT  6.037 132.768 6.277 133.416 ;
     RECT  5.969 138.528 6.277 140.232 ;
     RECT  5.393 216.816 6.277 218.28 ;
     RECT  5.941 219.408 6.277 223.464 ;
     RECT  6.037 262.656 6.277 263.16 ;
     RECT  5.141 183.792 6.289 185.208 ;
     RECT  6.073 283.872 6.289 284.664 ;
     RECT  5.459 236.496 6.293 237.48 ;
     RECT  5.929 66.672 6.323 67.8 ;
     RECT  6.073 102.96 6.323 103.752 ;
     RECT  6.277 138.192 6.323 140.232 ;
     RECT  6.275 192.144 6.323 194.616 ;
     RECT  5.285 134.88 6.325 136.776 ;
     RECT  5.996 292.032 6.325 295.176 ;
     RECT  6.227 18.384 6.329 19.656 ;
     RECT  6.227 78.432 6.329 79.752 ;
     RECT  6.323 103.536 6.329 103.752 ;
     RECT  5.869 106.416 6.329 112.824 ;
     RECT  6.227 255.312 6.329 256.632 ;
     RECT  6.227 21.168 6.361 21.816 ;
     RECT  6.257 23.328 6.361 23.88 ;
     RECT  6.277 129.792 6.361 131.784 ;
     RECT  6.277 132.768 6.361 133.512 ;
     RECT  5.171 180.48 6.361 181.944 ;
     RECT  6.221 59.712 6.365 65.544 ;
     RECT  6.181 126.24 6.365 127.08 ;
     RECT  5.965 246.288 6.365 248.04 ;
     RECT  5.929 147.072 6.397 149.64 ;
     RECT  6.289 183.792 6.397 185.4 ;
     RECT  5.393 186.432 6.397 186.888 ;
     RECT  6.217 187.872 6.397 190.728 ;
     RECT  6.217 199.776 6.397 201.24 ;
     RECT  6.329 106.416 6.419 107.112 ;
     RECT  6.361 129.792 6.419 133.512 ;
     RECT  5.509 116.736 6.421 117 ;
     RECT  6.193 171.936 6.421 172.584 ;
     RECT  4.673 31.296 6.433 32.52 ;
     RECT  5.507 33.792 6.433 34.488 ;
     RECT  6.073 225.744 6.433 227.4 ;
     RECT  6.289 283.872 6.433 285.192 ;
     RECT  6.325 292.032 6.433 295.272 ;
     RECT  6.419 106.512 6.437 107.112 ;
     RECT  5.929 124.752 6.437 124.824 ;
     RECT  5.965 249.936 6.437 251.88 ;
     RECT  6.275 41.616 6.467 43.992 ;
     RECT  6.113 164.736 6.467 170.616 ;
     RECT  6.433 31.296 6.469 34.488 ;
     RECT  6.253 83.76 6.469 93.912 ;
     RECT  4.739 94.896 6.469 95.112 ;
     RECT  6.373 215.76 6.469 215.784 ;
     RECT  6.277 216.816 6.469 223.464 ;
     RECT  6.433 225.744 6.469 227.832 ;
     RECT  5.789 276.48 6.469 276.504 ;
     RECT  6.217 287.664 6.469 288.36 ;
     RECT  5.753 264.48 6.473 264.504 ;
     RECT  6.419 132.192 6.476 133.512 ;
     RECT  6.325 134.64 6.476 136.776 ;
     RECT  5.795 202.8 6.497 203.784 ;
     RECT  6.497 202.8 6.505 203.928 ;
     RECT  5.749 205.056 6.505 210.408 ;
     RECT  6.293 236.544 6.505 237.48 ;
     RECT  6.077 297.552 6.505 298.056 ;
     RECT  6.469 83.76 6.509 95.112 ;
     RECT  6.437 106.512 6.509 107.064 ;
     RECT  5.789 272.448 6.509 273.576 ;
     RECT  6.469 31.296 6.515 34.776 ;
     RECT  6.428 40.176 6.515 40.2 ;
     RECT  5.929 98.64 6.515 101.256 ;
     RECT  6.185 153.12 6.515 154.344 ;
     RECT  6.433 174.288 6.517 174.312 ;
     RECT  5.393 1.728 6.524 1.848 ;
     RECT  6.044 2.832 6.524 15.48 ;
     RECT  6.467 164.736 6.541 169.368 ;
     RECT  6.509 106.512 6.545 106.632 ;
     RECT  5.825 177.456 6.545 179.016 ;
     RECT  6.476 132.192 6.563 136.776 ;
     RECT  6.275 195.84 6.563 197.736 ;
     RECT  6.505 202.8 6.563 210.408 ;
     RECT  6.217 258.96 6.563 261.24 ;
     RECT  6.277 262.32 6.563 263.16 ;
     RECT  6.469 276.48 6.563 276.984 ;
     RECT  6.433 283.392 6.565 285.192 ;
     RECT  6.421 116.64 6.577 117 ;
     RECT  5.171 224.688 6.577 224.712 ;
     RECT  6.469 225.744 6.577 227.928 ;
     RECT  6.217 229.296 6.577 231.816 ;
     RECT  5.573 232.992 6.577 233.016 ;
     RECT  5.5 234.144 6.577 234.216 ;
     RECT  6.437 250.704 6.577 251.88 ;
     RECT  6.433 253.056 6.577 253.08 ;
     RECT  6.329 256.032 6.577 256.632 ;
     RECT  6.467 41.616 6.581 42.456 ;
     RECT  6.467 170.592 6.581 170.616 ;
     RECT  5.897 268.32 6.581 270.888 ;
     RECT  6.515 31.296 6.613 33.288 ;
     RECT  6.509 85.104 6.613 95.112 ;
     RECT  5.465 96.288 6.613 97.56 ;
     RECT  5.749 114 6.613 115.512 ;
     RECT  6.577 116.64 6.613 117.432 ;
     RECT  6.577 229.296 6.613 233.016 ;
     RECT  6.577 234.096 6.613 234.264 ;
     RECT  6.397 279.84 6.613 279.864 ;
     RECT  6.565 282.72 6.613 285.192 ;
     RECT  6.515 99.168 6.617 101.256 ;
     RECT  6.433 292.032 6.641 295.416 ;
     RECT  6.577 224.688 6.649 227.928 ;
     RECT  5.677 243.12 6.649 243.336 ;
     RECT  6.641 292.032 6.649 295.848 ;
     RECT  5.465 0.192 6.653 0.312 ;
     RECT  5.603 122.784 6.653 123.624 ;
     RECT  6.613 85.104 6.659 97.56 ;
     RECT  6.613 114 6.659 117.432 ;
     RECT  6.509 272.64 6.659 273.576 ;
     RECT  6.613 229.296 6.66 234.264 ;
     RECT  5.357 82.656 6.685 82.68 ;
     RECT  6.509 83.76 6.685 83.928 ;
     RECT  5.789 266.832 6.685 266.856 ;
     RECT  6.469 287.472 6.685 288.36 ;
     RECT  6.563 196.992 6.689 197.736 ;
     RECT  6.581 268.32 6.7 269.592 ;
     RECT  6.076 72.912 6.707 72.936 ;
     RECT  6.524 1.728 6.709 15.48 ;
     RECT  6.329 78.912 6.709 79.752 ;
     RECT  6.649 224.688 6.709 228.168 ;
     RECT  6.66 229.296 6.709 234.312 ;
     RECT  5.713 36.48 6.721 36.552 ;
     RECT  6.563 203.424 6.721 210.408 ;
     RECT  6.709 78.912 6.725 79.944 ;
     RECT  6.689 197.088 6.725 197.736 ;
     RECT  6.649 291.936 6.725 295.848 ;
     RECT  5.651 299.28 6.749 299.784 ;
     RECT  5.651 119.088 6.757 119.112 ;
     RECT  5.651 120.192 6.757 120.888 ;
     RECT  6.397 183.648 6.757 185.4 ;
     RECT  6.397 186.432 6.757 190.728 ;
     RECT  6.649 243.072 6.757 243.336 ;
     RECT  6.685 287.472 6.757 288.456 ;
     RECT  6.659 97.296 6.761 97.56 ;
     RECT  6.545 106.512 6.761 106.536 ;
     RECT  6.515 153.504 6.761 154.344 ;
     RECT  6.323 192.144 6.761 194.328 ;
     RECT  6.397 147.072 6.764 149.928 ;
     RECT  6.131 278.112 6.793 278.232 ;
     RECT  6.563 132.192 6.797 133.272 ;
     RECT  6.721 203.424 6.797 210.696 ;
     RECT  6.659 272.64 6.797 273 ;
     RECT  6.563 276.48 6.797 276.504 ;
     RECT  6.541 164.304 6.803 169.368 ;
     RECT  6.365 60.72 6.805 65.544 ;
     RECT  6.323 66.672 6.805 67.752 ;
     RECT  5.609 281.568 6.805 281.592 ;
     RECT  6.613 282.72 6.805 286.104 ;
     RECT  6.221 75.168 6.829 75.432 ;
     RECT  6.725 79.152 6.829 79.944 ;
     RECT  5.853 128.304 6.829 128.328 ;
     RECT  6.419 129.792 6.829 131.064 ;
     RECT  6.361 180.48 6.829 182.424 ;
     RECT  5.617 211.872 6.829 213.096 ;
     RECT  5.605 214.176 6.829 214.2 ;
     RECT  6.469 215.76 6.829 223.464 ;
     RECT  6.709 224.448 6.829 234.312 ;
     RECT  6.757 287.472 6.829 288.552 ;
     RECT  6.365 126.336 6.833 127.08 ;
     RECT  6.749 299.28 6.833 300.12 ;
     RECT  6.833 299.28 6.851 300.024 ;
     RECT  6.685 265.968 6.853 266.856 ;
     RECT  6.805 281.568 6.86 286.104 ;
     RECT  6.329 18.384 6.865 19.512 ;
     RECT  6.217 53.376 6.901 53.976 ;
     RECT  5.939 55.248 6.901 56.04 ;
     RECT  6.227 77.04 6.901 77.112 ;
     RECT  6.685 82.656 6.901 83.928 ;
     RECT  6.185 151.968 6.901 152.088 ;
     RECT  5.789 159.984 6.901 163.128 ;
     RECT  6.803 164.304 6.901 164.808 ;
     RECT  5.825 176.352 6.901 176.472 ;
     RECT  6.545 177.456 6.901 178.728 ;
     RECT  6.797 207.408 6.901 210.696 ;
     RECT  6.829 287.424 6.901 288.552 ;
     RECT  6.757 119.088 6.937 120.888 ;
     RECT  6.275 144.624 6.937 145.848 ;
     RECT  5.699 239.328 6.937 240.696 ;
     RECT  6.083 51.504 6.973 51.624 ;
     RECT  6.937 239.328 6.997 241.128 ;
     RECT  6.659 115.104 7.009 117.432 ;
     RECT  6.937 119.088 7.009 120.936 ;
     RECT  6.709 1.728 7.045 16.248 ;
     RECT  5.869 104.832 7.045 104.856 ;
     RECT  6.764 147.072 7.045 150.456 ;
     RECT  5.897 158.448 7.045 159 ;
     RECT  6.901 159.984 7.045 164.808 ;
     RECT  6.901 287.424 7.045 288.984 ;
     RECT  5.465 289.968 7.045 290.952 ;
     RECT  6.833 126.432 7.081 127.08 ;
     RECT  6.829 128.304 7.081 131.064 ;
     RECT  6.323 140.208 7.081 140.232 ;
     RECT  5.969 141.264 7.081 141.288 ;
     RECT  6.853 265.968 7.081 267.288 ;
     RECT  6.7 268.32 7.081 269.4 ;
     RECT  6.997 239.328 7.093 241.224 ;
     RECT  6.757 242.832 7.093 243.336 ;
     RECT  6.083 49.776 7.117 49.8 ;
     RECT  6.653 122.88 7.117 123.624 ;
     RECT  6.437 124.752 7.117 124.776 ;
     RECT  6.761 192.144 7.117 193.8 ;
     RECT  7.117 49.536 7.141 49.8 ;
     RECT  6.973 51.504 7.141 51.72 ;
     RECT  6.581 270.576 7.141 270.888 ;
     RECT  6.037 38.592 7.153 38.616 ;
     RECT  7.009 115.104 7.153 120.936 ;
     RECT  6.563 134.256 7.153 136.776 ;
     RECT  6.323 138.192 7.153 139.128 ;
     RECT  7.081 140.208 7.153 141.288 ;
     RECT  6.275 142.512 7.153 143.592 ;
     RECT  6.901 176.352 7.189 178.728 ;
     RECT  6.829 211.872 7.189 214.2 ;
     RECT  6.829 215.76 7.189 234.312 ;
     RECT  6.829 235.536 7.189 235.56 ;
     RECT  7.045 147.072 7.225 150.744 ;
     RECT  7.045 1.728 7.237 17.112 ;
     RECT  6.865 18.096 7.237 19.512 ;
     RECT  6.257 24.912 7.261 25.32 ;
     RECT  5.497 26.976 7.261 27.96 ;
     RECT  6.515 34.752 7.261 34.776 ;
     RECT  6.721 36 7.261 37.08 ;
     RECT  6.829 79.152 7.261 80.04 ;
     RECT  6.037 155.808 7.261 156.984 ;
     RECT  6.397 198.864 7.261 201.24 ;
     RECT  7.153 140.208 7.285 143.592 ;
     RECT  6.937 144.624 7.285 145.992 ;
     RECT  5.897 29.664 7.292 29.784 ;
     RECT  6.613 31.248 7.292 33.288 ;
     RECT  6.361 21.168 7.297 23.88 ;
     RECT  6.329 108.144 7.297 112.824 ;
     RECT  6.659 114 7.297 114.024 ;
     RECT  6.517 174.288 7.297 174.648 ;
     RECT  6.653 0.288 7.333 0.312 ;
     RECT  6.829 74.928 7.333 75.432 ;
     RECT  6.901 76.944 7.333 77.112 ;
     RECT  6.329 103.536 7.333 103.56 ;
     RECT  7.225 146.976 7.333 150.744 ;
     RECT  6.829 180 7.333 182.424 ;
     RECT  6.757 183.648 7.333 190.728 ;
     RECT  6.185 275.184 7.333 275.304 ;
     RECT  7.045 287.424 7.333 290.952 ;
     RECT  6.725 291.936 7.333 295.272 ;
     RECT  7.285 140.208 7.369 145.992 ;
     RECT  7.333 146.976 7.369 150.84 ;
     RECT  6.563 195.84 7.369 195.864 ;
     RECT  6.613 279.744 7.369 279.864 ;
     RECT  7.333 0.288 7.379 0.36 ;
     RECT  7.261 79.152 7.405 80.952 ;
     RECT  6.901 81.936 7.405 83.928 ;
     RECT  6.421 171.936 7.405 172.68 ;
     RECT  7.333 180 7.405 190.728 ;
     RECT  7.369 249.12 7.405 249.144 ;
     RECT  7.261 34.752 7.429 37.08 ;
     RECT  7.261 198.864 7.429 201.288 ;
     RECT  6.505 297.552 7.429 298.104 ;
     RECT  6.365 59.712 7.436 59.736 ;
     RECT  6.805 60.72 7.436 67.752 ;
     RECT  7.405 249.12 7.436 249.624 ;
     RECT  6.577 250.704 7.436 253.08 ;
     RECT  6.221 57.12 7.441 58.728 ;
     RECT  7.436 59.712 7.441 67.752 ;
     RECT  7.045 158.448 7.441 164.808 ;
     RECT  6.505 236.544 7.441 237.528 ;
     RECT  6.793 278.112 7.441 278.568 ;
     RECT  7.369 279.552 7.441 279.864 ;
     RECT  6.541 45.456 7.477 45.48 ;
     RECT  7.297 174.048 7.477 174.648 ;
     RECT  7.189 175.68 7.477 178.728 ;
     RECT  7.436 249.12 7.477 253.08 ;
     RECT  6.761 153.504 7.513 154.056 ;
     RECT  5.939 46.8 7.525 48.456 ;
     RECT  6.901 296.4 7.525 296.424 ;
     RECT  7.369 69.216 7.549 69.24 ;
     RECT  6.257 70.224 7.549 70.632 ;
     RECT  6.617 99.744 7.549 101.256 ;
     RECT  7.441 158.352 7.549 164.808 ;
     RECT  7.477 245.232 7.549 245.256 ;
     RECT  7.405 171.84 7.58 172.68 ;
     RECT  7.297 20.64 7.585 23.88 ;
     RECT  7.261 24.912 7.585 27.96 ;
     RECT  7.153 115.104 7.585 121.656 ;
     RECT  7.081 126.432 7.585 131.064 ;
     RECT  6.797 132.192 7.585 133.08 ;
     RECT  6.581 42.192 7.621 42.456 ;
     RECT  7.585 73.872 7.621 73.896 ;
     RECT  7.333 74.928 7.621 77.112 ;
     RECT  7.549 99.744 7.621 101.304 ;
     RECT  7.333 103.536 7.621 103.608 ;
     RECT  7.045 104.832 7.621 105.432 ;
     RECT  6.901 151.824 7.621 152.088 ;
     RECT  7.513 153.264 7.621 154.056 ;
     RECT  7.58 171.84 7.621 172.872 ;
     RECT  7.477 174.048 7.621 178.728 ;
     RECT  6.86 280.992 7.621 286.104 ;
     RECT  6.901 207.408 7.657 210.84 ;
     RECT  7.549 244.56 7.657 245.256 ;
     RECT  6.365 246.288 7.657 247.944 ;
     RECT  7.621 42.192 7.669 42.552 ;
     RECT  6.467 43.968 7.669 43.992 ;
     RECT  7.405 79.152 7.669 83.928 ;
     RECT  6.659 85.104 7.669 95.928 ;
     RECT  7.585 115.104 7.669 121.896 ;
     RECT  7.117 122.88 7.669 124.776 ;
     RECT  7.153 134.256 7.669 139.128 ;
     RECT  7.369 140.208 7.669 150.84 ;
     RECT  7.405 179.952 7.669 190.728 ;
     RECT  7.117 192.048 7.669 193.8 ;
     RECT  7.189 215.76 7.669 235.56 ;
     RECT  7.441 236.544 7.669 238.104 ;
     RECT  7.429 297.552 7.669 298.2 ;
     RECT  6.803 165.84 7.693 169.368 ;
     RECT  7.441 278.112 7.693 279.864 ;
     RECT  7.621 280.992 7.693 286.296 ;
     RECT  7.333 287.424 7.693 295.272 ;
     RECT  7.525 296.4 7.693 296.568 ;
     RECT  7.292 29.664 7.729 33.288 ;
     RECT  6.563 262.656 7.729 263.16 ;
     RECT  7.729 29.664 7.765 33.576 ;
     RECT  7.429 34.752 7.765 37.272 ;
     RECT  6.725 197.232 7.765 197.736 ;
     RECT  7.429 198.816 7.765 201.288 ;
     RECT  7.657 244.56 7.765 247.944 ;
     RECT  7.477 249.12 7.765 253.896 ;
     RECT  7.081 265.968 7.765 269.4 ;
     RECT  7.693 107.04 7.801 107.064 ;
     RECT  7.237 1.728 7.808 19.512 ;
     RECT  7.585 20.64 7.808 27.96 ;
     RECT  7.765 29.664 7.808 37.272 ;
     RECT  7.153 38.592 7.808 38.808 ;
     RECT  7.669 41.712 7.808 42.552 ;
     RECT  7.669 43.632 7.808 43.992 ;
     RECT  7.477 45.408 7.808 45.48 ;
     RECT  7.525 46.704 7.808 48.456 ;
     RECT  7.141 49.536 7.808 52.392 ;
     RECT  6.901 53.376 7.808 56.04 ;
     RECT  7.441 57.12 7.808 67.752 ;
     RECT  7.549 69.216 7.808 70.632 ;
     RECT  7.621 73.872 7.808 77.112 ;
     RECT  7.477 78.096 7.808 78.12 ;
     RECT  7.669 79.152 7.808 95.928 ;
     RECT  6.761 97.296 7.808 97.32 ;
     RECT  7.585 98.736 7.808 98.76 ;
     RECT  7.621 99.744 7.808 101.64 ;
     RECT  7.621 103.536 7.808 105.432 ;
     RECT  7.801 106.56 7.808 107.064 ;
     RECT  7.297 108.144 7.808 114.024 ;
     RECT  7.669 115.104 7.808 124.776 ;
     RECT  7.585 126.432 7.808 133.08 ;
     RECT  7.669 134.256 7.808 150.84 ;
     RECT  7.621 151.824 7.808 154.056 ;
     RECT  7.261 155.328 7.808 156.984 ;
     RECT  7.549 158.304 7.808 164.808 ;
     RECT  7.693 165.84 7.808 169.656 ;
     RECT  7.621 171.84 7.808 178.728 ;
     RECT  7.669 179.952 7.808 193.8 ;
     RECT  7.369 195.264 7.808 195.864 ;
     RECT  7.765 197.232 7.808 201.288 ;
     RECT  7.573 202.32 7.808 202.344 ;
     RECT  6.797 203.424 7.808 206.28 ;
     RECT  7.657 207.408 7.808 210.888 ;
     RECT  7.189 211.872 7.808 214.296 ;
     RECT  7.669 215.76 7.808 238.104 ;
     RECT  7.093 239.328 7.808 243.336 ;
     RECT  7.765 244.56 7.808 253.896 ;
     RECT  6.577 256.032 7.808 257.064 ;
     RECT  6.937 258.192 7.808 258.216 ;
     RECT  6.563 259.632 7.808 261.24 ;
     RECT  7.729 262.608 7.808 263.16 ;
     RECT  6.853 264.24 7.808 264.264 ;
     RECT  7.765 265.968 7.808 269.544 ;
     RECT  7.141 270.576 7.808 271.56 ;
     RECT  6.797 272.832 7.808 273 ;
     RECT  7.333 274.224 7.808 275.304 ;
     RECT  7.693 278.112 7.808 286.296 ;
     RECT  7.693 287.424 7.808 296.568 ;
     RECT  7.669 297.552 7.808 298.248 ;
     RECT  7.808 1.728 7.859 298.248 ;
     RECT  7.859 1.728 8.104 298.2 ;
     RECT  8.104 258.192 8.129 265.032 ;
     RECT  8.104 61.296 8.165 70.824 ;
     RECT  8.104 83.76 8.165 84.36 ;
     RECT  7.379 0.336 8.197 0.36 ;
     RECT  8.104 1.728 8.197 7.464 ;
     RECT  8.104 129.84 8.201 154.008 ;
     RECT  8.104 208.08 8.201 210.312 ;
     RECT  8.104 251.136 8.201 254.424 ;
     RECT  8.104 78.096 8.237 80.952 ;
     RECT  8.104 118.128 8.237 122.664 ;
     RECT  8.104 29.76 8.243 43.896 ;
     RECT  8.104 45.456 8.243 47.928 ;
     RECT  8.165 63.072 8.243 70.824 ;
     RECT  8.237 121.968 8.243 122.664 ;
     RECT  8.201 142.512 8.243 154.008 ;
     RECT  8.104 155.088 8.243 170.904 ;
     RECT  8.104 211.872 8.243 214.296 ;
     RECT  8.104 228.336 8.243 232.776 ;
     RECT  8.104 283.248 8.243 285.384 ;
     RECT  8.104 123.648 8.273 128.376 ;
     RECT  8.243 155.088 8.273 167.016 ;
     RECT  8.243 148.032 8.281 154.008 ;
     RECT  8.243 45.552 8.284 47.928 ;
     RECT  8.284 46.128 8.291 47.928 ;
     RECT  8.104 54.624 8.291 55.032 ;
     RECT  8.104 218.784 8.291 220.008 ;
     RECT  8.104 221.04 8.291 227.208 ;
     RECT  8.104 52.56 8.309 53.304 ;
     RECT  8.104 103.2 8.309 114.024 ;
     RECT  8.243 142.512 8.309 147.048 ;
     RECT  8.104 236.016 8.309 236.904 ;
     RECT  8.129 259.776 8.339 265.032 ;
     RECT  8.104 266.736 8.339 275.736 ;
     RECT  8.243 213.168 8.345 214.296 ;
     RECT  8.339 266.736 8.353 273.048 ;
     RECT  8.104 23.952 8.381 27.96 ;
     RECT  8.104 190.464 8.381 206.52 ;
     RECT  8.309 107.568 8.387 114.024 ;
     RECT  8.353 268.992 8.387 273.048 ;
     RECT  8.104 286.704 8.387 298.2 ;
     RECT  8.104 57.12 8.417 59.976 ;
     RECT  8.104 72.144 8.417 72.408 ;
     RECT  8.387 286.704 8.425 298.104 ;
     RECT  8.381 191.904 8.453 206.52 ;
     RECT  8.104 14.64 8.489 22.584 ;
     RECT  8.104 77.04 8.489 77.112 ;
     RECT  8.339 259.776 8.525 264.216 ;
     RECT  8.104 48.96 8.531 51.432 ;
     RECT  8.201 129.84 8.531 141.336 ;
     RECT  8.417 58.656 8.561 59.976 ;
     RECT  8.243 63.072 8.561 69.24 ;
     RECT  8.273 155.088 8.561 166.248 ;
     RECT  8.453 191.904 8.561 199.992 ;
     RECT  8.425 286.704 8.561 297.576 ;
     RECT  8.489 14.64 8.579 18.072 ;
     RECT  8.489 19.344 8.579 22.584 ;
     RECT  8.273 123.648 8.579 128.28 ;
     RECT  8.243 285.312 8.579 285.384 ;
     RECT  8.381 23.952 8.597 27.912 ;
     RECT  8.561 63.072 8.597 65.256 ;
     RECT  8.579 127.68 8.597 128.28 ;
     RECT  8.104 239.04 8.597 249.96 ;
     RECT  8.597 239.04 8.62 247.56 ;
     RECT  8.597 127.68 8.627 127.992 ;
     RECT  8.417 57.12 8.633 57.672 ;
     RECT  8.281 149.472 8.633 154.008 ;
     RECT  8.387 268.992 8.633 270.168 ;
     RECT  8.243 29.76 8.669 35.592 ;
     RECT  8.597 63.072 8.669 65.016 ;
     RECT  8.561 155.088 8.669 163.512 ;
     RECT  8.291 47.856 8.675 47.88 ;
     RECT  8.243 122.448 8.675 122.664 ;
     RECT  8.243 228.72 8.675 232.776 ;
     RECT  8.62 239.04 8.675 247.416 ;
     RECT  8.561 66.528 8.705 69.24 ;
     RECT  8.597 248.544 8.705 249.96 ;
     RECT  8.561 286.704 8.705 290.712 ;
     RECT  8.579 16.848 8.723 18.072 ;
     RECT  8.339 274.224 8.723 275.736 ;
     RECT  8.579 14.64 8.741 15.432 ;
     RECT  8.417 72.384 8.741 72.408 ;
     RECT  8.104 73.872 8.741 75.432 ;
     RECT  8.353 266.736 8.741 267.816 ;
     RECT  8.579 19.344 8.769 19.368 ;
     RECT  8.675 122.448 8.771 122.568 ;
     RECT  8.669 155.088 8.771 159.192 ;
     RECT  8.243 70.368 8.777 70.824 ;
     RECT  8.561 291.792 8.777 297.576 ;
     RECT  8.525 261.024 8.785 264.216 ;
     RECT  8.705 287.184 8.785 290.712 ;
     RECT  8.771 155.088 8.812 157.176 ;
     RECT  8.741 14.688 8.813 15.432 ;
     RECT  8.669 29.76 8.813 32.52 ;
     RECT  8.104 82.128 8.813 82.488 ;
     RECT  8.291 221.184 8.813 227.208 ;
     RECT  8.129 258.192 8.813 258.792 ;
     RECT  8.201 251.136 8.819 253.08 ;
     RECT  6.851 299.28 8.821 299.304 ;
     RECT  8.531 136.08 8.849 141.336 ;
     RECT  8.813 221.184 8.849 223.704 ;
     RECT  8.243 283.248 8.867 284.088 ;
     RECT  8.561 58.704 8.915 59.976 ;
     RECT  8.813 258.192 8.915 258.648 ;
     RECT  8.915 58.704 8.921 59.256 ;
     RECT  8.237 118.128 8.921 120.84 ;
     RECT  8.579 125.04 8.921 125.064 ;
     RECT  8.243 36.816 8.957 40.344 ;
     RECT  8.849 136.128 8.957 141.336 ;
     RECT  8.309 103.2 8.993 106.584 ;
     RECT  8.675 228.72 9.011 232.536 ;
     RECT  8.197 0.336 9.013 7.464 ;
     RECT  8.597 24.528 9.029 27.912 ;
     RECT  8.237 79.68 9.059 80.952 ;
     RECT  8.201 254.4 9.059 254.424 ;
     RECT  8.669 33.552 9.065 35.592 ;
     RECT  8.104 95.952 9.065 102.024 ;
     RECT  8.771 122.448 9.065 122.472 ;
     RECT  8.531 129.84 9.065 135.048 ;
     RECT  8.525 259.776 9.065 259.848 ;
     RECT  8.387 271.44 9.065 273.048 ;
     RECT  9.013 0.192 9.097 7.464 ;
     RECT  8.104 8.496 9.097 13.32 ;
     RECT  8.104 87.264 9.097 89.928 ;
     RECT  8.104 91.008 9.097 92.856 ;
     RECT  8.387 111.024 9.097 114.024 ;
     RECT  8.104 115.056 9.097 117.144 ;
     RECT  8.104 233.808 9.097 234.312 ;
     RECT  8.867 283.248 9.097 283.56 ;
     RECT  8.821 299.28 9.097 299.352 ;
     RECT  8.957 36.816 9.101 38.808 ;
     RECT  8.579 123.648 9.101 123.672 ;
     RECT  8.819 251.136 9.101 252.504 ;
     RECT  9.097 87.264 9.107 92.856 ;
     RECT  9.101 251.136 9.107 251.736 ;
     RECT  8.104 85.44 9.109 85.992 ;
     RECT  9.097 233.712 9.133 234.312 ;
     RECT  8.104 277.152 9.133 281.496 ;
     RECT  9.097 282.672 9.133 283.56 ;
     RECT  9.029 24.528 9.137 26.376 ;
     RECT  8.165 61.296 9.137 62.088 ;
     RECT  9.065 134.064 9.137 135.048 ;
     RECT  8.104 172.32 9.137 189.48 ;
     RECT  8.104 216.432 9.137 217.752 ;
     RECT  9.133 277.152 9.137 283.56 ;
     RECT  8.669 63.696 9.155 65.016 ;
     RECT  9.109 80.976 9.157 81 ;
     RECT  8.165 83.76 9.157 83.784 ;
     RECT  9.109 84.864 9.157 85.992 ;
     RECT  8.201 210.144 9.164 210.312 ;
     RECT  8.633 57.12 9.169 57.144 ;
     RECT  9.137 61.68 9.169 62.088 ;
     RECT  9.097 111.024 9.169 117.144 ;
     RECT  8.921 118.128 9.169 118.68 ;
     RECT  8.243 41.376 9.173 43.896 ;
     RECT  9.169 111.024 9.173 118.68 ;
     RECT  8.633 149.664 9.173 154.008 ;
     RECT  8.561 164.592 9.173 166.248 ;
     RECT  8.777 291.792 9.173 295.704 ;
     RECT  9.173 41.376 9.203 43.32 ;
     RECT  8.813 82.128 9.203 82.44 ;
     RECT  8.104 93.888 9.205 94.68 ;
     RECT  8.309 142.512 9.205 147 ;
     RECT  8.345 213.6 9.205 214.296 ;
     RECT  9.097 215.424 9.205 215.448 ;
     RECT  8.531 51.12 9.209 51.432 ;
     RECT  9.173 111.36 9.209 118.68 ;
     RECT  9.065 271.68 9.209 273.048 ;
     RECT  9.137 279.504 9.209 283.56 ;
     RECT  9.209 272.496 9.245 273.048 ;
     RECT  9.137 277.152 9.245 278.232 ;
     RECT  8.705 66.72 9.251 69.24 ;
     RECT  9.205 213.6 9.251 215.448 ;
     RECT  8.813 224.688 9.251 227.208 ;
     RECT  9.097 299.28 9.251 299.4 ;
     RECT  9.205 142.464 9.28 147 ;
     RECT  8.531 49.008 9.281 50.136 ;
     RECT  8.561 196.656 9.281 199.992 ;
     RECT  9.251 67.2 9.299 69.24 ;
     RECT  9.097 0.192 9.313 13.32 ;
     RECT  8.291 46.128 9.313 46.632 ;
     RECT  8.291 55.008 9.313 55.032 ;
     RECT  9.251 299.28 9.317 299.352 ;
     RECT  8.243 168.288 9.349 170.904 ;
     RECT  8.453 201.264 9.349 206.52 ;
     RECT  8.309 236.016 9.349 236.664 ;
     RECT  9.137 172.32 9.353 177.816 ;
     RECT  9.251 213.936 9.353 214.968 ;
     RECT  9.173 153.216 9.385 154.008 ;
     RECT  8.812 155.088 9.385 156.984 ;
     RECT  8.785 262.224 9.385 264.216 ;
     RECT  9.313 0.192 9.389 13.608 ;
     RECT  9.353 174.288 9.389 177.816 ;
     RECT  8.777 296.976 9.389 297.576 ;
     RECT  9.281 198.48 9.395 199.992 ;
     RECT  9.299 67.776 9.397 69.24 ;
     RECT  9.349 168.288 9.404 171.096 ;
     RECT  8.993 103.2 9.421 104.04 ;
     RECT  9.349 201.264 9.421 207.096 ;
     RECT  8.201 208.08 9.421 209.112 ;
     RECT  8.291 219.408 9.421 220.008 ;
     RECT  9.251 226.848 9.421 227.208 ;
     RECT  9.281 49.728 9.425 50.136 ;
     RECT  9.065 95.952 9.425 101.496 ;
     RECT  9.356 70.944 9.443 70.968 ;
     RECT  9.157 80.976 9.443 81.096 ;
     RECT  8.849 221.184 9.443 222.216 ;
     RECT  8.741 74.304 9.445 75.432 ;
     RECT  9.173 164.736 9.445 166.248 ;
     RECT  9.404 167.856 9.445 171.096 ;
     RECT  9.353 172.32 9.445 173.016 ;
     RECT  9.389 297.552 9.445 297.576 ;
     RECT  8.579 21.072 9.457 22.584 ;
     RECT  8.309 53.232 9.457 53.304 ;
     RECT  9.313 55.008 9.457 55.512 ;
     RECT  8.921 119.76 9.457 120.84 ;
     RECT  9.137 178.8 9.457 189.48 ;
     RECT  8.381 190.464 9.457 190.872 ;
     RECT  9.421 226.848 9.457 227.4 ;
     RECT  9.011 228.72 9.457 231.768 ;
     RECT  9.389 0.192 9.461 9.096 ;
     RECT  9.209 51.408 9.493 51.432 ;
     RECT  9.065 259.824 9.493 259.848 ;
     RECT  8.785 261.024 9.493 261.24 ;
     RECT  9.245 272.832 9.493 273.048 ;
     RECT  8.723 274.224 9.493 275.304 ;
     RECT  9.101 38.208 9.494 38.808 ;
     RECT  9.457 226.848 9.497 231.768 ;
     RECT  9.457 21.072 9.5 22.68 ;
     RECT  9.457 178.8 9.533 190.872 ;
     RECT  9.251 224.688 9.533 225.816 ;
     RECT  9.493 259.824 9.533 261.24 ;
     RECT  9.5 21.072 9.541 22.728 ;
     RECT  9.493 51.408 9.541 51.912 ;
     RECT  8.579 126.576 9.541 126.696 ;
     RECT  8.627 127.68 9.541 127.8 ;
     RECT  9.349 236.016 9.557 237.528 ;
     RECT  8.675 239.04 9.557 244.296 ;
     RECT  9.457 53.232 9.565 55.512 ;
     RECT  9.169 57.024 9.565 57.144 ;
     RECT  9.245 277.152 9.565 278.184 ;
     RECT  8.957 137.904 9.569 141.336 ;
     RECT  9.445 164.736 9.569 171.096 ;
     RECT  9.389 174.48 9.587 177.816 ;
     RECT  9.421 201.264 9.587 209.112 ;
     RECT  8.561 191.904 9.589 195.528 ;
     RECT  9.281 196.656 9.589 197.496 ;
     RECT  9.029 27.36 9.596 27.912 ;
     RECT  8.921 58.704 9.596 58.776 ;
     RECT  9.395 198.816 9.596 199.992 ;
     RECT  9.587 201.264 9.596 207.096 ;
     RECT  9.205 93.888 9.601 94.824 ;
     RECT  9.425 95.952 9.601 101.256 ;
     RECT  9.137 216.48 9.601 217.752 ;
     RECT  9.421 219.264 9.601 220.008 ;
     RECT  9.169 61.68 9.605 62.424 ;
     RECT  9.397 67.776 9.605 69.864 ;
     RECT  9.107 87.36 9.605 92.856 ;
     RECT  8.675 245.52 9.605 247.416 ;
     RECT  8.741 266.736 9.605 267.24 ;
     RECT  9.317 299.328 9.605 299.352 ;
     RECT  9.157 83.76 9.635 85.992 ;
     RECT  9.533 181.872 9.635 190.872 ;
     RECT  9.596 27.36 9.637 28.44 ;
     RECT  9.601 29.616 9.637 29.64 ;
     RECT  9.565 53.232 9.637 55.896 ;
     RECT  9.565 56.976 9.637 57.144 ;
     RECT  9.596 58.368 9.637 58.776 ;
     RECT  9.605 87.648 9.637 92.856 ;
     RECT  9.601 93.888 9.637 101.256 ;
     RECT  8.771 159.168 9.637 159.192 ;
     RECT  9.587 208.08 9.637 209.112 ;
     RECT  9.385 262.224 9.637 264.264 ;
     RECT  9.637 87.648 9.641 101.256 ;
     RECT  9.557 236.016 9.641 244.296 ;
     RECT  8.785 287.28 9.665 290.712 ;
     RECT  9.173 291.792 9.665 295.08 ;
     RECT  8.993 105.12 9.673 106.584 ;
     RECT  8.387 107.568 9.673 110.04 ;
     RECT  9.065 129.84 9.673 133.08 ;
     RECT  9.28 142.464 9.673 147.048 ;
     RECT  8.281 148.032 9.673 148.056 ;
     RECT  9.635 184.08 9.673 190.872 ;
     RECT  9.589 191.904 9.673 197.496 ;
     RECT  8.705 248.544 9.673 249.288 ;
     RECT  9.641 238.848 9.676 244.296 ;
     RECT  9.541 51.408 9.677 52.008 ;
     RECT  9.533 178.8 9.677 180.744 ;
     RECT  9.605 245.856 9.677 247.416 ;
     RECT  9.637 27.36 9.683 29.64 ;
     RECT  9.676 240.336 9.683 244.296 ;
     RECT  8.813 30.768 9.685 32.52 ;
     RECT  9.065 33.552 9.685 34.632 ;
     RECT  9.445 74.304 9.685 75.576 ;
     RECT  9.601 216.48 9.709 220.008 ;
     RECT  9.425 49.776 9.713 50.136 ;
     RECT  9.641 87.648 9.713 100.2 ;
     RECT  9.569 164.736 9.713 170.28 ;
     RECT  9.637 208.08 9.713 209.16 ;
     RECT  9.353 214.176 9.713 214.968 ;
     RECT  9.641 236.016 9.713 237.816 ;
     RECT  9.713 236.592 9.724 237.816 ;
     RECT  9.673 184.08 9.731 197.496 ;
     RECT  9.389 10.272 9.745 13.608 ;
     RECT  8.813 14.688 9.745 15.288 ;
     RECT  8.723 16.848 9.745 17.832 ;
     RECT  9.605 62.064 9.745 62.424 ;
     RECT  9.155 63.696 9.745 64.872 ;
     RECT  9.164 210.144 9.745 210.552 ;
     RECT  8.243 211.872 9.745 211.896 ;
     RECT  9.673 142.464 9.749 148.056 ;
     RECT  9.709 216.48 9.749 220.632 ;
     RECT  9.313 46.128 9.781 46.872 ;
     RECT  8.633 268.992 9.781 269.016 ;
     RECT  9.745 16.848 9.785 18.696 ;
     RECT  9.683 28.992 9.785 29.64 ;
     RECT  9.605 67.776 9.785 69.288 ;
     RECT  9.421 102.576 9.785 104.04 ;
     RECT  9.724 236.592 9.785 237.528 ;
     RECT  9.677 245.856 9.785 246.264 ;
     RECT  9.685 30.768 9.817 34.632 ;
     RECT  8.489 77.088 9.817 77.112 ;
     RECT  8.237 78.096 9.817 78.696 ;
     RECT  9.713 87.648 9.821 98.328 ;
     RECT  9.173 149.664 9.821 151.656 ;
     RECT  9.683 241.152 9.821 244.296 ;
     RECT  9.203 41.376 9.827 42.744 ;
     RECT  9.677 178.8 9.827 180.696 ;
     RECT  9.637 262.224 9.829 264.552 ;
     RECT  9.745 10.272 9.853 15.288 ;
     RECT  9.821 243.36 9.853 244.296 ;
     RECT  9.565 44.64 9.857 44.664 ;
     RECT  9.637 56.976 9.857 58.776 ;
     RECT  9.209 279.648 9.884 283.56 ;
     RECT  9.857 57.84 9.889 58.776 ;
     RECT  9.685 74.304 9.889 75.816 ;
     RECT  9.731 184.08 9.893 196.104 ;
     RECT  9.745 62.064 9.923 64.872 ;
     RECT  9.673 128.88 9.923 133.08 ;
     RECT  9.827 178.8 9.923 180.504 ;
     RECT  9.349 72.528 9.925 72.552 ;
     RECT  9.637 159.168 9.925 159.24 ;
     RECT  8.104 255.984 9.925 257.112 ;
     RECT  8.915 258.24 9.925 258.648 ;
     RECT  9.925 72.384 9.961 72.552 ;
     RECT  9.493 272.832 9.961 275.304 ;
     RECT  9.565 277.008 9.961 278.184 ;
     RECT  9.785 237.12 9.962 237.528 ;
     RECT  9.133 233.712 9.965 234.36 ;
     RECT  9.749 219.264 9.971 220.632 ;
     RECT  9.884 279.648 9.971 283.848 ;
     RECT  9.637 52.992 9.997 55.944 ;
     RECT  9.961 72.048 9.997 72.552 ;
     RECT  9.203 82.416 9.997 82.44 ;
     RECT  9.785 103.2 9.997 104.04 ;
     RECT  9.673 105.12 9.997 110.04 ;
     RECT  9.677 247.248 9.997 247.416 ;
     RECT  9.673 248.544 9.997 249.384 ;
     RECT  9.677 51.408 10.001 51.576 ;
     RECT  9.889 57.84 10.001 59.112 ;
     RECT  9.635 85.92 10.001 85.992 ;
     RECT  9.749 142.464 10.001 146.04 ;
     RECT  9.596 198.816 10.001 207.096 ;
     RECT  9.137 24.864 10.028 26.376 ;
     RECT  9.683 27.36 10.028 27.912 ;
     RECT  9.829 263.28 10.028 264.552 ;
     RECT  9.781 268.32 10.028 269.016 ;
     RECT  8.633 270.096 10.028 270.168 ;
     RECT  8.957 39.888 10.033 39.912 ;
     RECT  9.827 41.376 10.033 42.216 ;
     RECT  9.745 210.144 10.033 211.896 ;
     RECT  9.925 255.984 10.033 258.648 ;
     RECT  9.457 119.76 10.037 121.416 ;
     RECT  9.821 241.152 10.037 242.328 ;
     RECT  9.889 122.88 10.069 122.904 ;
     RECT  9.541 126.576 10.069 127.8 ;
     RECT  9.443 221.76 10.069 222.216 ;
     RECT  9.605 266.736 10.069 266.76 ;
     RECT  10.028 268.32 10.069 270.168 ;
     RECT  9.997 71.952 10.105 72.552 ;
     RECT  9.889 73.728 10.105 75.816 ;
     RECT  9.923 178.848 10.109 180.504 ;
     RECT  9.965 233.712 10.109 234.216 ;
     RECT  9.961 272.832 10.109 278.184 ;
     RECT  9.541 20.976 10.115 22.728 ;
     RECT  10.069 221.76 10.115 222.264 ;
     RECT  10.028 263.28 10.115 264.984 ;
     RECT  10.069 266.16 10.115 266.76 ;
     RECT  9.781 45.696 10.133 46.872 ;
     RECT  9.821 87.648 10.145 96.6 ;
     RECT  9.713 208.224 10.145 209.16 ;
     RECT  10.069 23.808 10.156 23.832 ;
     RECT  10.115 266.16 10.156 266.184 ;
     RECT  10.069 126.528 10.165 127.8 ;
     RECT  10.069 79.728 10.177 79.992 ;
     RECT  8.669 160.704 10.177 163.512 ;
     RECT  10.141 235.344 10.177 235.368 ;
     RECT  9.107 251.376 10.177 251.736 ;
     RECT  10.069 268.032 10.177 270.216 ;
     RECT  10.145 87.648 10.181 96.504 ;
     RECT  9.821 149.664 10.181 151.08 ;
     RECT  9.461 1.728 10.204 9.096 ;
     RECT  10.033 39.888 10.211 42.216 ;
     RECT  10.109 233.712 10.211 233.736 ;
     RECT  8.579 285.36 10.211 285.384 ;
     RECT  10.177 79.68 10.213 79.992 ;
     RECT  9.443 80.976 10.213 81 ;
     RECT  10.069 122.544 10.213 122.904 ;
     RECT  9.971 279.648 10.213 283.656 ;
     RECT  10.133 45.696 10.217 47.352 ;
     RECT  10.001 58.608 10.217 59.112 ;
     RECT  9.385 153.216 10.217 156.984 ;
     RECT  9.445 172.08 10.217 173.016 ;
     RECT  9.893 190.416 10.217 196.104 ;
     RECT  10.145 208.896 10.241 209.16 ;
     RECT  10.033 210.144 10.241 212.424 ;
     RECT  10.165 43.296 10.249 43.32 ;
     RECT  9.713 164.736 10.249 169.704 ;
     RECT  9.587 175.104 10.249 177.816 ;
     RECT  9.445 297.552 10.249 298.056 ;
     RECT  10.213 279.552 10.252 283.656 ;
     RECT  9.817 30.576 10.253 34.632 ;
     RECT  10.211 39.888 10.253 41.016 ;
     RECT  9.877 296.4 10.259 296.424 ;
     RECT  9.997 82.416 10.261 82.68 ;
     RECT  9.635 83.76 10.261 84.744 ;
     RECT  9.209 111.792 10.261 118.68 ;
     RECT  8.957 136.128 10.261 136.824 ;
     RECT  9.569 137.904 10.261 140.232 ;
     RECT  9.569 141.312 10.261 141.336 ;
     RECT  10.001 142.464 10.261 145.848 ;
     RECT  10.241 208.896 10.261 212.424 ;
     RECT  8.849 223.632 10.261 223.704 ;
     RECT  9.533 225.024 10.261 225.816 ;
     RECT  9.497 226.848 10.261 230.76 ;
     RECT  9.494 38.256 10.285 38.808 ;
     RECT  10.253 39.888 10.285 40.728 ;
     RECT  9.745 125.424 10.285 125.448 ;
     RECT  10.028 24.864 10.289 27.912 ;
     RECT  10.181 87.792 10.289 96.504 ;
     RECT  10.177 160.704 10.289 163.608 ;
     RECT  10.249 164.688 10.289 169.704 ;
     RECT  10.211 42.192 10.297 42.216 ;
     RECT  10.261 82.032 10.307 84.744 ;
     RECT  9.925 159.168 10.309 159.672 ;
     RECT  10.289 164.688 10.309 169.464 ;
     RECT  9.497 231.744 10.316 231.768 ;
     RECT  10.177 268.032 10.316 270.408 ;
     RECT  9.692 36.192 10.321 36.216 ;
     RECT  10.289 91.392 10.325 96.504 ;
     RECT  10.261 208.896 10.325 212.52 ;
     RECT  9.853 243.36 10.325 244.776 ;
     RECT  10.253 34.224 10.333 34.632 ;
     RECT  10.249 152.16 10.333 152.184 ;
     RECT  10.037 119.76 10.357 121.272 ;
     RECT  10.165 126.432 10.357 127.8 ;
     RECT  10.115 221.808 10.357 222.264 ;
     RECT  10.177 250.512 10.357 251.736 ;
     RECT  10.316 268.032 10.357 270.744 ;
     RECT  9.665 287.28 10.357 295.08 ;
     RECT  9.461 0.192 10.361 0.552 ;
     RECT  9.893 184.08 10.361 189.432 ;
     RECT  10.289 24.864 10.393 27.096 ;
     RECT  10.213 122.544 10.393 123.432 ;
     RECT  10.285 124.704 10.393 125.448 ;
     RECT  10.357 126.432 10.393 127.848 ;
     RECT  10.357 221.808 10.393 222.408 ;
     RECT  10.261 223.632 10.393 223.8 ;
     RECT  10.357 119.664 10.397 121.272 ;
     RECT  9.137 134.064 10.397 134.904 ;
     RECT  9.853 10.272 10.403 15.864 ;
     RECT  9.785 18.672 10.403 18.696 ;
     RECT  10.316 19.728 10.403 19.752 ;
     RECT  10.357 268.032 10.403 271.56 ;
     RECT  10.204 6.72 10.405 9.096 ;
     RECT  10.217 153.216 10.405 155.112 ;
     RECT  10.393 122.544 10.412 123.48 ;
     RECT  10.393 124.704 10.412 127.848 ;
     RECT  10.405 6.72 10.429 9.144 ;
     RECT  10.403 10.272 10.429 15.384 ;
     RECT  10.429 6.72 10.433 15.384 ;
     RECT  10.261 86.544 10.433 86.664 ;
     RECT  10.217 190.416 10.451 194.568 ;
     RECT  10.397 134.256 10.453 134.904 ;
     RECT  9.997 247.248 10.46 249.384 ;
     RECT  10.357 250.512 10.46 252.6 ;
     RECT  10.309 158.544 10.465 159.672 ;
     RECT  10.289 160.704 10.465 163.512 ;
     RECT  10.309 164.592 10.465 169.464 ;
     RECT  10.316 231.744 10.465 232.536 ;
     RECT  10.181 150.48 10.469 151.08 ;
     RECT  9.971 219.456 10.469 220.632 ;
     RECT  10.261 136.128 10.499 140.232 ;
     RECT  10.249 297.552 10.499 298.152 ;
     RECT  10.105 71.952 10.501 75.816 ;
     RECT  9.817 77.088 10.501 78.696 ;
     RECT  10.393 221.808 10.501 223.8 ;
     RECT  10.261 225.024 10.501 230.76 ;
     RECT  10.289 87.792 10.505 90.072 ;
     RECT  10.325 91.392 10.505 91.8 ;
     RECT  10.451 190.416 10.505 191.496 ;
     RECT  10.453 134.256 10.541 134.952 ;
     RECT  10.109 272.832 10.541 277.032 ;
     RECT  10.46 247.248 10.547 252.6 ;
     RECT  9.997 103.2 10.556 110.04 ;
     RECT  9.961 48.432 10.565 48.456 ;
     RECT  9.713 49.776 10.565 49.8 ;
     RECT  9.641 101.232 10.573 101.256 ;
     RECT  10.217 172.704 10.573 173.016 ;
     RECT  10.465 164.544 10.577 169.464 ;
     RECT  10.252 282.336 10.577 283.656 ;
     RECT  10.217 45.696 10.609 46.728 ;
     RECT  10.501 71.952 10.609 78.696 ;
     RECT  10.033 255.696 10.609 258.648 ;
     RECT  10.541 134.256 10.613 134.904 ;
     RECT  10.405 152.592 10.613 155.112 ;
     RECT  10.249 175.104 10.613 177.864 ;
     RECT  10.501 221.808 10.613 230.76 ;
     RECT  10.547 250.512 10.613 252.6 ;
     RECT  10.609 255.696 10.613 259.176 ;
     RECT  10.565 48.432 10.643 49.8 ;
     RECT  10.556 103.2 10.643 110.184 ;
     RECT  10.465 231.744 10.643 233.208 ;
     RECT  10.465 158.544 10.645 163.512 ;
     RECT  10.613 258.192 10.645 259.176 ;
     RECT  10.613 223.392 10.649 230.76 ;
     RECT  10.037 241.248 10.649 242.328 ;
     RECT  10.325 243.6 10.649 244.776 ;
     RECT  10.217 156.288 10.681 156.984 ;
     RECT  10.403 271.536 10.681 271.56 ;
     RECT  10.541 272.832 10.681 276.984 ;
     RECT  10.217 196.08 10.717 196.104 ;
     RECT  9.731 197.088 10.717 197.496 ;
     RECT  9.676 238.848 10.717 239.16 ;
     RECT  10.403 268.032 10.721 270.408 ;
     RECT  10.361 0.192 10.729 0.216 ;
     RECT  10.645 258.192 10.741 259.368 ;
     RECT  9.533 260.4 10.741 261.24 ;
     RECT  10.465 60.912 10.748 60.936 ;
     RECT  9.923 62.064 10.748 63.72 ;
     RECT  9.749 216.48 10.748 217.704 ;
     RECT  10.609 71.904 10.753 78.696 ;
     RECT  10.177 235.2 10.753 235.368 ;
     RECT  10.357 287.28 10.753 295.272 ;
     RECT  10.325 92.88 10.757 96.504 ;
     RECT  10.753 235.2 10.757 236.088 ;
     RECT  10.649 243.648 10.757 244.776 ;
     RECT  9.785 28.992 10.789 29.352 ;
     RECT  9.749 147.024 10.789 148.056 ;
     RECT  10.613 175.104 10.789 175.32 ;
     RECT  10.325 210.144 10.789 212.52 ;
     RECT  9.713 214.176 10.789 214.2 ;
     RECT  10.204 1.728 10.793 5.736 ;
     RECT  10.321 35.76 10.825 36.216 ;
     RECT  9.101 37.2 10.825 37.224 ;
     RECT  9.923 64.704 10.825 64.872 ;
     RECT  9.997 66.048 10.825 66.072 ;
     RECT  10.753 71.664 10.825 78.696 ;
     RECT  10.213 79.68 10.825 81 ;
     RECT  10.645 158.496 10.825 163.512 ;
     RECT  9.635 181.872 10.825 182.952 ;
     RECT  10.361 184.08 10.825 184.68 ;
     RECT  10.789 210.144 10.825 214.2 ;
     RECT  10.748 215.184 10.825 217.704 ;
     RECT  10.741 258.192 10.828 261.24 ;
     RECT  10.253 30.576 10.829 33.096 ;
     RECT  10.412 122.544 10.829 127.848 ;
     RECT  10.748 60.912 10.835 63.72 ;
     RECT  10.261 111.168 10.835 118.68 ;
     RECT  10.825 210.144 10.835 217.704 ;
     RECT  10.649 225.024 10.835 230.76 ;
     RECT  10.828 258.192 10.835 259.368 ;
     RECT  10.753 287.28 10.837 295.368 ;
     RECT  10.825 71.664 10.844 81 ;
     RECT  10.307 82.032 10.844 84.024 ;
     RECT  10.835 114.48 10.861 118.68 ;
     RECT  10.397 119.664 10.861 121.128 ;
     RECT  10.757 243.744 10.861 244.776 ;
     RECT  9.785 245.856 10.861 246.216 ;
     RECT  10.829 30.576 10.865 31.944 ;
     RECT  9.997 52.992 10.865 56.232 ;
     RECT  10.573 101.232 10.865 102.12 ;
     RECT  10.613 221.808 10.865 222.408 ;
     RECT  10.789 174.432 10.883 175.32 ;
     RECT  10.717 196.08 10.883 197.496 ;
     RECT  9.821 97.728 10.885 98.328 ;
     RECT  9.713 99.552 10.885 100.2 ;
     RECT  10.643 103.2 10.897 109.992 ;
     RECT  10.001 206.784 10.897 207.096 ;
     RECT  10.829 127.728 10.901 127.848 ;
     RECT  10.835 210.144 10.901 214.728 ;
     RECT  10.825 171.552 10.909 171.576 ;
     RECT  10.451 192.624 10.931 194.568 ;
     RECT  10.681 271.536 10.931 276.984 ;
     RECT  9.785 16.848 10.933 17.688 ;
     RECT  10.885 97.728 10.933 100.2 ;
     RECT  10.865 101.232 10.933 101.496 ;
     RECT  10.825 158.352 10.937 163.512 ;
     RECT  10.643 231.744 10.937 231.768 ;
     RECT  10.613 250.512 10.937 251.928 ;
     RECT  10.835 111.168 10.973 113.496 ;
     RECT  10.861 114.48 10.973 121.128 ;
     RECT  10.499 136.128 10.973 136.152 ;
     RECT  10.499 137.184 10.973 140.232 ;
     RECT  10.931 271.632 10.973 276.984 ;
     RECT  10.825 35.76 10.981 37.224 ;
     RECT  10.285 38.256 10.981 40.728 ;
     RECT  10.835 62.4 11.005 63.72 ;
     RECT  10.825 64.704 11.005 66.072 ;
     RECT  10.973 138.048 11.005 140.232 ;
     RECT  10.261 141.312 11.005 145.848 ;
     RECT  10.469 219.456 11.005 220.44 ;
     RECT  9.962 237.12 11.005 237.48 ;
     RECT  10.837 287.28 11.005 295.08 ;
     RECT  11.005 138.048 11.009 145.848 ;
     RECT  10.829 122.544 11.029 126.696 ;
     RECT  11.005 237.12 11.029 237.768 ;
     RECT  10.717 238.848 11.029 239.304 ;
     RECT  10.901 127.824 11.041 127.848 ;
     RECT  10.865 30.576 11.045 31.176 ;
     RECT  10.981 35.76 11.053 40.728 ;
     RECT  10.721 268.032 11.075 270.216 ;
     RECT  10.115 20.976 11.077 22.68 ;
     RECT  11.005 62.4 11.077 66.072 ;
     RECT  10.973 111.648 11.081 113.496 ;
     RECT  10.547 247.248 11.081 249.384 ;
     RECT  11.075 268.032 11.084 270.168 ;
     RECT  10.835 216.432 11.113 217.704 ;
     RECT  11.005 219.264 11.113 220.44 ;
     RECT  11.005 254.16 11.113 254.184 ;
     RECT  10.613 255.696 11.113 256.92 ;
     RECT  10.499 297.552 11.113 297.624 ;
     RECT  10.333 34.608 11.117 34.632 ;
     RECT  10.001 198.816 11.117 205.8 ;
     RECT  10.901 210.144 11.117 212.616 ;
     RECT  10.835 258.192 11.117 259.272 ;
     RECT  10.681 156.288 11.123 157.224 ;
     RECT  10.757 95.76 11.125 96.504 ;
     RECT  10.933 97.728 11.125 101.496 ;
     RECT  10.361 185.808 11.125 189.432 ;
     RECT  10.505 190.416 11.125 191.4 ;
     RECT  10.115 263.28 11.125 264.792 ;
     RECT  11.084 266.448 11.125 266.472 ;
     RECT  11.041 127.824 11.149 128.088 ;
     RECT  10.789 146.976 11.149 148.056 ;
     RECT  10.469 150.48 11.149 150.984 ;
     RECT  11.117 204.864 11.149 205.8 ;
     RECT  10.897 206.784 11.149 207.672 ;
     RECT  10.828 260.496 11.149 261.24 ;
     RECT  9.829 262.224 11.149 262.296 ;
     RECT  11.125 263.28 11.149 266.472 ;
     RECT  10.573 172.704 11.153 173.304 ;
     RECT  11.125 185.808 11.171 191.4 ;
     RECT  11.113 216.432 11.171 220.44 ;
     RECT  11.149 260.496 11.171 266.472 ;
     RECT  11.084 267.792 11.171 270.168 ;
     RECT  11.009 142.512 11.189 145.848 ;
     RECT  11.117 210.144 11.189 210.552 ;
     RECT  11.171 188.256 11.212 191.4 ;
     RECT  11.113 255.408 11.219 256.92 ;
     RECT  10.249 43.296 11.221 43.896 ;
     RECT  9.785 68.016 11.221 69.288 ;
     RECT  10.577 283.536 11.221 283.656 ;
     RECT  11.149 127.824 11.225 128.232 ;
     RECT  11.189 142.512 11.225 145.128 ;
     RECT  10.883 196.128 11.225 197.496 ;
     RECT  10.835 226.32 11.225 230.76 ;
     RECT  10.109 179.04 11.257 180.504 ;
     RECT  10.252 279.552 11.257 281.304 ;
     RECT  10.577 282.336 11.257 282.36 ;
     RECT  11.171 216.432 11.261 218.328 ;
     RECT  11.221 68.016 11.285 70.008 ;
     RECT  11.149 146.88 11.293 148.056 ;
     RECT  10.393 149.136 11.293 149.16 ;
     RECT  10.789 28.416 11.297 29.352 ;
     RECT  10.865 54.384 11.297 56.232 ;
     RECT  11.029 237.12 11.297 239.304 ;
     RECT  10.609 45.024 11.315 46.728 ;
     RECT  11.285 68.016 11.317 70.104 ;
     RECT  10.844 71.664 11.317 84.024 ;
     RECT  10.931 193.056 11.317 194.568 ;
     RECT  10.613 176.4 11.324 177.864 ;
     RECT  11.257 179.04 11.324 180.696 ;
     RECT  10.505 89.472 11.329 90.072 ;
     RECT  10.505 91.392 11.329 91.608 ;
     RECT  10.643 233.04 11.329 233.208 ;
     RECT  10.393 24.144 11.365 27.096 ;
     RECT  11.324 56.88 11.365 56.904 ;
     RECT  11.324 176.4 11.365 180.696 ;
     RECT  10.825 181.872 11.365 184.68 ;
     RECT  11.317 68.016 11.369 84.024 ;
     RECT  11.125 95.76 11.369 101.496 ;
     RECT  10.937 250.656 11.369 251.928 ;
     RECT  10.973 271.632 11.369 273.096 ;
     RECT  10.001 51.408 11.401 51.432 ;
     RECT  10.835 60.912 11.401 61.128 ;
     RECT  11.317 193.056 11.401 194.904 ;
     RECT  11.005 286.704 11.401 295.08 ;
     RECT  11.365 24.144 11.405 27.24 ;
     RECT  11.297 28.416 11.405 29.16 ;
     RECT  11.365 56.88 11.411 57.192 ;
     RECT  11.077 62.4 11.411 66.744 ;
     RECT  11.297 238.176 11.411 239.304 ;
     RECT  11.369 271.632 11.411 273 ;
     RECT  10.937 158.496 11.413 163.512 ;
     RECT  10.577 164.544 11.413 169.368 ;
     RECT  11.329 233.04 11.413 233.64 ;
     RECT  11.149 204.864 11.42 207.672 ;
     RECT  10.325 208.992 11.42 209.16 ;
     RECT  11.293 146.88 11.429 149.16 ;
     RECT  11.149 150.192 11.429 150.984 ;
     RECT  11.029 122.496 11.437 126.696 ;
     RECT  11.009 138.048 11.441 141.336 ;
     RECT  11.413 158.496 11.459 169.368 ;
     RECT  11.113 296.976 11.461 297.624 ;
     RECT  11.401 286.272 11.468 295.08 ;
     RECT  11.315 45.936 11.473 46.728 ;
     RECT  11.429 146.88 11.473 150.984 ;
     RECT  10.897 102.576 11.477 109.992 ;
     RECT  11.42 204.864 11.507 209.16 ;
     RECT  10.861 243.744 11.509 246.216 ;
     RECT  11.081 247.248 11.509 247.272 ;
     RECT  10.973 274.176 11.509 276.984 ;
     RECT  10.109 278.16 11.509 278.184 ;
     RECT  11.461 296.4 11.509 297.624 ;
     RECT  11.405 26.064 11.513 27.24 ;
     RECT  11.053 35.76 11.513 39.192 ;
     RECT  10.973 114.48 11.513 120.84 ;
     RECT  11.509 274.176 11.537 278.184 ;
     RECT  11.257 279.552 11.537 282.36 ;
     RECT  11.405 24.144 11.545 24.696 ;
     RECT  11.123 156.288 11.545 157.08 ;
     RECT  11.221 283.536 11.545 284.472 ;
     RECT  11.513 26.16 11.549 27.24 ;
     RECT  11.045 30.768 11.549 31.176 ;
     RECT  11.441 141.216 11.549 141.336 ;
     RECT  11.171 219.36 11.549 220.44 ;
     RECT  11.153 172.704 11.555 173.208 ;
     RECT  11.537 274.176 11.555 282.36 ;
     RECT  11.468 285.696 11.557 295.08 ;
     RECT  10.753 19.296 11.581 19.32 ;
     RECT  11.077 20.88 11.581 22.68 ;
     RECT  10.217 58.848 11.581 59.112 ;
     RECT  9.923 129.36 11.581 133.08 ;
     RECT  11.219 255.984 11.581 256.92 ;
     RECT  11.117 258.192 11.581 259.176 ;
     RECT  11.473 45.936 11.585 46.968 ;
     RECT  11.557 285.456 11.603 295.08 ;
     RECT  11.545 283.392 11.605 284.472 ;
     RECT  11.603 285.456 11.605 294.504 ;
     RECT  11.581 19.296 11.612 19.512 ;
     RECT  11.581 129.36 11.617 133.416 ;
     RECT  10.613 134.544 11.617 134.904 ;
     RECT  10.613 152.592 11.617 155.064 ;
     RECT  11.545 156.192 11.617 157.08 ;
     RECT  11.585 45.984 11.621 46.968 ;
     RECT  10.643 48.48 11.621 49.8 ;
     RECT  11.509 243.744 11.621 247.272 ;
     RECT  11.555 274.176 11.621 282.216 ;
     RECT  11.617 129.36 11.625 134.904 ;
     RECT  11.225 226.32 11.644 227.496 ;
     RECT  10.793 1.728 11.653 2.856 ;
     RECT  10.793 3.84 11.653 5.736 ;
     RECT  10.433 6.816 11.653 15.384 ;
     RECT  11.473 33.12 11.653 33.144 ;
     RECT  11.365 34.368 11.653 34.392 ;
     RECT  11.221 43.248 11.653 43.896 ;
     RECT  11.369 70.656 11.653 84.024 ;
     RECT  10.861 85.2 11.653 85.224 ;
     RECT  10.505 87.792 11.653 88.104 ;
     RECT  11.329 89.472 11.653 91.608 ;
     RECT  11.225 128.064 11.653 128.232 ;
     RECT  11.625 129.36 11.653 134.952 ;
     RECT  11.459 167.616 11.653 169.368 ;
     RECT  10.649 241.248 11.653 242.28 ;
     RECT  11.509 296.16 11.653 297.624 ;
     RECT  11.401 60.816 11.657 61.128 ;
     RECT  11.081 111.648 11.657 113.304 ;
     RECT  11.212 188.352 11.657 191.4 ;
     RECT  11.581 58.848 11.689 59.64 ;
     RECT  11.653 241.248 11.689 242.376 ;
     RECT  11.113 253.584 11.689 254.184 ;
     RECT  11.053 40.608 11.693 40.728 ;
     RECT  11.549 26.208 11.699 27.24 ;
     RECT  11.653 129.264 11.699 134.952 ;
     RECT  11.657 190.56 11.699 191.4 ;
     RECT  11.621 246.96 11.699 247.272 ;
     RECT  11.621 279.648 11.699 282.216 ;
     RECT  11.699 191.184 11.701 191.4 ;
     RECT  10.883 175.296 11.725 175.32 ;
     RECT  11.365 176.4 11.725 184.68 ;
     RECT  11.657 60.816 11.729 60.936 ;
     RECT  11.411 238.944 11.729 239.304 ;
     RECT  11.653 33.12 11.737 34.392 ;
     RECT  11.701 191.184 11.747 192.024 ;
     RECT  11.621 274.176 11.747 278.28 ;
     RECT  11.699 279.648 11.747 282.024 ;
     RECT  11.473 146.112 11.749 150.984 ;
     RECT  11.411 66.192 11.761 66.744 ;
     RECT  11.369 68.016 11.761 69.384 ;
     RECT  10.757 92.88 11.761 94.776 ;
     RECT  11.369 95.76 11.761 100.2 ;
     RECT  11.725 175.296 11.761 184.68 ;
     RECT  11.171 185.808 11.761 187.08 ;
     RECT  11.621 49.056 11.765 49.8 ;
     RECT  11.761 66.192 11.765 69.384 ;
     RECT  11.699 129.264 11.765 132.312 ;
     RECT  11.225 142.704 11.765 145.128 ;
     RECT  11.747 191.52 11.788 192.024 ;
     RECT  11.653 128.064 11.795 128.28 ;
     RECT  11.747 274.704 11.795 278.28 ;
     RECT  11.653 3.84 11.797 15.384 ;
     RECT  11.689 241.248 11.797 242.664 ;
     RECT  11.621 243.744 11.797 245.928 ;
     RECT  10.865 52.992 11.833 53.352 ;
     RECT  11.411 57.168 11.833 57.192 ;
     RECT  11.689 58.224 11.833 59.64 ;
     RECT  10.865 221.808 11.833 222.12 ;
     RECT  10.835 225.024 11.837 225.048 ;
     RECT  11.297 237.12 11.837 237.144 ;
     RECT  11.369 101.472 11.845 101.496 ;
     RECT  11.477 102.576 11.845 107.352 ;
     RECT  11.689 253.344 11.845 254.184 ;
     RECT  11.653 87.792 11.861 91.608 ;
     RECT  11.653 70.656 11.869 85.224 ;
     RECT  10.433 86.544 11.869 86.568 ;
     RECT  11.477 108.624 11.869 109.992 ;
     RECT  10.757 235.296 11.869 236.088 ;
     RECT  11.845 253.344 11.869 254.28 ;
     RECT  11.411 62.4 11.873 64.968 ;
     RECT  11.459 158.496 11.873 162.072 ;
     RECT  11.171 260.496 11.873 265.608 ;
     RECT  11.117 198.816 11.893 203.784 ;
     RECT  10.933 16.8 11.9 17.688 ;
     RECT  11.749 146.112 11.905 151.032 ;
     RECT  11.761 175.296 11.905 187.08 ;
     RECT  11.869 253.344 11.905 255 ;
     RECT  11.833 57.168 11.909 59.64 ;
     RECT  11.729 239.28 11.933 239.304 ;
     RECT  11.869 70.656 11.939 86.568 ;
     RECT  11.653 0.288 11.941 2.856 ;
     RECT  11.797 3.84 11.941 15.624 ;
     RECT  11.9 16.8 11.941 17.88 ;
     RECT  11.612 19.104 11.941 19.512 ;
     RECT  11.737 33.12 11.941 33.144 ;
     RECT  11.939 82.464 11.941 86.568 ;
     RECT  11.861 87.792 11.941 91.752 ;
     RECT  11.507 208.512 11.941 209.16 ;
     RECT  11.833 221.52 11.941 222.12 ;
     RECT  11.939 70.656 11.945 81.336 ;
     RECT  11.873 158.976 11.945 162.072 ;
     RECT  11.905 175.152 11.945 187.08 ;
     RECT  11.657 188.352 11.945 189.432 ;
     RECT  11.225 229.296 11.948 230.76 ;
     RECT  11.699 133.392 11.977 134.952 ;
     RECT  11.945 175.152 11.977 186.936 ;
     RECT  11.761 92.88 11.98 100.2 ;
     RECT  11.941 0.288 11.981 19.512 ;
     RECT  11.981 1.728 11.987 19.512 ;
     RECT  11.737 34.224 11.987 34.392 ;
     RECT  11.189 210.288 11.987 210.552 ;
     RECT  11.905 136.272 11.989 136.296 ;
     RECT  11.441 138.048 11.989 139.8 ;
     RECT  11.113 171.216 11.989 171.24 ;
     RECT  10.649 223.392 11.989 223.8 ;
     RECT  11.549 219.36 12.009 220.104 ;
     RECT  11.401 50.928 12.013 51.432 ;
     RECT  11.977 133.392 12.013 135.24 ;
     RECT  11.989 136.272 12.013 139.8 ;
     RECT  11.948 229.296 12.013 230.904 ;
     RECT  11.833 52.992 12.017 53.64 ;
     RECT  11.893 198.48 12.017 203.784 ;
     RECT  11.933 239.28 12.017 239.928 ;
     RECT  11.653 296.16 12.017 297.672 ;
     RECT  11.617 152.592 12.035 157.08 ;
     RECT  11.905 225.36 12.035 225.384 ;
     RECT  11.261 216.432 12.037 218.232 ;
     RECT  11.869 234.912 12.037 236.088 ;
     RECT  11.369 250.896 12.037 251.928 ;
     RECT  11.905 253.056 12.037 255 ;
     RECT  10.789 299.28 12.037 299.304 ;
     RECT  11.941 82.464 12.049 91.752 ;
     RECT  11.98 92.88 12.049 95.496 ;
     RECT  11.297 54.672 12.053 55.272 ;
     RECT  11.765 66.288 12.053 69.384 ;
     RECT  11.989 170.976 12.076 171.96 ;
     RECT  11.987 210.528 12.083 210.552 ;
     RECT  10.901 213.696 12.083 214.728 ;
     RECT  12.037 234.912 12.083 236.568 ;
     RECT  11.581 255.984 12.083 259.176 ;
     RECT  11.549 30.912 12.085 31.176 ;
     RECT  11.987 34.368 12.089 34.392 ;
     RECT  11.989 223.392 12.089 223.992 ;
     RECT  11.977 174.816 12.113 186.936 ;
     RECT  12.083 213.696 12.121 214.536 ;
     RECT  11.797 241.248 12.121 245.928 ;
     RECT  12.017 297.552 12.121 297.672 ;
     RECT  12.037 215.76 12.124 218.232 ;
     RECT  11.765 143.28 12.157 145.128 ;
     RECT  11.905 146.112 12.157 151.464 ;
     RECT  12.083 234.912 12.157 235.08 ;
     RECT  12.083 256.32 12.157 259.176 ;
     RECT  11.171 268.464 12.157 270.168 ;
     RECT  12.013 271.392 12.157 271.416 ;
     RECT  11.545 23.904 12.161 24.696 ;
     RECT  11.653 42.768 12.161 43.896 ;
     RECT  11.653 167.616 12.161 169.848 ;
     RECT  11.788 191.52 12.161 191.544 ;
     RECT  11.401 193.056 12.161 194.952 ;
     RECT  11.699 247.248 12.161 247.272 ;
     RECT  12.013 50.928 12.188 51.768 ;
     RECT  11.225 196.128 12.188 197.448 ;
     RECT  11.437 121.824 12.193 126.696 ;
     RECT  11.795 128.064 12.193 128.088 ;
     RECT  11.365 266.976 12.193 267 ;
     RECT  12.017 239.28 12.197 239.304 ;
     RECT  11.873 260.496 12.197 264.792 ;
     RECT  11.513 35.76 12.229 38.76 ;
     RECT  12.161 42.768 12.229 43.8 ;
     RECT  12.188 195.984 12.229 197.448 ;
     RECT  12.017 198.48 12.229 202.584 ;
     RECT  12.017 203.76 12.229 203.784 ;
     RECT  11.507 204.864 12.229 207.24 ;
     RECT  11.413 233.04 12.229 233.064 ;
     RECT  12.193 266.976 12.229 267.096 ;
     RECT  12.157 268.464 12.229 271.416 ;
     RECT  11.621 45.984 12.233 46.776 ;
     RECT  12.037 299.28 12.233 299.352 ;
     RECT  11.411 272.448 12.241 272.952 ;
     RECT  11.117 211.536 12.265 212.616 ;
     RECT  11.555 173.088 12.277 173.208 ;
     RECT  12.113 174.432 12.277 186.936 ;
     RECT  12.017 296.16 12.277 296.424 ;
     RECT  11.081 248.352 12.337 249.384 ;
     RECT  12.197 260.496 12.337 264.696 ;
     RECT  11.513 120.576 12.428 120.84 ;
     RECT  12.193 121.824 12.428 128.088 ;
     RECT  11.699 26.304 12.481 27.24 ;
     RECT  11.405 29.136 12.481 29.16 ;
     RECT  12.161 193.056 12.481 194.616 ;
     RECT  11.941 33.024 12.517 33.144 ;
     RECT  11.845 101.472 12.517 107.352 ;
     RECT  11.869 108.624 12.517 110.568 ;
     RECT  11.765 129.264 12.517 132.216 ;
     RECT  12.337 247.92 12.517 249.384 ;
     RECT  12.037 250.896 12.517 255 ;
     RECT  11.98 97.008 12.565 100.2 ;
     RECT  12.517 101.472 12.565 110.568 ;
     RECT  12.013 229.296 12.565 231.624 ;
     RECT  12.428 120.576 12.575 128.088 ;
     RECT  12.229 42.048 12.589 43.8 ;
     RECT  12.076 170.976 12.613 171.24 ;
     RECT  12.565 229.248 12.613 231.624 ;
     RECT  12.301 56.064 12.62 56.088 ;
     RECT  11.909 57.168 12.62 59.112 ;
     RECT  12.229 203.76 12.661 207.24 ;
     RECT  11.941 208.512 12.661 209.208 ;
     RECT  11.549 141.216 12.697 141.24 ;
     RECT  12.233 299.28 12.707 299.304 ;
     RECT  11.657 111.648 12.733 113.256 ;
     RECT  12.697 141.216 12.733 141.672 ;
     RECT  12.157 256.32 12.733 259.224 ;
     RECT  12.337 260.4 12.733 264.696 ;
     RECT  12.517 129.12 12.757 132.216 ;
     RECT  12.013 133.392 12.757 139.8 ;
     RECT  11.644 226.416 12.757 227.496 ;
     RECT  12.613 228.912 12.757 231.624 ;
     RECT  12.229 232.848 12.757 233.064 ;
     RECT  11.797 44.88 12.769 44.904 ;
     RECT  11.729 60.816 12.769 60.84 ;
     RECT  12.085 30.912 12.805 31.752 ;
     RECT  12.733 141.12 12.841 141.672 ;
     RECT  11.945 189.36 12.841 189.432 ;
     RECT  12.841 141.12 12.853 141.768 ;
     RECT  12.157 143.28 12.853 151.464 ;
     RECT  11.513 114.48 12.877 119.4 ;
     RECT  12.575 120.48 12.877 128.088 ;
     RECT  12.757 226.416 12.877 227.928 ;
     RECT  12.757 228.912 12.877 233.112 ;
     RECT  12.241 272.544 12.877 272.952 ;
     RECT  11.605 283.392 12.877 294.504 ;
     RECT  12.277 296.016 12.877 296.424 ;
     RECT  11.987 1.728 12.949 15.24 ;
     RECT  11.987 16.512 12.949 19.512 ;
     RECT  12.841 238.224 12.949 238.248 ;
     RECT  12.757 129.12 12.956 139.8 ;
     RECT  12.853 141.12 12.956 151.464 ;
     RECT  12.277 173.088 12.977 186.936 ;
     RECT  12.481 26.304 12.985 29.16 ;
     RECT  12.265 210.768 12.985 212.616 ;
     RECT  12.121 213.648 12.985 214.536 ;
     RECT  12.62 56.064 13.045 59.112 ;
     RECT  12.769 60.816 13.045 61.368 ;
     RECT  11.945 158.976 13.045 161.88 ;
     RECT  11.459 163.2 13.045 166.44 ;
     RECT  11.945 71.04 13.057 81.336 ;
     RECT  12.049 82.464 13.057 95.496 ;
     RECT  13.045 158.976 13.057 166.44 ;
     RECT  12.161 167.616 13.057 169.464 ;
     RECT  11.747 279.648 13.057 281.256 ;
     RECT  12.035 152.784 13.065 157.08 ;
     RECT  12.805 30.864 13.093 31.944 ;
     RECT  12.517 32.976 13.093 33.144 ;
     RECT  12.085 39.84 13.093 39.864 ;
     RECT  12.589 41.472 13.093 43.8 ;
     RECT  12.877 114.48 13.093 128.088 ;
     RECT  12.956 129.12 13.093 151.464 ;
     RECT  12.661 203.76 13.093 209.208 ;
     RECT  12.985 210.768 13.093 214.536 ;
     RECT  12.124 215.904 13.093 218.232 ;
     RECT  12.877 226.416 13.093 233.112 ;
     RECT  12.083 236.544 13.093 236.568 ;
     RECT  12.949 238.224 13.093 238.488 ;
     RECT  13.057 279.648 13.093 282.168 ;
     RECT  12.877 283.392 13.093 296.424 ;
     RECT  12.121 297.552 13.093 297.768 ;
     RECT  12.229 35.28 13.129 38.76 ;
     RECT  12.121 240.624 13.129 245.928 ;
     RECT  13.093 279.648 13.129 296.424 ;
     RECT  12.949 1.728 13.208 19.512 ;
     RECT  11.581 20.88 13.208 22.872 ;
     RECT  12.161 24.096 13.208 24.696 ;
     RECT  12.985 26.304 13.208 29.256 ;
     RECT  13.093 30.864 13.208 33.144 ;
     RECT  13.129 34.704 13.208 38.76 ;
     RECT  13.093 39.84 13.208 43.8 ;
     RECT  12.769 44.88 13.208 45.576 ;
     RECT  12.233 46.752 13.208 46.776 ;
     RECT  12.517 47.856 13.208 47.88 ;
     RECT  11.765 49.056 13.208 49.08 ;
     RECT  12.188 50.112 13.208 51.768 ;
     RECT  12.017 52.992 13.208 53.016 ;
     RECT  12.053 54.672 13.208 54.696 ;
     RECT  13.045 56.064 13.208 59.496 ;
     RECT  13.045 60.528 13.208 61.368 ;
     RECT  11.873 62.544 13.208 64.968 ;
     RECT  12.053 66.288 13.208 69 ;
     RECT  13.057 71.04 13.208 95.496 ;
     RECT  12.565 97.008 13.208 110.568 ;
     RECT  12.733 111.648 13.208 113.304 ;
     RECT  13.093 114.48 13.208 151.464 ;
     RECT  13.065 152.736 13.208 157.08 ;
     RECT  13.057 158.976 13.208 169.464 ;
     RECT  12.613 170.448 13.208 171.24 ;
     RECT  12.977 172.8 13.208 186.936 ;
     RECT  11.945 188.352 13.208 188.376 ;
     RECT  12.841 189.36 13.208 190.344 ;
     RECT  13.165 191.328 13.208 191.352 ;
     RECT  12.481 192.96 13.208 194.616 ;
     RECT  12.229 195.984 13.208 202.584 ;
     RECT  13.093 203.76 13.208 218.232 ;
     RECT  12.009 219.36 13.208 219.96 ;
     RECT  11.941 221.184 13.208 222.12 ;
     RECT  12.089 223.392 13.208 223.56 ;
     RECT  13.093 226.368 13.208 233.112 ;
     RECT  12.157 234.288 13.208 235.08 ;
     RECT  13.093 236.544 13.208 238.488 ;
     RECT  13.093 239.616 13.208 239.64 ;
     RECT  13.129 240.624 13.208 246.696 ;
     RECT  12.517 247.92 13.208 255 ;
     RECT  12.733 256.32 13.208 264.696 ;
     RECT  12.229 266.928 13.208 271.416 ;
     RECT  12.877 272.544 13.208 273.144 ;
     RECT  11.795 274.704 13.208 278.184 ;
     RECT  13.129 279.648 13.208 296.568 ;
     RECT  13.093 297.552 13.208 298.248 ;
     RECT  13.208 1.728 13.504 298.248 ;
     RECT  13.504 137.904 13.529 151.08 ;
     RECT  13.504 39.792 13.565 44.424 ;
     RECT  13.504 194.4 13.565 202.584 ;
     RECT  13.504 229.296 13.565 231.432 ;
     RECT  13.565 41.424 13.601 44.424 ;
     RECT  13.504 51.312 13.601 54.696 ;
     RECT  13.504 82.464 13.601 90.216 ;
     RECT  13.601 43.632 13.619 44.424 ;
     RECT  13.504 72.576 13.619 80.328 ;
     RECT  13.529 148.08 13.619 151.08 ;
     RECT  13.504 156 13.619 170.472 ;
     RECT  13.504 171.6 13.619 174.456 ;
     RECT  13.565 229.296 13.619 229.32 ;
     RECT  13.504 247.92 13.619 251.832 ;
     RECT  13.504 257.376 13.619 266.808 ;
     RECT  13.601 82.464 13.637 87.144 ;
     RECT  13.504 225.36 13.637 227.496 ;
     RECT  13.504 274.128 13.637 293.592 ;
     RECT  13.504 252.816 13.667 254.52 ;
     RECT  13.504 28.176 13.673 37.656 ;
     RECT  13.504 47.76 13.673 48.36 ;
     RECT  13.504 107.28 13.673 117.096 ;
     RECT  13.504 245.52 13.673 246.456 ;
     RECT  13.504 255.888 13.673 256.392 ;
     RECT  13.504 272.496 13.673 273.144 ;
     RECT  13.529 137.904 13.681 147.096 ;
     RECT  13.565 39.792 13.708 40.296 ;
     RECT  13.601 52.368 13.708 54.696 ;
     RECT  13.619 72.576 13.709 73.032 ;
     RECT  13.637 82.464 13.709 87.096 ;
     RECT  13.504 91.392 13.709 95.496 ;
     RECT  13.565 201.408 13.709 202.584 ;
     RECT  13.504 208.272 13.709 222.36 ;
     RECT  13.504 58.704 13.715 64.968 ;
     RECT  13.504 294.624 13.715 298.248 ;
     RECT  13.504 1.728 13.745 19.416 ;
     RECT  13.709 208.272 13.745 212.136 ;
     RECT  13.637 225.36 13.745 226.44 ;
     RECT  13.715 294.72 13.763 298.248 ;
     RECT  13.619 74.4 13.781 80.328 ;
     RECT  13.504 134.832 13.781 136.776 ;
     RECT  13.763 295.728 13.781 298.248 ;
     RECT  13.673 34.224 13.811 37.656 ;
     RECT  13.715 58.704 13.811 61.032 ;
     RECT  13.619 43.68 13.817 44.424 ;
     RECT  13.781 136.704 13.817 136.776 ;
     RECT  13.619 159.552 13.817 170.472 ;
     RECT  13.619 257.376 13.817 265.032 ;
     RECT  13.504 152.736 13.852 154.68 ;
     RECT  13.709 213.12 13.853 222.36 ;
     RECT  13.504 55.824 13.859 57.528 ;
     RECT  13.565 230.304 13.859 231.432 ;
     RECT  13.673 245.616 13.859 246.456 ;
     RECT  13.705 299.28 13.885 299.304 ;
     RECT  13.781 74.448 13.889 80.328 ;
     RECT  13.504 185.808 13.897 186.936 ;
     RECT  13.504 244.464 13.9 244.488 ;
     RECT  13.853 216.432 13.907 218.328 ;
     RECT  13.853 219.36 13.907 222.36 ;
     RECT  13.619 247.92 13.907 251.544 ;
     RECT  13.709 82.464 13.925 83.736 ;
     RECT  13.709 91.392 13.925 95.16 ;
     RECT  13.504 20.928 13.955 24.12 ;
     RECT  13.925 92.496 13.955 95.16 ;
     RECT  13.504 175.728 13.955 184.728 ;
     RECT  13.504 125.376 13.961 132.216 ;
     RECT  13.811 58.752 13.997 61.032 ;
     RECT  13.961 125.376 13.997 125.976 ;
     RECT  13.955 175.728 13.997 180.792 ;
     RECT  13.852 152.736 14.003 154.584 ;
     RECT  13.673 28.176 14.033 33.144 ;
     RECT  13.681 138.048 14.033 147.096 ;
     RECT  13.907 216.432 14.033 218.28 ;
     RECT  14.003 153.552 14.044 154.584 ;
     RECT  13.811 34.416 14.051 37.656 ;
     RECT  13.955 182.016 14.051 184.728 ;
     RECT  13.565 194.4 14.051 200.376 ;
     RECT  13.673 107.28 14.069 110.568 ;
     RECT  14.051 194.4 14.069 199.896 ;
     RECT  13.637 227.472 14.069 227.496 ;
     RECT  14.033 216.432 14.099 217.272 ;
     RECT  13.504 66.288 14.105 69 ;
     RECT  13.955 22.56 14.14 24.12 ;
     RECT  13.853 213.12 14.14 215.016 ;
     RECT  13.709 201.408 14.147 202.488 ;
     RECT  13.781 295.728 14.147 297.624 ;
     RECT  12.625 0.192 14.173 0.216 ;
     RECT  14.051 183.936 14.213 184.728 ;
     RECT  13.817 170.352 14.221 170.472 ;
     RECT  13.504 204.864 14.243 207.24 ;
     RECT  13.907 219.36 14.284 222.264 ;
     RECT  14.033 28.176 14.285 33.096 ;
     RECT  13.637 274.128 14.285 282.024 ;
     RECT  13.504 45.552 14.291 46.392 ;
     RECT  13.504 118.128 14.321 122.664 ;
     RECT  14.285 274.128 14.321 277.464 ;
     RECT  13.504 96.528 14.357 100.872 ;
     RECT  13.673 111.84 14.357 117.096 ;
     RECT  14.321 119.088 14.357 122.664 ;
     RECT  13.817 136.704 14.357 136.728 ;
     RECT  14.284 219.36 14.357 220.584 ;
     RECT  13.619 172.608 14.393 174.456 ;
     RECT  14.285 28.464 14.429 33.096 ;
     RECT  13.601 41.424 14.429 42.648 ;
     RECT  13.817 257.376 14.429 263.448 ;
     RECT  13.817 43.68 14.435 43.704 ;
     RECT  14.291 45.552 14.435 45.576 ;
     RECT  14.285 278.592 14.435 282.024 ;
     RECT  13.885 298.704 14.437 299.304 ;
     RECT  14.14 213.12 14.465 214.536 ;
     RECT  13.504 234.816 14.473 243.48 ;
     RECT  13.889 79.2 14.485 80.328 ;
     RECT  13.504 191.328 14.485 193.416 ;
     RECT  14.069 194.4 14.485 199.08 ;
     RECT  13.859 246 14.485 246.456 ;
     RECT  13.504 50.16 14.497 50.184 ;
     RECT  13.601 51.312 14.497 51.336 ;
     RECT  13.504 70.272 14.497 71.448 ;
     RECT  13.715 62.16 14.501 64.968 ;
     RECT  14.357 119.088 14.501 121.464 ;
     RECT  14.033 138.048 14.501 143.688 ;
     RECT  13.817 159.552 14.501 168.648 ;
     RECT  14.473 240.912 14.501 243.48 ;
     RECT  14.033 218.256 14.531 218.28 ;
     RECT  13.504 123.696 14.533 124.248 ;
     RECT  13.997 125.376 14.533 125.688 ;
     RECT  14.069 107.52 14.537 110.568 ;
     RECT  13.504 267.984 14.537 271.176 ;
     RECT  13.709 72.576 14.569 72.84 ;
     RECT  14.393 172.704 14.569 174.456 ;
     RECT  13.997 175.728 14.569 180.456 ;
     RECT  14.429 32.736 14.573 33.096 ;
     RECT  14.537 107.52 14.579 108.84 ;
     RECT  14.533 123.696 14.579 125.688 ;
     RECT  13.601 88.128 14.581 90.216 ;
     RECT  13.925 91.392 14.581 91.416 ;
     RECT  13.619 148.08 14.581 150.552 ;
     RECT  14.357 114.432 14.588 117.096 ;
     RECT  14.485 79.2 14.627 81 ;
     RECT  13.619 171.6 14.627 171.624 ;
     RECT  13.708 40.08 14.629 40.296 ;
     RECT  14.588 114.432 14.629 117.144 ;
     RECT  13.997 58.752 14.645 59.496 ;
     RECT  13.925 82.656 14.645 83.736 ;
     RECT  13.897 186.576 14.645 186.936 ;
     RECT  14.321 274.128 14.645 276.84 ;
     RECT  14.033 144.672 14.677 147.096 ;
     RECT  14.581 148.08 14.677 151.032 ;
     RECT  14.147 201.552 14.677 202.488 ;
     RECT  14.569 232.512 14.677 232.536 ;
     RECT  13.673 255.888 14.677 255.912 ;
     RECT  13.619 266.4 14.677 266.808 ;
     RECT  14.537 267.984 14.677 269.304 ;
     RECT  14.537 270.624 14.677 271.176 ;
     RECT  13.709 84.768 14.684 87.096 ;
     RECT  14.581 88.128 14.684 91.416 ;
     RECT  13.817 264.432 14.713 265.032 ;
     RECT  13.673 272.496 14.713 272.52 ;
     RECT  14.645 82.656 14.717 83.352 ;
     RECT  14.044 153.984 14.717 154.584 ;
     RECT  14.473 234.816 14.717 239.88 ;
     RECT  13.745 16.992 14.723 19.416 ;
     RECT  14.677 266.4 14.723 269.304 ;
     RECT  14.437 298.704 14.723 299.352 ;
     RECT  14.357 96.528 14.732 100.536 ;
     RECT  14.629 40.08 14.749 41.016 ;
     RECT  14.677 144.672 14.749 151.032 ;
     RECT  14.581 152.544 14.749 152.568 ;
     RECT  14.501 138.48 14.753 143.688 ;
     RECT  13.619 156 14.753 158.52 ;
     RECT  13.745 208.656 14.753 212.136 ;
     RECT  13.889 74.448 14.771 78.072 ;
     RECT  14.627 79.2 14.771 80.616 ;
     RECT  14.684 84.768 14.771 91.416 ;
     RECT  14.723 266.4 14.771 267.384 ;
     RECT  14.771 84.768 14.773 87.192 ;
     RECT  13.637 283.152 14.773 293.592 ;
     RECT  13.763 294.72 14.773 294.744 ;
     RECT  13.504 25.152 14.78 26.808 ;
     RECT  14.677 232.512 14.78 233.208 ;
     RECT  14.717 234.816 14.78 238.248 ;
     RECT  14.429 42.432 14.785 42.648 ;
     RECT  13.955 20.928 14.789 21.384 ;
     RECT  14.501 62.16 14.789 63.48 ;
     RECT  14.357 122.448 14.789 122.664 ;
     RECT  14.753 138.48 14.789 143.496 ;
     RECT  14.749 144.672 14.789 152.568 ;
     RECT  14.753 208.656 14.789 210.024 ;
     RECT  14.717 239.856 14.789 239.88 ;
     RECT  13.907 249.264 14.819 251.544 ;
     RECT  14.645 274.368 14.819 276.84 ;
     RECT  14.749 19.92 14.821 19.944 ;
     RECT  14.789 20.928 14.821 21.096 ;
     RECT  14.497 49.728 14.821 51.336 ;
     RECT  14.497 70.176 14.821 71.448 ;
     RECT  14.717 154.464 14.821 154.584 ;
     RECT  14.213 184.128 14.821 184.728 ;
     RECT  14.357 219.36 14.821 220.008 ;
     RECT  14.485 246 14.821 247.752 ;
     RECT  14.677 270.624 14.821 271.32 ;
     RECT  14.713 272.496 14.821 273.288 ;
     RECT  14.435 278.976 14.821 282.024 ;
     RECT  14.773 283.152 14.821 294.744 ;
     RECT  14.357 111.84 14.825 113.064 ;
     RECT  14.641 133.248 14.825 133.272 ;
     RECT  14.789 144.672 14.825 147.24 ;
     RECT  14.821 278.976 14.825 294.744 ;
     RECT  14.569 72.528 14.831 72.84 ;
     RECT  14.78 25.152 14.857 27.336 ;
     RECT  14.821 70.08 14.857 71.448 ;
     RECT  14.831 72.528 14.857 72.888 ;
     RECT  14.485 191.328 14.857 199.08 ;
     RECT  14.677 201.552 14.857 202.632 ;
     RECT  13.504 203.616 14.857 203.64 ;
     RECT  14.753 211.2 14.857 212.136 ;
     RECT  14.465 213.12 14.857 213.384 ;
     RECT  13.504 223.344 14.857 223.416 ;
     RECT  13.859 230.736 14.857 231.432 ;
     RECT  14.78 232.512 14.857 238.248 ;
     RECT  14.501 241.2 14.857 243.48 ;
     RECT  14.051 36 14.861 37.656 ;
     RECT  13.708 52.56 14.861 54.696 ;
     RECT  14.105 66.288 14.861 68.232 ;
     RECT  14.771 77.472 14.861 78.072 ;
     RECT  14.789 148.416 14.861 152.568 ;
     RECT  14.78 44.88 14.867 45.432 ;
     RECT  14.825 112.32 14.867 113.064 ;
     RECT  14.857 230.736 14.867 238.248 ;
     RECT  14.501 159.648 14.869 168.648 ;
     RECT  13.504 102.528 14.893 106.008 ;
     RECT  14.429 28.464 14.897 31.752 ;
     RECT  14.789 138.528 14.897 143.496 ;
     RECT  14.857 241.2 14.897 243.96 ;
     RECT  14.821 244.992 14.897 247.752 ;
     RECT  14.821 48.912 14.905 51.336 ;
     RECT  14.221 170.352 14.915 170.424 ;
     RECT  14.825 283.392 14.915 294.744 ;
     RECT  14.723 298.752 14.915 299.352 ;
     RECT  14.645 186.72 14.917 186.936 ;
     RECT  13.504 188.352 14.917 190.296 ;
     RECT  14.537 109.824 14.925 110.568 ;
     RECT  14.771 88.32 14.929 91.416 ;
     RECT  13.955 92.496 14.929 94.68 ;
     RECT  14.732 95.712 14.929 100.536 ;
     RECT  14.723 16.992 14.933 18.792 ;
     RECT  14.569 172.704 14.933 180.456 ;
     RECT  14.867 234.24 14.933 238.248 ;
     RECT  14.147 295.728 14.933 297.576 ;
     RECT  14.869 159.648 14.956 169.32 ;
     RECT  14.857 223.344 14.963 223.992 ;
     RECT  14.897 241.44 14.963 243.96 ;
     RECT  14.497 46.752 14.965 46.776 ;
     RECT  13.673 47.76 14.965 47.928 ;
     RECT  14.501 64.56 14.965 64.968 ;
     RECT  13.961 127.2 14.965 132.216 ;
     RECT  14.897 247.44 14.965 247.752 ;
     RECT  14.897 138.528 14.969 143.304 ;
     RECT  14.867 230.736 14.972 233.208 ;
     RECT  14.857 25.104 15.001 27.336 ;
     RECT  14.749 39.504 15.001 41.016 ;
     RECT  14.857 70.08 15.001 72.888 ;
     RECT  14.771 74.448 15.001 76.488 ;
     RECT  14.905 48.912 15.005 49.608 ;
     RECT  13.997 60.672 15.005 61.032 ;
     RECT  14.819 274.656 15.005 276.84 ;
     RECT  14.915 299.328 15.005 299.352 ;
     RECT  14.173 0.048 15.011 0.216 ;
     RECT  14.099 216.576 15.011 217.272 ;
     RECT  14.933 234.336 15.011 238.248 ;
     RECT  14.965 46.752 15.013 47.928 ;
     RECT  14.821 154.464 15.037 154.728 ;
     RECT  14.753 156 15.037 157.176 ;
     RECT  14.897 244.992 15.037 246.264 ;
     RECT  14.965 127.2 15.041 132.984 ;
     RECT  14.857 191.28 15.041 199.08 ;
     RECT  15.011 235.008 15.041 238.248 ;
     RECT  15.005 276.816 15.041 276.84 ;
     RECT  14.929 88.32 15.059 100.536 ;
     RECT  14.243 206.064 15.061 207.24 ;
     RECT  14.051 34.416 15.068 34.728 ;
     RECT  13.781 134.832 15.073 135.528 ;
     RECT  14.819 251.088 15.073 251.544 ;
     RECT  13.667 252.816 15.073 254.28 ;
     RECT  14.956 159.648 15.077 168.696 ;
     RECT  15.073 251.088 15.077 254.28 ;
     RECT  15.013 46.752 15.1 48.12 ;
     RECT  14.501 119.088 15.107 121.128 ;
     RECT  14.677 255.504 15.107 256.632 ;
     RECT  14.717 82.656 15.109 83.256 ;
     RECT  14.893 102.192 15.109 106.008 ;
     RECT  14.579 107.52 15.109 108.6 ;
     RECT  14.821 219.264 15.109 220.008 ;
     RECT  13.745 226.416 15.109 226.44 ;
     RECT  14.773 84.528 15.113 87.192 ;
     RECT  14.969 138.528 15.113 143.16 ;
     RECT  14.051 182.016 15.113 182.952 ;
     RECT  15.041 191.376 15.113 199.08 ;
     RECT  14.723 268.512 15.113 269.304 ;
     RECT  14.14 22.56 15.145 23.544 ;
     RECT  15.001 24.816 15.145 27.336 ;
     RECT  14.897 31.008 15.149 31.752 ;
     RECT  14.861 36 15.149 37.128 ;
     RECT  15.005 49.248 15.149 49.608 ;
     RECT  14.965 64.56 15.149 65.304 ;
     RECT  14.933 173.808 15.149 180.456 ;
     RECT  14.917 186.72 15.149 190.296 ;
     RECT  15.113 191.808 15.149 199.08 ;
     RECT  14.905 50.592 15.181 51.336 ;
     RECT  15.149 36 15.185 37.08 ;
     RECT  15.149 192.144 15.185 199.08 ;
     RECT  14.465 214.512 15.185 214.536 ;
     RECT  14.825 278.976 15.185 282.312 ;
     RECT  15.107 255.888 15.203 256.632 ;
     RECT  15.185 192.624 15.205 199.08 ;
     RECT  14.569 225.168 15.212 225.192 ;
     RECT  15.109 226.32 15.212 226.44 ;
     RECT  14.861 77.52 15.217 78.072 ;
     RECT  14.771 79.2 15.217 80.52 ;
     RECT  15.205 192.624 15.217 199.656 ;
     RECT  15.113 138.528 15.221 140.04 ;
     RECT  15.041 235.008 15.221 235.416 ;
     RECT  15.041 236.496 15.221 238.248 ;
     RECT  15.037 244.8 15.221 246.264 ;
     RECT  15.077 251.088 15.221 253.656 ;
     RECT  15.221 236.544 15.251 238.248 ;
     RECT  14.897 28.464 15.253 29.592 ;
     RECT  15.212 225.168 15.253 227.16 ;
     RECT  15.001 228.144 15.253 228.552 ;
     RECT  14.972 229.776 15.253 233.208 ;
     RECT  15.145 22.56 15.257 27.336 ;
     RECT  14.861 66.288 15.257 68.184 ;
     RECT  14.867 112.32 15.257 112.536 ;
     RECT  14.857 211.2 15.257 213.384 ;
     RECT  15.011 216.624 15.257 217.272 ;
     RECT  15.217 192.624 15.289 200.04 ;
     RECT  15.181 50.592 15.293 51.96 ;
     RECT  15.109 102.192 15.293 108.6 ;
     RECT  15.149 175.008 15.293 180.456 ;
     RECT  14.429 258.24 15.293 263.448 ;
     RECT  15.001 38.208 15.299 41.016 ;
     RECT  14.785 42.432 15.299 43.272 ;
     RECT  14.861 148.416 15.299 151.512 ;
     RECT  15.109 218.64 15.299 220.008 ;
     RECT  15.253 225.12 15.299 227.16 ;
     RECT  15.253 228.144 15.299 233.208 ;
     RECT  15.293 258.24 15.299 261.24 ;
     RECT  15.005 60.672 15.325 60.984 ;
     RECT  15.325 60.624 15.329 60.984 ;
     RECT  15.059 88.32 15.329 91.464 ;
     RECT  15.289 192.624 15.329 200.568 ;
     RECT  15.005 274.656 15.329 275.544 ;
     RECT  15.329 192.912 15.347 200.568 ;
     RECT  15.059 92.544 15.349 100.536 ;
     RECT  14.789 208.656 15.349 209.736 ;
     RECT  15.257 217.008 15.349 217.272 ;
     RECT  15.257 24.912 15.361 27.336 ;
     RECT  15.253 28.416 15.361 29.592 ;
     RECT  14.915 170.352 15.361 170.376 ;
     RECT  15.113 182.208 15.361 182.952 ;
     RECT  14.821 184.128 15.361 185.208 ;
     RECT  15.293 262.224 15.361 263.448 ;
     RECT  14.713 264.432 15.361 265.08 ;
     RECT  15.361 24.912 15.365 29.592 ;
     RECT  15.113 84.528 15.365 85.656 ;
     RECT  15.251 236.832 15.365 238.248 ;
     RECT  15.221 246 15.365 246.264 ;
     RECT  15.221 252.288 15.365 253.656 ;
     RECT  15.203 256.32 15.365 256.536 ;
     RECT  15.329 91.008 15.395 91.464 ;
     RECT  14.861 152.544 15.395 152.568 ;
     RECT  15.037 154.464 15.395 157.176 ;
     RECT  13.745 1.728 15.397 16.008 ;
     RECT  14.933 16.992 15.397 18.024 ;
     RECT  14.243 204.864 15.397 204.888 ;
     RECT  15.061 206.064 15.397 207.528 ;
     RECT  14.284 221.568 15.397 222.264 ;
     RECT  14.963 223.344 15.397 223.368 ;
     RECT  15.149 49.248 15.401 49.272 ;
     RECT  15.077 159.648 15.401 167.208 ;
     RECT  15.349 208.56 15.401 209.736 ;
     RECT  15.349 217.008 15.401 217.56 ;
     RECT  15.299 258.336 15.401 261.24 ;
     RECT  15.299 40.608 15.433 41.016 ;
     RECT  15.397 204.864 15.433 207.528 ;
     RECT  15.401 208.56 15.433 208.968 ;
     RECT  15.395 154.464 15.436 154.824 ;
     RECT  14.915 285.504 15.436 294.744 ;
     RECT  15.365 26.4 15.437 29.592 ;
     RECT  14.867 45.408 15.437 45.432 ;
     RECT  15.293 50.736 15.437 51.96 ;
     RECT  15.149 173.808 15.437 173.976 ;
     RECT  15.149 186.72 15.437 190.008 ;
     RECT  15.433 204.864 15.437 208.968 ;
     RECT  15.299 226.32 15.437 227.16 ;
     RECT  15.436 285.504 15.437 292.44 ;
     RECT  14.821 270.624 15.443 273.288 ;
     RECT  15.257 22.56 15.445 23.544 ;
     RECT  15.437 204.864 15.461 207.864 ;
     RECT  15.433 40.608 15.469 41.112 ;
     RECT  14.629 114.432 15.469 118.104 ;
     RECT  15.299 38.208 15.473 39.528 ;
     RECT  15.445 22.176 15.491 23.544 ;
     RECT  13.859 56.496 15.493 57.528 ;
     RECT  14.925 110.544 15.505 110.568 ;
     RECT  14.579 124.752 15.505 125.688 ;
     RECT  15.401 217.536 15.505 217.56 ;
     RECT  15.299 218.64 15.505 219.912 ;
     RECT  15.437 226.368 15.505 227.16 ;
     RECT  15.365 24.912 15.509 25.272 ;
     RECT  15.437 26.4 15.509 29.496 ;
     RECT  14.645 58.752 15.509 58.776 ;
     RECT  15.001 70.08 15.509 76.488 ;
     RECT  15.217 77.52 15.509 80.52 ;
     RECT  15.365 84.528 15.509 85.176 ;
     RECT  15.221 235.392 15.509 235.416 ;
     RECT  14.915 283.392 15.509 284.424 ;
     RECT  15.491 22.176 15.532 22.872 ;
     RECT  14.821 19.92 15.539 21.096 ;
     RECT  14.819 249.264 15.541 250.104 ;
     RECT  14.861 53.04 15.545 54.696 ;
     RECT  15.221 138.528 15.545 139.992 ;
     RECT  15.461 204.624 15.545 207.864 ;
     RECT  15.493 55.68 15.548 57.528 ;
     RECT  15.469 114 15.569 118.104 ;
     RECT  15.107 119.088 15.569 119.112 ;
     RECT  15.397 1.728 15.578 18.024 ;
     RECT  15.548 55.68 15.58 57.72 ;
     RECT  14.789 62.544 15.581 63.48 ;
     RECT  15.041 132.624 15.581 132.984 ;
     RECT  14.825 144.816 15.581 147.24 ;
     RECT  15.113 268.512 15.587 268.536 ;
     RECT  15.329 60.624 15.589 60.936 ;
     RECT  14.857 201.552 15.613 203.64 ;
     RECT  15.436 293.52 15.613 294.744 ;
     RECT  14.933 295.728 15.613 296.424 ;
     RECT  15.257 212.88 15.617 213.384 ;
     RECT  15.361 262.224 15.617 265.08 ;
     RECT  15.509 283.488 15.617 284.424 ;
     RECT  15.221 244.8 15.635 245.016 ;
     RECT  14.579 123.696 15.637 123.72 ;
     RECT  15.505 124.752 15.637 125.976 ;
     RECT  15.107 120.288 15.649 121.128 ;
     RECT  15.347 200.064 15.649 200.568 ;
     RECT  15.613 201.552 15.649 204.072 ;
     RECT  15.539 19.92 15.653 20.472 ;
     RECT  15.149 31.104 15.653 31.752 ;
     RECT  15.041 127.2 15.653 131.592 ;
     RECT  15.299 225.12 15.653 225.192 ;
     RECT  15.653 127.2 15.683 131.4 ;
     RECT  14.573 32.736 15.685 33.048 ;
     RECT  15.068 34.128 15.685 34.728 ;
     RECT  15.505 110.544 15.685 110.76 ;
     RECT  15.436 154.464 15.685 154.728 ;
     RECT  14.753 158.496 15.685 158.52 ;
     RECT  15.293 175.296 15.689 180.456 ;
     RECT  15.617 262.752 15.689 265.08 ;
     RECT  15.443 270.624 15.689 273 ;
     RECT  15.329 274.944 15.689 275.256 ;
     RECT  15.617 283.536 15.689 284.424 ;
     RECT  15.589 60.24 15.721 60.936 ;
     RECT  15.257 66.288 15.721 66.696 ;
     RECT  15.689 175.44 15.721 180.456 ;
     RECT  14.771 266.4 15.721 267 ;
     RECT  15.109 82.608 15.725 83.256 ;
     RECT  15.401 159.984 15.725 167.208 ;
     RECT  15.365 256.368 15.725 256.536 ;
     RECT  15.011 0.192 15.757 0.216 ;
     RECT  15.649 120.288 15.757 121.32 ;
     RECT  14.789 122.448 15.757 122.52 ;
     RECT  15.395 156 15.757 157.176 ;
     RECT  15.685 158.496 15.757 159 ;
     RECT  15.365 237.12 15.757 238.248 ;
     RECT  15.469 40.608 15.761 41.448 ;
     RECT  15.725 160.032 15.761 167.208 ;
     RECT  15.505 217.536 15.761 219.912 ;
     RECT  15.653 225.168 15.761 225.192 ;
     RECT  15.635 244.992 15.761 245.016 ;
     RECT  15.365 252.288 15.761 253.512 ;
     RECT  15.689 262.752 15.761 264.456 ;
     RECT  15.361 182.208 15.779 185.208 ;
     RECT  15.437 208.944 15.797 208.968 ;
     RECT  15.505 226.368 15.827 227.976 ;
     RECT  15.721 66.096 15.833 66.696 ;
     RECT  15.509 70.128 15.833 76.488 ;
     RECT  15.395 91.392 15.833 91.464 ;
     RECT  15.293 102.624 15.833 108.6 ;
     RECT  15.833 74.592 15.865 76.488 ;
     RECT  15.509 77.52 15.865 80.424 ;
     RECT  15.581 146.448 15.865 147.24 ;
     RECT  14.963 241.44 15.865 243.816 ;
     RECT  15.365 246.144 15.865 246.264 ;
     RECT  14.965 247.44 15.865 247.944 ;
     RECT  15.185 279.552 15.865 282.312 ;
     RECT  15.545 53.04 15.869 54.36 ;
     RECT  15.649 200.064 15.869 204.072 ;
     RECT  15.757 156 15.875 159 ;
     RECT  15.1 46.752 15.877 47.928 ;
     RECT  15.685 154.416 15.877 154.728 ;
     RECT  15.437 285.504 15.877 291.432 ;
     RECT  15.865 246.144 15.893 247.944 ;
     RECT  14.933 297.552 15.893 297.576 ;
     RECT  15.113 86.736 15.901 87.192 ;
     RECT  15.329 88.32 15.901 89.496 ;
     RECT  15.361 169.872 15.901 170.376 ;
     RECT  15.578 1.728 15.905 17.976 ;
     RECT  15.617 213.36 15.905 213.384 ;
     RECT  15.827 226.368 15.905 226.392 ;
     RECT  14.933 172.704 15.912 172.776 ;
     RECT  15.875 156 15.923 158.472 ;
     RECT  15.653 31.2 15.925 31.752 ;
     RECT  15.685 32.736 15.925 34.728 ;
     RECT  15.779 184.128 15.925 185.208 ;
     RECT  15.397 221.568 15.925 223.368 ;
     RECT  15.757 237.12 15.937 238.536 ;
     RECT  15.865 240.768 15.937 243.816 ;
     RECT  15.905 16.944 15.941 17.976 ;
     RECT  15.509 27.408 15.941 29.496 ;
     RECT  15.901 86.736 15.941 89.496 ;
     RECT  15.347 192.912 15.941 198.84 ;
     RECT  15.937 240.672 15.965 243.816 ;
     RECT  15.761 218.064 15.971 219.912 ;
     RECT  15.299 42.432 15.973 43.08 ;
     RECT  15.757 120.288 15.973 122.52 ;
     RECT  15.637 123.696 15.973 125.976 ;
     RECT  15.545 138.528 15.973 139.944 ;
     RECT  15.893 297.552 15.976 297.672 ;
     RECT  15.073 134.832 15.98 135.864 ;
     RECT  15.325 137.328 15.98 137.352 ;
     RECT  15.505 269.568 16.009 269.592 ;
     RECT  15.473 38.208 16.013 38.856 ;
     RECT  15.923 158.352 16.019 158.472 ;
     RECT  15.901 169.872 16.019 170.616 ;
     RECT  15.437 173.808 16.019 173.832 ;
     RECT  15.865 279.552 16.019 282.36 ;
     RECT  15.581 62.544 16.021 63.336 ;
     RECT  15.941 28.416 16.049 29.496 ;
     RECT  15.865 146.448 16.049 147.288 ;
     RECT  15.299 148.416 16.049 151.032 ;
     RECT  16.019 158.448 16.049 158.472 ;
     RECT  15.965 240.672 16.049 244.008 ;
     RECT  15.893 246.144 16.049 247.992 ;
     RECT  15.761 252.48 16.049 253.512 ;
     RECT  15.877 284.976 16.049 291.432 ;
     RECT  15.349 92.544 16.081 100.728 ;
     RECT  15.721 175.44 16.081 180.696 ;
     RECT  15.779 182.208 16.081 182.952 ;
     RECT  15.925 184.128 16.085 185.304 ;
     RECT  15.925 221.184 16.085 223.368 ;
     RECT  15.721 266.208 16.085 267 ;
     RECT  15.689 271.104 16.085 273 ;
     RECT  16.021 62.16 16.108 63.336 ;
     RECT  15.865 74.592 16.115 80.424 ;
     RECT  15.937 112.8 16.115 112.824 ;
     RECT  15.98 134.832 16.117 137.352 ;
     RECT  15.793 210.192 16.117 210.216 ;
     RECT  15.257 211.2 16.117 211.752 ;
     RECT  16.108 62.544 16.129 63.336 ;
     RECT  16.049 253.392 16.157 253.512 ;
     RECT  15.613 293.52 16.157 296.424 ;
     RECT  15.757 0.192 16.163 0.312 ;
     RECT  15.149 64.56 16.165 64.872 ;
     RECT  15.257 68.16 16.165 68.184 ;
     RECT  15.077 168.336 16.172 168.696 ;
     RECT  16.019 169.872 16.172 169.944 ;
     RECT  15.941 16.944 16.193 17.496 ;
     RECT  16.117 134.016 16.193 137.352 ;
     RECT  15.971 218.16 16.211 219.912 ;
     RECT  15.925 31.2 16.213 34.728 ;
     RECT  15.581 144.816 16.213 145.368 ;
     RECT  15.185 36.048 16.225 37.08 ;
     RECT  15.437 51.84 16.225 51.96 ;
     RECT  15.869 53.04 16.225 53.784 ;
     RECT  15.569 114 16.225 119.112 ;
     RECT  15.973 120.288 16.225 125.976 ;
     RECT  15.877 153.792 16.225 154.728 ;
     RECT  15.912 172.608 16.225 172.776 ;
     RECT  16.049 240.672 16.225 241.8 ;
     RECT  15.725 82.608 16.229 83.064 ;
     RECT  16.172 168.336 16.259 169.944 ;
     RECT  15.581 132.72 16.261 132.984 ;
     RECT  16.193 134.016 16.261 134.52 ;
     RECT  16.259 168.336 16.261 168.792 ;
     RECT  16.225 172.608 16.261 173.112 ;
     RECT  15.58 55.728 16.265 57.72 ;
     RECT  15.401 258.432 16.265 261.24 ;
     RECT  16.085 271.296 16.265 273 ;
     RECT  15.973 42.288 16.268 43.08 ;
     RECT  15.877 46.512 16.297 47.928 ;
     RECT  16.049 146.928 16.297 147.288 ;
     RECT  16.049 148.416 16.297 150.408 ;
     RECT  16.085 221.232 16.297 223.368 ;
     RECT  16.213 31.2 16.3 35.064 ;
     RECT  16.213 144.24 16.301 145.368 ;
     RECT  15.689 275.232 16.301 275.256 ;
     RECT  16.019 279.552 16.301 281.592 ;
     RECT  15.685 110.544 16.307 111.048 ;
     RECT  16.268 42.288 16.309 43.512 ;
     RECT  16.261 44.976 16.309 45 ;
     RECT  15.721 60.096 16.333 60.936 ;
     RECT  16.165 68.16 16.333 68.28 ;
     RECT  15.941 27.408 16.337 27.432 ;
     RECT  16.301 279.84 16.337 281.592 ;
     RECT  16.309 42.288 16.355 45 ;
     RECT  16.259 169.824 16.355 169.944 ;
     RECT  15.869 200.064 16.357 200.136 ;
     RECT  16.225 36.048 16.369 37.656 ;
     RECT  15.941 86.736 16.369 87.576 ;
     RECT  16.265 258.432 16.392 258.888 ;
     RECT  15.827 227.376 16.403 227.976 ;
     RECT  16.265 56.976 16.405 57.72 ;
     RECT  15.649 58.704 16.405 58.728 ;
     RECT  16.333 68.16 16.405 69 ;
     RECT  15.941 88.992 16.405 89.496 ;
     RECT  16.117 210.192 16.405 211.752 ;
     RECT  16.049 246.96 16.405 247.992 ;
     RECT  15.541 249.12 16.405 250.104 ;
     RECT  16.265 272.976 16.405 273 ;
     RECT  15.761 40.608 16.409 41.112 ;
     RECT  16.405 209.136 16.409 211.752 ;
     RECT  15.509 25.056 16.441 25.272 ;
     RECT  15.509 26.4 16.441 26.424 ;
     RECT  15.937 237.12 16.441 238.824 ;
     RECT  15.877 268.224 16.441 268.488 ;
     RECT  15.437 292.416 16.441 292.44 ;
     RECT  16.157 293.52 16.441 294.024 ;
     RECT  15.683 127.872 16.445 131.4 ;
     RECT  15.761 160.032 16.445 167.16 ;
     RECT  16.392 258.192 16.453 258.888 ;
     RECT  16.165 64.56 16.477 65.016 ;
     RECT  16.081 92.496 16.477 100.728 ;
     RECT  15.437 187.296 16.477 190.008 ;
     RECT  16.405 272.976 16.477 273.72 ;
     RECT  16.297 146.928 16.481 150.408 ;
     RECT  15.976 297.552 16.481 297.72 ;
     RECT  15.725 256.368 16.499 256.488 ;
     RECT  16.453 257.472 16.499 258.888 ;
     RECT  16.049 28.512 16.508 29.496 ;
     RECT  16.229 82.608 16.508 82.776 ;
     RECT  15.781 84.192 16.508 84.216 ;
     RECT  16.477 187.296 16.508 190.2 ;
     RECT  15.869 201.216 16.508 204.072 ;
     RECT  15.545 205.296 16.508 207.24 ;
     RECT  16.157 295.248 16.525 296.424 ;
     RECT  16.477 92.448 16.547 100.728 ;
     RECT  16.445 160.752 16.547 167.16 ;
     RECT  15.532 22.224 16.549 22.872 ;
     RECT  16.405 56.976 16.549 58.728 ;
     RECT  16.333 59.76 16.549 60.936 ;
     RECT  16.477 64.56 16.549 65.256 ;
     RECT  16.115 76.608 16.549 80.424 ;
     RECT  16.508 84.192 16.549 84.264 ;
     RECT  16.369 85.872 16.549 87.576 ;
     RECT  16.307 110.88 16.549 111.048 ;
     RECT  15.299 229.056 16.549 233.208 ;
     RECT  16.441 267.36 16.549 268.488 ;
     RECT  16.009 269.568 16.549 270.024 ;
     RECT  16.129 62.544 16.553 62.568 ;
     RECT  16.337 279.84 16.553 280.392 ;
     RECT  16.547 95.136 16.585 100.728 ;
     RECT  15.833 102.672 16.585 108.6 ;
     RECT  16.549 228.384 16.585 233.208 ;
     RECT  16.193 135.648 16.589 137.352 ;
     RECT  16.403 227.376 16.589 227.4 ;
     RECT  16.508 81.84 16.595 82.776 ;
     RECT  16.549 84.192 16.595 87.576 ;
     RECT  16.508 245.904 16.595 245.928 ;
     RECT  16.585 102.672 16.597 109.08 ;
     RECT  15.833 66.288 16.621 66.696 ;
     RECT  16.405 68.16 16.621 69.048 ;
     RECT  16.225 153.312 16.621 154.728 ;
     RECT  16.441 276 16.621 276.024 ;
     RECT  16.355 169.824 16.625 169.896 ;
     RECT  15.653 20.112 16.657 20.472 ;
     RECT  16.549 22.224 16.657 23.112 ;
     RECT  16.513 265.68 16.657 265.704 ;
     RECT  16.499 257.472 16.661 258.792 ;
     RECT  15.437 50.736 16.691 50.76 ;
     RECT  16.225 51.84 16.691 53.784 ;
     RECT  16.585 228.384 16.691 233.88 ;
     RECT  16.225 235.488 16.691 235.512 ;
     RECT  16.597 102.672 16.693 109.176 ;
     RECT  16.549 110.88 16.697 111.768 ;
     RECT  16.621 66.288 16.729 69.048 ;
     RECT  15.833 70.128 16.729 73.56 ;
     RECT  15.973 138.48 16.729 139.944 ;
     RECT  15.113 141.12 16.729 143.16 ;
     RECT  15.941 192.912 16.729 195.384 ;
     RECT  16.477 278.688 16.729 278.712 ;
     RECT  16.595 84.816 16.733 87.576 ;
     RECT  16.697 110.88 16.739 110.904 ;
     RECT  16.405 214.032 16.739 214.152 ;
     RECT  16.355 44.304 16.741 45 ;
     RECT  16.297 46.512 16.741 48.984 ;
     RECT  16.549 56.976 16.741 60.936 ;
     RECT  16.333 112.848 16.741 112.872 ;
     RECT  16.225 114 16.741 126.36 ;
     RECT  16.739 214.128 16.741 214.152 ;
     RECT  16.445 127.872 16.765 128.904 ;
     RECT  16.549 152.16 16.765 152.184 ;
     RECT  16.508 201.216 16.765 207.24 ;
     RECT  16.741 214.128 16.765 214.872 ;
     RECT  16.405 215.904 16.765 215.928 ;
     RECT  16.369 35.952 16.769 37.656 ;
     RECT  16.621 276 16.769 276.456 ;
     RECT  16.693 102.672 16.787 109.848 ;
     RECT  16.261 132.72 16.789 134.52 ;
     RECT  16.693 212.976 16.789 213 ;
     RECT  16.765 214.128 16.789 215.928 ;
     RECT  16.729 278.112 16.789 278.712 ;
     RECT  16.508 28.512 16.796 29.976 ;
     RECT  16.3 31.2 16.796 34.92 ;
     RECT  16.508 187.296 16.801 190.92 ;
     RECT  16.729 66.288 16.805 73.56 ;
     RECT  16.477 272.976 16.835 273.816 ;
     RECT  16.769 276 16.835 276.024 ;
     RECT  16.441 25.056 16.837 26.424 ;
     RECT  16.585 95.136 16.837 100.872 ;
     RECT  16.787 102.672 16.837 108.6 ;
     RECT  16.085 184.128 16.837 184.968 ;
     RECT  16.357 200.016 16.837 200.136 ;
     RECT  16.765 201.216 16.837 207.432 ;
     RECT  16.297 221.232 16.837 223.944 ;
     RECT  15.833 91.392 16.873 91.416 ;
     RECT  16.547 92.448 16.873 94.056 ;
     RECT  16.301 144.768 16.873 145.368 ;
     RECT  16.481 297.696 16.873 297.72 ;
     RECT  16.409 41.088 16.877 41.112 ;
     RECT  16.547 165.84 16.877 167.16 ;
     RECT  16.741 46.512 16.883 49.32 ;
     RECT  16.049 285.264 16.885 291.432 ;
     RECT  16.441 292.416 16.885 294.024 ;
     RECT  16.691 51.84 16.909 51.864 ;
     RECT  16.405 88.992 16.909 90.072 ;
     RECT  16.873 91.392 16.909 94.056 ;
     RECT  16.789 214.128 16.909 216.552 ;
     RECT  16.441 237.12 16.909 239.304 ;
     RECT  16.789 212.016 16.913 213 ;
     RECT  16.796 28.512 16.931 34.92 ;
     RECT  15.923 156 16.933 157.176 ;
     RECT  16.789 132.672 16.945 134.52 ;
     RECT  16.837 95.136 16.949 108.6 ;
     RECT  16.801 187.296 16.949 191.016 ;
     RECT  16.909 19.008 16.981 19.032 ;
     RECT  16.837 24.336 16.981 26.424 ;
     RECT  16.691 52.992 16.981 53.784 ;
     RECT  16.805 68.16 16.981 73.56 ;
     RECT  16.115 74.592 16.981 75.48 ;
     RECT  16.549 76.608 16.981 80.808 ;
     RECT  16.909 88.992 16.981 94.056 ;
     RECT  16.945 132.576 16.981 134.52 ;
     RECT  15.941 196.656 16.981 198.84 ;
     RECT  16.837 200.016 16.981 207.432 ;
     RECT  15.221 251.088 16.981 251.112 ;
     RECT  16.837 252.24 16.981 252.264 ;
     RECT  15.761 262.752 16.981 264.024 ;
     RECT  16.657 265.536 16.981 265.704 ;
     RECT  16.835 273.264 16.981 273.816 ;
     RECT  16.741 112.848 16.988 126.36 ;
     RECT  16.193 17.04 17.009 17.496 ;
     RECT  16.981 18.912 17.009 19.032 ;
     RECT  16.657 20.112 17.009 23.112 ;
     RECT  16.883 46.512 17.009 49.224 ;
     RECT  16.013 38.832 17.017 38.856 ;
     RECT  16.547 160.752 17.021 164.76 ;
     RECT  16.885 299.28 17.021 299.304 ;
     RECT  16.981 88.896 17.027 94.056 ;
     RECT  16.405 246.96 17.027 250.104 ;
     RECT  16.981 251.088 17.027 252.264 ;
     RECT  16.981 262.752 17.027 265.704 ;
     RECT  16.549 267.36 17.027 270.024 ;
     RECT  16.873 297.696 17.027 298.056 ;
     RECT  16.931 31.248 17.029 34.92 ;
     RECT  16.409 209.136 17.036 210.936 ;
     RECT  16.733 86.784 17.053 87.576 ;
     RECT  16.481 147.072 17.053 150.408 ;
     RECT  16.837 221.232 17.053 224.76 ;
     RECT  16.621 40.08 17.057 40.104 ;
     RECT  16.765 152.016 17.057 152.184 ;
     RECT  16.265 259.92 17.057 261.24 ;
     RECT  17.027 268.992 17.057 270.024 ;
     RECT  16.748 83.76 17.075 83.784 ;
     RECT  15.905 1.728 17.077 15.624 ;
     RECT  17.057 152.16 17.077 152.184 ;
     RECT  16.621 153.312 17.077 154.872 ;
     RECT  16.981 196.656 17.077 207.432 ;
     RECT  16.909 214.128 17.077 216.6 ;
     RECT  15.689 283.536 17.077 283.848 ;
     RECT  16.885 285.264 17.077 294.024 ;
     RECT  16.981 68.16 17.089 75.48 ;
     RECT  16.981 76.608 17.089 81 ;
     RECT  16.589 135.84 17.089 137.352 ;
     RECT  16.729 138.48 17.089 143.16 ;
     RECT  17.009 17.04 17.093 23.112 ;
     RECT  16.981 24.336 17.093 26.664 ;
     RECT  16.949 95.136 17.093 108.312 ;
     RECT  16.729 192.192 17.093 195.384 ;
     RECT  16.741 44.304 17.123 45.048 ;
     RECT  17.027 91.776 17.123 94.056 ;
     RECT  16.765 127.632 17.123 128.904 ;
     RECT  16.981 132.48 17.123 134.52 ;
     RECT  17.089 135.84 17.123 143.16 ;
     RECT  17.021 162.432 17.123 164.76 ;
     RECT  16.261 168.24 17.123 168.792 ;
     RECT  16.837 184.08 17.123 184.968 ;
     RECT  17.036 208.656 17.123 210.936 ;
     RECT  16.913 212.016 17.123 212.664 ;
     RECT  16.909 236.592 17.123 239.304 ;
     RECT  16.225 240.48 17.123 241.8 ;
     RECT  17.077 283.248 17.123 294.024 ;
     RECT  17.093 18.672 17.125 23.112 ;
     RECT  17.077 214.128 17.125 216.648 ;
     RECT  17.123 137.328 17.129 139.944 ;
     RECT  17.053 147.072 17.129 150.552 ;
     RECT  17.077 152.16 17.129 154.872 ;
     RECT  16.933 156 17.129 157.32 ;
     RECT  17.125 214.128 17.129 216.744 ;
     RECT  17.053 221.232 17.129 225.24 ;
     RECT  16.691 228.384 17.129 233.16 ;
     RECT  17.123 284.448 17.161 294.024 ;
     RECT  16.525 295.248 17.161 296.232 ;
     RECT  17.161 284.448 17.164 296.232 ;
     RECT  17.129 156.144 17.165 157.32 ;
     RECT  17.027 247.872 17.165 250.104 ;
     RECT  16.789 277.344 17.165 278.712 ;
     RECT  17.164 285.264 17.165 296.232 ;
     RECT  17.077 1.152 17.197 15.624 ;
     RECT  17.093 17.04 17.197 17.16 ;
     RECT  17.123 168.24 17.201 168.648 ;
     RECT  17.197 1.152 17.219 17.16 ;
     RECT  17.123 209.136 17.219 210.936 ;
     RECT  17.123 212.016 17.219 212.568 ;
     RECT  17.077 300 17.219 300.024 ;
     RECT  16.261 172.128 17.221 173.112 ;
     RECT  16.049 242.832 17.221 243.24 ;
     RECT  16.265 271.296 17.228 271.944 ;
     RECT  17.093 25.104 17.237 26.664 ;
     RECT  16.909 50.928 17.237 51.864 ;
     RECT  17.123 141.216 17.237 143.16 ;
     RECT  17.129 152.16 17.267 152.856 ;
     RECT  16.787 109.824 17.269 109.848 ;
     RECT  16.988 112.848 17.269 126.408 ;
     RECT  16.949 187.296 17.269 190.968 ;
     RECT  17.057 269.52 17.269 270.024 ;
     RECT  17.228 271.296 17.269 272.136 ;
     RECT  17.029 31.296 17.273 34.92 ;
     RECT  17.221 242.832 17.273 244.104 ;
     RECT  16.549 63.696 17.305 65.256 ;
     RECT  16.805 66.288 17.305 66.744 ;
     RECT  17.269 112.704 17.305 126.408 ;
     RECT  16.873 144.768 17.305 145.464 ;
     RECT  16.081 175.44 17.305 182.952 ;
     RECT  17.123 236.592 17.309 238.872 ;
     RECT  17.165 247.872 17.309 249.624 ;
     RECT  17.219 1.728 17.315 17.16 ;
     RECT  17.269 269.52 17.315 272.136 ;
     RECT  16.981 52.992 17.317 54.696 ;
     RECT  16.265 55.728 17.317 55.752 ;
     RECT  16.741 56.976 17.317 61.224 ;
     RECT  17.273 243.984 17.317 244.104 ;
     RECT  17.305 112.704 17.341 126.552 ;
     RECT  17.123 127.632 17.341 128.424 ;
     RECT  17.305 175.44 17.341 183 ;
     RECT  17.123 184.08 17.341 184.728 ;
     RECT  17.129 214.272 17.341 216.744 ;
     RECT  16.211 218.208 17.341 219.912 ;
     RECT  17.123 162.432 17.345 164.376 ;
     RECT  16.981 273.264 17.345 274.584 ;
     RECT  17.317 243.984 17.353 244.344 ;
     RECT  17.125 18.672 17.363 23.208 ;
     RECT  17.305 144.768 17.377 145.656 ;
     RECT  17.077 196.512 17.377 207.432 ;
     RECT  17.341 214.272 17.377 219.912 ;
     RECT  17.129 221.232 17.377 223.176 ;
     RECT  16.931 28.512 17.381 30.264 ;
     RECT  17.341 112.704 17.381 128.424 ;
     RECT  17.341 175.44 17.404 184.728 ;
     RECT  17.353 244.08 17.404 244.344 ;
     RECT  17.273 31.296 17.417 34.824 ;
     RECT  16.769 36.384 17.417 37.656 ;
     RECT  16.445 129.888 17.417 131.4 ;
     RECT  17.129 153.888 17.417 154.872 ;
     RECT  17.315 269.52 17.417 271.752 ;
     RECT  17.123 44.304 17.449 44.76 ;
     RECT  16.499 256.464 17.449 256.488 ;
     RECT  17.381 28.512 17.453 29.16 ;
     RECT  16.355 42.288 17.453 42.744 ;
     RECT  17.404 178.08 17.489 184.728 ;
     RECT  17.123 241.056 17.489 241.8 ;
     RECT  17.404 244.08 17.489 244.104 ;
     RECT  17.027 297.696 17.507 297.768 ;
     RECT  16.553 279.888 17.521 280.392 ;
     RECT  17.219 209.136 17.525 210.36 ;
     RECT  17.123 283.248 17.525 283.272 ;
     RECT  17.377 144.768 17.557 145.704 ;
     RECT  17.489 241.44 17.557 241.8 ;
     RECT  17.273 242.832 17.557 242.856 ;
     RECT  17.317 52.992 17.561 61.224 ;
     RECT  17.525 209.136 17.561 209.16 ;
     RECT  16.337 281.424 17.561 281.592 ;
     RECT  17.089 68.16 17.564 81 ;
     RECT  16.595 82.032 17.564 82.632 ;
     RECT  16.477 254.784 17.564 254.808 ;
     RECT  17.453 42.432 17.593 42.744 ;
     RECT  17.489 179.616 17.597 184.728 ;
     RECT  17.129 228.384 17.603 232.008 ;
     RECT  17.453 28.512 17.605 29.112 ;
     RECT  17.377 196.512 17.605 207.528 ;
     RECT  16.157 253.488 17.605 253.512 ;
     RECT  17.449 256.464 17.605 256.584 ;
     RECT  17.027 263.184 17.605 265.704 ;
     RECT  17.605 27.888 17.629 29.112 ;
     RECT  17.009 46.464 17.629 49.224 ;
     RECT  17.561 58.512 17.629 61.224 ;
     RECT  17.305 63.696 17.629 66.744 ;
     RECT  17.309 247.92 17.633 249.624 ;
     RECT  17.129 147.072 17.653 149.496 ;
     RECT  17.021 160.752 17.653 161.304 ;
     RECT  17.404 175.44 17.653 176.952 ;
     RECT  17.237 50.928 17.665 51 ;
     RECT  17.125 226.848 17.665 226.872 ;
     RECT  16.733 84.816 17.701 85.608 ;
     RECT  17.053 86.784 17.701 87.768 ;
     RECT  17.653 160.128 17.701 161.304 ;
     RECT  17.605 195.696 17.701 207.528 ;
     RECT  17.017 38.784 17.737 38.856 ;
     RECT  17.665 50.784 17.737 51 ;
     RECT  16.981 234.192 17.737 234.312 ;
     RECT  17.701 235.776 17.737 235.8 ;
     RECT  17.485 246.048 17.737 246.36 ;
     RECT  17.057 260.352 17.737 261.24 ;
     RECT  17.165 277.344 17.737 278.568 ;
     RECT  17.269 109.824 17.773 110.808 ;
     RECT  17.773 109.824 17.797 111.72 ;
     RECT  17.221 171.936 17.797 173.112 ;
     RECT  17.129 224.544 17.809 225.24 ;
     RECT  17.165 285.84 17.809 296.232 ;
     RECT  16.333 0.048 17.843 0.072 ;
     RECT  16.625 169.872 17.845 169.896 ;
     RECT  17.797 171.024 17.845 173.112 ;
     RECT  17.653 174.432 17.845 176.952 ;
     RECT  17.701 297.648 17.845 297.672 ;
     RECT  17.809 224.544 17.852 225.336 ;
     RECT  17.852 224.544 17.873 225.672 ;
     RECT  17.564 68.16 17.881 82.632 ;
     RECT  17.564 254.64 17.953 254.808 ;
     RECT  17.605 255.984 17.953 256.584 ;
     RECT  17.593 42.432 18.025 42.84 ;
     RECT  17.449 43.824 18.025 44.76 ;
     RECT  17.603 228.384 18.025 231.864 ;
     RECT  17.845 169.824 18.037 169.896 ;
     RECT  17.845 171.024 18.037 176.952 ;
     RECT  17.027 251.904 18.037 251.928 ;
     RECT  17.027 88.896 18.061 90.072 ;
     RECT  17.123 91.776 18.061 93 ;
     RECT  17.381 112.896 18.085 128.424 ;
     RECT  17.129 137.808 18.092 139.944 ;
     RECT  17.881 67.824 18.097 82.632 ;
     RECT  17.701 83.808 18.097 87.768 ;
     RECT  17.093 192.528 18.097 194.472 ;
     RECT  17.701 195.696 18.097 207.72 ;
     RECT  18.061 88.896 18.133 93 ;
     RECT  17.123 94.032 18.133 94.056 ;
     RECT  17.737 260.352 18.133 261.864 ;
     RECT  17.605 263.184 18.133 266.376 ;
     RECT  17.219 212.544 18.14 212.568 ;
     RECT  17.377 214.272 18.14 223.176 ;
     RECT  17.737 37.68 18.169 38.856 ;
     RECT  18.037 251.712 18.169 251.928 ;
     RECT  17.605 253.488 18.169 253.656 ;
     RECT  17.557 144.768 18.181 145.8 ;
     RECT  17.417 36.384 18.229 36.648 ;
     RECT  17.873 224.544 18.229 225.864 ;
     RECT  17.629 58.512 18.241 66.744 ;
     RECT  18.097 67.824 18.241 87.768 ;
     RECT  17.701 160.032 18.241 161.304 ;
     RECT  17.345 162.432 18.241 162.792 ;
     RECT  18.229 224.496 18.241 225.864 ;
     RECT  17.315 1.728 18.277 16.296 ;
     RECT  17.363 18.672 18.277 22.776 ;
     RECT  17.381 30.144 18.277 30.264 ;
     RECT  17.417 31.296 18.277 34.776 ;
     RECT  17.237 141.216 18.277 142.776 ;
     RECT  18.181 144.24 18.277 145.8 ;
     RECT  17.267 152.16 18.277 152.184 ;
     RECT  17.953 254.64 18.277 256.584 ;
     RECT  16.661 257.952 18.277 258.792 ;
     RECT  17.521 279.792 18.277 280.392 ;
     RECT  18.097 185.328 18.313 185.352 ;
     RECT  17.269 186.768 18.313 190.968 ;
     RECT  18.169 251.712 18.313 253.656 ;
     RECT  18.277 254.64 18.313 258.792 ;
     RECT  17.345 273.696 18.313 274.584 ;
     RECT  18.097 299.28 18.323 299.4 ;
     RECT  18.241 58.512 18.325 87.768 ;
     RECT  17.605 154.992 18.325 155.064 ;
     RECT  17.165 156.144 18.325 157.176 ;
     RECT  17.809 285.84 18.325 296.376 ;
     RECT  17.633 247.92 18.332 247.944 ;
     RECT  18.133 259.872 18.349 266.376 ;
     RECT  17.027 267.36 18.349 267.912 ;
     RECT  18.097 192.528 18.373 207.72 ;
     RECT  17.525 210.24 18.373 210.36 ;
     RECT  18.14 212.544 18.373 223.176 ;
     RECT  18.229 36.048 18.38 36.648 ;
     RECT  18.169 37.68 18.38 39.336 ;
     RECT  18.373 212.016 18.385 223.176 ;
     RECT  18.325 285.84 18.385 296.568 ;
     RECT  18.38 36.048 18.408 39.336 ;
     RECT  17.653 147.024 18.421 149.496 ;
     RECT  17.129 150.528 18.421 150.552 ;
     RECT  18.385 211.536 18.421 223.176 ;
     RECT  18.241 224.208 18.421 225.864 ;
     RECT  17.893 40.848 18.429 40.872 ;
     RECT  17.237 25.104 18.449 26.328 ;
     RECT  17.629 27.312 18.449 29.112 ;
     RECT  18.277 1.248 18.469 16.296 ;
     RECT  18.429 40.416 18.469 40.872 ;
     RECT  18.133 88.896 18.469 94.056 ;
     RECT  17.093 95.136 18.469 106.728 ;
     RECT  17.093 107.712 18.469 108.312 ;
     RECT  17.797 109.44 18.469 111.72 ;
     RECT  18.085 112.896 18.469 128.616 ;
     RECT  17.417 130.416 18.469 131.4 ;
     RECT  17.123 132.576 18.469 134.52 ;
     RECT  17.123 135.84 18.469 135.864 ;
     RECT  18.092 137.664 18.469 139.944 ;
     RECT  17.845 297.552 18.469 297.672 ;
     RECT  17.417 269.52 18.493 271.32 ;
     RECT  18.323 299.376 18.515 299.4 ;
     RECT  18.025 42.432 18.565 44.76 ;
     RECT  17.629 46.032 18.565 49.224 ;
     RECT  18.469 136.944 18.565 139.944 ;
     RECT  18.469 1.152 18.608 16.92 ;
     RECT  18.277 18.192 18.608 22.776 ;
     RECT  18.449 25.104 18.608 29.112 ;
     RECT  18.277 30.144 18.608 34.776 ;
     RECT  18.408 35.952 18.608 39.336 ;
     RECT  18.469 40.416 18.608 41.256 ;
     RECT  18.565 42.432 18.608 49.224 ;
     RECT  17.737 50.688 18.608 51 ;
     RECT  17.561 52.992 18.608 57.432 ;
     RECT  18.325 58.512 18.608 87.816 ;
     RECT  18.469 88.896 18.608 106.728 ;
     RECT  18.469 107.712 18.608 111.72 ;
     RECT  18.469 112.896 18.608 131.4 ;
     RECT  18.469 132.48 18.608 135.864 ;
     RECT  18.565 136.944 18.608 139.992 ;
     RECT  18.277 141.216 18.608 145.8 ;
     RECT  18.421 147.024 18.608 150.552 ;
     RECT  18.277 152.16 18.608 152.76 ;
     RECT  17.417 153.888 18.608 153.912 ;
     RECT  18.325 154.992 18.608 157.176 ;
     RECT  17.953 158.544 18.608 158.568 ;
     RECT  18.241 160.032 18.608 162.792 ;
     RECT  17.345 164.112 18.608 164.376 ;
     RECT  16.877 166.08 18.608 167.16 ;
     RECT  17.201 168.24 18.608 168.6 ;
     RECT  18.037 169.824 18.608 176.952 ;
     RECT  17.489 178.08 18.608 178.632 ;
     RECT  17.597 179.616 18.608 184.296 ;
     RECT  18.313 185.328 18.608 190.968 ;
     RECT  18.373 192.528 18.608 208.584 ;
     RECT  18.373 210.24 18.608 210.408 ;
     RECT  18.421 211.536 18.608 225.864 ;
     RECT  17.665 226.848 18.608 226.92 ;
     RECT  18.025 228 18.608 231.864 ;
     RECT  17.129 233.136 18.608 233.16 ;
     RECT  17.737 234.192 18.608 235.8 ;
     RECT  17.309 237.12 18.608 238.872 ;
     RECT  17.593 239.856 18.608 240.024 ;
     RECT  17.557 241.44 18.608 242.856 ;
     RECT  17.737 245.616 18.608 246.36 ;
     RECT  18.332 247.584 18.608 247.944 ;
     RECT  17.633 248.928 18.608 249.624 ;
     RECT  18.313 251.712 18.608 258.792 ;
     RECT  18.349 259.872 18.608 267.912 ;
     RECT  18.493 269.52 18.608 271.512 ;
     RECT  18.313 273.696 18.608 275.496 ;
     RECT  17.737 276.672 18.608 278.568 ;
     RECT  18.277 279.792 18.608 281.352 ;
     RECT  18.025 282.816 18.608 282.84 ;
     RECT  18.385 284.448 18.608 284.472 ;
     RECT  18.385 285.792 18.608 296.568 ;
     RECT  18.469 297.552 18.608 298.248 ;
     RECT  18.608 1.152 18.611 298.248 ;
     RECT  18.611 1.728 18.707 298.248 ;
     RECT  18.707 1.728 18.904 298.2 ;
     RECT  18.904 179.52 18.929 188.952 ;
     RECT  18.904 266.112 18.929 266.952 ;
     RECT  18.904 16.896 18.965 16.92 ;
     RECT  18.904 91.44 18.965 112.872 ;
     RECT  18.904 20.88 19.001 22.92 ;
     RECT  18.904 70.56 19.001 80.328 ;
     RECT  18.904 86.736 19.001 86.76 ;
     RECT  18.904 207.744 19.001 212.568 ;
     RECT  18.904 167.52 19.037 173.544 ;
     RECT  18.929 185.904 19.043 188.952 ;
     RECT  18.904 239.856 19.043 250.104 ;
     RECT  19.001 70.56 19.073 80.232 ;
     RECT  18.904 139.68 19.073 152.712 ;
     RECT  18.904 270.432 19.073 278.712 ;
     RECT  18.904 285.984 19.073 298.2 ;
     RECT  18.929 179.52 19.081 184.728 ;
     RECT  18.904 37.056 19.117 39.336 ;
     RECT  18.904 279.792 19.132 285 ;
     RECT  19.073 139.68 19.145 144.168 ;
     RECT  19.073 285.984 19.145 297.768 ;
     RECT  18.904 28.416 19.181 29.208 ;
     RECT  19.073 145.2 19.181 152.712 ;
     RECT  19.073 270.576 19.181 278.712 ;
     RECT  19.181 148.56 19.187 152.712 ;
     RECT  19.073 70.608 19.217 80.232 ;
     RECT  19.145 139.68 19.217 143.208 ;
     RECT  19.187 152.16 19.217 152.712 ;
     RECT  19.181 29.04 19.253 29.208 ;
     RECT  19.217 70.608 19.253 76.92 ;
     RECT  19.043 185.904 19.283 188.568 ;
     RECT  18.997 0.048 19.285 0.072 ;
     RECT  18.904 40.416 19.325 55.56 ;
     RECT  19.217 139.728 19.325 143.208 ;
     RECT  18.904 175.824 19.325 178.488 ;
     RECT  18.965 91.44 19.331 101.496 ;
     RECT  18.904 1.728 19.361 15.576 ;
     RECT  19.283 187.392 19.361 188.568 ;
     RECT  18.904 56.64 19.379 65.256 ;
     RECT  18.904 257.472 19.379 259.32 ;
     RECT  18.904 123.696 19.397 124.824 ;
     RECT  18.904 161.136 19.427 163.08 ;
     RECT  18.904 268.464 19.427 269.016 ;
     RECT  18.904 89.472 19.433 90.024 ;
     RECT  18.904 115.44 19.433 120.888 ;
     RECT  18.904 192.576 19.433 206.232 ;
     RECT  19.043 240.288 19.433 250.104 ;
     RECT  19.379 257.52 19.433 259.32 ;
     RECT  19.181 270.576 19.468 273.336 ;
     RECT  19.433 89.712 19.469 90.024 ;
     RECT  18.904 132.816 19.469 136.728 ;
     RECT  18.904 228.432 19.475 238.344 ;
     RECT  18.904 254.064 19.475 255.624 ;
     RECT  19.421 300 19.505 300.12 ;
     RECT  19.037 167.568 19.523 173.256 ;
     RECT  19.505 300 19.523 300.024 ;
     RECT  19.117 37.056 19.541 38.184 ;
     RECT  19.397 124.8 19.571 124.824 ;
     RECT  19.468 270.96 19.577 273.336 ;
     RECT  19.132 282.096 19.577 285 ;
     RECT  18.904 125.856 19.613 129.384 ;
     RECT  19.217 152.16 19.613 152.664 ;
     RECT  19.475 228.432 19.613 235.176 ;
     RECT  19.285 0.048 19.669 0.216 ;
     RECT  19.361 1.728 19.669 2.856 ;
     RECT  19.001 20.976 19.685 22.92 ;
     RECT  19.325 40.848 19.685 55.56 ;
     RECT  19.379 56.832 19.685 65.256 ;
     RECT  18.965 102.576 19.685 112.872 ;
     RECT  19.081 179.616 19.685 184.728 ;
     RECT  19.433 240.288 19.685 247.944 ;
     RECT  19.685 179.616 19.756 183.192 ;
     RECT  18.904 31.584 19.757 35.352 ;
     RECT  19.433 115.44 19.757 120.12 ;
     RECT  19.469 135.072 19.757 136.728 ;
     RECT  19.756 179.616 19.757 183.048 ;
     RECT  19.613 126.24 19.763 129.384 ;
     RECT  19.361 3.84 19.793 15.576 ;
     RECT  19.433 196.608 19.793 206.232 ;
     RECT  19.475 236.4 19.793 238.344 ;
     RECT  18.904 137.904 19.811 138.648 ;
     RECT  19.325 139.776 19.811 143.208 ;
     RECT  19.685 45.936 19.829 55.56 ;
     RECT  19.613 228.432 19.859 232.632 ;
     RECT  19.829 47.712 19.865 55.56 ;
     RECT  19.181 145.2 19.865 147.096 ;
     RECT  18.904 156.672 19.865 157.608 ;
     RECT  18.904 213.648 19.865 218.28 ;
     RECT  19.685 240.288 19.865 240.312 ;
     RECT  18.904 265.056 19.865 265.08 ;
     RECT  18.904 130.464 19.868 131.688 ;
     RECT  19.469 132.816 19.868 134.04 ;
     RECT  18.904 164.208 19.871 164.52 ;
     RECT  18.904 165.648 19.871 166.248 ;
     RECT  18.904 159.12 19.897 159.816 ;
     RECT  19.181 274.368 19.897 278.712 ;
     RECT  19.132 279.792 19.897 281.016 ;
     RECT  19.145 286.08 19.901 297.768 ;
     RECT  19.577 271.488 19.907 273.336 ;
     RECT  18.904 251.328 19.909 251.352 ;
     RECT  18.904 252.48 19.909 253.08 ;
     RECT  19.757 35.328 19.933 35.352 ;
     RECT  19.669 0.048 19.937 2.856 ;
     RECT  19.865 50.736 19.937 55.176 ;
     RECT  19.829 45.936 19.955 46.728 ;
     RECT  19.523 167.568 19.955 168.792 ;
     RECT  19.523 169.872 19.955 173.256 ;
     RECT  19.757 179.616 19.955 183 ;
     RECT  18.904 224.16 19.955 227.448 ;
     RECT  19.859 228.432 19.955 229.704 ;
     RECT  19.859 231.024 19.955 232.632 ;
     RECT  19.685 243.888 19.955 247.944 ;
     RECT  19.909 251.328 19.955 253.08 ;
     RECT  18.904 66.48 19.957 68.376 ;
     RECT  19.897 174.288 19.957 174.312 ;
     RECT  19.325 175.824 19.957 177.768 ;
     RECT  19.217 77.952 19.969 80.232 ;
     RECT  19.757 135.312 19.969 136.728 ;
     RECT  19.427 161.136 19.969 162.888 ;
     RECT  19.433 192.576 19.969 195.576 ;
     RECT  18.904 220.56 19.969 223.176 ;
     RECT  19.955 224.16 19.969 226.632 ;
     RECT  19.865 47.712 19.973 49.656 ;
     RECT  19.897 274.368 20.003 281.016 ;
     RECT  18.904 87.792 20.005 88.344 ;
     RECT  19.469 90 20.005 90.024 ;
     RECT  19.685 102.624 20.005 112.872 ;
     RECT  18.904 113.856 20.005 114.36 ;
     RECT  19.001 207.744 20.005 212.232 ;
     RECT  19.865 213.648 20.005 218.136 ;
     RECT  18.904 261.024 20.005 261.24 ;
     RECT  18.904 24.432 20.012 26.808 ;
     RECT  19.865 145.2 20.041 146.424 ;
     RECT  19.793 237.936 20.041 238.344 ;
     RECT  20.005 90 20.051 90.552 ;
     RECT  19.331 91.728 20.051 101.496 ;
     RECT  19.433 257.664 20.051 259.32 ;
     RECT  19.685 20.976 20.053 21.096 ;
     RECT  20.012 24.432 20.053 27.288 ;
     RECT  19.955 169.968 20.053 173.256 ;
     RECT  19.957 174.288 20.053 177.768 ;
     RECT  20.053 17.088 20.077 17.208 ;
     RECT  19.897 158.208 20.077 159.816 ;
     RECT  19.969 160.8 20.077 162.888 ;
     RECT  18.904 219.36 20.077 219.576 ;
     RECT  19.969 220.56 20.077 226.632 ;
     RECT  20.005 261.024 20.077 261.288 ;
     RECT  18.904 262.512 20.077 263.976 ;
     RECT  19.955 46.032 20.081 46.728 ;
     RECT  19.955 231.408 20.081 232.632 ;
     RECT  19.685 241.296 20.099 242.856 ;
     RECT  19.793 200.16 20.101 206.232 ;
     RECT  20.005 207.744 20.101 218.136 ;
     RECT  19.685 57.024 20.113 65.256 ;
     RECT  19.957 66.24 20.113 68.376 ;
     RECT  19.955 167.568 20.113 168.552 ;
     RECT  19.901 286.08 20.113 294.696 ;
     RECT  19.933 35.328 20.147 36.456 ;
     RECT  20.053 169.968 20.147 177.768 ;
     RECT  19.955 243.888 20.147 247.896 ;
     RECT  18.904 18.72 20.149 19.848 ;
     RECT  20.053 20.88 20.149 21.096 ;
     RECT  19.757 31.584 20.149 33.096 ;
     RECT  18.904 83.232 20.149 85.608 ;
     RECT  18.904 121.968 20.149 122.568 ;
     RECT  19.283 185.904 20.149 186.264 ;
     RECT  20.051 90.528 20.153 90.552 ;
     RECT  20.147 245.616 20.153 247.896 ;
     RECT  19.907 271.488 20.153 272.088 ;
     RECT  19.969 77.952 20.185 80.376 ;
     RECT  20.053 24.432 20.189 27.384 ;
     RECT  19.397 123.696 20.189 123.816 ;
     RECT  20.081 231.408 20.189 232.584 ;
     RECT  19.955 252.24 20.189 252.792 ;
     RECT  19.685 22.176 20.197 22.92 ;
     RECT  20.189 24.432 20.197 25.176 ;
     RECT  20.147 243.888 20.197 244.392 ;
     RECT  19.907 273.072 20.197 273.336 ;
     RECT  20.003 274.368 20.197 276.072 ;
     RECT  20.003 277.584 20.197 281.016 ;
     RECT  19.577 282.096 20.197 284.664 ;
     RECT  18.904 154.224 20.221 155.112 ;
     RECT  18.904 190.032 20.221 191.448 ;
     RECT  19.685 40.848 20.225 44.952 ;
     RECT  20.189 231.408 20.243 231.768 ;
     RECT  20.197 277.584 20.243 284.664 ;
     RECT  20.113 285.984 20.243 294.696 ;
     RECT  18.929 266.208 20.245 266.952 ;
     RECT  19.427 268.464 20.245 268.488 ;
     RECT  19.187 148.56 20.257 151.176 ;
     RECT  19.871 164.208 20.257 166.248 ;
     RECT  20.221 189.696 20.257 191.448 ;
     RECT  20.149 18.72 20.269 21.096 ;
     RECT  20.189 26.4 20.291 27.384 ;
     RECT  19.253 29.184 20.291 29.208 ;
     RECT  20.204 30.288 20.291 30.312 ;
     RECT  20.149 31.44 20.291 33.096 ;
     RECT  20.101 200.16 20.291 218.136 ;
     RECT  20.005 102.624 20.293 114.36 ;
     RECT  19.757 115.44 20.293 117.576 ;
     RECT  19.901 295.824 20.293 297.768 ;
     RECT  20.293 102.624 20.297 117.576 ;
     RECT  19.757 118.608 20.297 120.12 ;
     RECT  20.243 277.584 20.297 281.544 ;
     RECT  19.763 127.872 20.3 129.384 ;
     RECT  19.868 130.464 20.3 134.04 ;
     RECT  20.257 164.112 20.329 166.248 ;
     RECT  19.955 228.432 20.329 229.368 ;
     RECT  20.245 125.184 20.332 125.208 ;
     RECT  20.113 57.024 20.333 68.376 ;
     RECT  20.149 185.808 20.333 186.264 ;
     RECT  20.041 144.768 20.337 146.424 ;
     RECT  19.937 1.728 20.341 2.856 ;
     RECT  19.793 3.84 20.341 15.528 ;
     RECT  19.253 74.592 20.341 76.92 ;
     RECT  20.341 74.4 20.365 76.92 ;
     RECT  20.197 22.176 20.369 25.176 ;
     RECT  20.369 24.336 20.387 25.176 ;
     RECT  20.3 127.872 20.387 134.04 ;
     RECT  20.221 153.984 20.396 155.112 ;
     RECT  19.811 141.456 20.401 143.208 ;
     RECT  20.337 144.24 20.401 146.424 ;
     RECT  19.361 187.392 20.401 187.512 ;
     RECT  20.333 60.048 20.405 68.376 ;
     RECT  20.077 158.208 20.405 162.888 ;
     RECT  20.297 279.888 20.405 281.544 ;
     RECT  19.433 248.928 20.429 250.104 ;
     RECT  20.197 273.072 20.433 276.072 ;
     RECT  19.937 0.048 20.435 0.552 ;
     RECT  20.149 83.232 20.437 85.704 ;
     RECT  20.329 164.016 20.437 166.248 ;
     RECT  20.113 167.232 20.437 168.552 ;
     RECT  19.475 254.256 20.437 255.624 ;
     RECT  20.437 164.016 20.441 168.552 ;
     RECT  20.429 248.928 20.444 250.248 ;
     RECT  20.437 83.232 20.473 86.088 ;
     RECT  20.245 266.208 20.473 268.488 ;
     RECT  20.291 203.904 20.476 218.136 ;
     RECT  20.405 60.048 20.477 65.304 ;
     RECT  20.387 130.272 20.477 134.04 ;
     RECT  19.969 135.312 20.477 137.496 ;
     RECT  20.441 164.112 20.477 168.552 ;
     RECT  20.147 35.568 20.483 36.456 ;
     RECT  20.291 200.16 20.483 202.92 ;
     RECT  20.437 254.256 20.485 256.2 ;
     RECT  20.257 148.56 20.492 151.56 ;
     RECT  19.969 192.528 20.492 195.576 ;
     RECT  20.077 261.024 20.509 263.976 ;
     RECT  20.225 40.848 20.513 44.904 ;
     RECT  20.297 111.984 20.513 117.576 ;
     RECT  20.444 248.928 20.531 250.488 ;
     RECT  20.257 189.456 20.533 191.448 ;
     RECT  20.492 192.432 20.533 195.576 ;
     RECT  20.291 31.44 20.545 31.464 ;
     RECT  19.865 156.672 20.545 157.224 ;
     RECT  20.533 189.456 20.545 195.576 ;
     RECT  20.041 237.936 20.545 238.92 ;
     RECT  20.509 260.928 20.545 263.976 ;
     RECT  20.477 62.688 20.549 65.304 ;
     RECT  20.476 203.904 20.549 217.56 ;
     RECT  20.492 148.368 20.579 151.56 ;
     RECT  20.153 246.192 20.579 247.896 ;
     RECT  20.531 248.928 20.579 249.768 ;
     RECT  19.253 70.608 20.581 73.368 ;
     RECT  20.365 74.352 20.581 76.92 ;
     RECT  20.149 121.68 20.581 122.568 ;
     RECT  20.189 123.696 20.581 123.768 ;
     RECT  20.401 141.456 20.585 146.424 ;
     RECT  20.405 158.208 20.585 162.6 ;
     RECT  19.793 236.4 20.588 236.904 ;
     RECT  20.147 177.216 20.617 177.768 ;
     RECT  19.955 179.616 20.617 181.32 ;
     RECT  20.545 237.936 20.617 239.064 ;
     RECT  20.545 189.312 20.645 195.576 ;
     RECT  19.793 196.608 20.645 198.888 ;
     RECT  20.333 185.904 20.653 186.264 ;
     RECT  20.401 187.392 20.653 187.8 ;
     RECT  20.581 124.848 20.665 124.872 ;
     RECT  20.549 210.336 20.675 217.56 ;
     RECT  20.581 70.608 20.677 76.92 ;
     RECT  20.185 77.952 20.677 81.336 ;
     RECT  20.473 83.04 20.689 86.088 ;
     RECT  20.005 87.12 20.689 88.344 ;
     RECT  19.613 234 20.689 235.176 ;
     RECT  20.473 266.208 20.689 268.728 ;
     RECT  20.545 156.624 20.725 157.224 ;
     RECT  20.645 189.312 20.729 198.888 ;
     RECT  19.937 50.736 20.765 54.6 ;
     RECT  20.189 252.384 20.771 252.792 ;
     RECT  20.387 127.872 20.773 129.192 ;
     RECT  20.405 66.48 20.797 68.376 ;
     RECT  19.763 126.24 20.797 126.264 ;
     RECT  19.613 152.64 20.797 152.664 ;
     RECT  20.099 241.68 20.797 242.856 ;
     RECT  20.545 31.392 20.801 31.464 ;
     RECT  20.477 164.16 20.819 168.552 ;
     RECT  19.973 47.712 20.828 49.608 ;
     RECT  20.585 141.456 20.828 142.632 ;
     RECT  20.797 66.48 20.833 68.52 ;
     RECT  20.689 83.04 20.833 88.344 ;
     RECT  20.477 133.44 20.833 134.04 ;
     RECT  20.329 227.952 20.837 229.368 ;
     RECT  20.797 241.68 20.867 243.24 ;
     RECT  19.541 37.584 20.869 38.184 ;
     RECT  19.117 39.312 20.869 39.336 ;
     RECT  20.051 94.08 20.869 101.496 ;
     RECT  20.797 152.64 20.869 152.856 ;
     RECT  20.396 153.984 20.869 155.4 ;
     RECT  20.293 295.824 20.869 298.056 ;
     RECT  20.675 210.384 20.873 211.08 ;
     RECT  20.341 1.728 20.905 15.528 ;
     RECT  20.077 16.512 20.905 17.208 ;
     RECT  20.585 143.664 20.905 146.424 ;
     RECT  20.243 282.864 20.905 284.664 ;
     RECT  20.147 169.968 20.909 175.992 ;
     RECT  20.729 189.312 20.909 194.088 ;
     RECT  19.685 184.176 20.915 184.728 ;
     RECT  20.867 243.216 20.915 243.24 ;
     RECT  20.771 252.384 20.915 252.648 ;
     RECT  20.689 234 20.917 235.224 ;
     RECT  20.588 236.208 20.917 236.904 ;
     RECT  20.545 260.928 20.924 264.84 ;
     RECT  20.333 57.024 20.941 58.776 ;
     RECT  20.153 271.488 20.941 271.512 ;
     RECT  20.369 22.8 20.945 23.352 ;
     RECT  20.477 60.048 20.945 61.176 ;
     RECT  20.513 112.224 20.945 117.576 ;
     RECT  20.909 173.856 20.945 175.992 ;
     RECT  20.945 22.8 20.953 22.824 ;
     RECT  20.549 203.904 20.956 209.304 ;
     RECT  20.873 210.384 20.963 210.936 ;
     RECT  20.485 259.872 20.965 259.896 ;
     RECT  20.924 260.88 20.965 264.84 ;
     RECT  20.689 266.208 20.965 269.064 ;
     RECT  20.483 35.952 20.977 36.456 ;
     RECT  20.869 37.584 20.977 39.336 ;
     RECT  20.579 148.416 20.977 151.56 ;
     RECT  20.869 152.64 20.977 155.4 ;
     RECT  20.917 234 20.977 236.904 ;
     RECT  20.617 237.936 20.977 240.024 ;
     RECT  20.051 257.664 20.977 258.888 ;
     RECT  20.833 66.48 21.013 68.712 ;
     RECT  20.977 148.416 21.013 155.4 ;
     RECT  20.725 156.576 21.013 157.224 ;
     RECT  20.963 210.384 21.017 210.456 ;
     RECT  20.197 244.224 21.017 244.392 ;
     RECT  20.725 28.464 21.048 28.488 ;
     RECT  20.833 82.656 21.049 88.344 ;
     RECT  20.051 91.728 21.049 93.048 ;
     RECT  20.869 94.08 21.049 101.544 ;
     RECT  20.297 102.624 21.049 110.808 ;
     RECT  20.581 121.68 21.049 123.768 ;
     RECT  20.077 219.36 21.049 226.632 ;
     RECT  20.837 227.952 21.049 227.976 ;
     RECT  20.819 164.4 21.053 168.552 ;
     RECT  20.677 70.608 21.059 81.336 ;
     RECT  20.243 286.08 21.059 294.696 ;
     RECT  20.977 35.952 21.068 39.336 ;
     RECT  20.828 47.088 21.068 49.608 ;
     RECT  21.059 286.656 21.077 294.696 ;
     RECT  20.869 295.776 21.077 298.056 ;
     RECT  21.059 73.008 21.085 81.336 ;
     RECT  20.297 118.656 21.085 120.12 ;
     RECT  21.049 121.392 21.085 123.768 ;
     RECT  21.013 148.416 21.085 157.224 ;
     RECT  20.585 158.208 21.085 158.616 ;
     RECT  20.729 195.12 21.085 198.888 ;
     RECT  20.401 29.568 21.089 30.216 ;
     RECT  20.956 209.28 21.089 209.304 ;
     RECT  20.945 60.096 21.107 61.176 ;
     RECT  21.085 73.008 21.107 81.432 ;
     RECT  20.801 31.392 21.109 31.416 ;
     RECT  21.107 73.248 21.109 81.432 ;
     RECT  21.049 82.464 21.109 88.344 ;
     RECT  21.053 164.64 21.109 168.552 ;
     RECT  20.977 234 21.109 240.024 ;
     RECT  20.485 254.016 21.109 256.2 ;
     RECT  20.977 257.52 21.109 258.888 ;
     RECT  20.941 270.72 21.109 271.512 ;
     RECT  21.077 286.656 21.109 298.056 ;
     RECT  20.269 18.72 21.125 20.664 ;
     RECT  20.833 133.44 21.125 134.28 ;
     RECT  21.049 219.36 21.125 227.976 ;
     RECT  20.405 280.32 21.125 281.544 ;
     RECT  21.089 30.192 21.155 30.216 ;
     RECT  21.068 46.224 21.155 49.608 ;
     RECT  20.585 159.648 21.155 162.6 ;
     RECT  21.109 233.472 21.155 240.024 ;
     RECT  21.109 73.248 21.157 88.344 ;
     RECT  21.049 91.728 21.157 101.544 ;
     RECT  21.049 102.528 21.157 110.808 ;
     RECT  20.617 177.216 21.157 181.32 ;
     RECT  19.955 182.4 21.157 183 ;
     RECT  21.155 235.152 21.157 240.024 ;
     RECT  21.109 270.624 21.157 271.512 ;
     RECT  21.157 73.248 21.161 88.968 ;
     RECT  21.157 91.728 21.161 110.808 ;
     RECT  21.125 133.776 21.161 134.28 ;
     RECT  21.109 164.64 21.161 168.648 ;
     RECT  20.905 282.864 21.161 284.952 ;
     RECT  21.109 286.656 21.161 298.248 ;
     RECT  21.155 46.848 21.169 49.608 ;
     RECT  20.291 26.4 21.193 26.424 ;
     RECT  20.291 32.496 21.193 33.096 ;
     RECT  19.757 34.08 21.193 34.104 ;
     RECT  21.068 35.952 21.193 39.864 ;
     RECT  20.513 40.848 21.193 43.944 ;
     RECT  21.059 70.608 21.193 71.976 ;
     RECT  20.945 173.904 21.193 175.992 ;
     RECT  21.157 177.216 21.193 183 ;
     RECT  20.915 252.384 21.193 252.504 ;
     RECT  21.161 91.728 21.203 110.568 ;
     RECT  20.905 1.728 21.205 17.544 ;
     RECT  20.915 184.704 21.205 184.728 ;
     RECT  20.433 273.744 21.205 276.072 ;
     RECT  21.161 80.976 21.229 88.968 ;
     RECT  21.085 90 21.229 90.024 ;
     RECT  21.085 195.12 21.229 199.176 ;
     RECT  20.483 200.16 21.229 202.872 ;
     RECT  20.945 112.272 21.233 117.576 ;
     RECT  21.085 148.416 21.233 158.616 ;
     RECT  21.155 161.664 21.233 162.6 ;
     RECT  20.579 249.168 21.233 249.768 ;
     RECT  21.161 282.864 21.233 283.08 ;
     RECT  21.109 253.632 21.253 258.888 ;
     RECT  20.965 259.872 21.253 269.064 ;
     RECT  20.797 126.24 21.265 126.696 ;
     RECT  20.773 127.68 21.265 129.192 ;
     RECT  20.243 231.408 21.265 231.72 ;
     RECT  20.765 50.736 21.269 51.144 ;
     RECT  21.085 118.656 21.269 123.768 ;
     RECT  21.161 164.832 21.269 168.648 ;
     RECT  21.193 32.496 21.277 34.104 ;
     RECT  21.229 80.976 21.305 90.024 ;
     RECT  21.265 231.408 21.305 232.488 ;
     RECT  21.155 233.472 21.305 233.496 ;
     RECT  20.941 56.976 21.312 58.776 ;
     RECT  20.653 185.904 21.337 187.8 ;
     RECT  21.017 244.224 21.337 244.248 ;
     RECT  21.253 282.384 21.34 282.744 ;
     RECT  21.305 231.408 21.341 231.432 ;
     RECT  21.157 235.152 21.341 240.36 ;
     RECT  21.305 88.272 21.347 90.024 ;
     RECT  21.253 253.632 21.349 269.064 ;
     RECT  21.157 270.624 21.349 271.8 ;
     RECT  21.203 91.728 21.356 94.488 ;
     RECT  21.265 126.24 21.409 129.192 ;
     RECT  21.305 80.976 21.413 87.096 ;
     RECT  21.155 159.648 21.413 160.536 ;
     RECT  21.356 91.488 21.443 94.488 ;
     RECT  19.811 139.776 21.445 140.232 ;
     RECT  20.828 141.408 21.445 142.632 ;
     RECT  21.233 161.904 21.445 162.6 ;
     RECT  21.107 60.096 21.449 61.032 ;
     RECT  21.203 95.76 21.449 110.568 ;
     RECT  21.233 112.272 21.449 114.072 ;
     RECT  21.341 240 21.449 240.36 ;
     RECT  21.193 25.728 21.481 26.424 ;
     RECT  20.549 64.032 21.481 65.304 ;
     RECT  21.229 195.12 21.481 202.872 ;
     RECT  20.956 203.904 21.481 207.768 ;
     RECT  21.193 251.808 21.481 252.504 ;
     RECT  21.349 253.632 21.481 271.8 ;
     RECT  20.297 277.584 21.481 278.568 ;
     RECT  21.125 19.248 21.485 20.664 ;
     RECT  21.347 88.272 21.485 88.968 ;
     RECT  21.161 284.112 21.485 284.952 ;
     RECT  21.449 60.096 21.491 60.936 ;
     RECT  21.233 249.264 21.491 249.768 ;
     RECT  21.481 251.472 21.493 252.504 ;
     RECT  21.347 90 21.504 90.024 ;
     RECT  21.193 173.904 21.509 183 ;
     RECT  20.765 52.272 21.517 54.6 ;
     RECT  20.675 212.592 21.517 217.56 ;
     RECT  21.193 35.952 21.539 43.944 ;
     RECT  21.205 184.704 21.553 184.776 ;
     RECT  21.337 185.904 21.553 187.848 ;
     RECT  21.517 212.592 21.553 218.136 ;
     RECT  21.445 231.072 21.553 231.192 ;
     RECT  20.579 246.192 21.553 246.984 ;
     RECT  21.485 19.248 21.557 20.424 ;
     RECT  21.413 82.464 21.557 87.096 ;
     RECT  21.449 97.824 21.557 110.568 ;
     RECT  21.161 295.776 21.557 298.248 ;
     RECT  21.445 139.776 21.587 142.632 ;
     RECT  21.553 231.024 21.587 231.192 ;
     RECT  20.387 24.336 21.589 24.456 ;
     RECT  21.481 25.728 21.589 26.856 ;
     RECT  21.409 126.24 21.589 129.24 ;
     RECT  20.867 241.68 21.589 242.184 ;
     RECT  21.553 246.192 21.589 247.272 ;
     RECT  21.587 139.776 21.593 142.392 ;
     RECT  21.445 161.904 21.593 162.744 ;
     RECT  21.509 173.904 21.593 183.576 ;
     RECT  21.481 253.632 21.593 272.232 ;
     RECT  21.481 64.032 21.596 65.496 ;
     RECT  21.013 66.48 21.596 68.952 ;
     RECT  21.589 125.088 21.625 129.24 ;
     RECT  20.477 130.272 21.625 132.216 ;
     RECT  21.269 166.752 21.625 168.648 ;
     RECT  21.205 273.744 21.625 276.456 ;
     RECT  21.481 277.584 21.625 279.336 ;
     RECT  21.553 184.704 21.629 187.848 ;
     RECT  21.548 300.144 21.635 300.168 ;
     RECT  21.233 115.104 21.637 117.576 ;
     RECT  21.269 118.656 21.637 123.672 ;
     RECT  21.161 134.256 21.637 134.28 ;
     RECT  20.477 135.312 21.637 136.728 ;
     RECT  19.811 138.528 21.637 138.648 ;
     RECT  21.593 139.776 21.637 141.912 ;
     RECT  21.593 162 21.637 162.744 ;
     RECT  21.541 62.16 21.661 62.184 ;
     RECT  21.125 225.504 21.665 227.976 ;
     RECT  21.491 249.264 21.665 249.72 ;
     RECT  21.485 284.928 21.665 284.952 ;
     RECT  20.435 0.288 21.683 0.552 ;
     RECT  21.596 64.032 21.683 68.952 ;
     RECT  21.557 98.16 21.683 110.568 ;
     RECT  21.637 138.528 21.683 141.912 ;
     RECT  21.593 173.904 21.683 182.952 ;
     RECT  21.539 38.064 21.697 43.944 ;
     RECT  21.683 98.16 21.701 105.144 ;
     RECT  21.233 153.936 21.701 158.616 ;
     RECT  21.683 177.216 21.701 182.952 ;
     RECT  21.481 195.12 21.701 207.768 ;
     RECT  21.593 257.088 21.701 272.232 ;
     RECT  21.449 95.76 21.731 96.792 ;
     RECT  21.205 1.728 21.733 17.688 ;
     RECT  21.277 34.08 21.733 34.104 ;
     RECT  20.909 189.456 21.733 194.088 ;
     RECT  21.701 195.12 21.733 199.176 ;
     RECT  21.625 125.088 21.737 132.216 ;
     RECT  21.701 155.904 21.779 158.616 ;
     RECT  21.625 273.744 21.781 279.336 ;
     RECT  21.109 31.248 21.805 31.416 ;
     RECT  21.683 64.032 21.805 65.496 ;
     RECT  21.637 134.256 21.805 136.824 ;
     RECT  21.733 1.728 21.809 18.264 ;
     RECT  21.733 34.08 21.829 34.968 ;
     RECT  21.539 35.952 21.829 36.984 ;
     RECT  21.683 66.48 21.829 68.952 ;
     RECT  21.193 69.984 21.829 71.976 ;
     RECT  21.665 226.272 21.829 227.976 ;
     RECT  20.837 229.008 21.829 229.368 ;
     RECT  21.637 162 21.836 163.032 ;
     RECT  21.553 212.592 21.836 218.328 ;
     RECT  21.125 219.36 21.836 224.472 ;
     RECT  21.589 24.336 21.845 26.856 ;
     RECT  21.805 63.744 21.877 65.496 ;
     RECT  20.909 169.968 21.877 172.296 ;
     RECT  21.733 189.456 21.877 199.176 ;
     RECT  21.557 82.656 21.881 87.096 ;
     RECT  21.836 212.592 21.881 224.472 ;
     RECT  21.701 257.088 21.881 269.976 ;
     RECT  21.877 21.744 21.913 21.768 ;
     RECT  21.312 56.976 21.913 58.056 ;
     RECT  21.589 240.96 21.913 242.184 ;
     RECT  21.683 173.904 21.917 175.992 ;
     RECT  21.881 257.088 21.917 269.592 ;
     RECT  21.913 56.928 21.949 58.056 ;
     RECT  21.683 138.528 21.949 139.56 ;
     RECT  21.337 243.648 21.949 244.248 ;
     RECT  21.701 200.16 21.971 207.768 ;
     RECT  21.884 211.68 21.971 211.704 ;
     RECT  21.017 210.432 21.985 210.456 ;
     RECT  21.449 112.368 21.989 114.072 ;
     RECT  21.629 185.136 21.989 187.848 ;
     RECT  21.701 177.216 22.012 178.584 ;
     RECT  21.805 30.912 22.021 31.416 ;
     RECT  21.277 32.496 22.021 32.808 ;
     RECT  21.829 226.272 22.021 229.704 ;
     RECT  21.587 231.024 22.021 231.096 ;
     RECT  21.443 92.304 22.025 94.488 ;
     RECT  21.779 157.152 22.025 158.616 ;
     RECT  21.697 38.064 22.028 44.232 ;
     RECT  21.695 45.696 22.028 45.72 ;
     RECT  21.637 115.104 22.033 123.672 ;
     RECT  20.905 143.664 22.057 146.856 ;
     RECT  21.781 273.264 22.067 279.336 ;
     RECT  21.985 23.328 22.069 23.352 ;
     RECT  21.845 24.336 22.069 24.456 ;
     RECT  21.845 25.872 22.069 26.856 ;
     RECT  21.048 27.888 22.069 28.488 ;
     RECT  22.033 115.104 22.097 117.96 ;
     RECT  21.917 265.344 22.097 269.592 ;
     RECT  22.069 23.328 22.115 24.456 ;
     RECT  22.028 38.064 22.115 45.72 ;
     RECT  21.949 243.552 22.129 244.248 ;
     RECT  21.589 246.192 22.129 247.944 ;
     RECT  21.701 98.16 22.133 102.744 ;
     RECT  22.069 25.872 22.156 28.488 ;
     RECT  21.413 159.792 22.165 160.536 ;
     RECT  21.125 280.608 22.165 280.632 ;
     RECT  21.557 296.4 22.165 298.248 ;
     RECT  21.809 18.24 22.169 18.264 ;
     RECT  22.115 23.856 22.169 24.456 ;
     RECT  22.021 30.912 22.169 32.808 ;
     RECT  22.067 273.264 22.169 279.192 ;
     RECT  22.012 177.264 22.177 178.584 ;
     RECT  21.625 166.752 22.201 168.84 ;
     RECT  21.161 73.248 22.205 79.944 ;
     RECT  21.233 148.416 22.205 152.856 ;
     RECT  21.269 164.832 22.205 165.672 ;
     RECT  22.115 38.064 22.211 42.216 ;
     RECT  21.169 46.848 22.211 49.464 ;
     RECT  22.205 151.152 22.211 152.856 ;
     RECT  22.165 296.4 22.211 298.728 ;
     RECT  21.557 19.248 22.213 20.088 ;
     RECT  21.805 134.256 22.213 136.92 ;
     RECT  21.949 138.432 22.213 139.56 ;
     RECT  22.201 166.752 22.213 168.984 ;
     RECT  21.877 169.968 22.213 172.728 ;
     RECT  22.165 280.416 22.213 280.632 ;
     RECT  22.165 281.664 22.213 281.688 ;
     RECT  21.161 286.656 22.213 294.696 ;
     RECT  21.949 59.04 22.259 59.064 ;
     RECT  21.34 282.72 22.259 282.744 ;
     RECT  21.737 125.088 22.261 131.208 ;
     RECT  21.737 132.192 22.261 132.216 ;
     RECT  21.989 187.776 22.261 187.848 ;
     RECT  21.877 189.024 22.261 199.176 ;
     RECT  22.129 243.552 22.268 247.944 ;
     RECT  22.213 285.984 22.273 294.936 ;
     RECT  21.829 66.48 22.277 71.976 ;
     RECT  22.205 73.248 22.277 78.168 ;
     RECT  21.917 174.528 22.277 175.992 ;
     RECT  21.881 212.976 22.277 224.472 ;
     RECT  21.913 21.648 22.309 21.768 ;
     RECT  22.261 132.192 22.309 132.696 ;
     RECT  21.305 232.464 22.309 232.488 ;
     RECT  21.913 240.96 22.309 242.28 ;
     RECT  22.268 243.552 22.309 248.472 ;
     RECT  21.269 51.12 22.313 51.144 ;
     RECT  22.273 285.312 22.313 294.936 ;
     RECT  22.211 296.976 22.313 298.728 ;
     RECT  22.156 26.016 22.348 28.488 ;
     RECT  22.309 240.96 22.349 248.472 ;
     RECT  21.917 257.088 22.349 264.264 ;
     RECT  22.213 18.768 22.355 20.088 ;
     RECT  22.213 30.816 22.355 30.84 ;
     RECT  22.211 38.736 22.355 42.216 ;
     RECT  22.349 247.92 22.355 248.472 ;
     RECT  21.829 34.08 22.381 36.984 ;
     RECT  22.205 79.152 22.381 79.944 ;
     RECT  21.413 80.976 22.381 81.432 ;
     RECT  22.277 217.536 22.381 224.472 ;
     RECT  22.309 232.464 22.381 232.68 ;
     RECT  22.211 151.152 22.385 152.76 ;
     RECT  21.341 235.152 22.385 238.92 ;
     RECT  22.033 119.184 22.403 123.672 ;
     RECT  21.683 0.528 22.421 0.552 ;
     RECT  21.971 200.16 22.421 206.952 ;
     RECT  22.313 297.552 22.451 298.728 ;
     RECT  22.309 21.648 22.453 22.344 ;
     RECT  22.277 73.248 22.453 77.928 ;
     RECT  22.205 165.072 22.453 165.672 ;
     RECT  22.385 235.152 22.453 238.872 ;
     RECT  21.665 249.648 22.453 249.72 ;
     RECT  22.277 66.528 22.457 71.976 ;
     RECT  22.381 79.152 22.457 81.432 ;
     RECT  21.683 140.736 22.457 141.912 ;
     RECT  22.261 187.776 22.457 199.176 ;
     RECT  22.348 28.32 22.46 28.488 ;
     RECT  21.701 271.488 22.489 272.232 ;
     RECT  22.169 273.264 22.489 276.36 ;
     RECT  21.493 250.896 22.499 252.504 ;
     RECT  22.213 134.256 22.501 139.56 ;
     RECT  22.355 19.056 22.525 20.088 ;
     RECT  22.381 33.888 22.525 36.984 ;
     RECT  22.453 208.752 22.525 208.776 ;
     RECT  22.453 249.648 22.525 249.912 ;
     RECT  22.499 250.896 22.525 251.688 ;
     RECT  22.261 124.8 22.529 131.208 ;
     RECT  22.421 202.368 22.529 206.952 ;
     RECT  22.46 28.32 22.547 29.016 ;
     RECT  22.457 187.776 22.547 198.936 ;
     RECT  22.349 257.088 22.547 263.976 ;
     RECT  21.949 56.064 22.556 58.056 ;
     RECT  22.165 159.792 22.556 160.728 ;
     RECT  21.593 253.632 22.556 256.056 ;
     RECT  22.547 257.088 22.556 263.88 ;
     RECT  21.485 88.272 22.561 88.92 ;
     RECT  22.457 66.624 22.565 71.976 ;
     RECT  22.457 79.152 22.565 81.192 ;
     RECT  22.556 253.632 22.565 263.88 ;
     RECT  22.489 271.488 22.565 276.36 ;
     RECT  21.517 52.272 22.597 54.648 ;
     RECT  22.556 55.824 22.597 58.056 ;
     RECT  21.881 83.04 22.597 87.096 ;
     RECT  22.561 88.272 22.597 89.496 ;
     RECT  21.731 95.808 22.597 96.792 ;
     RECT  22.529 202.368 22.601 206.376 ;
     RECT  21.985 209.856 22.601 210.456 ;
     RECT  21.661 62.112 22.633 62.184 ;
     RECT  21.877 63.312 22.633 65.496 ;
     RECT  22.349 240.96 22.633 246.888 ;
     RECT  22.597 83.04 22.637 89.544 ;
     RECT  22.501 133.968 22.637 139.56 ;
     RECT  22.025 158.16 22.637 158.616 ;
     RECT  22.313 285.312 22.637 294.744 ;
     RECT  22.637 158.16 22.643 158.424 ;
     RECT  22.556 159.6 22.643 160.728 ;
     RECT  22.633 240.528 22.643 246.888 ;
     RECT  22.097 265.824 22.643 269.592 ;
     RECT  22.451 297.552 22.643 298.152 ;
     RECT  21.989 185.136 22.645 186.792 ;
     RECT  22.643 240.528 22.645 243.288 ;
     RECT  21.491 60.096 22.652 60.888 ;
     RECT  22.633 62.112 22.652 65.496 ;
     RECT  21.683 106.176 22.669 110.568 ;
     RECT  22.643 160.416 22.669 160.728 ;
     RECT  21.836 162 22.669 163.128 ;
     RECT  22.277 174.96 22.673 175.992 ;
     RECT  22.565 253.632 22.673 259.32 ;
     RECT  22.693 300 22.7 300.024 ;
     RECT  22.565 71.808 22.705 71.976 ;
     RECT  22.133 101.76 22.705 102.744 ;
     RECT  21.701 104.016 22.705 105.144 ;
     RECT  21.809 1.728 22.709 17.112 ;
     RECT  22.565 260.304 22.709 263.88 ;
     RECT  22.025 94.032 22.741 94.488 ;
     RECT  21.701 153.936 22.741 154.92 ;
     RECT  21.779 155.904 22.741 155.928 ;
     RECT  22.669 160.416 22.741 163.128 ;
     RECT  22.453 73.2 22.745 77.928 ;
     RECT  22.177 177.456 22.745 178.584 ;
     RECT  22.597 52.272 22.781 58.056 ;
     RECT  22.565 66.624 22.781 70.728 ;
     RECT  22.637 83.04 22.781 87.816 ;
     RECT  22.547 187.776 22.781 197.16 ;
     RECT  22.643 268.224 22.781 269.592 ;
     RECT  22.7 300 22.787 300.12 ;
     RECT  22.597 95.808 22.789 96.936 ;
     RECT  22.705 101.76 22.789 105.144 ;
     RECT  22.669 106.176 22.789 111.192 ;
     RECT  22.645 184.848 22.789 186.792 ;
     RECT  22.021 226.272 22.789 231.096 ;
     RECT  22.381 232.224 22.789 232.68 ;
     RECT  22.205 148.416 22.813 150.072 ;
     RECT  22.453 165.072 22.813 165.72 ;
     RECT  22.213 166.752 22.813 172.728 ;
     RECT  22.547 28.32 22.817 28.488 ;
     RECT  22.115 43.296 22.817 44.76 ;
     RECT  22.385 151.44 22.817 152.76 ;
     RECT  22.643 158.16 22.817 158.184 ;
     RECT  22.813 165.072 22.817 173.16 ;
     RECT  22.381 217.536 22.817 225.048 ;
     RECT  22.817 151.536 22.835 152.76 ;
     RECT  22.309 132.192 22.837 132.792 ;
     RECT  22.637 133.968 22.837 139.128 ;
     RECT  22.211 46.848 22.849 49.128 ;
     RECT  22.277 212.976 22.849 216.552 ;
     RECT  22.453 234.864 22.849 238.872 ;
     RECT  22.525 19.056 22.853 20.232 ;
     RECT  22.741 160.416 22.853 163.416 ;
     RECT  22.133 98.16 22.883 100.776 ;
     RECT  22.789 184.752 22.883 186.792 ;
     RECT  22.789 95.664 22.885 97.176 ;
     RECT  22.883 98.16 22.885 100.584 ;
     RECT  22.673 175.152 22.885 175.992 ;
     RECT  22.709 16.128 22.889 17.112 ;
     RECT  22.547 198.288 22.889 198.936 ;
     RECT  22.601 209.856 22.889 210.168 ;
     RECT  22.709 260.352 22.889 263.88 ;
     RECT  22.817 217.536 22.897 224.856 ;
     RECT  22.169 32.16 22.921 32.808 ;
     RECT  22.525 33.888 22.921 37.656 ;
     RECT  22.837 132.192 22.921 132.84 ;
     RECT  22.837 133.824 22.921 139.128 ;
     RECT  22.789 226.272 22.921 232.68 ;
     RECT  22.781 187.776 22.925 197.112 ;
     RECT  22.849 234.528 22.925 238.872 ;
     RECT  22.673 253.92 22.925 259.32 ;
     RECT  21.989 112.656 22.957 114.072 ;
     RECT  22.643 265.824 22.972 266.952 ;
     RECT  22.403 122.448 22.993 123.672 ;
     RECT  22.957 211.2 22.993 211.224 ;
     RECT  22.849 212.88 22.993 216.552 ;
     RECT  22.645 240.384 22.993 243.288 ;
     RECT  22.993 240.24 22.997 243.288 ;
     RECT  22.525 249.648 22.997 251.688 ;
     RECT  22.355 38.976 23.027 42.216 ;
     RECT  22.972 266.16 23.027 266.952 ;
     RECT  22.705 71.808 23.029 72.024 ;
     RECT  22.745 73.2 23.029 73.608 ;
     RECT  22.025 92.304 23.029 93.048 ;
     RECT  22.957 112.464 23.029 114.072 ;
     RECT  22.097 115.104 23.029 117.816 ;
     RECT  22.883 184.752 23.029 186.408 ;
     RECT  22.057 143.424 23.033 146.856 ;
     RECT  22.817 165.072 23.033 172.152 ;
     RECT  22.885 175.152 23.033 176.184 ;
     RECT  22.993 211.2 23.033 216.552 ;
     RECT  22.781 268.464 23.036 269.592 ;
     RECT  22.652 60.096 23.101 65.496 ;
     RECT  21.701 179.616 23.101 182.952 ;
     RECT  22.813 0.288 23.125 0.312 ;
     RECT  22.637 88.8 23.137 89.544 ;
     RECT  23.029 90.528 23.137 90.552 ;
     RECT  22.529 125.328 23.137 131.208 ;
     RECT  22.921 132.192 23.137 139.128 ;
     RECT  23.029 184.704 23.137 186.408 ;
     RECT  22.565 274.368 23.137 276.36 ;
     RECT  22.348 26.016 23.173 26.856 ;
     RECT  22.741 94.032 23.209 94.632 ;
     RECT  22.885 95.664 23.209 100.584 ;
     RECT  23.029 112.464 23.209 117.816 ;
     RECT  23.137 274.368 23.209 276.456 ;
     RECT  22.169 277.44 23.209 279.192 ;
     RECT  22.849 46.752 23.221 49.128 ;
     RECT  22.565 271.488 23.221 273.384 ;
     RECT  22.813 147.84 23.245 150.072 ;
     RECT  22.853 163.392 23.245 163.416 ;
     RECT  23.209 274.368 23.245 279.192 ;
     RECT  23.101 59.184 23.269 65.496 ;
     RECT  22.781 83.04 23.269 87.72 ;
     RECT  22.817 173.136 23.269 173.16 ;
     RECT  22.637 285.312 23.276 285.336 ;
     RECT  23.027 39.888 23.281 42.216 ;
     RECT  23.137 88.8 23.281 90.552 ;
     RECT  23.029 92.208 23.281 93.048 ;
     RECT  23.209 94.032 23.281 100.584 ;
     RECT  23.245 163.392 23.281 163.464 ;
     RECT  22.213 280.416 23.281 281.688 ;
     RECT  23.276 284.352 23.317 285.336 ;
     RECT  22.745 74.688 23.353 77.928 ;
     RECT  22.565 79.152 23.353 79.752 ;
     RECT  22.637 286.416 23.353 294.744 ;
     RECT  22.169 23.856 23.365 23.88 ;
     RECT  23.173 25.536 23.365 26.856 ;
     RECT  23.353 30.864 23.389 30.888 ;
     RECT  22.921 32.16 23.389 37.656 ;
     RECT  23.033 143.424 23.389 146.664 ;
     RECT  22.525 208.32 23.42 208.776 ;
     RECT  22.835 152.736 23.425 152.76 ;
     RECT  22.741 153.936 23.425 155.928 ;
     RECT  23.389 142.752 23.461 146.664 ;
     RECT  23.033 175.44 23.461 176.184 ;
     RECT  22.745 177.456 23.461 178.536 ;
     RECT  23.137 184.656 23.461 186.408 ;
     RECT  22.889 16.512 23.497 17.112 ;
     RECT  23.365 23.856 23.497 26.856 ;
     RECT  22.993 122.448 23.497 124.008 ;
     RECT  23.42 208.32 23.533 209.16 ;
     RECT  23.125 0.192 23.537 0.312 ;
     RECT  22.817 28.464 23.557 28.488 ;
     RECT  22.643 244.272 23.557 246.888 ;
     RECT  22.355 247.92 23.557 247.944 ;
     RECT  22.889 260.4 23.569 263.88 ;
     RECT  22.781 52.272 23.605 57.96 ;
     RECT  23.353 74.688 23.605 79.752 ;
     RECT  22.565 80.88 23.605 81.192 ;
     RECT  22.457 140.736 23.605 141.576 ;
     RECT  23.461 142.704 23.605 146.664 ;
     RECT  22.421 200.16 23.605 201.384 ;
     RECT  22.601 202.416 23.605 206.376 ;
     RECT  22.643 297.552 23.605 298.104 ;
     RECT  23.605 200.16 23.612 206.376 ;
     RECT  23.461 184.56 23.633 186.408 ;
     RECT  23.612 200.16 23.641 206.808 ;
     RECT  23.389 30.864 23.677 37.656 ;
     RECT  23.269 82.656 23.677 87.72 ;
     RECT  23.497 122.448 23.677 124.248 ;
     RECT  23.281 39.888 23.701 42.312 ;
     RECT  22.817 43.296 23.701 44.664 ;
     RECT  23.281 280.32 23.701 281.688 ;
     RECT  23.365 282.672 23.701 282.696 ;
     RECT  23.221 46.752 23.713 49.8 ;
     RECT  22.781 70.08 23.749 70.728 ;
     RECT  23.029 71.808 23.749 73.608 ;
     RECT  22.025 157.152 23.749 157.176 ;
     RECT  23.101 179.616 23.749 183.096 ;
     RECT  23.633 184.224 23.749 186.408 ;
     RECT  22.889 210.144 23.749 210.168 ;
     RECT  23.033 211.2 23.749 212.568 ;
     RECT  22.925 234.528 23.749 237.672 ;
     RECT  23.317 283.776 23.749 285.336 ;
     RECT  23.353 286.416 23.749 295.272 ;
     RECT  23.713 46.752 23.756 50.136 ;
     RECT  23.605 51.36 23.756 57.96 ;
     RECT  22.709 1.728 23.785 14.808 ;
     RECT  22.853 19.056 23.785 19.08 ;
     RECT  22.897 218.256 23.797 224.856 ;
     RECT  22.921 226.176 23.797 232.68 ;
     RECT  23.425 152.736 23.821 155.928 ;
     RECT  23.749 157.152 23.821 157.848 ;
     RECT  23.797 218.256 23.821 232.68 ;
     RECT  22.925 191.472 23.845 197.112 ;
     RECT  23.641 252.912 23.845 252.936 ;
     RECT  23.027 266.304 23.852 266.952 ;
     RECT  23.749 70.08 23.857 73.608 ;
     RECT  23.605 74.688 23.857 81.192 ;
     RECT  23.677 82.176 23.857 87.72 ;
     RECT  22.789 101.76 23.857 111.192 ;
     RECT  22.835 151.536 23.857 151.56 ;
     RECT  23.821 152.64 23.857 155.928 ;
     RECT  23.749 234.144 23.857 237.672 ;
     RECT  23.756 46.752 23.885 57.96 ;
     RECT  23.269 59.088 23.885 65.496 ;
     RECT  23.497 16.512 23.893 17.4 ;
     RECT  22.453 21.648 23.893 22.584 ;
     RECT  22.781 66.624 23.893 68.376 ;
     RECT  23.857 70.08 23.893 87.72 ;
     RECT  23.281 88.8 23.893 100.584 ;
     RECT  23.137 125.328 23.893 139.128 ;
     RECT  23.605 140.736 23.893 146.664 ;
     RECT  23.821 157.152 23.893 157.896 ;
     RECT  22.889 198.624 23.893 198.936 ;
     RECT  23.641 200.16 23.893 206.952 ;
     RECT  23.852 266.304 23.893 267 ;
     RECT  23.036 268.464 23.893 270.168 ;
     RECT  23.893 66.624 23.929 68.712 ;
     RECT  23.857 101.712 23.929 111.192 ;
     RECT  23.033 165.072 23.929 165.72 ;
     RECT  22.885 299.28 23.933 299.304 ;
     RECT  23.885 46.752 23.965 65.496 ;
     RECT  23.929 66.624 23.965 68.808 ;
     RECT  22.925 187.776 23.965 190.344 ;
     RECT  23.845 191.472 23.965 197.256 ;
     RECT  23.557 244.272 23.965 247.944 ;
     RECT  22.997 249.696 23.965 251.4 ;
     RECT  23.893 157.152 24.001 158.424 ;
     RECT  23.845 252.48 24.001 252.936 ;
     RECT  22.925 254.208 24.001 259.32 ;
     RECT  23.785 1.728 24.008 14.856 ;
     RECT  23.893 16.368 24.008 17.4 ;
     RECT  23.785 18.768 24.008 19.08 ;
     RECT  22.853 20.208 24.008 20.232 ;
     RECT  23.893 21.648 24.008 22.872 ;
     RECT  23.497 23.856 24.008 27.144 ;
     RECT  23.557 28.464 24.008 29.4 ;
     RECT  23.677 30.72 24.008 37.656 ;
     RECT  23.317 38.784 24.008 38.808 ;
     RECT  23.701 39.888 24.008 44.664 ;
     RECT  23.965 46.608 24.008 68.952 ;
     RECT  23.893 70.08 24.008 100.584 ;
     RECT  23.929 101.664 24.008 111.192 ;
     RECT  23.209 112.464 24.008 117.912 ;
     RECT  22.403 119.184 24.008 121.416 ;
     RECT  23.677 122.448 24.008 124.296 ;
     RECT  23.893 125.328 24.008 146.664 ;
     RECT  23.245 147.84 24.008 150.312 ;
     RECT  23.857 151.536 24.008 155.928 ;
     RECT  24.001 157.152 24.008 159.144 ;
     RECT  22.853 160.416 24.008 162.024 ;
     RECT  23.281 163.392 24.008 163.944 ;
     RECT  23.929 165.024 24.008 165.72 ;
     RECT  23.033 167.088 24.008 172.152 ;
     RECT  23.269 173.136 24.008 173.832 ;
     RECT  23.461 175.44 24.008 178.536 ;
     RECT  23.749 179.616 24.008 186.408 ;
     RECT  23.965 187.776 24.008 197.256 ;
     RECT  23.893 198.624 24.008 206.952 ;
     RECT  23.533 207.936 24.008 209.16 ;
     RECT  23.749 210.144 24.008 212.568 ;
     RECT  23.033 213.84 24.008 216.552 ;
     RECT  23.821 218.256 24.008 232.92 ;
     RECT  23.857 233.904 24.008 237.672 ;
     RECT  22.925 238.752 24.008 238.872 ;
     RECT  22.997 240.24 24.008 242.904 ;
     RECT  23.965 244.272 24.008 251.4 ;
     RECT  24.001 252.48 24.008 259.32 ;
     RECT  23.569 260.4 24.008 264.84 ;
     RECT  23.893 266.304 24.008 270.168 ;
     RECT  23.221 271.392 24.008 273.384 ;
     RECT  23.245 274.368 24.008 279.288 ;
     RECT  23.701 280.32 24.008 282.696 ;
     RECT  23.749 283.776 24.008 295.272 ;
     RECT  23.605 297.552 24.008 298.248 ;
     RECT  24.008 1.728 24.304 298.248 ;
     RECT  24.325 300 24.361 300.024 ;
     RECT  24.304 70.704 24.365 94.296 ;
     RECT  24.304 130.896 24.365 139.128 ;
     RECT  24.304 184.56 24.365 208.632 ;
     RECT  24.361 300 24.412 300.12 ;
     RECT  24.304 1.728 24.419 20.568 ;
     RECT  24.304 44.784 24.419 45.48 ;
     RECT  24.304 46.608 24.419 53.592 ;
     RECT  24.304 68.64 24.419 69.336 ;
     RECT  24.365 74.304 24.419 94.296 ;
     RECT  24.304 151.824 24.419 171.528 ;
     RECT  24.304 229.968 24.419 242.808 ;
     RECT  24.419 74.304 24.437 91.656 ;
     RECT  24.304 112.752 24.437 129.48 ;
     RECT  24.304 217.728 24.437 228.792 ;
     RECT  24.412 300.096 24.445 300.12 ;
     RECT  24.304 32.544 24.467 36.504 ;
     RECT  24.365 70.704 24.467 73.32 ;
     RECT  24.304 274.512 24.467 295.848 ;
     RECT  24.304 30.048 24.473 31.512 ;
     RECT  24.419 68.64 24.473 69.096 ;
     RECT  24.304 175.872 24.473 179.736 ;
     RECT  24.304 180.72 24.473 183.192 ;
     RECT  24.365 185.28 24.473 208.632 ;
     RECT  24.437 217.728 24.473 227.784 ;
     RECT  24.467 274.512 24.473 279.048 ;
     RECT  24.467 280.32 24.481 295.848 ;
     RECT  24.304 57.024 24.509 67.224 ;
     RECT  24.437 116.016 24.509 129.48 ;
     RECT  24.473 180.72 24.509 181.32 ;
     RECT  24.473 274.992 24.509 279.048 ;
     RECT  24.419 151.824 24.515 161.928 ;
     RECT  24.419 163.008 24.515 171.528 ;
     RECT  24.304 248.64 24.515 253.896 ;
     RECT  24.304 271.776 24.515 273.384 ;
     RECT  24.419 44.784 24.545 44.904 ;
     RECT  24.473 68.64 24.545 69 ;
     RECT  24.304 172.608 24.563 174.552 ;
     RECT  24.304 40.368 24.581 43.32 ;
     RECT  24.545 44.88 24.581 44.904 ;
     RECT  24.509 116.016 24.581 129.096 ;
     RECT  24.365 130.896 24.581 136.824 ;
     RECT  24.304 140.208 24.581 145.176 ;
     RECT  24.437 228.768 24.581 228.792 ;
     RECT  24.304 254.976 24.581 256.344 ;
     RECT  24.515 271.776 24.581 273.336 ;
     RECT  24.509 274.992 24.581 279 ;
     RECT  24.304 297.552 24.581 298.248 ;
     RECT  24.304 257.424 24.604 262.056 ;
     RECT  24.437 81.072 24.617 91.656 ;
     RECT  24.515 253.248 24.617 253.512 ;
     RECT  24.581 132.72 24.659 136.824 ;
     RECT  24.473 203.616 24.659 208.632 ;
     RECT  24.304 24.48 24.689 27.864 ;
     RECT  24.304 266.112 24.707 270.552 ;
     RECT  24.304 21.696 24.725 22.872 ;
     RECT  24.467 32.544 24.725 36.024 ;
     RECT  24.545 68.64 24.725 68.952 ;
     RECT  24.659 132.72 24.725 136.44 ;
     RECT  24.481 280.32 24.725 280.344 ;
     RECT  24.481 281.52 24.725 295.848 ;
     RECT  24.581 116.016 24.755 124.008 ;
     RECT  24.689 24.48 24.761 25.032 ;
     RECT  24.581 40.368 24.761 42.744 ;
     RECT  24.725 32.688 24.797 36.024 ;
     RECT  24.755 116.016 24.797 121.464 ;
     RECT  24.659 203.616 24.797 205.224 ;
     RECT  24.797 116.016 24.803 121.368 ;
     RECT  24.473 185.28 24.803 202.584 ;
     RECT  24.304 95.664 24.833 111.096 ;
     RECT  24.581 142.608 24.833 145.176 ;
     RECT  24.473 217.728 24.833 227.256 ;
     RECT  24.833 95.664 24.851 107.784 ;
     RECT  24.761 24.48 24.905 24.888 ;
     RECT  24.509 57.024 24.905 65.544 ;
     RECT  24.803 117.504 24.905 121.368 ;
     RECT  24.797 32.688 24.941 35.016 ;
     RECT  24.797 36 24.941 36.024 ;
     RECT  24.515 248.64 24.941 251.976 ;
     RECT  24.473 30.048 24.947 31.32 ;
     RECT  24.617 253.488 24.947 253.512 ;
     RECT  24.941 32.688 24.977 34.44 ;
     RECT  24.581 271.92 24.995 273.336 ;
     RECT  24.995 272.016 25.013 273.336 ;
     RECT  24.755 122.544 25.049 124.008 ;
     RECT  24.581 140.208 25.049 141.576 ;
     RECT  24.803 185.28 25.049 198.504 ;
     RECT  24.833 223.92 25.049 227.256 ;
     RECT  24.725 285.744 25.049 295.848 ;
     RECT  24.905 24.528 25.085 24.888 ;
     RECT  24.419 230.256 25.085 242.808 ;
     RECT  24.419 1.728 25.091 18.792 ;
     RECT  23.537 0.288 25.093 0.312 ;
     RECT  24.617 81.216 25.121 91.656 ;
     RECT  24.581 130.896 25.121 131.64 ;
     RECT  24.563 173.808 25.121 174.552 ;
     RECT  24.707 266.112 25.121 270.168 ;
     RECT  24.725 21.696 25.157 22.776 ;
     RECT  25.049 286.272 25.187 295.848 ;
     RECT  24.437 112.752 25.193 114.84 ;
     RECT  24.473 182.4 25.193 183.192 ;
     RECT  24.304 263.28 25.193 264.456 ;
     RECT  24.365 137.856 25.265 139.128 ;
     RECT  24.515 151.824 25.265 161.352 ;
     RECT  24.473 177.984 25.265 179.736 ;
     RECT  24.473 175.872 25.285 176.952 ;
     RECT  24.304 244.416 25.285 245.112 ;
     RECT  24.604 257.568 25.285 262.056 ;
     RECT  25.193 263.28 25.285 263.928 ;
     RECT  24.509 66.624 25.297 67.224 ;
     RECT  24.725 68.64 25.297 68.664 ;
     RECT  24.304 147.84 25.297 150.312 ;
     RECT  24.905 57.12 25.331 65.544 ;
     RECT  25.285 244.08 25.331 245.112 ;
     RECT  24.419 19.92 25.333 20.568 ;
     RECT  24.304 37.584 25.333 38.904 ;
     RECT  24.761 40.368 25.333 41.112 ;
     RECT  24.467 70.704 25.333 72.936 ;
     RECT  25.193 112.752 25.333 114.6 ;
     RECT  24.304 146.448 25.333 146.52 ;
     RECT  24.689 26.208 25.337 27.864 ;
     RECT  25.085 230.256 25.337 231.096 ;
     RECT  24.941 248.64 25.337 248.76 ;
     RECT  24.941 249.888 25.337 251.976 ;
     RECT  25.333 37.584 25.369 41.112 ;
     RECT  25.085 232.08 25.369 242.808 ;
     RECT  25.331 244.08 25.369 244.776 ;
     RECT  25.157 22.608 25.379 22.776 ;
     RECT  25.369 232.08 25.379 244.776 ;
     RECT  24.515 163.392 25.381 171.528 ;
     RECT  24.437 74.304 25.392 79.992 ;
     RECT  25.093 0.192 25.405 0.312 ;
     RECT  24.419 46.656 25.405 46.68 ;
     RECT  25.333 70.08 25.427 72.936 ;
     RECT  24.803 116.016 25.427 116.52 ;
     RECT  25.34 183.888 25.427 183.912 ;
     RECT  25.265 138.096 25.429 139.128 ;
     RECT  25.049 140.208 25.429 140.328 ;
     RECT  24.833 108.912 25.436 111.096 ;
     RECT  25.121 266.112 25.436 269.016 ;
     RECT  25.091 18.768 25.441 18.792 ;
     RECT  25.333 19.92 25.441 21.432 ;
     RECT  25.436 108.912 25.441 111.288 ;
     RECT  25.121 130.896 25.445 131.208 ;
     RECT  25.091 1.728 25.475 17.688 ;
     RECT  25.187 286.272 25.475 295.752 ;
     RECT  25.121 82.128 25.477 91.656 ;
     RECT  24.419 92.688 25.477 94.296 ;
     RECT  25.121 174 25.477 174.552 ;
     RECT  25.285 175.68 25.477 176.952 ;
     RECT  24.509 180.816 25.477 181.32 ;
     RECT  24.803 199.536 25.477 202.584 ;
     RECT  24.419 47.952 25.484 53.592 ;
     RECT  25.369 37.104 25.513 41.112 ;
     RECT  25.333 146.4 25.513 146.52 ;
     RECT  25.429 138.096 25.516 140.328 ;
     RECT  24.797 204.048 25.517 205.224 ;
     RECT  25.381 163.392 25.523 171.576 ;
     RECT  25.436 265.92 25.523 269.016 ;
     RECT  25.297 147.84 25.525 150.744 ;
     RECT  24.304 247.296 25.532 247.32 ;
     RECT  25.477 180.768 25.549 181.32 ;
     RECT  25.333 112.56 25.553 114.6 ;
     RECT  24.304 213.792 25.553 216.504 ;
     RECT  25.484 47.856 25.571 53.592 ;
     RECT  25.331 57.12 25.571 64.632 ;
     RECT  25.441 108.912 25.571 111.432 ;
     RECT  25.553 112.56 25.571 113.544 ;
     RECT  25.532 247.2 25.585 247.32 ;
     RECT  24.581 274.992 25.585 278.184 ;
     RECT  25.475 3.888 25.589 17.688 ;
     RECT  25.427 116.4 25.589 116.52 ;
     RECT  24.725 132.72 25.589 134.856 ;
     RECT  25.516 140.208 25.589 140.328 ;
     RECT  24.581 297.552 25.597 298.104 ;
     RECT  25.513 37.008 25.619 41.112 ;
     RECT  25.405 0.192 25.621 0.36 ;
     RECT  25.477 82.128 25.621 94.296 ;
     RECT  24.659 206.208 25.621 208.632 ;
     RECT  24.304 209.712 25.621 212.136 ;
     RECT  25.013 272.4 25.621 273.336 ;
     RECT  25.589 3.888 25.625 17.304 ;
     RECT  25.392 74.88 25.632 79.992 ;
     RECT  25.525 147.6 25.657 150.744 ;
     RECT  25.265 151.824 25.657 158.712 ;
     RECT  25.585 274.992 25.657 278.616 ;
     RECT  25.379 232.08 25.661 234.024 ;
     RECT  25.049 187.488 25.667 198.504 ;
     RECT  25.445 130.896 25.669 130.92 ;
     RECT  25.649 300.096 25.676 300.12 ;
     RECT  24.304 54.72 25.693 55.752 ;
     RECT  25.549 180.768 25.693 181.368 ;
     RECT  25.193 182.4 25.693 182.712 ;
     RECT  25.693 54.672 25.697 55.752 ;
     RECT  25.589 133.584 25.697 134.856 ;
     RECT  24.725 135.84 25.697 136.44 ;
     RECT  25.265 177.984 25.697 179.688 ;
     RECT  25.667 187.488 25.715 198.408 ;
     RECT  25.621 0.192 25.717 0.408 ;
     RECT  25.337 26.208 25.717 27.288 ;
     RECT  25.405 245.76 25.717 245.784 ;
     RECT  25.585 247.2 25.717 247.368 ;
     RECT  25.121 270.048 25.717 270.168 ;
     RECT  25.621 82.128 25.729 94.584 ;
     RECT  24.851 95.664 25.733 107.64 ;
     RECT  25.625 3.888 25.756 17.16 ;
     RECT  25.717 26.112 25.763 27.288 ;
     RECT  25.717 245.76 25.763 247.368 ;
     RECT  25.523 266.112 25.763 269.016 ;
     RECT  24.905 117.504 25.765 117.672 ;
     RECT  24.905 118.656 25.765 121.368 ;
     RECT  24.581 125.088 25.765 129.096 ;
     RECT  25.669 130.512 25.765 130.92 ;
     RECT  25.621 206.208 25.765 212.136 ;
     RECT  25.049 226.272 25.765 227.256 ;
     RECT  25.621 272.4 25.765 273.576 ;
     RECT  25.657 274.992 25.765 279 ;
     RECT  25.285 257.568 25.769 263.928 ;
     RECT  24.725 281.52 25.769 284.28 ;
     RECT  25.717 270.048 25.804 270.36 ;
     RECT  25.379 235.296 25.805 244.776 ;
     RECT  25.724 229.008 25.811 229.032 ;
     RECT  25.379 22.704 25.813 22.776 ;
     RECT  25.085 24.864 25.813 24.888 ;
     RECT  25.632 79.2 25.813 79.992 ;
     RECT  25.669 81.024 25.813 81.048 ;
     RECT  24.563 172.608 25.813 172.632 ;
     RECT  25.553 213.792 25.82 216.216 ;
     RECT  25.297 66.624 25.837 68.664 ;
     RECT  25.523 163.392 25.841 169.896 ;
     RECT  25.813 79.2 25.859 81.048 ;
     RECT  25.265 160.032 25.859 161.352 ;
     RECT  25.717 248.496 25.859 248.616 ;
     RECT  25.477 199.536 25.861 202.824 ;
     RECT  24.761 42.24 25.868 42.744 ;
     RECT  24.833 217.728 25.868 222.888 ;
     RECT  24.581 255.936 25.873 256.344 ;
     RECT  25.769 257.568 25.873 261.144 ;
     RECT  25.717 28.416 25.877 29.208 ;
     RECT  25.427 72.48 25.877 72.936 ;
     RECT  25.632 74.88 25.877 77.928 ;
     RECT  25.868 217.68 25.877 222.888 ;
     RECT  25.765 206.16 25.907 212.424 ;
     RECT  25.82 213.6 25.907 216.216 ;
     RECT  25.877 217.68 25.907 222.792 ;
     RECT  25.717 44.736 25.909 44.76 ;
     RECT  25.405 46.128 25.909 46.68 ;
     RECT  25.765 117.12 25.909 117.672 ;
     RECT  25.765 118.656 25.909 121.464 ;
     RECT  25.813 172.56 25.909 172.632 ;
     RECT  25.813 22.704 25.913 23.352 ;
     RECT  25.657 147.6 25.913 158.712 ;
     RECT  25.868 42.24 25.916 43.272 ;
     RECT  25.909 44.304 25.916 44.76 ;
     RECT  25.877 72.768 25.945 72.936 ;
     RECT  25.733 104.784 25.945 107.64 ;
     RECT  25.861 199.488 25.945 202.824 ;
     RECT  25.769 281.52 25.945 283.224 ;
     RECT  25.841 164.736 25.949 169.896 ;
     RECT  25.873 255.936 25.949 261.144 ;
     RECT  25.475 286.272 25.949 290.712 ;
     RECT  25.441 18.768 25.955 21.432 ;
     RECT  25.859 79.2 25.955 80.952 ;
     RECT  25.909 117.12 25.955 121.464 ;
     RECT  25.907 217.68 25.955 217.704 ;
     RECT  25.049 141.408 25.957 141.576 ;
     RECT  24.833 142.608 25.957 144.696 ;
     RECT  25.513 146.4 25.957 146.568 ;
     RECT  25.571 112.56 25.973 113.064 ;
     RECT  25.571 57.12 25.981 60.888 ;
     RECT  25.804 270.336 25.981 270.36 ;
     RECT  25.717 0.192 25.985 0.6 ;
     RECT  25.805 235.92 25.985 244.776 ;
     RECT  25.916 42.24 26.003 44.76 ;
     RECT  25.733 95.664 26.003 103.704 ;
     RECT  25.957 141.408 26.003 144.696 ;
     RECT  25.949 164.736 26.003 166.872 ;
     RECT  25.765 272.4 26.005 279 ;
     RECT  25.909 46.128 26.012 46.728 ;
     RECT  25.841 163.392 26.012 163.56 ;
     RECT  25.985 0.192 26.017 0.552 ;
     RECT  24.947 30.288 26.017 31.32 ;
     RECT  25.981 57.024 26.017 60.888 ;
     RECT  25.049 122.544 26.017 123.864 ;
     RECT  25.765 125.088 26.017 130.92 ;
     RECT  25.697 133.68 26.017 134.856 ;
     RECT  25.049 185.28 26.017 186.408 ;
     RECT  26.003 44.304 26.021 44.76 ;
     RECT  25.913 147.6 26.021 156.168 ;
     RECT  25.877 29.184 26.025 29.208 ;
     RECT  26.017 30.288 26.025 31.368 ;
     RECT  26.003 166.272 26.051 166.872 ;
     RECT  25.661 232.368 26.051 234.024 ;
     RECT  25.985 240.576 26.051 244.776 ;
     RECT  25.859 160.224 26.053 161.352 ;
     RECT  25.949 286.272 26.053 286.632 ;
     RECT  25.756 3.888 26.057 13.608 ;
     RECT  26.003 42.24 26.057 42.744 ;
     RECT  25.729 82.128 26.057 94.68 ;
     RECT  25.973 112.32 26.057 113.064 ;
     RECT  26.025 29.184 26.089 31.368 ;
     RECT  24.977 32.688 26.089 34.248 ;
     RECT  26.005 272.4 26.089 279.288 ;
     RECT  25.769 284.256 26.089 284.28 ;
     RECT  25.955 117.552 26.093 121.464 ;
     RECT  25.945 199.488 26.093 202.92 ;
     RECT  25.907 218.832 26.093 222.792 ;
     RECT  25.619 37.008 26.099 41.064 ;
     RECT  26.012 45.936 26.099 46.728 ;
     RECT  26.057 82.128 26.099 89.976 ;
     RECT  26.017 122.544 26.099 130.92 ;
     RECT  25.516 138.096 26.099 138.84 ;
     RECT  26.012 162.816 26.099 163.56 ;
     RECT  26.017 184.656 26.099 186.408 ;
     RECT  25.715 188.496 26.099 198.408 ;
     RECT  25.981 270.336 26.101 271.32 ;
     RECT  26.089 272.4 26.101 279.816 ;
     RECT  26.089 284.256 26.101 284.424 ;
     RECT  25.955 18.768 26.108 20.568 ;
     RECT  25.571 49.968 26.125 53.592 ;
     RECT  25.697 54.672 26.125 54.696 ;
     RECT  26.017 56.928 26.125 60.888 ;
     RECT  25.837 66.624 26.125 69 ;
     RECT  25.909 172.56 26.125 172.776 ;
     RECT  25.477 174 26.125 176.952 ;
     RECT  26.099 186.336 26.125 186.408 ;
     RECT  25.715 187.488 26.125 187.512 ;
     RECT  25.945 281.04 26.125 283.224 ;
     RECT  26.089 29.184 26.129 34.248 ;
     RECT  26.099 37.008 26.129 39.384 ;
     RECT  26.021 44.304 26.129 44.664 ;
     RECT  26.057 113.04 26.129 113.064 ;
     RECT  26.099 138.096 26.129 138.456 ;
     RECT  26.003 164.736 26.129 164.904 ;
     RECT  25.949 167.904 26.129 169.896 ;
     RECT  26.125 172.56 26.129 176.952 ;
     RECT  26.093 219.36 26.129 222.792 ;
     RECT  25.049 223.92 26.129 225 ;
     RECT  25.765 226.272 26.129 227.976 ;
     RECT  25.475 291.696 26.129 295.752 ;
     RECT  26.125 186.336 26.14 187.512 ;
     RECT  26.051 232.368 26.147 233.928 ;
     RECT  26.051 240.576 26.147 243.384 ;
     RECT  26.099 40.656 26.165 41.064 ;
     RECT  26.057 91.2 26.165 94.68 ;
     RECT  26.003 95.664 26.165 99.528 ;
     RECT  25.571 108.912 26.165 111.096 ;
     RECT  25.907 213.936 26.165 216.216 ;
     RECT  26.108 18.576 26.195 20.568 ;
     RECT  25.913 22.704 26.195 22.728 ;
     RECT  26.125 49.968 26.195 54.696 ;
     RECT  26.099 82.128 26.195 89.064 ;
     RECT  26.003 100.56 26.195 103.704 ;
     RECT  25.945 104.784 26.195 107.688 ;
     RECT  26.021 147.6 26.195 155.016 ;
     RECT  25.913 157.248 26.195 158.712 ;
     RECT  26.129 172.56 26.195 174.552 ;
     RECT  25.693 180.768 26.197 182.712 ;
     RECT  25.756 14.832 26.201 17.16 ;
     RECT  26.165 92.208 26.201 94.68 ;
     RECT  25.949 259.536 26.201 261.144 ;
     RECT  26.101 270.336 26.201 279.816 ;
     RECT  26.125 55.92 26.209 60.888 ;
     RECT  26.057 3.888 26.229 12.792 ;
     RECT  26.165 108.912 26.233 110.232 ;
     RECT  26.129 138.096 26.233 138.408 ;
     RECT  26.017 133.68 26.236 135.432 ;
     RECT  26.201 15.024 26.237 17.16 ;
     RECT  26.129 37.008 26.243 39.336 ;
     RECT  26.165 95.664 26.243 99.48 ;
     RECT  26.099 193.248 26.243 198.408 ;
     RECT  26.053 286.08 26.269 286.632 ;
     RECT  26.003 141.408 26.273 143.976 ;
     RECT  25.765 253.056 26.273 253.08 ;
     RECT  25.769 262.176 26.273 263.928 ;
     RECT  26.243 37.056 26.284 39.336 ;
     RECT  25.517 204.048 26.293 204.552 ;
     RECT  26.057 42.24 26.309 42.696 ;
     RECT  26.093 117.6 26.309 121.464 ;
     RECT  25.589 140.304 26.309 140.328 ;
     RECT  26.129 175.872 26.309 176.952 ;
     RECT  26.237 15.024 26.339 15.768 ;
     RECT  26.129 164.736 26.339 164.76 ;
     RECT  26.195 172.656 26.339 174.552 ;
     RECT  25.697 178.128 26.341 179.688 ;
     RECT  26.197 180.72 26.341 182.712 ;
     RECT  26.229 3.888 26.345 10.392 ;
     RECT  26.195 18.816 26.345 20.088 ;
     RECT  26.129 44.304 26.345 44.472 ;
     RECT  26.053 160.224 26.345 161.832 ;
     RECT  25.763 266.112 26.345 268.44 ;
     RECT  26.293 203.376 26.38 204.552 ;
     RECT  26.147 240.72 26.38 243.384 ;
     RECT  26.345 3.888 26.387 10.248 ;
     RECT  26.309 176.544 26.387 176.952 ;
     RECT  26.14 186.816 26.387 187.512 ;
     RECT  26.195 104.832 26.389 107.688 ;
     RECT  26.233 108.672 26.389 110.232 ;
     RECT  26.101 284.256 26.413 285.048 ;
     RECT  26.269 286.032 26.413 286.632 ;
     RECT  26.195 83.616 26.417 89.064 ;
     RECT  26.195 147.6 26.417 154.536 ;
     RECT  25.907 206.16 26.417 209.256 ;
     RECT  25.945 72.768 26.437 72.984 ;
     RECT  26.017 0.048 26.453 0.552 ;
     RECT  26.209 56.784 26.453 60.888 ;
     RECT  26.273 143.952 26.453 143.976 ;
     RECT  26.195 157.296 26.453 158.712 ;
     RECT  26.129 219.6 26.453 222.792 ;
     RECT  26.147 233.664 26.453 233.928 ;
     RECT  25.676 300 26.461 300.12 ;
     RECT  26.417 207.6 26.483 209.256 ;
     RECT  25.813 24.864 26.485 24.984 ;
     RECT  25.763 26.112 26.485 26.76 ;
     RECT  26.417 206.16 26.485 206.616 ;
     RECT  26.389 104.832 26.489 110.232 ;
     RECT  26.099 122.544 26.489 125.688 ;
     RECT  26.453 219.6 26.489 222.408 ;
     RECT  25.957 145.872 26.521 146.568 ;
     RECT  26.417 147.6 26.521 152.376 ;
     RECT  26.345 18.816 26.525 19.656 ;
     RECT  25.427 70.752 26.525 70.872 ;
     RECT  26.099 126.672 26.525 130.92 ;
     RECT  26.417 153.408 26.525 154.536 ;
     RECT  26.38 240.72 26.525 242.856 ;
     RECT  26.453 0.048 26.531 0.408 ;
     RECT  26.229 11.376 26.531 12.792 ;
     RECT  26.339 15.264 26.531 15.768 ;
     RECT  26.201 270.336 26.531 279 ;
     RECT  26.051 244.464 26.533 244.776 ;
     RECT  25.763 245.76 26.533 246.504 ;
     RECT  26.125 66.48 26.54 69 ;
     RECT  25.475 1.728 26.557 2.856 ;
     RECT  26.387 3.888 26.557 9 ;
     RECT  26.099 46.032 26.557 46.728 ;
     RECT  26.54 66.48 26.557 69.48 ;
     RECT  26.341 178.128 26.557 182.712 ;
     RECT  26.129 224.304 26.557 225 ;
     RECT  26.129 226.272 26.557 227.928 ;
     RECT  25.955 79.2 26.561 79.992 ;
     RECT  26.273 141.408 26.561 142.728 ;
     RECT  26.531 11.376 26.579 12.648 ;
     RECT  26.531 270.336 26.579 271.944 ;
     RECT  25.877 74.928 26.593 77.928 ;
     RECT  26.561 79.2 26.593 79.224 ;
     RECT  26.557 66.48 26.597 69.624 ;
     RECT  26.129 292.56 26.621 295.752 ;
     RECT  26.237 17.04 26.627 17.16 ;
     RECT  26.597 69.456 26.627 69.624 ;
     RECT  26.525 129.936 26.629 130.92 ;
     RECT  26.053 132.24 26.629 132.264 ;
     RECT  26.485 24.864 26.633 26.76 ;
     RECT  26.521 145.872 26.633 152.376 ;
     RECT  25.697 136.416 26.665 136.44 ;
     RECT  26.633 24.864 26.669 26.328 ;
     RECT  26.201 259.536 26.669 260.904 ;
     RECT  26.531 0.048 26.675 0.312 ;
     RECT  26.525 19.056 26.675 19.656 ;
     RECT  26.165 215.328 26.701 216.216 ;
     RECT  26.579 12.624 26.705 12.648 ;
     RECT  26.453 157.296 26.705 157.512 ;
     RECT  26.531 273.168 26.705 279 ;
     RECT  26.621 292.56 26.705 295.896 ;
     RECT  26.093 199.488 26.723 202.296 ;
     RECT  25.949 287.76 26.737 290.712 ;
     RECT  26.387 10.176 26.741 10.248 ;
     RECT  26.531 15.744 26.741 15.768 ;
     RECT  26.627 17.136 26.741 17.16 ;
     RECT  26.417 87.312 26.741 89.064 ;
     RECT  26.309 118.368 26.741 121.464 ;
     RECT  26.489 222.384 26.741 222.408 ;
     RECT  26.533 244.464 26.741 246.504 ;
     RECT  26.557 224.304 26.771 227.928 ;
     RECT  26.453 58.512 26.773 60.888 ;
     RECT  25.571 62.256 26.773 64.632 ;
     RECT  26.201 92.4 26.773 94.68 ;
     RECT  26.243 95.664 26.773 99.432 ;
     RECT  26.485 205.872 26.773 206.616 ;
     RECT  26.579 11.376 26.777 11.496 ;
     RECT  26.773 92.4 26.777 99.432 ;
     RECT  26.561 141.888 26.777 142.728 ;
     RECT  25.985 235.92 26.777 239.352 ;
     RECT  26.273 262.848 26.777 263.928 ;
     RECT  26.489 104.832 26.785 107.688 ;
     RECT  26.701 215.328 26.785 216.984 ;
     RECT  26.236 133.68 26.801 135.336 ;
     RECT  26.627 69.552 26.813 69.624 ;
     RECT  26.557 178.128 26.813 183.624 ;
     RECT  26.243 193.248 26.813 198.12 ;
     RECT  26.771 227.232 26.813 227.256 ;
     RECT  26.777 263.28 26.813 263.928 ;
     RECT  26.705 277.008 26.813 279 ;
     RECT  26.737 287.76 26.813 291.384 ;
     RECT  26.785 105.12 26.819 107.688 ;
     RECT  25.523 171.456 26.821 171.576 ;
     RECT  26.557 46.032 26.845 46.776 ;
     RECT  25.571 47.952 26.845 48.936 ;
     RECT  26.099 163.008 26.845 163.56 ;
     RECT  25.337 230.688 26.845 231.096 ;
     RECT  26.147 232.368 26.845 232.536 ;
     RECT  26.705 157.296 26.849 157.416 ;
     RECT  26.099 188.496 26.849 192.216 ;
     RECT  26.579 271.296 26.849 271.944 ;
     RECT  26.557 1.728 26.867 9 ;
     RECT  26.723 199.488 26.869 199.608 ;
     RECT  25.859 248.496 26.869 248.52 ;
     RECT  26.483 208.752 26.881 209.256 ;
     RECT  26.845 46.032 26.885 48.936 ;
     RECT  26.705 273.168 26.885 275.784 ;
     RECT  26.195 100.56 26.915 103.656 ;
     RECT  26.387 176.64 26.917 176.952 ;
     RECT  26.813 178.128 26.917 179.688 ;
     RECT  25.907 210.432 26.917 212.424 ;
     RECT  26.165 213.936 26.917 214.296 ;
     RECT  25.337 249.888 26.917 251.016 ;
     RECT  26.581 21.648 26.921 21.672 ;
     RECT  26.437 72.768 26.921 73.416 ;
     RECT  26.801 133.632 26.921 135.336 ;
     RECT  26.339 172.752 26.921 174.552 ;
     RECT  26.813 69.6 26.953 69.624 ;
     RECT  26.845 70.608 26.953 70.632 ;
     RECT  26.741 118.56 26.953 121.464 ;
     RECT  26.489 122.544 26.953 125.112 ;
     RECT  26.633 145.872 26.953 149.496 ;
     RECT  26.813 180.672 26.953 183.624 ;
     RECT  26.099 184.656 26.953 185.304 ;
     RECT  26.777 235.92 26.953 237 ;
     RECT  26.597 66.48 26.957 68.424 ;
     RECT  26.387 186.912 26.957 187.512 ;
     RECT  26.885 273.168 26.957 275.592 ;
     RECT  26.813 277.008 26.957 277.08 ;
     RECT  26.921 173.136 26.963 174.552 ;
     RECT  26.869 247.92 26.965 248.52 ;
     RECT  26.917 249.888 26.965 251.352 ;
     RECT  25.949 255.936 26.972 258.168 ;
     RECT  26.953 145.296 26.989 149.496 ;
     RECT  26.965 247.92 26.989 251.352 ;
     RECT  26.917 264.912 26.989 264.936 ;
     RECT  26.195 49.968 26.993 54.36 ;
     RECT  26.953 69.6 26.993 70.632 ;
     RECT  26.165 91.2 26.993 91.224 ;
     RECT  26.633 150.48 26.993 152.376 ;
     RECT  26.917 210.288 26.993 212.568 ;
     RECT  26.989 247.776 26.993 251.352 ;
     RECT  26.813 278.4 26.993 279 ;
     RECT  26.993 250.176 27.004 251.352 ;
     RECT  26.665 252.912 27.013 252.936 ;
     RECT  26.125 280.992 27.02 283.224 ;
     RECT  26.413 284.256 27.02 286.632 ;
     RECT  26.741 87.312 27.029 87.336 ;
     RECT  26.917 213.6 27.029 214.296 ;
     RECT  26.705 292.56 27.029 295.848 ;
     RECT  26.953 118.56 27.037 125.112 ;
     RECT  27.004 250.32 27.052 251.352 ;
     RECT  26.741 88.752 27.059 89.064 ;
     RECT  27.037 118.56 27.065 121.128 ;
     RECT  26.885 46.032 27.097 48.696 ;
     RECT  26.957 187.296 27.097 187.512 ;
     RECT  26.849 188.496 27.097 190.68 ;
     RECT  26.957 66.48 27.101 66.696 ;
     RECT  26.849 191.952 27.101 192.216 ;
     RECT  26.785 215.328 27.101 216.216 ;
     RECT  26.957 273.168 27.101 275.304 ;
     RECT  27.029 292.56 27.101 295.752 ;
     RECT  26.021 156.144 27.133 156.168 ;
     RECT  26.525 153.408 27.137 154.488 ;
     RECT  26.917 176.64 27.137 179.688 ;
     RECT  26.917 299.28 27.155 299.352 ;
     RECT  25.597 297.552 27.157 298.056 ;
     RECT  26.771 224.304 27.164 225.432 ;
     RECT  26.777 11.472 27.173 11.496 ;
     RECT  27.137 176.64 27.173 179.496 ;
     RECT  26.309 42.336 27.205 42.696 ;
     RECT  26.051 166.368 27.205 166.872 ;
     RECT  26.129 167.904 27.205 169.224 ;
     RECT  26.813 197.76 27.205 198.12 ;
     RECT  26.869 199.152 27.205 199.608 ;
     RECT  26.993 278.976 27.205 279 ;
     RECT  27.101 292.56 27.205 295.704 ;
     RECT  26.723 200.832 27.209 202.296 ;
     RECT  26.777 238.272 27.233 239.352 ;
     RECT  27.133 156.096 27.241 156.168 ;
     RECT  26.417 83.616 27.245 86.232 ;
     RECT  26.777 92.4 27.253 97.992 ;
     RECT  27.029 213.696 27.253 214.296 ;
     RECT  27.101 215.328 27.253 216.168 ;
     RECT  26.972 255.696 27.253 258.168 ;
     RECT  26.669 260.88 27.253 260.904 ;
     RECT  27.205 42.336 27.277 42.888 ;
     RECT  26.989 144.72 27.281 149.496 ;
     RECT  26.953 180.672 27.299 185.304 ;
     RECT  27.253 255.6 27.299 258.36 ;
     RECT  25.553 114.576 27.301 114.6 ;
     RECT  27.277 117.408 27.301 117.432 ;
     RECT  27.205 166.368 27.301 169.224 ;
     RECT  27.025 218.112 27.301 218.136 ;
     RECT  26.741 246.24 27.301 246.504 ;
     RECT  26.993 247.776 27.301 249.048 ;
     RECT  26.777 98.976 27.308 99.432 ;
     RECT  26.845 230.304 27.308 232.536 ;
     RECT  26.453 233.664 27.308 233.688 ;
     RECT  27.308 230.304 27.311 233.688 ;
     RECT  26.665 136.416 27.313 136.488 ;
     RECT  26.233 137.472 27.313 138.408 ;
     RECT  26.845 163.008 27.313 164.088 ;
     RECT  27.205 165.264 27.313 165.288 ;
     RECT  27.301 166.368 27.313 169.56 ;
     RECT  27.299 181.824 27.313 185.304 ;
     RECT  26.881 208.752 27.313 209.304 ;
     RECT  26.993 210.288 27.313 211.512 ;
     RECT  27.253 260.88 27.313 261.288 ;
     RECT  27.157 297.552 27.313 298.152 ;
     RECT  27.233 238.272 27.317 239.4 ;
     RECT  27.313 166.368 27.347 169.896 ;
     RECT  26.345 44.352 27.349 44.472 ;
     RECT  26.453 158.544 27.349 158.712 ;
     RECT  26.345 160.224 27.349 161.64 ;
     RECT  26.813 193.248 27.349 196.728 ;
     RECT  27.209 202.272 27.349 202.296 ;
     RECT  26.38 203.856 27.349 204.552 ;
     RECT  26.813 287.856 27.349 291.384 ;
     RECT  27.205 292.416 27.349 295.704 ;
     RECT  26.453 56.784 27.353 57.48 ;
     RECT  27.109 270.192 27.353 270.216 ;
     RECT  27.301 116.64 27.388 117.432 ;
     RECT  27.313 163.008 27.388 165.288 ;
     RECT  27.02 280.992 27.388 286.632 ;
     RECT  26.129 29.376 27.389 33.912 ;
     RECT  26.993 70.032 27.389 70.632 ;
     RECT  27.301 113.952 27.389 115.128 ;
     RECT  26.821 170.976 27.389 171.576 ;
     RECT  27.205 197.76 27.389 199.608 ;
     RECT  27.311 230.064 27.389 233.688 ;
     RECT  26.675 0.096 27.395 0.312 ;
     RECT  27.277 42.192 27.395 42.888 ;
     RECT  27.349 158.544 27.395 159.096 ;
     RECT  27.313 181.824 27.395 185.832 ;
     RECT  27.389 230.064 27.395 232.824 ;
     RECT  27.349 287.856 27.395 295.704 ;
     RECT  27.313 260.88 27.397 261.624 ;
     RECT  26.629 129.936 27.404 132.264 ;
     RECT  27.097 112.272 27.408 112.296 ;
     RECT  27.349 202.272 27.413 204.648 ;
     RECT  26.773 205.728 27.413 206.616 ;
     RECT  26.669 24.864 27.421 26.28 ;
     RECT  26.525 240.72 27.421 242.808 ;
     RECT  26.345 266.88 27.421 268.44 ;
     RECT  26.525 126.672 27.425 128.856 ;
     RECT  27.395 181.92 27.425 185.832 ;
     RECT  27.395 230.064 27.425 230.712 ;
     RECT  27.317 239.328 27.425 239.352 ;
     RECT  27.299 255.6 27.425 255.624 ;
     RECT  27.205 278.976 27.425 279.288 ;
     RECT  27.395 292.992 27.425 295.704 ;
     RECT  27.413 202.272 27.436 206.616 ;
     RECT  27.349 192.816 27.443 196.728 ;
     RECT  26.993 49.968 27.445 53.4 ;
     RECT  26.867 4.656 27.457 9 ;
     RECT  26.165 40.656 27.457 40.824 ;
     RECT  27.097 187.296 27.461 190.68 ;
     RECT  27.164 223.968 27.461 225.432 ;
     RECT  27.013 252.48 27.461 252.936 ;
     RECT  27.425 292.992 27.461 294.84 ;
     RECT  26.921 72.96 27.491 73.416 ;
     RECT  27.308 98.976 27.491 100.296 ;
     RECT  27.404 129.936 27.491 132.552 ;
     RECT  27.101 66.48 27.493 66.648 ;
     RECT  26.195 82.128 27.493 82.344 ;
     RECT  26.489 108.672 27.493 110.232 ;
     RECT  27.173 176.64 27.493 176.952 ;
     RECT  27.097 45.744 27.497 48.696 ;
     RECT  26.593 74.928 27.497 79.224 ;
     RECT  26.819 105.12 27.497 107.64 ;
     RECT  27.395 159.072 27.497 159.096 ;
     RECT  27.443 194.352 27.497 196.728 ;
     RECT  27.436 203.856 27.497 206.616 ;
     RECT  27.299 256.704 27.497 258.36 ;
     RECT  27.421 240.528 27.505 242.808 ;
     RECT  27.349 160.224 27.529 162.024 ;
     RECT  27.497 46.176 27.533 48.696 ;
     RECT  27.493 65.712 27.533 66.648 ;
     RECT  27.491 129.936 27.533 131.976 ;
     RECT  27.173 178.272 27.533 179.496 ;
     RECT  27.395 232.368 27.533 232.536 ;
     RECT  27.065 118.56 27.539 120.792 ;
     RECT  27.347 168.048 27.539 169.896 ;
     RECT  27.452 171.936 27.539 172.152 ;
     RECT  27.313 208.752 27.539 211.512 ;
     RECT  27.461 252.528 27.539 252.936 ;
     RECT  27.397 260.88 27.539 262.2 ;
     RECT  27.395 287.856 27.539 291.96 ;
     RECT  26.741 244.464 27.541 244.824 ;
     RECT  27.493 82.128 27.565 82.632 ;
     RECT  27.245 83.76 27.565 86.232 ;
     RECT  26.489 219.6 27.565 221.352 ;
     RECT  27.457 23.184 27.569 23.208 ;
     RECT  26.773 58.512 27.569 64.632 ;
     RECT  26.963 173.184 27.587 174.552 ;
     RECT  27.505 240.72 27.587 242.808 ;
     RECT  27.457 40.368 27.596 40.824 ;
     RECT  27.347 166.368 27.596 166.728 ;
     RECT  27.349 44.256 27.601 44.472 ;
     RECT  27.037 122.544 27.601 125.112 ;
     RECT  26.483 207.6 27.601 207.624 ;
     RECT  27.395 42.192 27.605 42.744 ;
     RECT  27.533 65.712 27.605 65.736 ;
     RECT  27.565 81.84 27.605 82.632 ;
     RECT  27.059 88.752 27.605 89.016 ;
     RECT  27.497 194.352 27.605 195.384 ;
     RECT  26.953 235.536 27.605 237 ;
     RECT  27.541 243.84 27.628 244.824 ;
     RECT  26.675 19.632 27.635 19.656 ;
     RECT  27.389 29.808 27.635 33.912 ;
     RECT  27.539 168.048 27.635 168.744 ;
     RECT  26.957 277.008 27.635 277.032 ;
     RECT  26.284 38.4 27.637 39.336 ;
     RECT  27.596 40.368 27.637 41.064 ;
     RECT  27.601 44.208 27.637 44.472 ;
     RECT  27.569 58.56 27.637 64.632 ;
     RECT  27.493 176.544 27.637 176.952 ;
     RECT  27.445 49.728 27.641 53.4 ;
     RECT  27.353 56.784 27.641 57.432 ;
     RECT  27.497 196.56 27.641 196.728 ;
     RECT  27.539 208.752 27.641 211.464 ;
     RECT  27.388 280.992 27.641 281.16 ;
     RECT  26.953 27.936 27.644 27.96 ;
     RECT  26.915 101.376 27.644 103.656 ;
     RECT  26.284 37.056 27.673 37.224 ;
     RECT  27.637 38.4 27.673 41.064 ;
     RECT  27.637 44.112 27.673 44.472 ;
     RECT  27.421 80.832 27.673 80.856 ;
     RECT  27.637 176.16 27.673 176.952 ;
     RECT  27.253 91.68 27.677 97.992 ;
     RECT  27.533 131.568 27.677 131.976 ;
     RECT  27.425 183.6 27.677 185.832 ;
     RECT  27.539 290.112 27.677 291.96 ;
     RECT  27.641 196.704 27.683 196.728 ;
     RECT  27.052 250.752 27.683 251.352 ;
     RECT  27.644 27.936 27.685 28.68 ;
     RECT  27.601 122.544 27.685 125.16 ;
     RECT  27.565 219.6 27.685 221.736 ;
     RECT  26.921 133.68 27.709 135.336 ;
     RECT  27.313 136.416 27.709 139.176 ;
     RECT  26.989 55.488 27.713 55.512 ;
     RECT  27.539 169.872 27.713 169.896 ;
     RECT  27.641 208.752 27.713 210.984 ;
     RECT  27.497 256.704 27.713 256.728 ;
     RECT  27.677 291.36 27.713 291.96 ;
     RECT  27.713 208.752 27.721 209.928 ;
     RECT  27.721 208.752 27.724 209.832 ;
     RECT  27.421 24.528 27.731 26.28 ;
     RECT  27.685 27.6 27.731 28.68 ;
     RECT  27.635 29.808 27.731 33.768 ;
     RECT  27.644 101.376 27.731 103.896 ;
     RECT  26.993 150.48 27.731 151.224 ;
     RECT  27.388 117.408 27.733 117.432 ;
     RECT  27.539 118.56 27.733 120.6 ;
     RECT  27.241 155.856 27.733 156.168 ;
     RECT  26.849 157.296 27.733 157.32 ;
     RECT  27.301 217.44 27.733 218.136 ;
     RECT  26.777 142.464 27.74 142.728 ;
     RECT  27.421 266.88 27.74 268.728 ;
     RECT  26.849 271.296 27.74 271.368 ;
     RECT  27.461 223.968 27.745 224.568 ;
     RECT  27.395 0.288 27.749 0.312 ;
     RECT  27.533 46.176 27.749 46.824 ;
     RECT  27.641 56.784 27.749 56.808 ;
     RECT  27.709 133.68 27.749 139.176 ;
     RECT  27.724 208.752 27.749 209.784 ;
     RECT  27.155 299.28 27.749 299.304 ;
     RECT  27.673 44.016 27.757 44.472 ;
     RECT  27.601 207.216 27.781 207.624 ;
     RECT  26.989 264.48 27.781 264.936 ;
     RECT  27.74 266.88 27.781 269.4 ;
     RECT  27.731 101.376 27.785 103.608 ;
     RECT  27.461 187.488 27.785 190.68 ;
     RECT  27.497 257.952 27.785 258.36 ;
     RECT  27.253 213.696 27.82 216.168 ;
     RECT  27.749 46.176 27.821 46.776 ;
     RECT  27.677 183.696 27.821 185.832 ;
     RECT  27.497 203.856 27.821 204.648 ;
     RECT  27.82 213.696 27.821 214.536 ;
     RECT  27.628 243.984 27.821 244.824 ;
     RECT  27.497 74.928 27.827 79.176 ;
     RECT  27.673 80.736 27.827 80.856 ;
     RECT  27.491 98.976 27.827 99.192 ;
     RECT  27.74 142.464 27.827 143.592 ;
     RECT  27.74 270.48 27.827 271.368 ;
     RECT  27.827 74.928 27.849 78.648 ;
     RECT  27.497 105.168 27.853 107.64 ;
     RECT  27.493 108.672 27.853 111.144 ;
     RECT  27.605 235.536 27.853 235.944 ;
     RECT  27.605 42.288 27.857 42.744 ;
     RECT  27.533 47.952 27.857 48.696 ;
     RECT  27.565 83.76 27.857 86.76 ;
     RECT  27.493 112.464 27.865 112.872 ;
     RECT  27.605 81.84 27.868 81.864 ;
     RECT  27.389 113.952 27.875 114.6 ;
     RECT  27.313 296.88 27.875 298.152 ;
     RECT  27.785 101.376 27.893 103.224 ;
     RECT  27.853 105.168 27.893 111.144 ;
     RECT  27.875 296.88 27.893 297.624 ;
     RECT  27.457 4.656 27.916 9.096 ;
     RECT  27.821 213.744 27.916 214.536 ;
     RECT  27.731 27.6 27.923 28.44 ;
     RECT  27.733 117.408 27.923 120.6 ;
     RECT  27.733 155.856 27.923 157.32 ;
     RECT  27.425 181.92 27.923 182.424 ;
     RECT  27.749 209.232 27.923 209.784 ;
     RECT  27.916 213.744 27.923 214.44 ;
     RECT  27.673 37.056 27.925 41.064 ;
     RECT  27.685 122.544 27.925 125.208 ;
     RECT  27.827 142.464 27.925 142.824 ;
     RECT  27.281 144.72 27.925 147.048 ;
     RECT  27.877 227.136 27.925 227.16 ;
     RECT  27.493 279.312 27.925 279.576 ;
     RECT  27.745 280.752 27.925 280.776 ;
     RECT  27.491 100.272 27.929 100.296 ;
     RECT  27.923 157.296 27.929 157.32 ;
     RECT  27.923 182.016 27.929 182.424 ;
     RECT  27.785 187.536 27.929 189.432 ;
     RECT  27.827 270.864 27.929 271.368 ;
     RECT  27.677 290.112 27.929 290.328 ;
     RECT  27.677 96.72 27.961 97.992 ;
     RECT  27.827 98.976 27.961 99 ;
     RECT  27.785 258 27.961 258.36 ;
     RECT  26.669 259.536 27.961 259.8 ;
     RECT  27.389 197.76 27.964 199.128 ;
     RECT  27.893 105.888 27.965 111.144 ;
     RECT  27.749 133.824 27.965 139.176 ;
     RECT  27.923 213.744 27.965 214.152 ;
     RECT  27.533 232.512 27.965 232.536 ;
     RECT  27.965 137.952 27.971 139.176 ;
     RECT  27.281 148.176 27.971 149.496 ;
     RECT  27.925 279.312 27.971 280.776 ;
     RECT  27.923 27.6 27.997 27.912 ;
     RECT  27.925 36.864 27.997 41.064 ;
     RECT  27.964 197.76 27.997 198.408 ;
     RECT  27.388 282.144 27.997 286.632 ;
     RECT  27.539 287.856 27.997 289.08 ;
     RECT  27.757 44.112 28.001 44.472 ;
     RECT  27.857 83.76 28.001 85.176 ;
     RECT  27.965 106.128 28.001 111.144 ;
     RECT  27.605 88.752 28.028 88.968 ;
     RECT  27.529 159.888 28.028 162.024 ;
     RECT  27.388 163.008 28.028 164.856 ;
     RECT  27.827 80.832 28.037 80.856 ;
     RECT  27.893 101.376 28.037 103.08 ;
     RECT  28.028 159.888 28.037 164.856 ;
     RECT  27.971 279.312 28.037 279.816 ;
     RECT  27.731 29.808 28.067 30.888 ;
     RECT  28.037 159.888 28.067 163.56 ;
     RECT  27.425 127.536 28.069 128.856 ;
     RECT  27.533 129.936 28.069 130.584 ;
     RECT  27.683 250.752 28.069 251.016 ;
     RECT  27.857 42.288 28.073 42.648 ;
     RECT  27.925 122.544 28.073 125.928 ;
     RECT  27.971 137.952 28.073 138.552 ;
     RECT  27.925 141.888 28.073 142.824 ;
     RECT  27.923 155.856 28.073 156.12 ;
     RECT  27.317 238.272 28.073 238.296 ;
     RECT  27.301 246.24 28.073 249.048 ;
     RECT  27.101 273.888 28.073 275.304 ;
     RECT  27.997 36.768 28.105 41.064 ;
     RECT  27.539 172.128 28.105 172.152 ;
     RECT  27.587 173.184 28.105 174.024 ;
     RECT  27.461 292.992 28.108 294.696 ;
     RECT  27.997 282.144 28.109 289.08 ;
     RECT  28.028 88.32 28.115 88.968 ;
     RECT  27.997 90.192 28.115 90.216 ;
     RECT  27.677 91.68 28.115 95.64 ;
     RECT  28.001 106.128 28.115 107.16 ;
     RECT  28.073 246.24 28.115 247.368 ;
     RECT  28.028 255.12 28.115 255.144 ;
     RECT  27.857 48.336 28.117 48.696 ;
     RECT  27.641 49.728 28.117 53.016 ;
     RECT  26.957 68.112 28.117 68.136 ;
     RECT  28.069 295.824 28.117 295.848 ;
     RECT  27.893 296.88 28.117 297.576 ;
     RECT  26.813 263.28 28.124 263.448 ;
     RECT  27.781 264.48 28.124 265.224 ;
     RECT  27.733 217.44 28.127 218.328 ;
     RECT  27.685 219.312 28.127 221.736 ;
     RECT  28.073 142.608 28.137 142.824 ;
     RECT  28.115 92.688 28.145 95.64 ;
     RECT  27.677 131.568 28.145 131.592 ;
     RECT  27.971 148.896 28.145 149.496 ;
     RECT  27.209 200.832 28.145 201.24 ;
     RECT  27.997 26.784 28.163 27.912 ;
     RECT  28.073 138.48 28.163 138.552 ;
     RECT  27.731 24.528 28.181 25.224 ;
     RECT  27.425 230.064 28.181 230.376 ;
     RECT  28.069 250.224 28.181 251.016 ;
     RECT  28.108 294.048 28.181 294.696 ;
     RECT  28.127 217.44 28.211 221.736 ;
     RECT  28.124 263.28 28.211 265.224 ;
     RECT  28.181 294.144 28.211 294.696 ;
     RECT  28.117 68.112 28.213 68.904 ;
     RECT  27.781 228.384 28.213 228.408 ;
     RECT  27.589 22.992 28.217 23.016 ;
     RECT  28.067 159.888 28.217 162.504 ;
     RECT  27.713 210.96 28.217 210.984 ;
     RECT  27.961 258 28.22 259.8 ;
     RECT  27.539 260.88 28.22 261.672 ;
     RECT  27.925 140.736 28.249 140.76 ;
     RECT  28.145 201.12 28.249 201.24 ;
     RECT  27.436 202.272 28.249 202.728 ;
     RECT  27.731 31.872 28.253 33.768 ;
     RECT  27.961 96.72 28.253 99 ;
     RECT  27.923 117.408 28.253 117.432 ;
     RECT  27.821 203.856 28.253 203.88 ;
     RECT  27.82 215.808 28.253 216.168 ;
     RECT  28.109 282.144 28.253 288.84 ;
     RECT  28.217 162 28.259 162.504 ;
     RECT  27.539 252.912 28.261 252.936 ;
     RECT  27.164 254.112 28.261 254.136 ;
     RECT  28.213 68.112 28.285 69 ;
     RECT  27.389 70.032 28.285 70.152 ;
     RECT  28.181 24.672 28.289 25.224 ;
     RECT  28.067 29.808 28.289 30.6 ;
     RECT  27.785 190.464 28.289 190.68 ;
     RECT  27.781 266.736 28.309 269.4 ;
     RECT  26.993 152.352 28.316 152.376 ;
     RECT  27.137 153.408 28.316 153.432 ;
     RECT  27.541 73.488 28.321 73.512 ;
     RECT  27.849 74.928 28.321 78.072 ;
     RECT  28.001 83.76 28.325 84.888 ;
     RECT  27.875 113.952 28.325 113.976 ;
     RECT  27.925 144.288 28.325 147.048 ;
     RECT  28.289 190.656 28.325 190.68 ;
     RECT  28.289 29.808 28.355 30.504 ;
     RECT  28.105 36.24 28.355 41.064 ;
     RECT  28.213 71.184 28.355 71.304 ;
     RECT  28.249 140.688 28.355 140.76 ;
     RECT  28.355 71.28 28.357 71.304 ;
     RECT  27.731 150.864 28.357 151.224 ;
     RECT  28.316 152.352 28.357 153.432 ;
     RECT  27.596 165.888 28.357 166.728 ;
     RECT  28.069 278.112 28.357 278.136 ;
     RECT  27.916 5.808 28.361 9.096 ;
     RECT  28.137 142.8 28.361 142.824 ;
     RECT  28.325 144.672 28.361 147.048 ;
     RECT  28.259 162.48 28.361 162.504 ;
     RECT  27.929 188.16 28.361 189.432 ;
     RECT  28.285 66.72 28.369 66.744 ;
     RECT  28.115 91.68 28.393 91.704 ;
     RECT  28.355 30.144 28.397 30.504 ;
     RECT  28.361 144.672 28.397 145.32 ;
     RECT  28.067 163.536 28.397 163.56 ;
     RECT  28.261 252.912 28.397 254.136 ;
     RECT  28.309 266.208 28.397 269.4 ;
     RECT  28.117 295.824 28.397 297.576 ;
     RECT  28.073 122.544 28.403 123.672 ;
     RECT  28.069 127.536 28.403 130.584 ;
     RECT  28.357 150.864 28.403 153.432 ;
     RECT  28.22 258 28.405 261.672 ;
     RECT  28.285 68.112 28.429 70.152 ;
     RECT  28.289 24.72 28.433 25.224 ;
     RECT  27.137 154.464 28.433 154.488 ;
     RECT  28.249 191.664 28.433 191.688 ;
     RECT  28.357 277.584 28.433 278.136 ;
     RECT  28.357 71.28 28.453 71.448 ;
     RECT  28.397 266.88 28.465 269.4 ;
     RECT  27.497 206.016 28.501 206.232 ;
     RECT  27.745 223.584 28.501 224.568 ;
     RECT  27.925 225.744 28.501 227.16 ;
     RECT  28.073 248.352 28.501 249.048 ;
     RECT  28.181 250.224 28.501 250.488 ;
     RECT  28.309 275.904 28.501 275.928 ;
     RECT  28.211 218.784 28.537 221.736 ;
     RECT  27.587 240.72 28.537 242.424 ;
     RECT  27.781 272.688 28.537 272.712 ;
     RECT  28.073 273.888 28.537 274.68 ;
     RECT  28.403 153.408 28.549 153.432 ;
     RECT  27.821 244.464 28.549 244.824 ;
     RECT  28.001 108.192 28.565 111.144 ;
     RECT  28.565 108.192 28.597 111.192 ;
     RECT  27.443 192.816 28.604 193.128 ;
     RECT  26.867 1.728 28.609 3.624 ;
     RECT  27.916 4.656 28.609 4.68 ;
     RECT  28.001 44.208 28.645 44.472 ;
     RECT  27.923 119.712 28.645 120.6 ;
     RECT  28.501 223.584 28.645 227.16 ;
     RECT  28.537 240 28.645 242.424 ;
     RECT  28.117 48.336 28.681 53.016 ;
     RECT  28.357 54.672 28.681 54.696 ;
     RECT  28.073 125.904 28.681 125.928 ;
     RECT  28.105 172.128 28.681 174.024 ;
     RECT  27.929 182.112 28.681 182.424 ;
     RECT  27.605 194.352 28.681 195.288 ;
     RECT  27.997 197.184 28.681 198.408 ;
     RECT  28.355 39.312 28.7 41.064 ;
     RECT  28.253 96.72 28.7 98.76 ;
     RECT  27.865 112.464 28.709 112.488 ;
     RECT  27.637 58.56 28.741 65.016 ;
     RECT  28.403 130.32 28.741 130.584 ;
     RECT  27.853 170.496 28.741 170.52 ;
     RECT  28.693 57.12 28.748 57.144 ;
     RECT  28.211 217.44 28.748 217.752 ;
     RECT  28.645 223.344 28.748 227.16 ;
     RECT  28.213 228.384 28.748 228.744 ;
     RECT  27.965 133.824 28.789 136.44 ;
     RECT  28.361 146.736 28.789 147.048 ;
     RECT  28.145 148.944 28.789 149.496 ;
     RECT  28.073 42.624 28.825 42.648 ;
     RECT  28.741 169.776 28.825 170.52 ;
     RECT  28.681 171.552 28.825 174.024 ;
     RECT  27.673 175.824 28.825 176.952 ;
     RECT  27.533 178.416 28.825 179.496 ;
     RECT  28.609 1.728 28.837 4.68 ;
     RECT  28.645 44.208 28.837 44.712 ;
     RECT  28.403 122.544 28.837 123.336 ;
     RECT  28.549 244.464 28.837 245.112 ;
     RECT  28.405 258 28.837 258.168 ;
     RECT  28.357 165.888 28.844 166.776 ;
     RECT  27.635 168.048 28.844 168.072 ;
     RECT  27.821 46.176 28.885 46.728 ;
     RECT  28.037 164.688 28.885 164.856 ;
     RECT  28.844 165.888 28.885 168.072 ;
     RECT  28.825 169.776 28.885 174.024 ;
     RECT  27.857 86.208 28.892 86.76 ;
     RECT  28.825 175.824 28.892 179.496 ;
     RECT  28.604 192.336 28.897 193.128 ;
     RECT  28.681 194.352 28.897 198.408 ;
     RECT  28.405 259.2 28.933 261.672 ;
     RECT  28.465 266.88 28.94 269.688 ;
     RECT  28.837 2.148 28.969 4.68 ;
     RECT  28.361 5.808 28.969 7.992 ;
     RECT  28.681 48.336 28.969 54.696 ;
     RECT  28.892 86.208 28.969 87.192 ;
     RECT  28.355 36.24 28.981 37.704 ;
     RECT  28.537 272.496 28.981 274.68 ;
     RECT  28.325 83.76 28.988 84.12 ;
     RECT  28.645 240 28.997 242.664 ;
     RECT  28.837 244.272 28.997 245.112 ;
     RECT  28.748 233.088 29.005 233.112 ;
     RECT  28.885 169.776 29.029 174.408 ;
     RECT  28.969 48.336 29.077 54.888 ;
     RECT  28.361 188.16 29.077 188.904 ;
     RECT  28.837 44.208 29.084 45.144 ;
     RECT  28.885 46.176 29.084 46.776 ;
     RECT  28.393 91.008 29.084 91.704 ;
     RECT  28.145 92.688 29.084 95.16 ;
     RECT  29.077 187.2 29.113 188.904 ;
     RECT  28.211 294.624 29.125 294.696 ;
     RECT  28.397 295.824 29.125 295.992 ;
     RECT  28.789 133.44 29.132 136.44 ;
     RECT  28.501 205.248 29.149 206.232 ;
     RECT  27.781 207.216 29.149 208.056 ;
     RECT  28.501 238.992 29.173 239.016 ;
     RECT  28.115 246.24 29.173 246.264 ;
     RECT  28.741 58.56 29.18 65.976 ;
     RECT  28.969 2.148 29.408 7.992 ;
     RECT  28.361 9.072 29.408 9.096 ;
     RECT  26.741 10.224 29.408 10.248 ;
     RECT  28.433 25.2 29.408 25.224 ;
     RECT  28.163 26.928 29.408 27.912 ;
     RECT  28.397 30.144 29.408 30.168 ;
     RECT  28.253 32.496 29.408 33.768 ;
     RECT  28.981 35.424 29.408 37.704 ;
     RECT  28.7 39.312 29.408 41.16 ;
     RECT  28.825 42.624 29.408 42.744 ;
     RECT  29.084 44.208 29.408 46.776 ;
     RECT  29.077 48.336 29.408 55.752 ;
     RECT  28.748 57.024 29.408 57.144 ;
     RECT  29.18 58.128 29.408 65.976 ;
     RECT  28.429 67.248 29.408 70.152 ;
     RECT  28.453 71.28 29.408 72.216 ;
     RECT  28.321 73.488 29.408 78.072 ;
     RECT  28.969 79.248 29.408 79.272 ;
     RECT  28.969 80.304 29.408 80.328 ;
     RECT  28.988 83.184 29.408 84.12 ;
     RECT  28.969 86.016 29.408 87.192 ;
     RECT  28.115 88.896 29.408 88.92 ;
     RECT  29.084 91.008 29.408 95.16 ;
     RECT  28.7 96.672 29.408 98.76 ;
     RECT  28.037 101.376 29.408 102.648 ;
     RECT  28.115 106.464 29.408 107.16 ;
     RECT  28.597 108.192 29.408 111.288 ;
     RECT  28.709 112.32 29.408 112.488 ;
     RECT  27.853 115.68 29.408 115.704 ;
     RECT  28.645 119.712 29.408 120.888 ;
     RECT  28.837 122.496 29.408 123.336 ;
     RECT  28.681 125.904 29.408 126.264 ;
     RECT  28.403 127.536 29.408 128.904 ;
     RECT  28.741 130.32 29.408 131.496 ;
     RECT  29.132 133.104 29.408 136.44 ;
     RECT  28.163 138.528 29.408 138.552 ;
     RECT  28.355 140.736 29.408 140.76 ;
     RECT  28.397 144.72 29.408 145.32 ;
     RECT  28.789 146.736 29.408 147.48 ;
     RECT  28.789 148.944 29.408 149.88 ;
     RECT  28.403 151.536 29.408 152.376 ;
     RECT  28.549 153.408 29.408 153.624 ;
     RECT  28.073 155.856 29.408 155.88 ;
     RECT  28.573 157.92 29.408 157.944 ;
     RECT  28.217 159.888 29.408 161.016 ;
     RECT  28.885 164.688 29.408 168.504 ;
     RECT  29.029 169.776 29.408 174.744 ;
     RECT  28.892 175.824 29.408 179.592 ;
     RECT  27.299 180.672 29.408 180.84 ;
     RECT  28.681 182.112 29.408 182.472 ;
     RECT  27.821 183.696 29.408 184.92 ;
     RECT  29.113 186.384 29.408 188.904 ;
     RECT  28.637 190.896 29.408 190.92 ;
     RECT  28.897 192.336 29.408 198.408 ;
     RECT  28.825 199.488 29.408 199.512 ;
     RECT  28.249 201.12 29.408 202.728 ;
     RECT  29.149 205.248 29.408 208.056 ;
     RECT  27.923 209.76 29.408 209.784 ;
     RECT  28.825 211.344 29.408 211.368 ;
     RECT  26.993 212.544 29.408 212.568 ;
     RECT  27.965 213.744 29.408 213.768 ;
     RECT  28.253 215.952 29.408 216.168 ;
     RECT  28.748 217.152 29.408 217.752 ;
     RECT  28.537 218.784 29.408 222.312 ;
     RECT  28.748 223.344 29.408 228.744 ;
     RECT  28.681 229.776 29.408 229.848 ;
     RECT  28.429 231.312 29.408 231.336 ;
     RECT  29.005 232.512 29.408 233.112 ;
     RECT  27.853 235.392 29.408 235.944 ;
     RECT  27.605 236.976 29.408 237 ;
     RECT  29.173 238.272 29.408 239.016 ;
     RECT  28.997 240 29.408 245.112 ;
     RECT  29.173 246.192 29.408 246.264 ;
     RECT  28.115 247.344 29.408 247.368 ;
     RECT  28.501 248.352 29.408 250.488 ;
     RECT  28.397 252.912 29.408 253.176 ;
     RECT  28.796 254.352 29.408 254.376 ;
     RECT  28.837 257.088 29.408 258.168 ;
     RECT  28.933 259.2 29.408 261.864 ;
     RECT  28.211 263.28 29.408 264.936 ;
     RECT  28.94 266.88 29.408 269.784 ;
     RECT  27.929 270.864 29.408 270.888 ;
     RECT  28.981 271.92 29.408 274.68 ;
     RECT  28.501 275.904 29.408 276.552 ;
     RECT  28.433 277.584 29.408 277.704 ;
     RECT  28.037 279.312 29.408 279.576 ;
     RECT  28.253 282.192 29.408 286.104 ;
     RECT  28.253 287.472 29.408 288.84 ;
     RECT  27.929 290.304 29.408 290.328 ;
     RECT  27.713 291.36 29.408 291.384 ;
     RECT  28.108 292.992 29.408 293.016 ;
     RECT  29.125 294.624 29.408 295.992 ;
     RECT  28.397 296.976 29.408 297.576 ;
     RECT  29.408 2.148 29.512 298.092 ;
     RECT  29.512 2.418 29.704 297.822 ;
     RECT  29.704 136.224 29.765 136.248 ;
     RECT  29.704 266.928 29.765 266.952 ;
     RECT  29.704 267.936 29.837 267.96 ;
     RECT  29.704 5.808 29.843 7.224 ;
     RECT  29.704 160.992 29.843 161.016 ;
     RECT  29.704 3.024 29.873 3.624 ;
     RECT  29.704 52.992 29.881 53.928 ;
     RECT  29.704 4.656 29.891 4.68 ;
     RECT  29.704 93.792 29.891 93.816 ;
     RECT  29.704 50.736 29.939 50.76 ;
     RECT  29.881 53.904 29.939 53.928 ;
     RECT  29.704 166.464 29.945 166.488 ;
     RECT  29.873 3.072 29.981 3.624 ;
     RECT  29.704 206.112 30.017 206.136 ;
     RECT  29.843 6.672 30.161 7.224 ;
     RECT  30.161 6.672 30.305 6.696 ;
     RECT  29.981 3.6 30.341 3.624 ;
     RECT  29.704 216.144 30.917 216.168 ;
    LAYER M5 ;
     RECT  26.64 0.037 26.664 0.085 ;
     RECT  14.976 0.037 15 0.144 ;
     RECT  16.56 0.037 16.584 0.144 ;
     RECT  17.808 0.037 17.832 0.144 ;
     RECT  19.584 0.037 20.424 0.144 ;
     RECT  26.256 0.085 27.384 0.144 ;
     RECT  2.208 0.144 29.016 1.763 ;
     RECT  2.4 1.763 29.016 2.137 ;
     RECT  2.4 2.137 29.52 2.151 ;
     RECT  2.4 2.151 29.712 3.443 ;
     RECT  3.888 3.443 29.712 4.645 ;
     RECT  2.4 3.443 2.904 4.691 ;
     RECT  2.4 4.691 2.856 5.653 ;
     RECT  3.888 4.645 29.88 5.653 ;
     RECT  2.4 5.653 29.88 11.509 ;
     RECT  2.304 11.509 29.88 16.595 ;
     RECT  2.4 16.595 29.88 50.725 ;
     RECT  2.4 50.725 29.928 53.939 ;
     RECT  2.4 53.939 29.88 93.827 ;
     RECT  2.4 93.827 29.832 152.725 ;
     RECT  2.304 152.725 29.832 161.027 ;
     RECT  2.304 161.027 29.712 161.123 ;
     RECT  2.4 161.123 29.712 224.437 ;
     RECT  2.304 224.437 29.712 226.643 ;
     RECT  2.4 226.643 29.712 241.621 ;
     RECT  2.304 241.621 29.712 262.259 ;
     RECT  2.4 262.259 29.712 266.725 ;
     RECT  2.304 266.725 29.712 270.899 ;
     RECT  2.4 270.899 29.712 293.603 ;
     RECT  2.4 293.603 26.904 293.941 ;
     RECT  28.032 293.603 29.712 294.131 ;
     RECT  2.304 293.941 26.904 295.331 ;
     RECT  2.304 295.331 25.176 295.379 ;
     RECT  2.304 295.379 9.96 295.477 ;
     RECT  2.208 295.477 9.96 295.715 ;
     RECT  11.472 295.379 25.176 295.859 ;
     RECT  26.64 295.331 26.904 295.859 ;
     RECT  28.08 294.131 29.712 295.859 ;
     RECT  26.64 295.859 26.664 295.907 ;
     RECT  11.472 295.859 24.312 296.051 ;
     RECT  9.888 295.715 9.96 296.389 ;
     RECT  2.208 295.715 8.76 296.435 ;
     RECT  11.472 296.051 11.88 296.435 ;
     RECT  28.128 295.859 29.712 296.435 ;
     RECT  7.488 296.435 8.76 296.965 ;
     RECT  9.888 296.389 10.248 296.965 ;
     RECT  2.208 296.435 6.12 297.541 ;
     RECT  7.488 296.965 10.248 297.541 ;
     RECT  11.568 296.435 11.88 297.541 ;
     RECT  12.864 296.051 24.312 297.541 ;
     RECT  28.704 296.435 29.712 297.587 ;
     RECT  2.208 297.541 24.744 297.589 ;
     RECT  2.208 297.589 24.936 297.635 ;
     RECT  26.112 297.541 26.568 297.637 ;
     RECT  15.072 297.635 24.936 297.733 ;
     RECT  25.92 297.637 26.76 297.733 ;
     RECT  27.792 297.589 27.864 297.733 ;
     RECT  29.4 297.587 29.712 298.089 ;
     RECT  29.4 298.089 29.52 298.103 ;
     RECT  15.072 297.733 27.864 298.163 ;
     RECT  2.208 297.635 13.896 298.693 ;
     RECT  15.072 298.163 27.816 298.693 ;
     RECT  2.208 298.693 27.816 300.112 ;
     RECT  3.072 300.112 3.096 300.131 ;
     RECT  4.464 300.112 4.488 300.131 ;
     RECT  6.768 300.112 6.792 300.131 ;
     RECT  19.44 300.112 19.464 300.131 ;
     RECT  22.752 300.112 22.776 300.131 ;
     RECT  24.384 300.112 24.408 300.131 ;
     RECT  25.68 300.112 26.424 300.131 ;
     RECT  21.6 300.112 21.624 300.179 ;
     RECT  16.584 0.037 16.896 0.144 ;
     RECT  17.16 0.037 17.232 0.144 ;
     RECT  17.352 0.037 17.424 0.144 ;
     RECT  17.544 0.037 17.616 0.144 ;
     RECT  17.736 0.037 17.808 0.144 ;
     RECT  2.904 3.443 3.888 4.691 ;
     RECT  2.856 4.691 3.888 5.653 ;
     RECT  26.904 293.603 28.032 294.131 ;
     RECT  26.904 294.131 28.08 295.859 ;
     RECT  25.176 295.331 26.64 295.859 ;
     RECT  9.96 295.379 11.472 296.389 ;
     RECT  8.76 295.715 9.888 296.965 ;
     RECT  26.664 295.859 28.128 295.907 ;
     RECT  11.88 296.051 12.864 297.541 ;
     RECT  10.248 296.389 11.472 296.435 ;
     RECT  6.12 296.435 7.488 297.541 ;
     RECT  10.248 296.435 11.568 297.541 ;
     RECT  24.744 297.541 26.112 297.589 ;
     RECT  24.936 297.589 26.112 297.637 ;
     RECT  26.568 297.589 27.792 297.637 ;
     RECT  13.896 297.635 15.072 298.693 ;
     RECT  24.936 297.637 25.92 297.733 ;
     RECT  26.76 297.637 27.792 297.733 ;
     RECT  3.096 300.112 3.168 300.131 ;
     RECT  3.288 300.112 3.36 300.131 ;
     RECT  3.48 300.112 3.552 300.131 ;
     RECT  3.672 300.112 3.744 300.131 ;
     RECT  3.864 300.112 3.984 300.131 ;
     RECT  4.104 300.112 4.176 300.131 ;
     RECT  4.296 300.112 4.368 300.131 ;
     RECT  21.624 300.112 21.648 300.131 ;
     RECT  21.816 300.112 22.32 300.131 ;
     RECT  22.584 300.112 22.656 300.131 ;
     RECT  24.408 300.112 24.48 300.131 ;
     RECT  24.6 300.112 24.672 300.131 ;
     RECT  24.792 300.112 24.864 300.131 ;
     RECT  24.984 300.112 25.056 300.131 ;
     RECT  25.176 300.112 25.296 300.131 ;
     RECT  25.416 300.112 25.488 300.131 ;
     RECT  25.608 300.112 25.68 300.131 ;
  END
END ot_s81_hc_cryys
END LIBRARY
